VERSION 5.7 ;
BUSBITCHARS "[]" ;
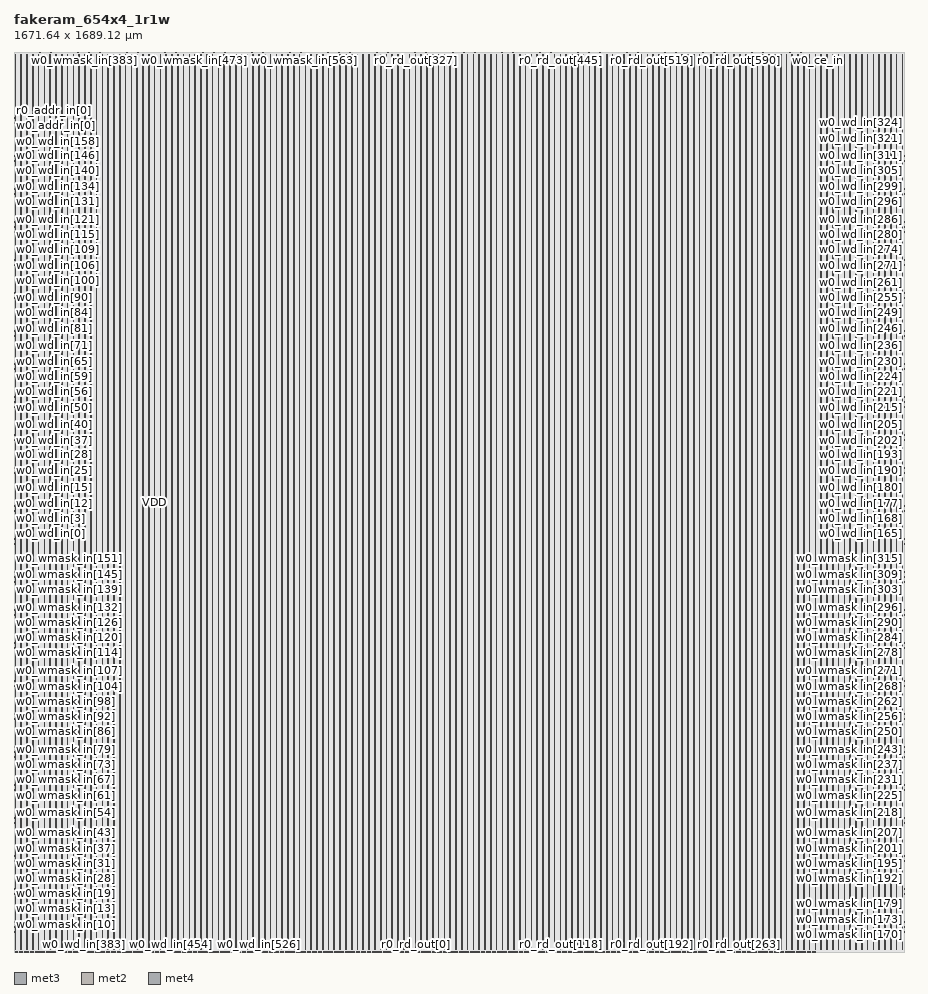
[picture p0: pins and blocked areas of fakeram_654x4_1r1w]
MACRO fakeram_654x4_1r1w
  FOREIGN fakeram_654x4_1r1w 0 0 ;
  SYMMETRY X Y R90 ;
  SIZE 1671.640 BY 1689.120 ;
  CLASS BLOCK ;
  PIN w0_wmask_in[0]
    DIRECTION INPUT ;
    USE SIGNAL ;
    SHAPE ABUTMENT ;
    PORT
      LAYER met3 ;
      RECT 0.000 3.930 0.900 4.230 ;
    END
  END w0_wmask_in[0]
  PIN w0_wmask_in[1]
    DIRECTION INPUT ;
    USE SIGNAL ;
    SHAPE ABUTMENT ;
    PORT
      LAYER met3 ;
      RECT 0.000 8.690 0.900 8.990 ;
    END
  END w0_wmask_in[1]
  PIN w0_wmask_in[2]
    DIRECTION INPUT ;
    USE SIGNAL ;
    SHAPE ABUTMENT ;
    PORT
      LAYER met3 ;
      RECT 0.000 13.450 0.900 13.750 ;
    END
  END w0_wmask_in[2]
  PIN w0_wmask_in[3]
    DIRECTION INPUT ;
    USE SIGNAL ;
    SHAPE ABUTMENT ;
    PORT
      LAYER met3 ;
      RECT 0.000 18.210 0.900 18.510 ;
    END
  END w0_wmask_in[3]
  PIN w0_wmask_in[4]
    DIRECTION INPUT ;
    USE SIGNAL ;
    SHAPE ABUTMENT ;
    PORT
      LAYER met3 ;
      RECT 0.000 22.970 0.900 23.270 ;
    END
  END w0_wmask_in[4]
  PIN w0_wmask_in[5]
    DIRECTION INPUT ;
    USE SIGNAL ;
    SHAPE ABUTMENT ;
    PORT
      LAYER met3 ;
      RECT 0.000 27.730 0.900 28.030 ;
    END
  END w0_wmask_in[5]
  PIN w0_wmask_in[6]
    DIRECTION INPUT ;
    USE SIGNAL ;
    SHAPE ABUTMENT ;
    PORT
      LAYER met3 ;
      RECT 0.000 32.490 0.900 32.790 ;
    END
  END w0_wmask_in[6]
  PIN w0_wmask_in[7]
    DIRECTION INPUT ;
    USE SIGNAL ;
    SHAPE ABUTMENT ;
    PORT
      LAYER met3 ;
      RECT 0.000 37.250 0.900 37.550 ;
    END
  END w0_wmask_in[7]
  PIN w0_wmask_in[8]
    DIRECTION INPUT ;
    USE SIGNAL ;
    SHAPE ABUTMENT ;
    PORT
      LAYER met3 ;
      RECT 0.000 42.010 0.900 42.310 ;
    END
  END w0_wmask_in[8]
  PIN w0_wmask_in[9]
    DIRECTION INPUT ;
    USE SIGNAL ;
    SHAPE ABUTMENT ;
    PORT
      LAYER met3 ;
      RECT 0.000 46.770 0.900 47.070 ;
    END
  END w0_wmask_in[9]
  PIN w0_wmask_in[10]
    DIRECTION INPUT ;
    USE SIGNAL ;
    SHAPE ABUTMENT ;
    PORT
      LAYER met3 ;
      RECT 0.000 51.530 0.900 51.830 ;
    END
  END w0_wmask_in[10]
  PIN w0_wmask_in[11]
    DIRECTION INPUT ;
    USE SIGNAL ;
    SHAPE ABUTMENT ;
    PORT
      LAYER met3 ;
      RECT 0.000 56.290 0.900 56.590 ;
    END
  END w0_wmask_in[11]
  PIN w0_wmask_in[12]
    DIRECTION INPUT ;
    USE SIGNAL ;
    SHAPE ABUTMENT ;
    PORT
      LAYER met3 ;
      RECT 0.000 61.050 0.900 61.350 ;
    END
  END w0_wmask_in[12]
  PIN w0_wmask_in[13]
    DIRECTION INPUT ;
    USE SIGNAL ;
    SHAPE ABUTMENT ;
    PORT
      LAYER met3 ;
      RECT 0.000 65.810 0.900 66.110 ;
    END
  END w0_wmask_in[13]
  PIN w0_wmask_in[14]
    DIRECTION INPUT ;
    USE SIGNAL ;
    SHAPE ABUTMENT ;
    PORT
      LAYER met3 ;
      RECT 0.000 70.570 0.900 70.870 ;
    END
  END w0_wmask_in[14]
  PIN w0_wmask_in[15]
    DIRECTION INPUT ;
    USE SIGNAL ;
    SHAPE ABUTMENT ;
    PORT
      LAYER met3 ;
      RECT 0.000 75.330 0.900 75.630 ;
    END
  END w0_wmask_in[15]
  PIN w0_wmask_in[16]
    DIRECTION INPUT ;
    USE SIGNAL ;
    SHAPE ABUTMENT ;
    PORT
      LAYER met3 ;
      RECT 0.000 80.090 0.900 80.390 ;
    END
  END w0_wmask_in[16]
  PIN w0_wmask_in[17]
    DIRECTION INPUT ;
    USE SIGNAL ;
    SHAPE ABUTMENT ;
    PORT
      LAYER met3 ;
      RECT 0.000 84.850 0.900 85.150 ;
    END
  END w0_wmask_in[17]
  PIN w0_wmask_in[18]
    DIRECTION INPUT ;
    USE SIGNAL ;
    SHAPE ABUTMENT ;
    PORT
      LAYER met3 ;
      RECT 0.000 89.610 0.900 89.910 ;
    END
  END w0_wmask_in[18]
  PIN w0_wmask_in[19]
    DIRECTION INPUT ;
    USE SIGNAL ;
    SHAPE ABUTMENT ;
    PORT
      LAYER met3 ;
      RECT 0.000 94.370 0.900 94.670 ;
    END
  END w0_wmask_in[19]
  PIN w0_wmask_in[20]
    DIRECTION INPUT ;
    USE SIGNAL ;
    SHAPE ABUTMENT ;
    PORT
      LAYER met3 ;
      RECT 0.000 99.130 0.900 99.430 ;
    END
  END w0_wmask_in[20]
  PIN w0_wmask_in[21]
    DIRECTION INPUT ;
    USE SIGNAL ;
    SHAPE ABUTMENT ;
    PORT
      LAYER met3 ;
      RECT 0.000 103.890 0.900 104.190 ;
    END
  END w0_wmask_in[21]
  PIN w0_wmask_in[22]
    DIRECTION INPUT ;
    USE SIGNAL ;
    SHAPE ABUTMENT ;
    PORT
      LAYER met3 ;
      RECT 0.000 108.650 0.900 108.950 ;
    END
  END w0_wmask_in[22]
  PIN w0_wmask_in[23]
    DIRECTION INPUT ;
    USE SIGNAL ;
    SHAPE ABUTMENT ;
    PORT
      LAYER met3 ;
      RECT 0.000 113.410 0.900 113.710 ;
    END
  END w0_wmask_in[23]
  PIN w0_wmask_in[24]
    DIRECTION INPUT ;
    USE SIGNAL ;
    SHAPE ABUTMENT ;
    PORT
      LAYER met3 ;
      RECT 0.000 118.170 0.900 118.470 ;
    END
  END w0_wmask_in[24]
  PIN w0_wmask_in[25]
    DIRECTION INPUT ;
    USE SIGNAL ;
    SHAPE ABUTMENT ;
    PORT
      LAYER met3 ;
      RECT 0.000 122.930 0.900 123.230 ;
    END
  END w0_wmask_in[25]
  PIN w0_wmask_in[26]
    DIRECTION INPUT ;
    USE SIGNAL ;
    SHAPE ABUTMENT ;
    PORT
      LAYER met3 ;
      RECT 0.000 127.690 0.900 127.990 ;
    END
  END w0_wmask_in[26]
  PIN w0_wmask_in[27]
    DIRECTION INPUT ;
    USE SIGNAL ;
    SHAPE ABUTMENT ;
    PORT
      LAYER met3 ;
      RECT 0.000 132.450 0.900 132.750 ;
    END
  END w0_wmask_in[27]
  PIN w0_wmask_in[28]
    DIRECTION INPUT ;
    USE SIGNAL ;
    SHAPE ABUTMENT ;
    PORT
      LAYER met3 ;
      RECT 0.000 137.210 0.900 137.510 ;
    END
  END w0_wmask_in[28]
  PIN w0_wmask_in[29]
    DIRECTION INPUT ;
    USE SIGNAL ;
    SHAPE ABUTMENT ;
    PORT
      LAYER met3 ;
      RECT 0.000 141.970 0.900 142.270 ;
    END
  END w0_wmask_in[29]
  PIN w0_wmask_in[30]
    DIRECTION INPUT ;
    USE SIGNAL ;
    SHAPE ABUTMENT ;
    PORT
      LAYER met3 ;
      RECT 0.000 146.730 0.900 147.030 ;
    END
  END w0_wmask_in[30]
  PIN w0_wmask_in[31]
    DIRECTION INPUT ;
    USE SIGNAL ;
    SHAPE ABUTMENT ;
    PORT
      LAYER met3 ;
      RECT 0.000 151.490 0.900 151.790 ;
    END
  END w0_wmask_in[31]
  PIN w0_wmask_in[32]
    DIRECTION INPUT ;
    USE SIGNAL ;
    SHAPE ABUTMENT ;
    PORT
      LAYER met3 ;
      RECT 0.000 156.250 0.900 156.550 ;
    END
  END w0_wmask_in[32]
  PIN w0_wmask_in[33]
    DIRECTION INPUT ;
    USE SIGNAL ;
    SHAPE ABUTMENT ;
    PORT
      LAYER met3 ;
      RECT 0.000 161.010 0.900 161.310 ;
    END
  END w0_wmask_in[33]
  PIN w0_wmask_in[34]
    DIRECTION INPUT ;
    USE SIGNAL ;
    SHAPE ABUTMENT ;
    PORT
      LAYER met3 ;
      RECT 0.000 165.770 0.900 166.070 ;
    END
  END w0_wmask_in[34]
  PIN w0_wmask_in[35]
    DIRECTION INPUT ;
    USE SIGNAL ;
    SHAPE ABUTMENT ;
    PORT
      LAYER met3 ;
      RECT 0.000 170.530 0.900 170.830 ;
    END
  END w0_wmask_in[35]
  PIN w0_wmask_in[36]
    DIRECTION INPUT ;
    USE SIGNAL ;
    SHAPE ABUTMENT ;
    PORT
      LAYER met3 ;
      RECT 0.000 175.290 0.900 175.590 ;
    END
  END w0_wmask_in[36]
  PIN w0_wmask_in[37]
    DIRECTION INPUT ;
    USE SIGNAL ;
    SHAPE ABUTMENT ;
    PORT
      LAYER met3 ;
      RECT 0.000 180.050 0.900 180.350 ;
    END
  END w0_wmask_in[37]
  PIN w0_wmask_in[38]
    DIRECTION INPUT ;
    USE SIGNAL ;
    SHAPE ABUTMENT ;
    PORT
      LAYER met3 ;
      RECT 0.000 184.810 0.900 185.110 ;
    END
  END w0_wmask_in[38]
  PIN w0_wmask_in[39]
    DIRECTION INPUT ;
    USE SIGNAL ;
    SHAPE ABUTMENT ;
    PORT
      LAYER met3 ;
      RECT 0.000 189.570 0.900 189.870 ;
    END
  END w0_wmask_in[39]
  PIN w0_wmask_in[40]
    DIRECTION INPUT ;
    USE SIGNAL ;
    SHAPE ABUTMENT ;
    PORT
      LAYER met3 ;
      RECT 0.000 194.330 0.900 194.630 ;
    END
  END w0_wmask_in[40]
  PIN w0_wmask_in[41]
    DIRECTION INPUT ;
    USE SIGNAL ;
    SHAPE ABUTMENT ;
    PORT
      LAYER met3 ;
      RECT 0.000 199.090 0.900 199.390 ;
    END
  END w0_wmask_in[41]
  PIN w0_wmask_in[42]
    DIRECTION INPUT ;
    USE SIGNAL ;
    SHAPE ABUTMENT ;
    PORT
      LAYER met3 ;
      RECT 0.000 203.850 0.900 204.150 ;
    END
  END w0_wmask_in[42]
  PIN w0_wmask_in[43]
    DIRECTION INPUT ;
    USE SIGNAL ;
    SHAPE ABUTMENT ;
    PORT
      LAYER met3 ;
      RECT 0.000 208.610 0.900 208.910 ;
    END
  END w0_wmask_in[43]
  PIN w0_wmask_in[44]
    DIRECTION INPUT ;
    USE SIGNAL ;
    SHAPE ABUTMENT ;
    PORT
      LAYER met3 ;
      RECT 0.000 213.370 0.900 213.670 ;
    END
  END w0_wmask_in[44]
  PIN w0_wmask_in[45]
    DIRECTION INPUT ;
    USE SIGNAL ;
    SHAPE ABUTMENT ;
    PORT
      LAYER met3 ;
      RECT 0.000 218.130 0.900 218.430 ;
    END
  END w0_wmask_in[45]
  PIN w0_wmask_in[46]
    DIRECTION INPUT ;
    USE SIGNAL ;
    SHAPE ABUTMENT ;
    PORT
      LAYER met3 ;
      RECT 0.000 222.890 0.900 223.190 ;
    END
  END w0_wmask_in[46]
  PIN w0_wmask_in[47]
    DIRECTION INPUT ;
    USE SIGNAL ;
    SHAPE ABUTMENT ;
    PORT
      LAYER met3 ;
      RECT 0.000 227.650 0.900 227.950 ;
    END
  END w0_wmask_in[47]
  PIN w0_wmask_in[48]
    DIRECTION INPUT ;
    USE SIGNAL ;
    SHAPE ABUTMENT ;
    PORT
      LAYER met3 ;
      RECT 0.000 232.410 0.900 232.710 ;
    END
  END w0_wmask_in[48]
  PIN w0_wmask_in[49]
    DIRECTION INPUT ;
    USE SIGNAL ;
    SHAPE ABUTMENT ;
    PORT
      LAYER met3 ;
      RECT 0.000 237.170 0.900 237.470 ;
    END
  END w0_wmask_in[49]
  PIN w0_wmask_in[50]
    DIRECTION INPUT ;
    USE SIGNAL ;
    SHAPE ABUTMENT ;
    PORT
      LAYER met3 ;
      RECT 0.000 241.930 0.900 242.230 ;
    END
  END w0_wmask_in[50]
  PIN w0_wmask_in[51]
    DIRECTION INPUT ;
    USE SIGNAL ;
    SHAPE ABUTMENT ;
    PORT
      LAYER met3 ;
      RECT 0.000 246.690 0.900 246.990 ;
    END
  END w0_wmask_in[51]
  PIN w0_wmask_in[52]
    DIRECTION INPUT ;
    USE SIGNAL ;
    SHAPE ABUTMENT ;
    PORT
      LAYER met3 ;
      RECT 0.000 251.450 0.900 251.750 ;
    END
  END w0_wmask_in[52]
  PIN w0_wmask_in[53]
    DIRECTION INPUT ;
    USE SIGNAL ;
    SHAPE ABUTMENT ;
    PORT
      LAYER met3 ;
      RECT 0.000 256.210 0.900 256.510 ;
    END
  END w0_wmask_in[53]
  PIN w0_wmask_in[54]
    DIRECTION INPUT ;
    USE SIGNAL ;
    SHAPE ABUTMENT ;
    PORT
      LAYER met3 ;
      RECT 0.000 260.970 0.900 261.270 ;
    END
  END w0_wmask_in[54]
  PIN w0_wmask_in[55]
    DIRECTION INPUT ;
    USE SIGNAL ;
    SHAPE ABUTMENT ;
    PORT
      LAYER met3 ;
      RECT 0.000 265.730 0.900 266.030 ;
    END
  END w0_wmask_in[55]
  PIN w0_wmask_in[56]
    DIRECTION INPUT ;
    USE SIGNAL ;
    SHAPE ABUTMENT ;
    PORT
      LAYER met3 ;
      RECT 0.000 270.490 0.900 270.790 ;
    END
  END w0_wmask_in[56]
  PIN w0_wmask_in[57]
    DIRECTION INPUT ;
    USE SIGNAL ;
    SHAPE ABUTMENT ;
    PORT
      LAYER met3 ;
      RECT 0.000 275.250 0.900 275.550 ;
    END
  END w0_wmask_in[57]
  PIN w0_wmask_in[58]
    DIRECTION INPUT ;
    USE SIGNAL ;
    SHAPE ABUTMENT ;
    PORT
      LAYER met3 ;
      RECT 0.000 280.010 0.900 280.310 ;
    END
  END w0_wmask_in[58]
  PIN w0_wmask_in[59]
    DIRECTION INPUT ;
    USE SIGNAL ;
    SHAPE ABUTMENT ;
    PORT
      LAYER met3 ;
      RECT 0.000 284.770 0.900 285.070 ;
    END
  END w0_wmask_in[59]
  PIN w0_wmask_in[60]
    DIRECTION INPUT ;
    USE SIGNAL ;
    SHAPE ABUTMENT ;
    PORT
      LAYER met3 ;
      RECT 0.000 289.530 0.900 289.830 ;
    END
  END w0_wmask_in[60]
  PIN w0_wmask_in[61]
    DIRECTION INPUT ;
    USE SIGNAL ;
    SHAPE ABUTMENT ;
    PORT
      LAYER met3 ;
      RECT 0.000 294.290 0.900 294.590 ;
    END
  END w0_wmask_in[61]
  PIN w0_wmask_in[62]
    DIRECTION INPUT ;
    USE SIGNAL ;
    SHAPE ABUTMENT ;
    PORT
      LAYER met3 ;
      RECT 0.000 299.050 0.900 299.350 ;
    END
  END w0_wmask_in[62]
  PIN w0_wmask_in[63]
    DIRECTION INPUT ;
    USE SIGNAL ;
    SHAPE ABUTMENT ;
    PORT
      LAYER met3 ;
      RECT 0.000 303.810 0.900 304.110 ;
    END
  END w0_wmask_in[63]
  PIN w0_wmask_in[64]
    DIRECTION INPUT ;
    USE SIGNAL ;
    SHAPE ABUTMENT ;
    PORT
      LAYER met3 ;
      RECT 0.000 308.570 0.900 308.870 ;
    END
  END w0_wmask_in[64]
  PIN w0_wmask_in[65]
    DIRECTION INPUT ;
    USE SIGNAL ;
    SHAPE ABUTMENT ;
    PORT
      LAYER met3 ;
      RECT 0.000 313.330 0.900 313.630 ;
    END
  END w0_wmask_in[65]
  PIN w0_wmask_in[66]
    DIRECTION INPUT ;
    USE SIGNAL ;
    SHAPE ABUTMENT ;
    PORT
      LAYER met3 ;
      RECT 0.000 318.090 0.900 318.390 ;
    END
  END w0_wmask_in[66]
  PIN w0_wmask_in[67]
    DIRECTION INPUT ;
    USE SIGNAL ;
    SHAPE ABUTMENT ;
    PORT
      LAYER met3 ;
      RECT 0.000 322.850 0.900 323.150 ;
    END
  END w0_wmask_in[67]
  PIN w0_wmask_in[68]
    DIRECTION INPUT ;
    USE SIGNAL ;
    SHAPE ABUTMENT ;
    PORT
      LAYER met3 ;
      RECT 0.000 327.610 0.900 327.910 ;
    END
  END w0_wmask_in[68]
  PIN w0_wmask_in[69]
    DIRECTION INPUT ;
    USE SIGNAL ;
    SHAPE ABUTMENT ;
    PORT
      LAYER met3 ;
      RECT 0.000 332.370 0.900 332.670 ;
    END
  END w0_wmask_in[69]
  PIN w0_wmask_in[70]
    DIRECTION INPUT ;
    USE SIGNAL ;
    SHAPE ABUTMENT ;
    PORT
      LAYER met3 ;
      RECT 0.000 337.130 0.900 337.430 ;
    END
  END w0_wmask_in[70]
  PIN w0_wmask_in[71]
    DIRECTION INPUT ;
    USE SIGNAL ;
    SHAPE ABUTMENT ;
    PORT
      LAYER met3 ;
      RECT 0.000 341.890 0.900 342.190 ;
    END
  END w0_wmask_in[71]
  PIN w0_wmask_in[72]
    DIRECTION INPUT ;
    USE SIGNAL ;
    SHAPE ABUTMENT ;
    PORT
      LAYER met3 ;
      RECT 0.000 346.650 0.900 346.950 ;
    END
  END w0_wmask_in[72]
  PIN w0_wmask_in[73]
    DIRECTION INPUT ;
    USE SIGNAL ;
    SHAPE ABUTMENT ;
    PORT
      LAYER met3 ;
      RECT 0.000 351.410 0.900 351.710 ;
    END
  END w0_wmask_in[73]
  PIN w0_wmask_in[74]
    DIRECTION INPUT ;
    USE SIGNAL ;
    SHAPE ABUTMENT ;
    PORT
      LAYER met3 ;
      RECT 0.000 356.170 0.900 356.470 ;
    END
  END w0_wmask_in[74]
  PIN w0_wmask_in[75]
    DIRECTION INPUT ;
    USE SIGNAL ;
    SHAPE ABUTMENT ;
    PORT
      LAYER met3 ;
      RECT 0.000 360.930 0.900 361.230 ;
    END
  END w0_wmask_in[75]
  PIN w0_wmask_in[76]
    DIRECTION INPUT ;
    USE SIGNAL ;
    SHAPE ABUTMENT ;
    PORT
      LAYER met3 ;
      RECT 0.000 365.690 0.900 365.990 ;
    END
  END w0_wmask_in[76]
  PIN w0_wmask_in[77]
    DIRECTION INPUT ;
    USE SIGNAL ;
    SHAPE ABUTMENT ;
    PORT
      LAYER met3 ;
      RECT 0.000 370.450 0.900 370.750 ;
    END
  END w0_wmask_in[77]
  PIN w0_wmask_in[78]
    DIRECTION INPUT ;
    USE SIGNAL ;
    SHAPE ABUTMENT ;
    PORT
      LAYER met3 ;
      RECT 0.000 375.210 0.900 375.510 ;
    END
  END w0_wmask_in[78]
  PIN w0_wmask_in[79]
    DIRECTION INPUT ;
    USE SIGNAL ;
    SHAPE ABUTMENT ;
    PORT
      LAYER met3 ;
      RECT 0.000 379.970 0.900 380.270 ;
    END
  END w0_wmask_in[79]
  PIN w0_wmask_in[80]
    DIRECTION INPUT ;
    USE SIGNAL ;
    SHAPE ABUTMENT ;
    PORT
      LAYER met3 ;
      RECT 0.000 384.730 0.900 385.030 ;
    END
  END w0_wmask_in[80]
  PIN w0_wmask_in[81]
    DIRECTION INPUT ;
    USE SIGNAL ;
    SHAPE ABUTMENT ;
    PORT
      LAYER met3 ;
      RECT 0.000 389.490 0.900 389.790 ;
    END
  END w0_wmask_in[81]
  PIN w0_wmask_in[82]
    DIRECTION INPUT ;
    USE SIGNAL ;
    SHAPE ABUTMENT ;
    PORT
      LAYER met3 ;
      RECT 0.000 394.250 0.900 394.550 ;
    END
  END w0_wmask_in[82]
  PIN w0_wmask_in[83]
    DIRECTION INPUT ;
    USE SIGNAL ;
    SHAPE ABUTMENT ;
    PORT
      LAYER met3 ;
      RECT 0.000 399.010 0.900 399.310 ;
    END
  END w0_wmask_in[83]
  PIN w0_wmask_in[84]
    DIRECTION INPUT ;
    USE SIGNAL ;
    SHAPE ABUTMENT ;
    PORT
      LAYER met3 ;
      RECT 0.000 403.770 0.900 404.070 ;
    END
  END w0_wmask_in[84]
  PIN w0_wmask_in[85]
    DIRECTION INPUT ;
    USE SIGNAL ;
    SHAPE ABUTMENT ;
    PORT
      LAYER met3 ;
      RECT 0.000 408.530 0.900 408.830 ;
    END
  END w0_wmask_in[85]
  PIN w0_wmask_in[86]
    DIRECTION INPUT ;
    USE SIGNAL ;
    SHAPE ABUTMENT ;
    PORT
      LAYER met3 ;
      RECT 0.000 413.290 0.900 413.590 ;
    END
  END w0_wmask_in[86]
  PIN w0_wmask_in[87]
    DIRECTION INPUT ;
    USE SIGNAL ;
    SHAPE ABUTMENT ;
    PORT
      LAYER met3 ;
      RECT 0.000 418.050 0.900 418.350 ;
    END
  END w0_wmask_in[87]
  PIN w0_wmask_in[88]
    DIRECTION INPUT ;
    USE SIGNAL ;
    SHAPE ABUTMENT ;
    PORT
      LAYER met3 ;
      RECT 0.000 422.810 0.900 423.110 ;
    END
  END w0_wmask_in[88]
  PIN w0_wmask_in[89]
    DIRECTION INPUT ;
    USE SIGNAL ;
    SHAPE ABUTMENT ;
    PORT
      LAYER met3 ;
      RECT 0.000 427.570 0.900 427.870 ;
    END
  END w0_wmask_in[89]
  PIN w0_wmask_in[90]
    DIRECTION INPUT ;
    USE SIGNAL ;
    SHAPE ABUTMENT ;
    PORT
      LAYER met3 ;
      RECT 0.000 432.330 0.900 432.630 ;
    END
  END w0_wmask_in[90]
  PIN w0_wmask_in[91]
    DIRECTION INPUT ;
    USE SIGNAL ;
    SHAPE ABUTMENT ;
    PORT
      LAYER met3 ;
      RECT 0.000 437.090 0.900 437.390 ;
    END
  END w0_wmask_in[91]
  PIN w0_wmask_in[92]
    DIRECTION INPUT ;
    USE SIGNAL ;
    SHAPE ABUTMENT ;
    PORT
      LAYER met3 ;
      RECT 0.000 441.850 0.900 442.150 ;
    END
  END w0_wmask_in[92]
  PIN w0_wmask_in[93]
    DIRECTION INPUT ;
    USE SIGNAL ;
    SHAPE ABUTMENT ;
    PORT
      LAYER met3 ;
      RECT 0.000 446.610 0.900 446.910 ;
    END
  END w0_wmask_in[93]
  PIN w0_wmask_in[94]
    DIRECTION INPUT ;
    USE SIGNAL ;
    SHAPE ABUTMENT ;
    PORT
      LAYER met3 ;
      RECT 0.000 451.370 0.900 451.670 ;
    END
  END w0_wmask_in[94]
  PIN w0_wmask_in[95]
    DIRECTION INPUT ;
    USE SIGNAL ;
    SHAPE ABUTMENT ;
    PORT
      LAYER met3 ;
      RECT 0.000 456.130 0.900 456.430 ;
    END
  END w0_wmask_in[95]
  PIN w0_wmask_in[96]
    DIRECTION INPUT ;
    USE SIGNAL ;
    SHAPE ABUTMENT ;
    PORT
      LAYER met3 ;
      RECT 0.000 460.890 0.900 461.190 ;
    END
  END w0_wmask_in[96]
  PIN w0_wmask_in[97]
    DIRECTION INPUT ;
    USE SIGNAL ;
    SHAPE ABUTMENT ;
    PORT
      LAYER met3 ;
      RECT 0.000 465.650 0.900 465.950 ;
    END
  END w0_wmask_in[97]
  PIN w0_wmask_in[98]
    DIRECTION INPUT ;
    USE SIGNAL ;
    SHAPE ABUTMENT ;
    PORT
      LAYER met3 ;
      RECT 0.000 470.410 0.900 470.710 ;
    END
  END w0_wmask_in[98]
  PIN w0_wmask_in[99]
    DIRECTION INPUT ;
    USE SIGNAL ;
    SHAPE ABUTMENT ;
    PORT
      LAYER met3 ;
      RECT 0.000 475.170 0.900 475.470 ;
    END
  END w0_wmask_in[99]
  PIN w0_wmask_in[100]
    DIRECTION INPUT ;
    USE SIGNAL ;
    SHAPE ABUTMENT ;
    PORT
      LAYER met3 ;
      RECT 0.000 479.930 0.900 480.230 ;
    END
  END w0_wmask_in[100]
  PIN w0_wmask_in[101]
    DIRECTION INPUT ;
    USE SIGNAL ;
    SHAPE ABUTMENT ;
    PORT
      LAYER met3 ;
      RECT 0.000 484.690 0.900 484.990 ;
    END
  END w0_wmask_in[101]
  PIN w0_wmask_in[102]
    DIRECTION INPUT ;
    USE SIGNAL ;
    SHAPE ABUTMENT ;
    PORT
      LAYER met3 ;
      RECT 0.000 489.450 0.900 489.750 ;
    END
  END w0_wmask_in[102]
  PIN w0_wmask_in[103]
    DIRECTION INPUT ;
    USE SIGNAL ;
    SHAPE ABUTMENT ;
    PORT
      LAYER met3 ;
      RECT 0.000 494.210 0.900 494.510 ;
    END
  END w0_wmask_in[103]
  PIN w0_wmask_in[104]
    DIRECTION INPUT ;
    USE SIGNAL ;
    SHAPE ABUTMENT ;
    PORT
      LAYER met3 ;
      RECT 0.000 498.970 0.900 499.270 ;
    END
  END w0_wmask_in[104]
  PIN w0_wmask_in[105]
    DIRECTION INPUT ;
    USE SIGNAL ;
    SHAPE ABUTMENT ;
    PORT
      LAYER met3 ;
      RECT 0.000 503.730 0.900 504.030 ;
    END
  END w0_wmask_in[105]
  PIN w0_wmask_in[106]
    DIRECTION INPUT ;
    USE SIGNAL ;
    SHAPE ABUTMENT ;
    PORT
      LAYER met3 ;
      RECT 0.000 508.490 0.900 508.790 ;
    END
  END w0_wmask_in[106]
  PIN w0_wmask_in[107]
    DIRECTION INPUT ;
    USE SIGNAL ;
    SHAPE ABUTMENT ;
    PORT
      LAYER met3 ;
      RECT 0.000 513.250 0.900 513.550 ;
    END
  END w0_wmask_in[107]
  PIN w0_wmask_in[108]
    DIRECTION INPUT ;
    USE SIGNAL ;
    SHAPE ABUTMENT ;
    PORT
      LAYER met3 ;
      RECT 0.000 518.010 0.900 518.310 ;
    END
  END w0_wmask_in[108]
  PIN w0_wmask_in[109]
    DIRECTION INPUT ;
    USE SIGNAL ;
    SHAPE ABUTMENT ;
    PORT
      LAYER met3 ;
      RECT 0.000 522.770 0.900 523.070 ;
    END
  END w0_wmask_in[109]
  PIN w0_wmask_in[110]
    DIRECTION INPUT ;
    USE SIGNAL ;
    SHAPE ABUTMENT ;
    PORT
      LAYER met3 ;
      RECT 0.000 527.530 0.900 527.830 ;
    END
  END w0_wmask_in[110]
  PIN w0_wmask_in[111]
    DIRECTION INPUT ;
    USE SIGNAL ;
    SHAPE ABUTMENT ;
    PORT
      LAYER met3 ;
      RECT 0.000 532.290 0.900 532.590 ;
    END
  END w0_wmask_in[111]
  PIN w0_wmask_in[112]
    DIRECTION INPUT ;
    USE SIGNAL ;
    SHAPE ABUTMENT ;
    PORT
      LAYER met3 ;
      RECT 0.000 537.050 0.900 537.350 ;
    END
  END w0_wmask_in[112]
  PIN w0_wmask_in[113]
    DIRECTION INPUT ;
    USE SIGNAL ;
    SHAPE ABUTMENT ;
    PORT
      LAYER met3 ;
      RECT 0.000 541.810 0.900 542.110 ;
    END
  END w0_wmask_in[113]
  PIN w0_wmask_in[114]
    DIRECTION INPUT ;
    USE SIGNAL ;
    SHAPE ABUTMENT ;
    PORT
      LAYER met3 ;
      RECT 0.000 546.570 0.900 546.870 ;
    END
  END w0_wmask_in[114]
  PIN w0_wmask_in[115]
    DIRECTION INPUT ;
    USE SIGNAL ;
    SHAPE ABUTMENT ;
    PORT
      LAYER met3 ;
      RECT 0.000 551.330 0.900 551.630 ;
    END
  END w0_wmask_in[115]
  PIN w0_wmask_in[116]
    DIRECTION INPUT ;
    USE SIGNAL ;
    SHAPE ABUTMENT ;
    PORT
      LAYER met3 ;
      RECT 0.000 556.090 0.900 556.390 ;
    END
  END w0_wmask_in[116]
  PIN w0_wmask_in[117]
    DIRECTION INPUT ;
    USE SIGNAL ;
    SHAPE ABUTMENT ;
    PORT
      LAYER met3 ;
      RECT 0.000 560.850 0.900 561.150 ;
    END
  END w0_wmask_in[117]
  PIN w0_wmask_in[118]
    DIRECTION INPUT ;
    USE SIGNAL ;
    SHAPE ABUTMENT ;
    PORT
      LAYER met3 ;
      RECT 0.000 565.610 0.900 565.910 ;
    END
  END w0_wmask_in[118]
  PIN w0_wmask_in[119]
    DIRECTION INPUT ;
    USE SIGNAL ;
    SHAPE ABUTMENT ;
    PORT
      LAYER met3 ;
      RECT 0.000 570.370 0.900 570.670 ;
    END
  END w0_wmask_in[119]
  PIN w0_wmask_in[120]
    DIRECTION INPUT ;
    USE SIGNAL ;
    SHAPE ABUTMENT ;
    PORT
      LAYER met3 ;
      RECT 0.000 575.130 0.900 575.430 ;
    END
  END w0_wmask_in[120]
  PIN w0_wmask_in[121]
    DIRECTION INPUT ;
    USE SIGNAL ;
    SHAPE ABUTMENT ;
    PORT
      LAYER met3 ;
      RECT 0.000 579.890 0.900 580.190 ;
    END
  END w0_wmask_in[121]
  PIN w0_wmask_in[122]
    DIRECTION INPUT ;
    USE SIGNAL ;
    SHAPE ABUTMENT ;
    PORT
      LAYER met3 ;
      RECT 0.000 584.650 0.900 584.950 ;
    END
  END w0_wmask_in[122]
  PIN w0_wmask_in[123]
    DIRECTION INPUT ;
    USE SIGNAL ;
    SHAPE ABUTMENT ;
    PORT
      LAYER met3 ;
      RECT 0.000 589.410 0.900 589.710 ;
    END
  END w0_wmask_in[123]
  PIN w0_wmask_in[124]
    DIRECTION INPUT ;
    USE SIGNAL ;
    SHAPE ABUTMENT ;
    PORT
      LAYER met3 ;
      RECT 0.000 594.170 0.900 594.470 ;
    END
  END w0_wmask_in[124]
  PIN w0_wmask_in[125]
    DIRECTION INPUT ;
    USE SIGNAL ;
    SHAPE ABUTMENT ;
    PORT
      LAYER met3 ;
      RECT 0.000 598.930 0.900 599.230 ;
    END
  END w0_wmask_in[125]
  PIN w0_wmask_in[126]
    DIRECTION INPUT ;
    USE SIGNAL ;
    SHAPE ABUTMENT ;
    PORT
      LAYER met3 ;
      RECT 0.000 603.690 0.900 603.990 ;
    END
  END w0_wmask_in[126]
  PIN w0_wmask_in[127]
    DIRECTION INPUT ;
    USE SIGNAL ;
    SHAPE ABUTMENT ;
    PORT
      LAYER met3 ;
      RECT 0.000 608.450 0.900 608.750 ;
    END
  END w0_wmask_in[127]
  PIN w0_wmask_in[128]
    DIRECTION INPUT ;
    USE SIGNAL ;
    SHAPE ABUTMENT ;
    PORT
      LAYER met3 ;
      RECT 0.000 613.210 0.900 613.510 ;
    END
  END w0_wmask_in[128]
  PIN w0_wmask_in[129]
    DIRECTION INPUT ;
    USE SIGNAL ;
    SHAPE ABUTMENT ;
    PORT
      LAYER met3 ;
      RECT 0.000 617.970 0.900 618.270 ;
    END
  END w0_wmask_in[129]
  PIN w0_wmask_in[130]
    DIRECTION INPUT ;
    USE SIGNAL ;
    SHAPE ABUTMENT ;
    PORT
      LAYER met3 ;
      RECT 0.000 622.730 0.900 623.030 ;
    END
  END w0_wmask_in[130]
  PIN w0_wmask_in[131]
    DIRECTION INPUT ;
    USE SIGNAL ;
    SHAPE ABUTMENT ;
    PORT
      LAYER met3 ;
      RECT 0.000 627.490 0.900 627.790 ;
    END
  END w0_wmask_in[131]
  PIN w0_wmask_in[132]
    DIRECTION INPUT ;
    USE SIGNAL ;
    SHAPE ABUTMENT ;
    PORT
      LAYER met3 ;
      RECT 0.000 632.250 0.900 632.550 ;
    END
  END w0_wmask_in[132]
  PIN w0_wmask_in[133]
    DIRECTION INPUT ;
    USE SIGNAL ;
    SHAPE ABUTMENT ;
    PORT
      LAYER met3 ;
      RECT 0.000 637.010 0.900 637.310 ;
    END
  END w0_wmask_in[133]
  PIN w0_wmask_in[134]
    DIRECTION INPUT ;
    USE SIGNAL ;
    SHAPE ABUTMENT ;
    PORT
      LAYER met3 ;
      RECT 0.000 641.770 0.900 642.070 ;
    END
  END w0_wmask_in[134]
  PIN w0_wmask_in[135]
    DIRECTION INPUT ;
    USE SIGNAL ;
    SHAPE ABUTMENT ;
    PORT
      LAYER met3 ;
      RECT 0.000 646.530 0.900 646.830 ;
    END
  END w0_wmask_in[135]
  PIN w0_wmask_in[136]
    DIRECTION INPUT ;
    USE SIGNAL ;
    SHAPE ABUTMENT ;
    PORT
      LAYER met3 ;
      RECT 0.000 651.290 0.900 651.590 ;
    END
  END w0_wmask_in[136]
  PIN w0_wmask_in[137]
    DIRECTION INPUT ;
    USE SIGNAL ;
    SHAPE ABUTMENT ;
    PORT
      LAYER met3 ;
      RECT 0.000 656.050 0.900 656.350 ;
    END
  END w0_wmask_in[137]
  PIN w0_wmask_in[138]
    DIRECTION INPUT ;
    USE SIGNAL ;
    SHAPE ABUTMENT ;
    PORT
      LAYER met3 ;
      RECT 0.000 660.810 0.900 661.110 ;
    END
  END w0_wmask_in[138]
  PIN w0_wmask_in[139]
    DIRECTION INPUT ;
    USE SIGNAL ;
    SHAPE ABUTMENT ;
    PORT
      LAYER met3 ;
      RECT 0.000 665.570 0.900 665.870 ;
    END
  END w0_wmask_in[139]
  PIN w0_wmask_in[140]
    DIRECTION INPUT ;
    USE SIGNAL ;
    SHAPE ABUTMENT ;
    PORT
      LAYER met3 ;
      RECT 0.000 670.330 0.900 670.630 ;
    END
  END w0_wmask_in[140]
  PIN w0_wmask_in[141]
    DIRECTION INPUT ;
    USE SIGNAL ;
    SHAPE ABUTMENT ;
    PORT
      LAYER met3 ;
      RECT 0.000 675.090 0.900 675.390 ;
    END
  END w0_wmask_in[141]
  PIN w0_wmask_in[142]
    DIRECTION INPUT ;
    USE SIGNAL ;
    SHAPE ABUTMENT ;
    PORT
      LAYER met3 ;
      RECT 0.000 679.850 0.900 680.150 ;
    END
  END w0_wmask_in[142]
  PIN w0_wmask_in[143]
    DIRECTION INPUT ;
    USE SIGNAL ;
    SHAPE ABUTMENT ;
    PORT
      LAYER met3 ;
      RECT 0.000 684.610 0.900 684.910 ;
    END
  END w0_wmask_in[143]
  PIN w0_wmask_in[144]
    DIRECTION INPUT ;
    USE SIGNAL ;
    SHAPE ABUTMENT ;
    PORT
      LAYER met3 ;
      RECT 0.000 689.370 0.900 689.670 ;
    END
  END w0_wmask_in[144]
  PIN w0_wmask_in[145]
    DIRECTION INPUT ;
    USE SIGNAL ;
    SHAPE ABUTMENT ;
    PORT
      LAYER met3 ;
      RECT 0.000 694.130 0.900 694.430 ;
    END
  END w0_wmask_in[145]
  PIN w0_wmask_in[146]
    DIRECTION INPUT ;
    USE SIGNAL ;
    SHAPE ABUTMENT ;
    PORT
      LAYER met3 ;
      RECT 0.000 698.890 0.900 699.190 ;
    END
  END w0_wmask_in[146]
  PIN w0_wmask_in[147]
    DIRECTION INPUT ;
    USE SIGNAL ;
    SHAPE ABUTMENT ;
    PORT
      LAYER met3 ;
      RECT 0.000 703.650 0.900 703.950 ;
    END
  END w0_wmask_in[147]
  PIN w0_wmask_in[148]
    DIRECTION INPUT ;
    USE SIGNAL ;
    SHAPE ABUTMENT ;
    PORT
      LAYER met3 ;
      RECT 0.000 708.410 0.900 708.710 ;
    END
  END w0_wmask_in[148]
  PIN w0_wmask_in[149]
    DIRECTION INPUT ;
    USE SIGNAL ;
    SHAPE ABUTMENT ;
    PORT
      LAYER met3 ;
      RECT 0.000 713.170 0.900 713.470 ;
    END
  END w0_wmask_in[149]
  PIN w0_wmask_in[150]
    DIRECTION INPUT ;
    USE SIGNAL ;
    SHAPE ABUTMENT ;
    PORT
      LAYER met3 ;
      RECT 0.000 717.930 0.900 718.230 ;
    END
  END w0_wmask_in[150]
  PIN w0_wmask_in[151]
    DIRECTION INPUT ;
    USE SIGNAL ;
    SHAPE ABUTMENT ;
    PORT
      LAYER met3 ;
      RECT 0.000 722.690 0.900 722.990 ;
    END
  END w0_wmask_in[151]
  PIN w0_wmask_in[152]
    DIRECTION INPUT ;
    USE SIGNAL ;
    SHAPE ABUTMENT ;
    PORT
      LAYER met3 ;
      RECT 0.000 727.450 0.900 727.750 ;
    END
  END w0_wmask_in[152]
  PIN w0_wmask_in[153]
    DIRECTION INPUT ;
    USE SIGNAL ;
    SHAPE ABUTMENT ;
    PORT
      LAYER met3 ;
      RECT 0.000 732.210 0.900 732.510 ;
    END
  END w0_wmask_in[153]
  PIN w0_wmask_in[154]
    DIRECTION INPUT ;
    USE SIGNAL ;
    SHAPE ABUTMENT ;
    PORT
      LAYER met3 ;
      RECT 0.000 736.970 0.900 737.270 ;
    END
  END w0_wmask_in[154]
  PIN w0_wmask_in[155]
    DIRECTION INPUT ;
    USE SIGNAL ;
    SHAPE ABUTMENT ;
    PORT
      LAYER met3 ;
      RECT 0.000 741.730 0.900 742.030 ;
    END
  END w0_wmask_in[155]
  PIN w0_wmask_in[156]
    DIRECTION INPUT ;
    USE SIGNAL ;
    SHAPE ABUTMENT ;
    PORT
      LAYER met3 ;
      RECT 0.000 746.490 0.900 746.790 ;
    END
  END w0_wmask_in[156]
  PIN w0_wmask_in[157]
    DIRECTION INPUT ;
    USE SIGNAL ;
    SHAPE ABUTMENT ;
    PORT
      LAYER met3 ;
      RECT 0.000 751.250 0.900 751.550 ;
    END
  END w0_wmask_in[157]
  PIN w0_wmask_in[158]
    DIRECTION INPUT ;
    USE SIGNAL ;
    SHAPE ABUTMENT ;
    PORT
      LAYER met3 ;
      RECT 0.000 756.010 0.900 756.310 ;
    END
  END w0_wmask_in[158]
  PIN w0_wmask_in[159]
    DIRECTION INPUT ;
    USE SIGNAL ;
    SHAPE ABUTMENT ;
    PORT
      LAYER met3 ;
      RECT 0.000 760.770 0.900 761.070 ;
    END
  END w0_wmask_in[159]
  PIN w0_wmask_in[160]
    DIRECTION INPUT ;
    USE SIGNAL ;
    SHAPE ABUTMENT ;
    PORT
      LAYER met3 ;
      RECT 0.000 765.530 0.900 765.830 ;
    END
  END w0_wmask_in[160]
  PIN w0_wmask_in[161]
    DIRECTION INPUT ;
    USE SIGNAL ;
    SHAPE ABUTMENT ;
    PORT
      LAYER met3 ;
      RECT 0.000 770.290 0.900 770.590 ;
    END
  END w0_wmask_in[161]
  PIN w0_wmask_in[162]
    DIRECTION INPUT ;
    USE SIGNAL ;
    SHAPE ABUTMENT ;
    PORT
      LAYER met3 ;
      RECT 0.000 775.050 0.900 775.350 ;
    END
  END w0_wmask_in[162]
  PIN w0_wmask_in[163]
    DIRECTION INPUT ;
    USE SIGNAL ;
    SHAPE ABUTMENT ;
    PORT
      LAYER met3 ;
      RECT 0.000 779.810 0.900 780.110 ;
    END
  END w0_wmask_in[163]
  PIN w0_wmask_in[164]
    DIRECTION INPUT ;
    USE SIGNAL ;
    SHAPE ABUTMENT ;
    PORT
      LAYER met3 ;
      RECT 1670.740 3.930 1671.640 4.230 ;
    END
  END w0_wmask_in[164]
  PIN w0_wmask_in[165]
    DIRECTION INPUT ;
    USE SIGNAL ;
    SHAPE ABUTMENT ;
    PORT
      LAYER met3 ;
      RECT 1670.740 8.690 1671.640 8.990 ;
    END
  END w0_wmask_in[165]
  PIN w0_wmask_in[166]
    DIRECTION INPUT ;
    USE SIGNAL ;
    SHAPE ABUTMENT ;
    PORT
      LAYER met3 ;
      RECT 1670.740 13.450 1671.640 13.750 ;
    END
  END w0_wmask_in[166]
  PIN w0_wmask_in[167]
    DIRECTION INPUT ;
    USE SIGNAL ;
    SHAPE ABUTMENT ;
    PORT
      LAYER met3 ;
      RECT 1670.740 18.210 1671.640 18.510 ;
    END
  END w0_wmask_in[167]
  PIN w0_wmask_in[168]
    DIRECTION INPUT ;
    USE SIGNAL ;
    SHAPE ABUTMENT ;
    PORT
      LAYER met3 ;
      RECT 1670.740 22.970 1671.640 23.270 ;
    END
  END w0_wmask_in[168]
  PIN w0_wmask_in[169]
    DIRECTION INPUT ;
    USE SIGNAL ;
    SHAPE ABUTMENT ;
    PORT
      LAYER met3 ;
      RECT 1670.740 27.730 1671.640 28.030 ;
    END
  END w0_wmask_in[169]
  PIN w0_wmask_in[170]
    DIRECTION INPUT ;
    USE SIGNAL ;
    SHAPE ABUTMENT ;
    PORT
      LAYER met3 ;
      RECT 1670.740 32.490 1671.640 32.790 ;
    END
  END w0_wmask_in[170]
  PIN w0_wmask_in[171]
    DIRECTION INPUT ;
    USE SIGNAL ;
    SHAPE ABUTMENT ;
    PORT
      LAYER met3 ;
      RECT 1670.740 37.250 1671.640 37.550 ;
    END
  END w0_wmask_in[171]
  PIN w0_wmask_in[172]
    DIRECTION INPUT ;
    USE SIGNAL ;
    SHAPE ABUTMENT ;
    PORT
      LAYER met3 ;
      RECT 1670.740 42.010 1671.640 42.310 ;
    END
  END w0_wmask_in[172]
  PIN w0_wmask_in[173]
    DIRECTION INPUT ;
    USE SIGNAL ;
    SHAPE ABUTMENT ;
    PORT
      LAYER met3 ;
      RECT 1670.740 46.770 1671.640 47.070 ;
    END
  END w0_wmask_in[173]
  PIN w0_wmask_in[174]
    DIRECTION INPUT ;
    USE SIGNAL ;
    SHAPE ABUTMENT ;
    PORT
      LAYER met3 ;
      RECT 1670.740 51.530 1671.640 51.830 ;
    END
  END w0_wmask_in[174]
  PIN w0_wmask_in[175]
    DIRECTION INPUT ;
    USE SIGNAL ;
    SHAPE ABUTMENT ;
    PORT
      LAYER met3 ;
      RECT 1670.740 56.290 1671.640 56.590 ;
    END
  END w0_wmask_in[175]
  PIN w0_wmask_in[176]
    DIRECTION INPUT ;
    USE SIGNAL ;
    SHAPE ABUTMENT ;
    PORT
      LAYER met3 ;
      RECT 1670.740 61.050 1671.640 61.350 ;
    END
  END w0_wmask_in[176]
  PIN w0_wmask_in[177]
    DIRECTION INPUT ;
    USE SIGNAL ;
    SHAPE ABUTMENT ;
    PORT
      LAYER met3 ;
      RECT 1670.740 65.810 1671.640 66.110 ;
    END
  END w0_wmask_in[177]
  PIN w0_wmask_in[178]
    DIRECTION INPUT ;
    USE SIGNAL ;
    SHAPE ABUTMENT ;
    PORT
      LAYER met3 ;
      RECT 1670.740 70.570 1671.640 70.870 ;
    END
  END w0_wmask_in[178]
  PIN w0_wmask_in[179]
    DIRECTION INPUT ;
    USE SIGNAL ;
    SHAPE ABUTMENT ;
    PORT
      LAYER met3 ;
      RECT 1670.740 75.330 1671.640 75.630 ;
    END
  END w0_wmask_in[179]
  PIN w0_wmask_in[180]
    DIRECTION INPUT ;
    USE SIGNAL ;
    SHAPE ABUTMENT ;
    PORT
      LAYER met3 ;
      RECT 1670.740 80.090 1671.640 80.390 ;
    END
  END w0_wmask_in[180]
  PIN w0_wmask_in[181]
    DIRECTION INPUT ;
    USE SIGNAL ;
    SHAPE ABUTMENT ;
    PORT
      LAYER met3 ;
      RECT 1670.740 84.850 1671.640 85.150 ;
    END
  END w0_wmask_in[181]
  PIN w0_wmask_in[182]
    DIRECTION INPUT ;
    USE SIGNAL ;
    SHAPE ABUTMENT ;
    PORT
      LAYER met3 ;
      RECT 1670.740 89.610 1671.640 89.910 ;
    END
  END w0_wmask_in[182]
  PIN w0_wmask_in[183]
    DIRECTION INPUT ;
    USE SIGNAL ;
    SHAPE ABUTMENT ;
    PORT
      LAYER met3 ;
      RECT 1670.740 94.370 1671.640 94.670 ;
    END
  END w0_wmask_in[183]
  PIN w0_wmask_in[184]
    DIRECTION INPUT ;
    USE SIGNAL ;
    SHAPE ABUTMENT ;
    PORT
      LAYER met3 ;
      RECT 1670.740 99.130 1671.640 99.430 ;
    END
  END w0_wmask_in[184]
  PIN w0_wmask_in[185]
    DIRECTION INPUT ;
    USE SIGNAL ;
    SHAPE ABUTMENT ;
    PORT
      LAYER met3 ;
      RECT 1670.740 103.890 1671.640 104.190 ;
    END
  END w0_wmask_in[185]
  PIN w0_wmask_in[186]
    DIRECTION INPUT ;
    USE SIGNAL ;
    SHAPE ABUTMENT ;
    PORT
      LAYER met3 ;
      RECT 1670.740 108.650 1671.640 108.950 ;
    END
  END w0_wmask_in[186]
  PIN w0_wmask_in[187]
    DIRECTION INPUT ;
    USE SIGNAL ;
    SHAPE ABUTMENT ;
    PORT
      LAYER met3 ;
      RECT 1670.740 113.410 1671.640 113.710 ;
    END
  END w0_wmask_in[187]
  PIN w0_wmask_in[188]
    DIRECTION INPUT ;
    USE SIGNAL ;
    SHAPE ABUTMENT ;
    PORT
      LAYER met3 ;
      RECT 1670.740 118.170 1671.640 118.470 ;
    END
  END w0_wmask_in[188]
  PIN w0_wmask_in[189]
    DIRECTION INPUT ;
    USE SIGNAL ;
    SHAPE ABUTMENT ;
    PORT
      LAYER met3 ;
      RECT 1670.740 122.930 1671.640 123.230 ;
    END
  END w0_wmask_in[189]
  PIN w0_wmask_in[190]
    DIRECTION INPUT ;
    USE SIGNAL ;
    SHAPE ABUTMENT ;
    PORT
      LAYER met3 ;
      RECT 1670.740 127.690 1671.640 127.990 ;
    END
  END w0_wmask_in[190]
  PIN w0_wmask_in[191]
    DIRECTION INPUT ;
    USE SIGNAL ;
    SHAPE ABUTMENT ;
    PORT
      LAYER met3 ;
      RECT 1670.740 132.450 1671.640 132.750 ;
    END
  END w0_wmask_in[191]
  PIN w0_wmask_in[192]
    DIRECTION INPUT ;
    USE SIGNAL ;
    SHAPE ABUTMENT ;
    PORT
      LAYER met3 ;
      RECT 1670.740 137.210 1671.640 137.510 ;
    END
  END w0_wmask_in[192]
  PIN w0_wmask_in[193]
    DIRECTION INPUT ;
    USE SIGNAL ;
    SHAPE ABUTMENT ;
    PORT
      LAYER met3 ;
      RECT 1670.740 141.970 1671.640 142.270 ;
    END
  END w0_wmask_in[193]
  PIN w0_wmask_in[194]
    DIRECTION INPUT ;
    USE SIGNAL ;
    SHAPE ABUTMENT ;
    PORT
      LAYER met3 ;
      RECT 1670.740 146.730 1671.640 147.030 ;
    END
  END w0_wmask_in[194]
  PIN w0_wmask_in[195]
    DIRECTION INPUT ;
    USE SIGNAL ;
    SHAPE ABUTMENT ;
    PORT
      LAYER met3 ;
      RECT 1670.740 151.490 1671.640 151.790 ;
    END
  END w0_wmask_in[195]
  PIN w0_wmask_in[196]
    DIRECTION INPUT ;
    USE SIGNAL ;
    SHAPE ABUTMENT ;
    PORT
      LAYER met3 ;
      RECT 1670.740 156.250 1671.640 156.550 ;
    END
  END w0_wmask_in[196]
  PIN w0_wmask_in[197]
    DIRECTION INPUT ;
    USE SIGNAL ;
    SHAPE ABUTMENT ;
    PORT
      LAYER met3 ;
      RECT 1670.740 161.010 1671.640 161.310 ;
    END
  END w0_wmask_in[197]
  PIN w0_wmask_in[198]
    DIRECTION INPUT ;
    USE SIGNAL ;
    SHAPE ABUTMENT ;
    PORT
      LAYER met3 ;
      RECT 1670.740 165.770 1671.640 166.070 ;
    END
  END w0_wmask_in[198]
  PIN w0_wmask_in[199]
    DIRECTION INPUT ;
    USE SIGNAL ;
    SHAPE ABUTMENT ;
    PORT
      LAYER met3 ;
      RECT 1670.740 170.530 1671.640 170.830 ;
    END
  END w0_wmask_in[199]
  PIN w0_wmask_in[200]
    DIRECTION INPUT ;
    USE SIGNAL ;
    SHAPE ABUTMENT ;
    PORT
      LAYER met3 ;
      RECT 1670.740 175.290 1671.640 175.590 ;
    END
  END w0_wmask_in[200]
  PIN w0_wmask_in[201]
    DIRECTION INPUT ;
    USE SIGNAL ;
    SHAPE ABUTMENT ;
    PORT
      LAYER met3 ;
      RECT 1670.740 180.050 1671.640 180.350 ;
    END
  END w0_wmask_in[201]
  PIN w0_wmask_in[202]
    DIRECTION INPUT ;
    USE SIGNAL ;
    SHAPE ABUTMENT ;
    PORT
      LAYER met3 ;
      RECT 1670.740 184.810 1671.640 185.110 ;
    END
  END w0_wmask_in[202]
  PIN w0_wmask_in[203]
    DIRECTION INPUT ;
    USE SIGNAL ;
    SHAPE ABUTMENT ;
    PORT
      LAYER met3 ;
      RECT 1670.740 189.570 1671.640 189.870 ;
    END
  END w0_wmask_in[203]
  PIN w0_wmask_in[204]
    DIRECTION INPUT ;
    USE SIGNAL ;
    SHAPE ABUTMENT ;
    PORT
      LAYER met3 ;
      RECT 1670.740 194.330 1671.640 194.630 ;
    END
  END w0_wmask_in[204]
  PIN w0_wmask_in[205]
    DIRECTION INPUT ;
    USE SIGNAL ;
    SHAPE ABUTMENT ;
    PORT
      LAYER met3 ;
      RECT 1670.740 199.090 1671.640 199.390 ;
    END
  END w0_wmask_in[205]
  PIN w0_wmask_in[206]
    DIRECTION INPUT ;
    USE SIGNAL ;
    SHAPE ABUTMENT ;
    PORT
      LAYER met3 ;
      RECT 1670.740 203.850 1671.640 204.150 ;
    END
  END w0_wmask_in[206]
  PIN w0_wmask_in[207]
    DIRECTION INPUT ;
    USE SIGNAL ;
    SHAPE ABUTMENT ;
    PORT
      LAYER met3 ;
      RECT 1670.740 208.610 1671.640 208.910 ;
    END
  END w0_wmask_in[207]
  PIN w0_wmask_in[208]
    DIRECTION INPUT ;
    USE SIGNAL ;
    SHAPE ABUTMENT ;
    PORT
      LAYER met3 ;
      RECT 1670.740 213.370 1671.640 213.670 ;
    END
  END w0_wmask_in[208]
  PIN w0_wmask_in[209]
    DIRECTION INPUT ;
    USE SIGNAL ;
    SHAPE ABUTMENT ;
    PORT
      LAYER met3 ;
      RECT 1670.740 218.130 1671.640 218.430 ;
    END
  END w0_wmask_in[209]
  PIN w0_wmask_in[210]
    DIRECTION INPUT ;
    USE SIGNAL ;
    SHAPE ABUTMENT ;
    PORT
      LAYER met3 ;
      RECT 1670.740 222.890 1671.640 223.190 ;
    END
  END w0_wmask_in[210]
  PIN w0_wmask_in[211]
    DIRECTION INPUT ;
    USE SIGNAL ;
    SHAPE ABUTMENT ;
    PORT
      LAYER met3 ;
      RECT 1670.740 227.650 1671.640 227.950 ;
    END
  END w0_wmask_in[211]
  PIN w0_wmask_in[212]
    DIRECTION INPUT ;
    USE SIGNAL ;
    SHAPE ABUTMENT ;
    PORT
      LAYER met3 ;
      RECT 1670.740 232.410 1671.640 232.710 ;
    END
  END w0_wmask_in[212]
  PIN w0_wmask_in[213]
    DIRECTION INPUT ;
    USE SIGNAL ;
    SHAPE ABUTMENT ;
    PORT
      LAYER met3 ;
      RECT 1670.740 237.170 1671.640 237.470 ;
    END
  END w0_wmask_in[213]
  PIN w0_wmask_in[214]
    DIRECTION INPUT ;
    USE SIGNAL ;
    SHAPE ABUTMENT ;
    PORT
      LAYER met3 ;
      RECT 1670.740 241.930 1671.640 242.230 ;
    END
  END w0_wmask_in[214]
  PIN w0_wmask_in[215]
    DIRECTION INPUT ;
    USE SIGNAL ;
    SHAPE ABUTMENT ;
    PORT
      LAYER met3 ;
      RECT 1670.740 246.690 1671.640 246.990 ;
    END
  END w0_wmask_in[215]
  PIN w0_wmask_in[216]
    DIRECTION INPUT ;
    USE SIGNAL ;
    SHAPE ABUTMENT ;
    PORT
      LAYER met3 ;
      RECT 1670.740 251.450 1671.640 251.750 ;
    END
  END w0_wmask_in[216]
  PIN w0_wmask_in[217]
    DIRECTION INPUT ;
    USE SIGNAL ;
    SHAPE ABUTMENT ;
    PORT
      LAYER met3 ;
      RECT 1670.740 256.210 1671.640 256.510 ;
    END
  END w0_wmask_in[217]
  PIN w0_wmask_in[218]
    DIRECTION INPUT ;
    USE SIGNAL ;
    SHAPE ABUTMENT ;
    PORT
      LAYER met3 ;
      RECT 1670.740 260.970 1671.640 261.270 ;
    END
  END w0_wmask_in[218]
  PIN w0_wmask_in[219]
    DIRECTION INPUT ;
    USE SIGNAL ;
    SHAPE ABUTMENT ;
    PORT
      LAYER met3 ;
      RECT 1670.740 265.730 1671.640 266.030 ;
    END
  END w0_wmask_in[219]
  PIN w0_wmask_in[220]
    DIRECTION INPUT ;
    USE SIGNAL ;
    SHAPE ABUTMENT ;
    PORT
      LAYER met3 ;
      RECT 1670.740 270.490 1671.640 270.790 ;
    END
  END w0_wmask_in[220]
  PIN w0_wmask_in[221]
    DIRECTION INPUT ;
    USE SIGNAL ;
    SHAPE ABUTMENT ;
    PORT
      LAYER met3 ;
      RECT 1670.740 275.250 1671.640 275.550 ;
    END
  END w0_wmask_in[221]
  PIN w0_wmask_in[222]
    DIRECTION INPUT ;
    USE SIGNAL ;
    SHAPE ABUTMENT ;
    PORT
      LAYER met3 ;
      RECT 1670.740 280.010 1671.640 280.310 ;
    END
  END w0_wmask_in[222]
  PIN w0_wmask_in[223]
    DIRECTION INPUT ;
    USE SIGNAL ;
    SHAPE ABUTMENT ;
    PORT
      LAYER met3 ;
      RECT 1670.740 284.770 1671.640 285.070 ;
    END
  END w0_wmask_in[223]
  PIN w0_wmask_in[224]
    DIRECTION INPUT ;
    USE SIGNAL ;
    SHAPE ABUTMENT ;
    PORT
      LAYER met3 ;
      RECT 1670.740 289.530 1671.640 289.830 ;
    END
  END w0_wmask_in[224]
  PIN w0_wmask_in[225]
    DIRECTION INPUT ;
    USE SIGNAL ;
    SHAPE ABUTMENT ;
    PORT
      LAYER met3 ;
      RECT 1670.740 294.290 1671.640 294.590 ;
    END
  END w0_wmask_in[225]
  PIN w0_wmask_in[226]
    DIRECTION INPUT ;
    USE SIGNAL ;
    SHAPE ABUTMENT ;
    PORT
      LAYER met3 ;
      RECT 1670.740 299.050 1671.640 299.350 ;
    END
  END w0_wmask_in[226]
  PIN w0_wmask_in[227]
    DIRECTION INPUT ;
    USE SIGNAL ;
    SHAPE ABUTMENT ;
    PORT
      LAYER met3 ;
      RECT 1670.740 303.810 1671.640 304.110 ;
    END
  END w0_wmask_in[227]
  PIN w0_wmask_in[228]
    DIRECTION INPUT ;
    USE SIGNAL ;
    SHAPE ABUTMENT ;
    PORT
      LAYER met3 ;
      RECT 1670.740 308.570 1671.640 308.870 ;
    END
  END w0_wmask_in[228]
  PIN w0_wmask_in[229]
    DIRECTION INPUT ;
    USE SIGNAL ;
    SHAPE ABUTMENT ;
    PORT
      LAYER met3 ;
      RECT 1670.740 313.330 1671.640 313.630 ;
    END
  END w0_wmask_in[229]
  PIN w0_wmask_in[230]
    DIRECTION INPUT ;
    USE SIGNAL ;
    SHAPE ABUTMENT ;
    PORT
      LAYER met3 ;
      RECT 1670.740 318.090 1671.640 318.390 ;
    END
  END w0_wmask_in[230]
  PIN w0_wmask_in[231]
    DIRECTION INPUT ;
    USE SIGNAL ;
    SHAPE ABUTMENT ;
    PORT
      LAYER met3 ;
      RECT 1670.740 322.850 1671.640 323.150 ;
    END
  END w0_wmask_in[231]
  PIN w0_wmask_in[232]
    DIRECTION INPUT ;
    USE SIGNAL ;
    SHAPE ABUTMENT ;
    PORT
      LAYER met3 ;
      RECT 1670.740 327.610 1671.640 327.910 ;
    END
  END w0_wmask_in[232]
  PIN w0_wmask_in[233]
    DIRECTION INPUT ;
    USE SIGNAL ;
    SHAPE ABUTMENT ;
    PORT
      LAYER met3 ;
      RECT 1670.740 332.370 1671.640 332.670 ;
    END
  END w0_wmask_in[233]
  PIN w0_wmask_in[234]
    DIRECTION INPUT ;
    USE SIGNAL ;
    SHAPE ABUTMENT ;
    PORT
      LAYER met3 ;
      RECT 1670.740 337.130 1671.640 337.430 ;
    END
  END w0_wmask_in[234]
  PIN w0_wmask_in[235]
    DIRECTION INPUT ;
    USE SIGNAL ;
    SHAPE ABUTMENT ;
    PORT
      LAYER met3 ;
      RECT 1670.740 341.890 1671.640 342.190 ;
    END
  END w0_wmask_in[235]
  PIN w0_wmask_in[236]
    DIRECTION INPUT ;
    USE SIGNAL ;
    SHAPE ABUTMENT ;
    PORT
      LAYER met3 ;
      RECT 1670.740 346.650 1671.640 346.950 ;
    END
  END w0_wmask_in[236]
  PIN w0_wmask_in[237]
    DIRECTION INPUT ;
    USE SIGNAL ;
    SHAPE ABUTMENT ;
    PORT
      LAYER met3 ;
      RECT 1670.740 351.410 1671.640 351.710 ;
    END
  END w0_wmask_in[237]
  PIN w0_wmask_in[238]
    DIRECTION INPUT ;
    USE SIGNAL ;
    SHAPE ABUTMENT ;
    PORT
      LAYER met3 ;
      RECT 1670.740 356.170 1671.640 356.470 ;
    END
  END w0_wmask_in[238]
  PIN w0_wmask_in[239]
    DIRECTION INPUT ;
    USE SIGNAL ;
    SHAPE ABUTMENT ;
    PORT
      LAYER met3 ;
      RECT 1670.740 360.930 1671.640 361.230 ;
    END
  END w0_wmask_in[239]
  PIN w0_wmask_in[240]
    DIRECTION INPUT ;
    USE SIGNAL ;
    SHAPE ABUTMENT ;
    PORT
      LAYER met3 ;
      RECT 1670.740 365.690 1671.640 365.990 ;
    END
  END w0_wmask_in[240]
  PIN w0_wmask_in[241]
    DIRECTION INPUT ;
    USE SIGNAL ;
    SHAPE ABUTMENT ;
    PORT
      LAYER met3 ;
      RECT 1670.740 370.450 1671.640 370.750 ;
    END
  END w0_wmask_in[241]
  PIN w0_wmask_in[242]
    DIRECTION INPUT ;
    USE SIGNAL ;
    SHAPE ABUTMENT ;
    PORT
      LAYER met3 ;
      RECT 1670.740 375.210 1671.640 375.510 ;
    END
  END w0_wmask_in[242]
  PIN w0_wmask_in[243]
    DIRECTION INPUT ;
    USE SIGNAL ;
    SHAPE ABUTMENT ;
    PORT
      LAYER met3 ;
      RECT 1670.740 379.970 1671.640 380.270 ;
    END
  END w0_wmask_in[243]
  PIN w0_wmask_in[244]
    DIRECTION INPUT ;
    USE SIGNAL ;
    SHAPE ABUTMENT ;
    PORT
      LAYER met3 ;
      RECT 1670.740 384.730 1671.640 385.030 ;
    END
  END w0_wmask_in[244]
  PIN w0_wmask_in[245]
    DIRECTION INPUT ;
    USE SIGNAL ;
    SHAPE ABUTMENT ;
    PORT
      LAYER met3 ;
      RECT 1670.740 389.490 1671.640 389.790 ;
    END
  END w0_wmask_in[245]
  PIN w0_wmask_in[246]
    DIRECTION INPUT ;
    USE SIGNAL ;
    SHAPE ABUTMENT ;
    PORT
      LAYER met3 ;
      RECT 1670.740 394.250 1671.640 394.550 ;
    END
  END w0_wmask_in[246]
  PIN w0_wmask_in[247]
    DIRECTION INPUT ;
    USE SIGNAL ;
    SHAPE ABUTMENT ;
    PORT
      LAYER met3 ;
      RECT 1670.740 399.010 1671.640 399.310 ;
    END
  END w0_wmask_in[247]
  PIN w0_wmask_in[248]
    DIRECTION INPUT ;
    USE SIGNAL ;
    SHAPE ABUTMENT ;
    PORT
      LAYER met3 ;
      RECT 1670.740 403.770 1671.640 404.070 ;
    END
  END w0_wmask_in[248]
  PIN w0_wmask_in[249]
    DIRECTION INPUT ;
    USE SIGNAL ;
    SHAPE ABUTMENT ;
    PORT
      LAYER met3 ;
      RECT 1670.740 408.530 1671.640 408.830 ;
    END
  END w0_wmask_in[249]
  PIN w0_wmask_in[250]
    DIRECTION INPUT ;
    USE SIGNAL ;
    SHAPE ABUTMENT ;
    PORT
      LAYER met3 ;
      RECT 1670.740 413.290 1671.640 413.590 ;
    END
  END w0_wmask_in[250]
  PIN w0_wmask_in[251]
    DIRECTION INPUT ;
    USE SIGNAL ;
    SHAPE ABUTMENT ;
    PORT
      LAYER met3 ;
      RECT 1670.740 418.050 1671.640 418.350 ;
    END
  END w0_wmask_in[251]
  PIN w0_wmask_in[252]
    DIRECTION INPUT ;
    USE SIGNAL ;
    SHAPE ABUTMENT ;
    PORT
      LAYER met3 ;
      RECT 1670.740 422.810 1671.640 423.110 ;
    END
  END w0_wmask_in[252]
  PIN w0_wmask_in[253]
    DIRECTION INPUT ;
    USE SIGNAL ;
    SHAPE ABUTMENT ;
    PORT
      LAYER met3 ;
      RECT 1670.740 427.570 1671.640 427.870 ;
    END
  END w0_wmask_in[253]
  PIN w0_wmask_in[254]
    DIRECTION INPUT ;
    USE SIGNAL ;
    SHAPE ABUTMENT ;
    PORT
      LAYER met3 ;
      RECT 1670.740 432.330 1671.640 432.630 ;
    END
  END w0_wmask_in[254]
  PIN w0_wmask_in[255]
    DIRECTION INPUT ;
    USE SIGNAL ;
    SHAPE ABUTMENT ;
    PORT
      LAYER met3 ;
      RECT 1670.740 437.090 1671.640 437.390 ;
    END
  END w0_wmask_in[255]
  PIN w0_wmask_in[256]
    DIRECTION INPUT ;
    USE SIGNAL ;
    SHAPE ABUTMENT ;
    PORT
      LAYER met3 ;
      RECT 1670.740 441.850 1671.640 442.150 ;
    END
  END w0_wmask_in[256]
  PIN w0_wmask_in[257]
    DIRECTION INPUT ;
    USE SIGNAL ;
    SHAPE ABUTMENT ;
    PORT
      LAYER met3 ;
      RECT 1670.740 446.610 1671.640 446.910 ;
    END
  END w0_wmask_in[257]
  PIN w0_wmask_in[258]
    DIRECTION INPUT ;
    USE SIGNAL ;
    SHAPE ABUTMENT ;
    PORT
      LAYER met3 ;
      RECT 1670.740 451.370 1671.640 451.670 ;
    END
  END w0_wmask_in[258]
  PIN w0_wmask_in[259]
    DIRECTION INPUT ;
    USE SIGNAL ;
    SHAPE ABUTMENT ;
    PORT
      LAYER met3 ;
      RECT 1670.740 456.130 1671.640 456.430 ;
    END
  END w0_wmask_in[259]
  PIN w0_wmask_in[260]
    DIRECTION INPUT ;
    USE SIGNAL ;
    SHAPE ABUTMENT ;
    PORT
      LAYER met3 ;
      RECT 1670.740 460.890 1671.640 461.190 ;
    END
  END w0_wmask_in[260]
  PIN w0_wmask_in[261]
    DIRECTION INPUT ;
    USE SIGNAL ;
    SHAPE ABUTMENT ;
    PORT
      LAYER met3 ;
      RECT 1670.740 465.650 1671.640 465.950 ;
    END
  END w0_wmask_in[261]
  PIN w0_wmask_in[262]
    DIRECTION INPUT ;
    USE SIGNAL ;
    SHAPE ABUTMENT ;
    PORT
      LAYER met3 ;
      RECT 1670.740 470.410 1671.640 470.710 ;
    END
  END w0_wmask_in[262]
  PIN w0_wmask_in[263]
    DIRECTION INPUT ;
    USE SIGNAL ;
    SHAPE ABUTMENT ;
    PORT
      LAYER met3 ;
      RECT 1670.740 475.170 1671.640 475.470 ;
    END
  END w0_wmask_in[263]
  PIN w0_wmask_in[264]
    DIRECTION INPUT ;
    USE SIGNAL ;
    SHAPE ABUTMENT ;
    PORT
      LAYER met3 ;
      RECT 1670.740 479.930 1671.640 480.230 ;
    END
  END w0_wmask_in[264]
  PIN w0_wmask_in[265]
    DIRECTION INPUT ;
    USE SIGNAL ;
    SHAPE ABUTMENT ;
    PORT
      LAYER met3 ;
      RECT 1670.740 484.690 1671.640 484.990 ;
    END
  END w0_wmask_in[265]
  PIN w0_wmask_in[266]
    DIRECTION INPUT ;
    USE SIGNAL ;
    SHAPE ABUTMENT ;
    PORT
      LAYER met3 ;
      RECT 1670.740 489.450 1671.640 489.750 ;
    END
  END w0_wmask_in[266]
  PIN w0_wmask_in[267]
    DIRECTION INPUT ;
    USE SIGNAL ;
    SHAPE ABUTMENT ;
    PORT
      LAYER met3 ;
      RECT 1670.740 494.210 1671.640 494.510 ;
    END
  END w0_wmask_in[267]
  PIN w0_wmask_in[268]
    DIRECTION INPUT ;
    USE SIGNAL ;
    SHAPE ABUTMENT ;
    PORT
      LAYER met3 ;
      RECT 1670.740 498.970 1671.640 499.270 ;
    END
  END w0_wmask_in[268]
  PIN w0_wmask_in[269]
    DIRECTION INPUT ;
    USE SIGNAL ;
    SHAPE ABUTMENT ;
    PORT
      LAYER met3 ;
      RECT 1670.740 503.730 1671.640 504.030 ;
    END
  END w0_wmask_in[269]
  PIN w0_wmask_in[270]
    DIRECTION INPUT ;
    USE SIGNAL ;
    SHAPE ABUTMENT ;
    PORT
      LAYER met3 ;
      RECT 1670.740 508.490 1671.640 508.790 ;
    END
  END w0_wmask_in[270]
  PIN w0_wmask_in[271]
    DIRECTION INPUT ;
    USE SIGNAL ;
    SHAPE ABUTMENT ;
    PORT
      LAYER met3 ;
      RECT 1670.740 513.250 1671.640 513.550 ;
    END
  END w0_wmask_in[271]
  PIN w0_wmask_in[272]
    DIRECTION INPUT ;
    USE SIGNAL ;
    SHAPE ABUTMENT ;
    PORT
      LAYER met3 ;
      RECT 1670.740 518.010 1671.640 518.310 ;
    END
  END w0_wmask_in[272]
  PIN w0_wmask_in[273]
    DIRECTION INPUT ;
    USE SIGNAL ;
    SHAPE ABUTMENT ;
    PORT
      LAYER met3 ;
      RECT 1670.740 522.770 1671.640 523.070 ;
    END
  END w0_wmask_in[273]
  PIN w0_wmask_in[274]
    DIRECTION INPUT ;
    USE SIGNAL ;
    SHAPE ABUTMENT ;
    PORT
      LAYER met3 ;
      RECT 1670.740 527.530 1671.640 527.830 ;
    END
  END w0_wmask_in[274]
  PIN w0_wmask_in[275]
    DIRECTION INPUT ;
    USE SIGNAL ;
    SHAPE ABUTMENT ;
    PORT
      LAYER met3 ;
      RECT 1670.740 532.290 1671.640 532.590 ;
    END
  END w0_wmask_in[275]
  PIN w0_wmask_in[276]
    DIRECTION INPUT ;
    USE SIGNAL ;
    SHAPE ABUTMENT ;
    PORT
      LAYER met3 ;
      RECT 1670.740 537.050 1671.640 537.350 ;
    END
  END w0_wmask_in[276]
  PIN w0_wmask_in[277]
    DIRECTION INPUT ;
    USE SIGNAL ;
    SHAPE ABUTMENT ;
    PORT
      LAYER met3 ;
      RECT 1670.740 541.810 1671.640 542.110 ;
    END
  END w0_wmask_in[277]
  PIN w0_wmask_in[278]
    DIRECTION INPUT ;
    USE SIGNAL ;
    SHAPE ABUTMENT ;
    PORT
      LAYER met3 ;
      RECT 1670.740 546.570 1671.640 546.870 ;
    END
  END w0_wmask_in[278]
  PIN w0_wmask_in[279]
    DIRECTION INPUT ;
    USE SIGNAL ;
    SHAPE ABUTMENT ;
    PORT
      LAYER met3 ;
      RECT 1670.740 551.330 1671.640 551.630 ;
    END
  END w0_wmask_in[279]
  PIN w0_wmask_in[280]
    DIRECTION INPUT ;
    USE SIGNAL ;
    SHAPE ABUTMENT ;
    PORT
      LAYER met3 ;
      RECT 1670.740 556.090 1671.640 556.390 ;
    END
  END w0_wmask_in[280]
  PIN w0_wmask_in[281]
    DIRECTION INPUT ;
    USE SIGNAL ;
    SHAPE ABUTMENT ;
    PORT
      LAYER met3 ;
      RECT 1670.740 560.850 1671.640 561.150 ;
    END
  END w0_wmask_in[281]
  PIN w0_wmask_in[282]
    DIRECTION INPUT ;
    USE SIGNAL ;
    SHAPE ABUTMENT ;
    PORT
      LAYER met3 ;
      RECT 1670.740 565.610 1671.640 565.910 ;
    END
  END w0_wmask_in[282]
  PIN w0_wmask_in[283]
    DIRECTION INPUT ;
    USE SIGNAL ;
    SHAPE ABUTMENT ;
    PORT
      LAYER met3 ;
      RECT 1670.740 570.370 1671.640 570.670 ;
    END
  END w0_wmask_in[283]
  PIN w0_wmask_in[284]
    DIRECTION INPUT ;
    USE SIGNAL ;
    SHAPE ABUTMENT ;
    PORT
      LAYER met3 ;
      RECT 1670.740 575.130 1671.640 575.430 ;
    END
  END w0_wmask_in[284]
  PIN w0_wmask_in[285]
    DIRECTION INPUT ;
    USE SIGNAL ;
    SHAPE ABUTMENT ;
    PORT
      LAYER met3 ;
      RECT 1670.740 579.890 1671.640 580.190 ;
    END
  END w0_wmask_in[285]
  PIN w0_wmask_in[286]
    DIRECTION INPUT ;
    USE SIGNAL ;
    SHAPE ABUTMENT ;
    PORT
      LAYER met3 ;
      RECT 1670.740 584.650 1671.640 584.950 ;
    END
  END w0_wmask_in[286]
  PIN w0_wmask_in[287]
    DIRECTION INPUT ;
    USE SIGNAL ;
    SHAPE ABUTMENT ;
    PORT
      LAYER met3 ;
      RECT 1670.740 589.410 1671.640 589.710 ;
    END
  END w0_wmask_in[287]
  PIN w0_wmask_in[288]
    DIRECTION INPUT ;
    USE SIGNAL ;
    SHAPE ABUTMENT ;
    PORT
      LAYER met3 ;
      RECT 1670.740 594.170 1671.640 594.470 ;
    END
  END w0_wmask_in[288]
  PIN w0_wmask_in[289]
    DIRECTION INPUT ;
    USE SIGNAL ;
    SHAPE ABUTMENT ;
    PORT
      LAYER met3 ;
      RECT 1670.740 598.930 1671.640 599.230 ;
    END
  END w0_wmask_in[289]
  PIN w0_wmask_in[290]
    DIRECTION INPUT ;
    USE SIGNAL ;
    SHAPE ABUTMENT ;
    PORT
      LAYER met3 ;
      RECT 1670.740 603.690 1671.640 603.990 ;
    END
  END w0_wmask_in[290]
  PIN w0_wmask_in[291]
    DIRECTION INPUT ;
    USE SIGNAL ;
    SHAPE ABUTMENT ;
    PORT
      LAYER met3 ;
      RECT 1670.740 608.450 1671.640 608.750 ;
    END
  END w0_wmask_in[291]
  PIN w0_wmask_in[292]
    DIRECTION INPUT ;
    USE SIGNAL ;
    SHAPE ABUTMENT ;
    PORT
      LAYER met3 ;
      RECT 1670.740 613.210 1671.640 613.510 ;
    END
  END w0_wmask_in[292]
  PIN w0_wmask_in[293]
    DIRECTION INPUT ;
    USE SIGNAL ;
    SHAPE ABUTMENT ;
    PORT
      LAYER met3 ;
      RECT 1670.740 617.970 1671.640 618.270 ;
    END
  END w0_wmask_in[293]
  PIN w0_wmask_in[294]
    DIRECTION INPUT ;
    USE SIGNAL ;
    SHAPE ABUTMENT ;
    PORT
      LAYER met3 ;
      RECT 1670.740 622.730 1671.640 623.030 ;
    END
  END w0_wmask_in[294]
  PIN w0_wmask_in[295]
    DIRECTION INPUT ;
    USE SIGNAL ;
    SHAPE ABUTMENT ;
    PORT
      LAYER met3 ;
      RECT 1670.740 627.490 1671.640 627.790 ;
    END
  END w0_wmask_in[295]
  PIN w0_wmask_in[296]
    DIRECTION INPUT ;
    USE SIGNAL ;
    SHAPE ABUTMENT ;
    PORT
      LAYER met3 ;
      RECT 1670.740 632.250 1671.640 632.550 ;
    END
  END w0_wmask_in[296]
  PIN w0_wmask_in[297]
    DIRECTION INPUT ;
    USE SIGNAL ;
    SHAPE ABUTMENT ;
    PORT
      LAYER met3 ;
      RECT 1670.740 637.010 1671.640 637.310 ;
    END
  END w0_wmask_in[297]
  PIN w0_wmask_in[298]
    DIRECTION INPUT ;
    USE SIGNAL ;
    SHAPE ABUTMENT ;
    PORT
      LAYER met3 ;
      RECT 1670.740 641.770 1671.640 642.070 ;
    END
  END w0_wmask_in[298]
  PIN w0_wmask_in[299]
    DIRECTION INPUT ;
    USE SIGNAL ;
    SHAPE ABUTMENT ;
    PORT
      LAYER met3 ;
      RECT 1670.740 646.530 1671.640 646.830 ;
    END
  END w0_wmask_in[299]
  PIN w0_wmask_in[300]
    DIRECTION INPUT ;
    USE SIGNAL ;
    SHAPE ABUTMENT ;
    PORT
      LAYER met3 ;
      RECT 1670.740 651.290 1671.640 651.590 ;
    END
  END w0_wmask_in[300]
  PIN w0_wmask_in[301]
    DIRECTION INPUT ;
    USE SIGNAL ;
    SHAPE ABUTMENT ;
    PORT
      LAYER met3 ;
      RECT 1670.740 656.050 1671.640 656.350 ;
    END
  END w0_wmask_in[301]
  PIN w0_wmask_in[302]
    DIRECTION INPUT ;
    USE SIGNAL ;
    SHAPE ABUTMENT ;
    PORT
      LAYER met3 ;
      RECT 1670.740 660.810 1671.640 661.110 ;
    END
  END w0_wmask_in[302]
  PIN w0_wmask_in[303]
    DIRECTION INPUT ;
    USE SIGNAL ;
    SHAPE ABUTMENT ;
    PORT
      LAYER met3 ;
      RECT 1670.740 665.570 1671.640 665.870 ;
    END
  END w0_wmask_in[303]
  PIN w0_wmask_in[304]
    DIRECTION INPUT ;
    USE SIGNAL ;
    SHAPE ABUTMENT ;
    PORT
      LAYER met3 ;
      RECT 1670.740 670.330 1671.640 670.630 ;
    END
  END w0_wmask_in[304]
  PIN w0_wmask_in[305]
    DIRECTION INPUT ;
    USE SIGNAL ;
    SHAPE ABUTMENT ;
    PORT
      LAYER met3 ;
      RECT 1670.740 675.090 1671.640 675.390 ;
    END
  END w0_wmask_in[305]
  PIN w0_wmask_in[306]
    DIRECTION INPUT ;
    USE SIGNAL ;
    SHAPE ABUTMENT ;
    PORT
      LAYER met3 ;
      RECT 1670.740 679.850 1671.640 680.150 ;
    END
  END w0_wmask_in[306]
  PIN w0_wmask_in[307]
    DIRECTION INPUT ;
    USE SIGNAL ;
    SHAPE ABUTMENT ;
    PORT
      LAYER met3 ;
      RECT 1670.740 684.610 1671.640 684.910 ;
    END
  END w0_wmask_in[307]
  PIN w0_wmask_in[308]
    DIRECTION INPUT ;
    USE SIGNAL ;
    SHAPE ABUTMENT ;
    PORT
      LAYER met3 ;
      RECT 1670.740 689.370 1671.640 689.670 ;
    END
  END w0_wmask_in[308]
  PIN w0_wmask_in[309]
    DIRECTION INPUT ;
    USE SIGNAL ;
    SHAPE ABUTMENT ;
    PORT
      LAYER met3 ;
      RECT 1670.740 694.130 1671.640 694.430 ;
    END
  END w0_wmask_in[309]
  PIN w0_wmask_in[310]
    DIRECTION INPUT ;
    USE SIGNAL ;
    SHAPE ABUTMENT ;
    PORT
      LAYER met3 ;
      RECT 1670.740 698.890 1671.640 699.190 ;
    END
  END w0_wmask_in[310]
  PIN w0_wmask_in[311]
    DIRECTION INPUT ;
    USE SIGNAL ;
    SHAPE ABUTMENT ;
    PORT
      LAYER met3 ;
      RECT 1670.740 703.650 1671.640 703.950 ;
    END
  END w0_wmask_in[311]
  PIN w0_wmask_in[312]
    DIRECTION INPUT ;
    USE SIGNAL ;
    SHAPE ABUTMENT ;
    PORT
      LAYER met3 ;
      RECT 1670.740 708.410 1671.640 708.710 ;
    END
  END w0_wmask_in[312]
  PIN w0_wmask_in[313]
    DIRECTION INPUT ;
    USE SIGNAL ;
    SHAPE ABUTMENT ;
    PORT
      LAYER met3 ;
      RECT 1670.740 713.170 1671.640 713.470 ;
    END
  END w0_wmask_in[313]
  PIN w0_wmask_in[314]
    DIRECTION INPUT ;
    USE SIGNAL ;
    SHAPE ABUTMENT ;
    PORT
      LAYER met3 ;
      RECT 1670.740 717.930 1671.640 718.230 ;
    END
  END w0_wmask_in[314]
  PIN w0_wmask_in[315]
    DIRECTION INPUT ;
    USE SIGNAL ;
    SHAPE ABUTMENT ;
    PORT
      LAYER met3 ;
      RECT 1670.740 722.690 1671.640 722.990 ;
    END
  END w0_wmask_in[315]
  PIN w0_wmask_in[316]
    DIRECTION INPUT ;
    USE SIGNAL ;
    SHAPE ABUTMENT ;
    PORT
      LAYER met3 ;
      RECT 1670.740 727.450 1671.640 727.750 ;
    END
  END w0_wmask_in[316]
  PIN w0_wmask_in[317]
    DIRECTION INPUT ;
    USE SIGNAL ;
    SHAPE ABUTMENT ;
    PORT
      LAYER met3 ;
      RECT 1670.740 732.210 1671.640 732.510 ;
    END
  END w0_wmask_in[317]
  PIN w0_wmask_in[318]
    DIRECTION INPUT ;
    USE SIGNAL ;
    SHAPE ABUTMENT ;
    PORT
      LAYER met3 ;
      RECT 1670.740 736.970 1671.640 737.270 ;
    END
  END w0_wmask_in[318]
  PIN w0_wmask_in[319]
    DIRECTION INPUT ;
    USE SIGNAL ;
    SHAPE ABUTMENT ;
    PORT
      LAYER met3 ;
      RECT 1670.740 741.730 1671.640 742.030 ;
    END
  END w0_wmask_in[319]
  PIN w0_wmask_in[320]
    DIRECTION INPUT ;
    USE SIGNAL ;
    SHAPE ABUTMENT ;
    PORT
      LAYER met3 ;
      RECT 1670.740 746.490 1671.640 746.790 ;
    END
  END w0_wmask_in[320]
  PIN w0_wmask_in[321]
    DIRECTION INPUT ;
    USE SIGNAL ;
    SHAPE ABUTMENT ;
    PORT
      LAYER met3 ;
      RECT 1670.740 751.250 1671.640 751.550 ;
    END
  END w0_wmask_in[321]
  PIN w0_wmask_in[322]
    DIRECTION INPUT ;
    USE SIGNAL ;
    SHAPE ABUTMENT ;
    PORT
      LAYER met3 ;
      RECT 1670.740 756.010 1671.640 756.310 ;
    END
  END w0_wmask_in[322]
  PIN w0_wmask_in[323]
    DIRECTION INPUT ;
    USE SIGNAL ;
    SHAPE ABUTMENT ;
    PORT
      LAYER met3 ;
      RECT 1670.740 760.770 1671.640 761.070 ;
    END
  END w0_wmask_in[323]
  PIN w0_wmask_in[324]
    DIRECTION INPUT ;
    USE SIGNAL ;
    SHAPE ABUTMENT ;
    PORT
      LAYER met3 ;
      RECT 1670.740 765.530 1671.640 765.830 ;
    END
  END w0_wmask_in[324]
  PIN w0_wmask_in[325]
    DIRECTION INPUT ;
    USE SIGNAL ;
    SHAPE ABUTMENT ;
    PORT
      LAYER met3 ;
      RECT 1670.740 770.290 1671.640 770.590 ;
    END
  END w0_wmask_in[325]
  PIN w0_wmask_in[326]
    DIRECTION INPUT ;
    USE SIGNAL ;
    SHAPE ABUTMENT ;
    PORT
      LAYER met3 ;
      RECT 1670.740 775.050 1671.640 775.350 ;
    END
  END w0_wmask_in[326]
  PIN w0_wmask_in[327]
    DIRECTION INPUT ;
    USE SIGNAL ;
    SHAPE ABUTMENT ;
    PORT
      LAYER met2 ;
      RECT 2.690 1688.700 2.830 1689.120 ;
    END
  END w0_wmask_in[327]
  PIN w0_wmask_in[328]
    DIRECTION INPUT ;
    USE SIGNAL ;
    SHAPE ABUTMENT ;
    PORT
      LAYER met2 ;
      RECT 4.990 1688.700 5.130 1689.120 ;
    END
  END w0_wmask_in[328]
  PIN w0_wmask_in[329]
    DIRECTION INPUT ;
    USE SIGNAL ;
    SHAPE ABUTMENT ;
    PORT
      LAYER met2 ;
      RECT 7.290 1688.700 7.430 1689.120 ;
    END
  END w0_wmask_in[329]
  PIN w0_wmask_in[330]
    DIRECTION INPUT ;
    USE SIGNAL ;
    SHAPE ABUTMENT ;
    PORT
      LAYER met2 ;
      RECT 9.590 1688.700 9.730 1689.120 ;
    END
  END w0_wmask_in[330]
  PIN w0_wmask_in[331]
    DIRECTION INPUT ;
    USE SIGNAL ;
    SHAPE ABUTMENT ;
    PORT
      LAYER met2 ;
      RECT 11.890 1688.700 12.030 1689.120 ;
    END
  END w0_wmask_in[331]
  PIN w0_wmask_in[332]
    DIRECTION INPUT ;
    USE SIGNAL ;
    SHAPE ABUTMENT ;
    PORT
      LAYER met2 ;
      RECT 14.190 1688.700 14.330 1689.120 ;
    END
  END w0_wmask_in[332]
  PIN w0_wmask_in[333]
    DIRECTION INPUT ;
    USE SIGNAL ;
    SHAPE ABUTMENT ;
    PORT
      LAYER met2 ;
      RECT 16.490 1688.700 16.630 1689.120 ;
    END
  END w0_wmask_in[333]
  PIN w0_wmask_in[334]
    DIRECTION INPUT ;
    USE SIGNAL ;
    SHAPE ABUTMENT ;
    PORT
      LAYER met2 ;
      RECT 18.790 1688.700 18.930 1689.120 ;
    END
  END w0_wmask_in[334]
  PIN w0_wmask_in[335]
    DIRECTION INPUT ;
    USE SIGNAL ;
    SHAPE ABUTMENT ;
    PORT
      LAYER met2 ;
      RECT 21.090 1688.700 21.230 1689.120 ;
    END
  END w0_wmask_in[335]
  PIN w0_wmask_in[336]
    DIRECTION INPUT ;
    USE SIGNAL ;
    SHAPE ABUTMENT ;
    PORT
      LAYER met2 ;
      RECT 23.390 1688.700 23.530 1689.120 ;
    END
  END w0_wmask_in[336]
  PIN w0_wmask_in[337]
    DIRECTION INPUT ;
    USE SIGNAL ;
    SHAPE ABUTMENT ;
    PORT
      LAYER met2 ;
      RECT 25.690 1688.700 25.830 1689.120 ;
    END
  END w0_wmask_in[337]
  PIN w0_wmask_in[338]
    DIRECTION INPUT ;
    USE SIGNAL ;
    SHAPE ABUTMENT ;
    PORT
      LAYER met2 ;
      RECT 27.990 1688.700 28.130 1689.120 ;
    END
  END w0_wmask_in[338]
  PIN w0_wmask_in[339]
    DIRECTION INPUT ;
    USE SIGNAL ;
    SHAPE ABUTMENT ;
    PORT
      LAYER met2 ;
      RECT 30.290 1688.700 30.430 1689.120 ;
    END
  END w0_wmask_in[339]
  PIN w0_wmask_in[340]
    DIRECTION INPUT ;
    USE SIGNAL ;
    SHAPE ABUTMENT ;
    PORT
      LAYER met2 ;
      RECT 32.590 1688.700 32.730 1689.120 ;
    END
  END w0_wmask_in[340]
  PIN w0_wmask_in[341]
    DIRECTION INPUT ;
    USE SIGNAL ;
    SHAPE ABUTMENT ;
    PORT
      LAYER met2 ;
      RECT 34.890 1688.700 35.030 1689.120 ;
    END
  END w0_wmask_in[341]
  PIN w0_wmask_in[342]
    DIRECTION INPUT ;
    USE SIGNAL ;
    SHAPE ABUTMENT ;
    PORT
      LAYER met2 ;
      RECT 37.190 1688.700 37.330 1689.120 ;
    END
  END w0_wmask_in[342]
  PIN w0_wmask_in[343]
    DIRECTION INPUT ;
    USE SIGNAL ;
    SHAPE ABUTMENT ;
    PORT
      LAYER met2 ;
      RECT 39.490 1688.700 39.630 1689.120 ;
    END
  END w0_wmask_in[343]
  PIN w0_wmask_in[344]
    DIRECTION INPUT ;
    USE SIGNAL ;
    SHAPE ABUTMENT ;
    PORT
      LAYER met2 ;
      RECT 41.790 1688.700 41.930 1689.120 ;
    END
  END w0_wmask_in[344]
  PIN w0_wmask_in[345]
    DIRECTION INPUT ;
    USE SIGNAL ;
    SHAPE ABUTMENT ;
    PORT
      LAYER met2 ;
      RECT 44.090 1688.700 44.230 1689.120 ;
    END
  END w0_wmask_in[345]
  PIN w0_wmask_in[346]
    DIRECTION INPUT ;
    USE SIGNAL ;
    SHAPE ABUTMENT ;
    PORT
      LAYER met2 ;
      RECT 46.390 1688.700 46.530 1689.120 ;
    END
  END w0_wmask_in[346]
  PIN w0_wmask_in[347]
    DIRECTION INPUT ;
    USE SIGNAL ;
    SHAPE ABUTMENT ;
    PORT
      LAYER met2 ;
      RECT 48.690 1688.700 48.830 1689.120 ;
    END
  END w0_wmask_in[347]
  PIN w0_wmask_in[348]
    DIRECTION INPUT ;
    USE SIGNAL ;
    SHAPE ABUTMENT ;
    PORT
      LAYER met2 ;
      RECT 50.990 1688.700 51.130 1689.120 ;
    END
  END w0_wmask_in[348]
  PIN w0_wmask_in[349]
    DIRECTION INPUT ;
    USE SIGNAL ;
    SHAPE ABUTMENT ;
    PORT
      LAYER met2 ;
      RECT 53.290 1688.700 53.430 1689.120 ;
    END
  END w0_wmask_in[349]
  PIN w0_wmask_in[350]
    DIRECTION INPUT ;
    USE SIGNAL ;
    SHAPE ABUTMENT ;
    PORT
      LAYER met2 ;
      RECT 55.590 1688.700 55.730 1689.120 ;
    END
  END w0_wmask_in[350]
  PIN w0_wmask_in[351]
    DIRECTION INPUT ;
    USE SIGNAL ;
    SHAPE ABUTMENT ;
    PORT
      LAYER met2 ;
      RECT 57.890 1688.700 58.030 1689.120 ;
    END
  END w0_wmask_in[351]
  PIN w0_wmask_in[352]
    DIRECTION INPUT ;
    USE SIGNAL ;
    SHAPE ABUTMENT ;
    PORT
      LAYER met2 ;
      RECT 60.190 1688.700 60.330 1689.120 ;
    END
  END w0_wmask_in[352]
  PIN w0_wmask_in[353]
    DIRECTION INPUT ;
    USE SIGNAL ;
    SHAPE ABUTMENT ;
    PORT
      LAYER met2 ;
      RECT 62.490 1688.700 62.630 1689.120 ;
    END
  END w0_wmask_in[353]
  PIN w0_wmask_in[354]
    DIRECTION INPUT ;
    USE SIGNAL ;
    SHAPE ABUTMENT ;
    PORT
      LAYER met2 ;
      RECT 64.790 1688.700 64.930 1689.120 ;
    END
  END w0_wmask_in[354]
  PIN w0_wmask_in[355]
    DIRECTION INPUT ;
    USE SIGNAL ;
    SHAPE ABUTMENT ;
    PORT
      LAYER met2 ;
      RECT 67.090 1688.700 67.230 1689.120 ;
    END
  END w0_wmask_in[355]
  PIN w0_wmask_in[356]
    DIRECTION INPUT ;
    USE SIGNAL ;
    SHAPE ABUTMENT ;
    PORT
      LAYER met2 ;
      RECT 69.390 1688.700 69.530 1689.120 ;
    END
  END w0_wmask_in[356]
  PIN w0_wmask_in[357]
    DIRECTION INPUT ;
    USE SIGNAL ;
    SHAPE ABUTMENT ;
    PORT
      LAYER met2 ;
      RECT 71.690 1688.700 71.830 1689.120 ;
    END
  END w0_wmask_in[357]
  PIN w0_wmask_in[358]
    DIRECTION INPUT ;
    USE SIGNAL ;
    SHAPE ABUTMENT ;
    PORT
      LAYER met2 ;
      RECT 73.990 1688.700 74.130 1689.120 ;
    END
  END w0_wmask_in[358]
  PIN w0_wmask_in[359]
    DIRECTION INPUT ;
    USE SIGNAL ;
    SHAPE ABUTMENT ;
    PORT
      LAYER met2 ;
      RECT 76.290 1688.700 76.430 1689.120 ;
    END
  END w0_wmask_in[359]
  PIN w0_wmask_in[360]
    DIRECTION INPUT ;
    USE SIGNAL ;
    SHAPE ABUTMENT ;
    PORT
      LAYER met2 ;
      RECT 78.590 1688.700 78.730 1689.120 ;
    END
  END w0_wmask_in[360]
  PIN w0_wmask_in[361]
    DIRECTION INPUT ;
    USE SIGNAL ;
    SHAPE ABUTMENT ;
    PORT
      LAYER met2 ;
      RECT 80.890 1688.700 81.030 1689.120 ;
    END
  END w0_wmask_in[361]
  PIN w0_wmask_in[362]
    DIRECTION INPUT ;
    USE SIGNAL ;
    SHAPE ABUTMENT ;
    PORT
      LAYER met2 ;
      RECT 83.190 1688.700 83.330 1689.120 ;
    END
  END w0_wmask_in[362]
  PIN w0_wmask_in[363]
    DIRECTION INPUT ;
    USE SIGNAL ;
    SHAPE ABUTMENT ;
    PORT
      LAYER met2 ;
      RECT 85.490 1688.700 85.630 1689.120 ;
    END
  END w0_wmask_in[363]
  PIN w0_wmask_in[364]
    DIRECTION INPUT ;
    USE SIGNAL ;
    SHAPE ABUTMENT ;
    PORT
      LAYER met2 ;
      RECT 87.790 1688.700 87.930 1689.120 ;
    END
  END w0_wmask_in[364]
  PIN w0_wmask_in[365]
    DIRECTION INPUT ;
    USE SIGNAL ;
    SHAPE ABUTMENT ;
    PORT
      LAYER met2 ;
      RECT 90.090 1688.700 90.230 1689.120 ;
    END
  END w0_wmask_in[365]
  PIN w0_wmask_in[366]
    DIRECTION INPUT ;
    USE SIGNAL ;
    SHAPE ABUTMENT ;
    PORT
      LAYER met2 ;
      RECT 92.390 1688.700 92.530 1689.120 ;
    END
  END w0_wmask_in[366]
  PIN w0_wmask_in[367]
    DIRECTION INPUT ;
    USE SIGNAL ;
    SHAPE ABUTMENT ;
    PORT
      LAYER met2 ;
      RECT 94.690 1688.700 94.830 1689.120 ;
    END
  END w0_wmask_in[367]
  PIN w0_wmask_in[368]
    DIRECTION INPUT ;
    USE SIGNAL ;
    SHAPE ABUTMENT ;
    PORT
      LAYER met2 ;
      RECT 96.990 1688.700 97.130 1689.120 ;
    END
  END w0_wmask_in[368]
  PIN w0_wmask_in[369]
    DIRECTION INPUT ;
    USE SIGNAL ;
    SHAPE ABUTMENT ;
    PORT
      LAYER met2 ;
      RECT 99.290 1688.700 99.430 1689.120 ;
    END
  END w0_wmask_in[369]
  PIN w0_wmask_in[370]
    DIRECTION INPUT ;
    USE SIGNAL ;
    SHAPE ABUTMENT ;
    PORT
      LAYER met2 ;
      RECT 101.590 1688.700 101.730 1689.120 ;
    END
  END w0_wmask_in[370]
  PIN w0_wmask_in[371]
    DIRECTION INPUT ;
    USE SIGNAL ;
    SHAPE ABUTMENT ;
    PORT
      LAYER met2 ;
      RECT 103.890 1688.700 104.030 1689.120 ;
    END
  END w0_wmask_in[371]
  PIN w0_wmask_in[372]
    DIRECTION INPUT ;
    USE SIGNAL ;
    SHAPE ABUTMENT ;
    PORT
      LAYER met2 ;
      RECT 106.190 1688.700 106.330 1689.120 ;
    END
  END w0_wmask_in[372]
  PIN w0_wmask_in[373]
    DIRECTION INPUT ;
    USE SIGNAL ;
    SHAPE ABUTMENT ;
    PORT
      LAYER met2 ;
      RECT 108.490 1688.700 108.630 1689.120 ;
    END
  END w0_wmask_in[373]
  PIN w0_wmask_in[374]
    DIRECTION INPUT ;
    USE SIGNAL ;
    SHAPE ABUTMENT ;
    PORT
      LAYER met2 ;
      RECT 110.790 1688.700 110.930 1689.120 ;
    END
  END w0_wmask_in[374]
  PIN w0_wmask_in[375]
    DIRECTION INPUT ;
    USE SIGNAL ;
    SHAPE ABUTMENT ;
    PORT
      LAYER met2 ;
      RECT 113.090 1688.700 113.230 1689.120 ;
    END
  END w0_wmask_in[375]
  PIN w0_wmask_in[376]
    DIRECTION INPUT ;
    USE SIGNAL ;
    SHAPE ABUTMENT ;
    PORT
      LAYER met2 ;
      RECT 115.390 1688.700 115.530 1689.120 ;
    END
  END w0_wmask_in[376]
  PIN w0_wmask_in[377]
    DIRECTION INPUT ;
    USE SIGNAL ;
    SHAPE ABUTMENT ;
    PORT
      LAYER met2 ;
      RECT 117.690 1688.700 117.830 1689.120 ;
    END
  END w0_wmask_in[377]
  PIN w0_wmask_in[378]
    DIRECTION INPUT ;
    USE SIGNAL ;
    SHAPE ABUTMENT ;
    PORT
      LAYER met2 ;
      RECT 119.990 1688.700 120.130 1689.120 ;
    END
  END w0_wmask_in[378]
  PIN w0_wmask_in[379]
    DIRECTION INPUT ;
    USE SIGNAL ;
    SHAPE ABUTMENT ;
    PORT
      LAYER met2 ;
      RECT 122.290 1688.700 122.430 1689.120 ;
    END
  END w0_wmask_in[379]
  PIN w0_wmask_in[380]
    DIRECTION INPUT ;
    USE SIGNAL ;
    SHAPE ABUTMENT ;
    PORT
      LAYER met2 ;
      RECT 124.590 1688.700 124.730 1689.120 ;
    END
  END w0_wmask_in[380]
  PIN w0_wmask_in[381]
    DIRECTION INPUT ;
    USE SIGNAL ;
    SHAPE ABUTMENT ;
    PORT
      LAYER met2 ;
      RECT 126.890 1688.700 127.030 1689.120 ;
    END
  END w0_wmask_in[381]
  PIN w0_wmask_in[382]
    DIRECTION INPUT ;
    USE SIGNAL ;
    SHAPE ABUTMENT ;
    PORT
      LAYER met2 ;
      RECT 129.190 1688.700 129.330 1689.120 ;
    END
  END w0_wmask_in[382]
  PIN w0_wmask_in[383]
    DIRECTION INPUT ;
    USE SIGNAL ;
    SHAPE ABUTMENT ;
    PORT
      LAYER met2 ;
      RECT 131.490 1688.700 131.630 1689.120 ;
    END
  END w0_wmask_in[383]
  PIN w0_wmask_in[384]
    DIRECTION INPUT ;
    USE SIGNAL ;
    SHAPE ABUTMENT ;
    PORT
      LAYER met2 ;
      RECT 133.790 1688.700 133.930 1689.120 ;
    END
  END w0_wmask_in[384]
  PIN w0_wmask_in[385]
    DIRECTION INPUT ;
    USE SIGNAL ;
    SHAPE ABUTMENT ;
    PORT
      LAYER met2 ;
      RECT 136.090 1688.700 136.230 1689.120 ;
    END
  END w0_wmask_in[385]
  PIN w0_wmask_in[386]
    DIRECTION INPUT ;
    USE SIGNAL ;
    SHAPE ABUTMENT ;
    PORT
      LAYER met2 ;
      RECT 138.390 1688.700 138.530 1689.120 ;
    END
  END w0_wmask_in[386]
  PIN w0_wmask_in[387]
    DIRECTION INPUT ;
    USE SIGNAL ;
    SHAPE ABUTMENT ;
    PORT
      LAYER met2 ;
      RECT 140.690 1688.700 140.830 1689.120 ;
    END
  END w0_wmask_in[387]
  PIN w0_wmask_in[388]
    DIRECTION INPUT ;
    USE SIGNAL ;
    SHAPE ABUTMENT ;
    PORT
      LAYER met2 ;
      RECT 142.990 1688.700 143.130 1689.120 ;
    END
  END w0_wmask_in[388]
  PIN w0_wmask_in[389]
    DIRECTION INPUT ;
    USE SIGNAL ;
    SHAPE ABUTMENT ;
    PORT
      LAYER met2 ;
      RECT 145.290 1688.700 145.430 1689.120 ;
    END
  END w0_wmask_in[389]
  PIN w0_wmask_in[390]
    DIRECTION INPUT ;
    USE SIGNAL ;
    SHAPE ABUTMENT ;
    PORT
      LAYER met2 ;
      RECT 147.590 1688.700 147.730 1689.120 ;
    END
  END w0_wmask_in[390]
  PIN w0_wmask_in[391]
    DIRECTION INPUT ;
    USE SIGNAL ;
    SHAPE ABUTMENT ;
    PORT
      LAYER met2 ;
      RECT 149.890 1688.700 150.030 1689.120 ;
    END
  END w0_wmask_in[391]
  PIN w0_wmask_in[392]
    DIRECTION INPUT ;
    USE SIGNAL ;
    SHAPE ABUTMENT ;
    PORT
      LAYER met2 ;
      RECT 152.190 1688.700 152.330 1689.120 ;
    END
  END w0_wmask_in[392]
  PIN w0_wmask_in[393]
    DIRECTION INPUT ;
    USE SIGNAL ;
    SHAPE ABUTMENT ;
    PORT
      LAYER met2 ;
      RECT 154.490 1688.700 154.630 1689.120 ;
    END
  END w0_wmask_in[393]
  PIN w0_wmask_in[394]
    DIRECTION INPUT ;
    USE SIGNAL ;
    SHAPE ABUTMENT ;
    PORT
      LAYER met2 ;
      RECT 156.790 1688.700 156.930 1689.120 ;
    END
  END w0_wmask_in[394]
  PIN w0_wmask_in[395]
    DIRECTION INPUT ;
    USE SIGNAL ;
    SHAPE ABUTMENT ;
    PORT
      LAYER met2 ;
      RECT 159.090 1688.700 159.230 1689.120 ;
    END
  END w0_wmask_in[395]
  PIN w0_wmask_in[396]
    DIRECTION INPUT ;
    USE SIGNAL ;
    SHAPE ABUTMENT ;
    PORT
      LAYER met2 ;
      RECT 161.390 1688.700 161.530 1689.120 ;
    END
  END w0_wmask_in[396]
  PIN w0_wmask_in[397]
    DIRECTION INPUT ;
    USE SIGNAL ;
    SHAPE ABUTMENT ;
    PORT
      LAYER met2 ;
      RECT 163.690 1688.700 163.830 1689.120 ;
    END
  END w0_wmask_in[397]
  PIN w0_wmask_in[398]
    DIRECTION INPUT ;
    USE SIGNAL ;
    SHAPE ABUTMENT ;
    PORT
      LAYER met2 ;
      RECT 165.990 1688.700 166.130 1689.120 ;
    END
  END w0_wmask_in[398]
  PIN w0_wmask_in[399]
    DIRECTION INPUT ;
    USE SIGNAL ;
    SHAPE ABUTMENT ;
    PORT
      LAYER met2 ;
      RECT 168.290 1688.700 168.430 1689.120 ;
    END
  END w0_wmask_in[399]
  PIN w0_wmask_in[400]
    DIRECTION INPUT ;
    USE SIGNAL ;
    SHAPE ABUTMENT ;
    PORT
      LAYER met2 ;
      RECT 170.590 1688.700 170.730 1689.120 ;
    END
  END w0_wmask_in[400]
  PIN w0_wmask_in[401]
    DIRECTION INPUT ;
    USE SIGNAL ;
    SHAPE ABUTMENT ;
    PORT
      LAYER met2 ;
      RECT 172.890 1688.700 173.030 1689.120 ;
    END
  END w0_wmask_in[401]
  PIN w0_wmask_in[402]
    DIRECTION INPUT ;
    USE SIGNAL ;
    SHAPE ABUTMENT ;
    PORT
      LAYER met2 ;
      RECT 175.190 1688.700 175.330 1689.120 ;
    END
  END w0_wmask_in[402]
  PIN w0_wmask_in[403]
    DIRECTION INPUT ;
    USE SIGNAL ;
    SHAPE ABUTMENT ;
    PORT
      LAYER met2 ;
      RECT 177.490 1688.700 177.630 1689.120 ;
    END
  END w0_wmask_in[403]
  PIN w0_wmask_in[404]
    DIRECTION INPUT ;
    USE SIGNAL ;
    SHAPE ABUTMENT ;
    PORT
      LAYER met2 ;
      RECT 179.790 1688.700 179.930 1689.120 ;
    END
  END w0_wmask_in[404]
  PIN w0_wmask_in[405]
    DIRECTION INPUT ;
    USE SIGNAL ;
    SHAPE ABUTMENT ;
    PORT
      LAYER met2 ;
      RECT 182.090 1688.700 182.230 1689.120 ;
    END
  END w0_wmask_in[405]
  PIN w0_wmask_in[406]
    DIRECTION INPUT ;
    USE SIGNAL ;
    SHAPE ABUTMENT ;
    PORT
      LAYER met2 ;
      RECT 184.390 1688.700 184.530 1689.120 ;
    END
  END w0_wmask_in[406]
  PIN w0_wmask_in[407]
    DIRECTION INPUT ;
    USE SIGNAL ;
    SHAPE ABUTMENT ;
    PORT
      LAYER met2 ;
      RECT 186.690 1688.700 186.830 1689.120 ;
    END
  END w0_wmask_in[407]
  PIN w0_wmask_in[408]
    DIRECTION INPUT ;
    USE SIGNAL ;
    SHAPE ABUTMENT ;
    PORT
      LAYER met2 ;
      RECT 188.990 1688.700 189.130 1689.120 ;
    END
  END w0_wmask_in[408]
  PIN w0_wmask_in[409]
    DIRECTION INPUT ;
    USE SIGNAL ;
    SHAPE ABUTMENT ;
    PORT
      LAYER met2 ;
      RECT 191.290 1688.700 191.430 1689.120 ;
    END
  END w0_wmask_in[409]
  PIN w0_wmask_in[410]
    DIRECTION INPUT ;
    USE SIGNAL ;
    SHAPE ABUTMENT ;
    PORT
      LAYER met2 ;
      RECT 193.590 1688.700 193.730 1689.120 ;
    END
  END w0_wmask_in[410]
  PIN w0_wmask_in[411]
    DIRECTION INPUT ;
    USE SIGNAL ;
    SHAPE ABUTMENT ;
    PORT
      LAYER met2 ;
      RECT 195.890 1688.700 196.030 1689.120 ;
    END
  END w0_wmask_in[411]
  PIN w0_wmask_in[412]
    DIRECTION INPUT ;
    USE SIGNAL ;
    SHAPE ABUTMENT ;
    PORT
      LAYER met2 ;
      RECT 198.190 1688.700 198.330 1689.120 ;
    END
  END w0_wmask_in[412]
  PIN w0_wmask_in[413]
    DIRECTION INPUT ;
    USE SIGNAL ;
    SHAPE ABUTMENT ;
    PORT
      LAYER met2 ;
      RECT 200.490 1688.700 200.630 1689.120 ;
    END
  END w0_wmask_in[413]
  PIN w0_wmask_in[414]
    DIRECTION INPUT ;
    USE SIGNAL ;
    SHAPE ABUTMENT ;
    PORT
      LAYER met2 ;
      RECT 202.790 1688.700 202.930 1689.120 ;
    END
  END w0_wmask_in[414]
  PIN w0_wmask_in[415]
    DIRECTION INPUT ;
    USE SIGNAL ;
    SHAPE ABUTMENT ;
    PORT
      LAYER met2 ;
      RECT 205.090 1688.700 205.230 1689.120 ;
    END
  END w0_wmask_in[415]
  PIN w0_wmask_in[416]
    DIRECTION INPUT ;
    USE SIGNAL ;
    SHAPE ABUTMENT ;
    PORT
      LAYER met2 ;
      RECT 207.390 1688.700 207.530 1689.120 ;
    END
  END w0_wmask_in[416]
  PIN w0_wmask_in[417]
    DIRECTION INPUT ;
    USE SIGNAL ;
    SHAPE ABUTMENT ;
    PORT
      LAYER met2 ;
      RECT 209.690 1688.700 209.830 1689.120 ;
    END
  END w0_wmask_in[417]
  PIN w0_wmask_in[418]
    DIRECTION INPUT ;
    USE SIGNAL ;
    SHAPE ABUTMENT ;
    PORT
      LAYER met2 ;
      RECT 211.990 1688.700 212.130 1689.120 ;
    END
  END w0_wmask_in[418]
  PIN w0_wmask_in[419]
    DIRECTION INPUT ;
    USE SIGNAL ;
    SHAPE ABUTMENT ;
    PORT
      LAYER met2 ;
      RECT 214.290 1688.700 214.430 1689.120 ;
    END
  END w0_wmask_in[419]
  PIN w0_wmask_in[420]
    DIRECTION INPUT ;
    USE SIGNAL ;
    SHAPE ABUTMENT ;
    PORT
      LAYER met2 ;
      RECT 216.590 1688.700 216.730 1689.120 ;
    END
  END w0_wmask_in[420]
  PIN w0_wmask_in[421]
    DIRECTION INPUT ;
    USE SIGNAL ;
    SHAPE ABUTMENT ;
    PORT
      LAYER met2 ;
      RECT 218.890 1688.700 219.030 1689.120 ;
    END
  END w0_wmask_in[421]
  PIN w0_wmask_in[422]
    DIRECTION INPUT ;
    USE SIGNAL ;
    SHAPE ABUTMENT ;
    PORT
      LAYER met2 ;
      RECT 221.190 1688.700 221.330 1689.120 ;
    END
  END w0_wmask_in[422]
  PIN w0_wmask_in[423]
    DIRECTION INPUT ;
    USE SIGNAL ;
    SHAPE ABUTMENT ;
    PORT
      LAYER met2 ;
      RECT 223.490 1688.700 223.630 1689.120 ;
    END
  END w0_wmask_in[423]
  PIN w0_wmask_in[424]
    DIRECTION INPUT ;
    USE SIGNAL ;
    SHAPE ABUTMENT ;
    PORT
      LAYER met2 ;
      RECT 225.790 1688.700 225.930 1689.120 ;
    END
  END w0_wmask_in[424]
  PIN w0_wmask_in[425]
    DIRECTION INPUT ;
    USE SIGNAL ;
    SHAPE ABUTMENT ;
    PORT
      LAYER met2 ;
      RECT 228.090 1688.700 228.230 1689.120 ;
    END
  END w0_wmask_in[425]
  PIN w0_wmask_in[426]
    DIRECTION INPUT ;
    USE SIGNAL ;
    SHAPE ABUTMENT ;
    PORT
      LAYER met2 ;
      RECT 230.390 1688.700 230.530 1689.120 ;
    END
  END w0_wmask_in[426]
  PIN w0_wmask_in[427]
    DIRECTION INPUT ;
    USE SIGNAL ;
    SHAPE ABUTMENT ;
    PORT
      LAYER met2 ;
      RECT 232.690 1688.700 232.830 1689.120 ;
    END
  END w0_wmask_in[427]
  PIN w0_wmask_in[428]
    DIRECTION INPUT ;
    USE SIGNAL ;
    SHAPE ABUTMENT ;
    PORT
      LAYER met2 ;
      RECT 234.990 1688.700 235.130 1689.120 ;
    END
  END w0_wmask_in[428]
  PIN w0_wmask_in[429]
    DIRECTION INPUT ;
    USE SIGNAL ;
    SHAPE ABUTMENT ;
    PORT
      LAYER met2 ;
      RECT 237.290 1688.700 237.430 1689.120 ;
    END
  END w0_wmask_in[429]
  PIN w0_wmask_in[430]
    DIRECTION INPUT ;
    USE SIGNAL ;
    SHAPE ABUTMENT ;
    PORT
      LAYER met2 ;
      RECT 239.590 1688.700 239.730 1689.120 ;
    END
  END w0_wmask_in[430]
  PIN w0_wmask_in[431]
    DIRECTION INPUT ;
    USE SIGNAL ;
    SHAPE ABUTMENT ;
    PORT
      LAYER met2 ;
      RECT 241.890 1688.700 242.030 1689.120 ;
    END
  END w0_wmask_in[431]
  PIN w0_wmask_in[432]
    DIRECTION INPUT ;
    USE SIGNAL ;
    SHAPE ABUTMENT ;
    PORT
      LAYER met2 ;
      RECT 244.190 1688.700 244.330 1689.120 ;
    END
  END w0_wmask_in[432]
  PIN w0_wmask_in[433]
    DIRECTION INPUT ;
    USE SIGNAL ;
    SHAPE ABUTMENT ;
    PORT
      LAYER met2 ;
      RECT 246.490 1688.700 246.630 1689.120 ;
    END
  END w0_wmask_in[433]
  PIN w0_wmask_in[434]
    DIRECTION INPUT ;
    USE SIGNAL ;
    SHAPE ABUTMENT ;
    PORT
      LAYER met2 ;
      RECT 248.790 1688.700 248.930 1689.120 ;
    END
  END w0_wmask_in[434]
  PIN w0_wmask_in[435]
    DIRECTION INPUT ;
    USE SIGNAL ;
    SHAPE ABUTMENT ;
    PORT
      LAYER met2 ;
      RECT 251.090 1688.700 251.230 1689.120 ;
    END
  END w0_wmask_in[435]
  PIN w0_wmask_in[436]
    DIRECTION INPUT ;
    USE SIGNAL ;
    SHAPE ABUTMENT ;
    PORT
      LAYER met2 ;
      RECT 253.390 1688.700 253.530 1689.120 ;
    END
  END w0_wmask_in[436]
  PIN w0_wmask_in[437]
    DIRECTION INPUT ;
    USE SIGNAL ;
    SHAPE ABUTMENT ;
    PORT
      LAYER met2 ;
      RECT 255.690 1688.700 255.830 1689.120 ;
    END
  END w0_wmask_in[437]
  PIN w0_wmask_in[438]
    DIRECTION INPUT ;
    USE SIGNAL ;
    SHAPE ABUTMENT ;
    PORT
      LAYER met2 ;
      RECT 257.990 1688.700 258.130 1689.120 ;
    END
  END w0_wmask_in[438]
  PIN w0_wmask_in[439]
    DIRECTION INPUT ;
    USE SIGNAL ;
    SHAPE ABUTMENT ;
    PORT
      LAYER met2 ;
      RECT 260.290 1688.700 260.430 1689.120 ;
    END
  END w0_wmask_in[439]
  PIN w0_wmask_in[440]
    DIRECTION INPUT ;
    USE SIGNAL ;
    SHAPE ABUTMENT ;
    PORT
      LAYER met2 ;
      RECT 262.590 1688.700 262.730 1689.120 ;
    END
  END w0_wmask_in[440]
  PIN w0_wmask_in[441]
    DIRECTION INPUT ;
    USE SIGNAL ;
    SHAPE ABUTMENT ;
    PORT
      LAYER met2 ;
      RECT 264.890 1688.700 265.030 1689.120 ;
    END
  END w0_wmask_in[441]
  PIN w0_wmask_in[442]
    DIRECTION INPUT ;
    USE SIGNAL ;
    SHAPE ABUTMENT ;
    PORT
      LAYER met2 ;
      RECT 267.190 1688.700 267.330 1689.120 ;
    END
  END w0_wmask_in[442]
  PIN w0_wmask_in[443]
    DIRECTION INPUT ;
    USE SIGNAL ;
    SHAPE ABUTMENT ;
    PORT
      LAYER met2 ;
      RECT 269.490 1688.700 269.630 1689.120 ;
    END
  END w0_wmask_in[443]
  PIN w0_wmask_in[444]
    DIRECTION INPUT ;
    USE SIGNAL ;
    SHAPE ABUTMENT ;
    PORT
      LAYER met2 ;
      RECT 271.790 1688.700 271.930 1689.120 ;
    END
  END w0_wmask_in[444]
  PIN w0_wmask_in[445]
    DIRECTION INPUT ;
    USE SIGNAL ;
    SHAPE ABUTMENT ;
    PORT
      LAYER met2 ;
      RECT 274.090 1688.700 274.230 1689.120 ;
    END
  END w0_wmask_in[445]
  PIN w0_wmask_in[446]
    DIRECTION INPUT ;
    USE SIGNAL ;
    SHAPE ABUTMENT ;
    PORT
      LAYER met2 ;
      RECT 276.390 1688.700 276.530 1689.120 ;
    END
  END w0_wmask_in[446]
  PIN w0_wmask_in[447]
    DIRECTION INPUT ;
    USE SIGNAL ;
    SHAPE ABUTMENT ;
    PORT
      LAYER met2 ;
      RECT 278.690 1688.700 278.830 1689.120 ;
    END
  END w0_wmask_in[447]
  PIN w0_wmask_in[448]
    DIRECTION INPUT ;
    USE SIGNAL ;
    SHAPE ABUTMENT ;
    PORT
      LAYER met2 ;
      RECT 280.990 1688.700 281.130 1689.120 ;
    END
  END w0_wmask_in[448]
  PIN w0_wmask_in[449]
    DIRECTION INPUT ;
    USE SIGNAL ;
    SHAPE ABUTMENT ;
    PORT
      LAYER met2 ;
      RECT 283.290 1688.700 283.430 1689.120 ;
    END
  END w0_wmask_in[449]
  PIN w0_wmask_in[450]
    DIRECTION INPUT ;
    USE SIGNAL ;
    SHAPE ABUTMENT ;
    PORT
      LAYER met2 ;
      RECT 285.590 1688.700 285.730 1689.120 ;
    END
  END w0_wmask_in[450]
  PIN w0_wmask_in[451]
    DIRECTION INPUT ;
    USE SIGNAL ;
    SHAPE ABUTMENT ;
    PORT
      LAYER met2 ;
      RECT 287.890 1688.700 288.030 1689.120 ;
    END
  END w0_wmask_in[451]
  PIN w0_wmask_in[452]
    DIRECTION INPUT ;
    USE SIGNAL ;
    SHAPE ABUTMENT ;
    PORT
      LAYER met2 ;
      RECT 290.190 1688.700 290.330 1689.120 ;
    END
  END w0_wmask_in[452]
  PIN w0_wmask_in[453]
    DIRECTION INPUT ;
    USE SIGNAL ;
    SHAPE ABUTMENT ;
    PORT
      LAYER met2 ;
      RECT 292.490 1688.700 292.630 1689.120 ;
    END
  END w0_wmask_in[453]
  PIN w0_wmask_in[454]
    DIRECTION INPUT ;
    USE SIGNAL ;
    SHAPE ABUTMENT ;
    PORT
      LAYER met2 ;
      RECT 294.790 1688.700 294.930 1689.120 ;
    END
  END w0_wmask_in[454]
  PIN w0_wmask_in[455]
    DIRECTION INPUT ;
    USE SIGNAL ;
    SHAPE ABUTMENT ;
    PORT
      LAYER met2 ;
      RECT 297.090 1688.700 297.230 1689.120 ;
    END
  END w0_wmask_in[455]
  PIN w0_wmask_in[456]
    DIRECTION INPUT ;
    USE SIGNAL ;
    SHAPE ABUTMENT ;
    PORT
      LAYER met2 ;
      RECT 299.390 1688.700 299.530 1689.120 ;
    END
  END w0_wmask_in[456]
  PIN w0_wmask_in[457]
    DIRECTION INPUT ;
    USE SIGNAL ;
    SHAPE ABUTMENT ;
    PORT
      LAYER met2 ;
      RECT 301.690 1688.700 301.830 1689.120 ;
    END
  END w0_wmask_in[457]
  PIN w0_wmask_in[458]
    DIRECTION INPUT ;
    USE SIGNAL ;
    SHAPE ABUTMENT ;
    PORT
      LAYER met2 ;
      RECT 303.990 1688.700 304.130 1689.120 ;
    END
  END w0_wmask_in[458]
  PIN w0_wmask_in[459]
    DIRECTION INPUT ;
    USE SIGNAL ;
    SHAPE ABUTMENT ;
    PORT
      LAYER met2 ;
      RECT 306.290 1688.700 306.430 1689.120 ;
    END
  END w0_wmask_in[459]
  PIN w0_wmask_in[460]
    DIRECTION INPUT ;
    USE SIGNAL ;
    SHAPE ABUTMENT ;
    PORT
      LAYER met2 ;
      RECT 308.590 1688.700 308.730 1689.120 ;
    END
  END w0_wmask_in[460]
  PIN w0_wmask_in[461]
    DIRECTION INPUT ;
    USE SIGNAL ;
    SHAPE ABUTMENT ;
    PORT
      LAYER met2 ;
      RECT 310.890 1688.700 311.030 1689.120 ;
    END
  END w0_wmask_in[461]
  PIN w0_wmask_in[462]
    DIRECTION INPUT ;
    USE SIGNAL ;
    SHAPE ABUTMENT ;
    PORT
      LAYER met2 ;
      RECT 313.190 1688.700 313.330 1689.120 ;
    END
  END w0_wmask_in[462]
  PIN w0_wmask_in[463]
    DIRECTION INPUT ;
    USE SIGNAL ;
    SHAPE ABUTMENT ;
    PORT
      LAYER met2 ;
      RECT 315.490 1688.700 315.630 1689.120 ;
    END
  END w0_wmask_in[463]
  PIN w0_wmask_in[464]
    DIRECTION INPUT ;
    USE SIGNAL ;
    SHAPE ABUTMENT ;
    PORT
      LAYER met2 ;
      RECT 317.790 1688.700 317.930 1689.120 ;
    END
  END w0_wmask_in[464]
  PIN w0_wmask_in[465]
    DIRECTION INPUT ;
    USE SIGNAL ;
    SHAPE ABUTMENT ;
    PORT
      LAYER met2 ;
      RECT 320.090 1688.700 320.230 1689.120 ;
    END
  END w0_wmask_in[465]
  PIN w0_wmask_in[466]
    DIRECTION INPUT ;
    USE SIGNAL ;
    SHAPE ABUTMENT ;
    PORT
      LAYER met2 ;
      RECT 322.390 1688.700 322.530 1689.120 ;
    END
  END w0_wmask_in[466]
  PIN w0_wmask_in[467]
    DIRECTION INPUT ;
    USE SIGNAL ;
    SHAPE ABUTMENT ;
    PORT
      LAYER met2 ;
      RECT 324.690 1688.700 324.830 1689.120 ;
    END
  END w0_wmask_in[467]
  PIN w0_wmask_in[468]
    DIRECTION INPUT ;
    USE SIGNAL ;
    SHAPE ABUTMENT ;
    PORT
      LAYER met2 ;
      RECT 326.990 1688.700 327.130 1689.120 ;
    END
  END w0_wmask_in[468]
  PIN w0_wmask_in[469]
    DIRECTION INPUT ;
    USE SIGNAL ;
    SHAPE ABUTMENT ;
    PORT
      LAYER met2 ;
      RECT 329.290 1688.700 329.430 1689.120 ;
    END
  END w0_wmask_in[469]
  PIN w0_wmask_in[470]
    DIRECTION INPUT ;
    USE SIGNAL ;
    SHAPE ABUTMENT ;
    PORT
      LAYER met2 ;
      RECT 331.590 1688.700 331.730 1689.120 ;
    END
  END w0_wmask_in[470]
  PIN w0_wmask_in[471]
    DIRECTION INPUT ;
    USE SIGNAL ;
    SHAPE ABUTMENT ;
    PORT
      LAYER met2 ;
      RECT 333.890 1688.700 334.030 1689.120 ;
    END
  END w0_wmask_in[471]
  PIN w0_wmask_in[472]
    DIRECTION INPUT ;
    USE SIGNAL ;
    SHAPE ABUTMENT ;
    PORT
      LAYER met2 ;
      RECT 336.190 1688.700 336.330 1689.120 ;
    END
  END w0_wmask_in[472]
  PIN w0_wmask_in[473]
    DIRECTION INPUT ;
    USE SIGNAL ;
    SHAPE ABUTMENT ;
    PORT
      LAYER met2 ;
      RECT 338.490 1688.700 338.630 1689.120 ;
    END
  END w0_wmask_in[473]
  PIN w0_wmask_in[474]
    DIRECTION INPUT ;
    USE SIGNAL ;
    SHAPE ABUTMENT ;
    PORT
      LAYER met2 ;
      RECT 340.790 1688.700 340.930 1689.120 ;
    END
  END w0_wmask_in[474]
  PIN w0_wmask_in[475]
    DIRECTION INPUT ;
    USE SIGNAL ;
    SHAPE ABUTMENT ;
    PORT
      LAYER met2 ;
      RECT 343.090 1688.700 343.230 1689.120 ;
    END
  END w0_wmask_in[475]
  PIN w0_wmask_in[476]
    DIRECTION INPUT ;
    USE SIGNAL ;
    SHAPE ABUTMENT ;
    PORT
      LAYER met2 ;
      RECT 345.390 1688.700 345.530 1689.120 ;
    END
  END w0_wmask_in[476]
  PIN w0_wmask_in[477]
    DIRECTION INPUT ;
    USE SIGNAL ;
    SHAPE ABUTMENT ;
    PORT
      LAYER met2 ;
      RECT 347.690 1688.700 347.830 1689.120 ;
    END
  END w0_wmask_in[477]
  PIN w0_wmask_in[478]
    DIRECTION INPUT ;
    USE SIGNAL ;
    SHAPE ABUTMENT ;
    PORT
      LAYER met2 ;
      RECT 349.990 1688.700 350.130 1689.120 ;
    END
  END w0_wmask_in[478]
  PIN w0_wmask_in[479]
    DIRECTION INPUT ;
    USE SIGNAL ;
    SHAPE ABUTMENT ;
    PORT
      LAYER met2 ;
      RECT 352.290 1688.700 352.430 1689.120 ;
    END
  END w0_wmask_in[479]
  PIN w0_wmask_in[480]
    DIRECTION INPUT ;
    USE SIGNAL ;
    SHAPE ABUTMENT ;
    PORT
      LAYER met2 ;
      RECT 354.590 1688.700 354.730 1689.120 ;
    END
  END w0_wmask_in[480]
  PIN w0_wmask_in[481]
    DIRECTION INPUT ;
    USE SIGNAL ;
    SHAPE ABUTMENT ;
    PORT
      LAYER met2 ;
      RECT 356.890 1688.700 357.030 1689.120 ;
    END
  END w0_wmask_in[481]
  PIN w0_wmask_in[482]
    DIRECTION INPUT ;
    USE SIGNAL ;
    SHAPE ABUTMENT ;
    PORT
      LAYER met2 ;
      RECT 359.190 1688.700 359.330 1689.120 ;
    END
  END w0_wmask_in[482]
  PIN w0_wmask_in[483]
    DIRECTION INPUT ;
    USE SIGNAL ;
    SHAPE ABUTMENT ;
    PORT
      LAYER met2 ;
      RECT 361.490 1688.700 361.630 1689.120 ;
    END
  END w0_wmask_in[483]
  PIN w0_wmask_in[484]
    DIRECTION INPUT ;
    USE SIGNAL ;
    SHAPE ABUTMENT ;
    PORT
      LAYER met2 ;
      RECT 363.790 1688.700 363.930 1689.120 ;
    END
  END w0_wmask_in[484]
  PIN w0_wmask_in[485]
    DIRECTION INPUT ;
    USE SIGNAL ;
    SHAPE ABUTMENT ;
    PORT
      LAYER met2 ;
      RECT 366.090 1688.700 366.230 1689.120 ;
    END
  END w0_wmask_in[485]
  PIN w0_wmask_in[486]
    DIRECTION INPUT ;
    USE SIGNAL ;
    SHAPE ABUTMENT ;
    PORT
      LAYER met2 ;
      RECT 368.390 1688.700 368.530 1689.120 ;
    END
  END w0_wmask_in[486]
  PIN w0_wmask_in[487]
    DIRECTION INPUT ;
    USE SIGNAL ;
    SHAPE ABUTMENT ;
    PORT
      LAYER met2 ;
      RECT 370.690 1688.700 370.830 1689.120 ;
    END
  END w0_wmask_in[487]
  PIN w0_wmask_in[488]
    DIRECTION INPUT ;
    USE SIGNAL ;
    SHAPE ABUTMENT ;
    PORT
      LAYER met2 ;
      RECT 372.990 1688.700 373.130 1689.120 ;
    END
  END w0_wmask_in[488]
  PIN w0_wmask_in[489]
    DIRECTION INPUT ;
    USE SIGNAL ;
    SHAPE ABUTMENT ;
    PORT
      LAYER met2 ;
      RECT 375.290 1688.700 375.430 1689.120 ;
    END
  END w0_wmask_in[489]
  PIN w0_wmask_in[490]
    DIRECTION INPUT ;
    USE SIGNAL ;
    SHAPE ABUTMENT ;
    PORT
      LAYER met2 ;
      RECT 377.590 1688.700 377.730 1689.120 ;
    END
  END w0_wmask_in[490]
  PIN w0_wmask_in[491]
    DIRECTION INPUT ;
    USE SIGNAL ;
    SHAPE ABUTMENT ;
    PORT
      LAYER met2 ;
      RECT 379.890 1688.700 380.030 1689.120 ;
    END
  END w0_wmask_in[491]
  PIN w0_wmask_in[492]
    DIRECTION INPUT ;
    USE SIGNAL ;
    SHAPE ABUTMENT ;
    PORT
      LAYER met2 ;
      RECT 382.190 1688.700 382.330 1689.120 ;
    END
  END w0_wmask_in[492]
  PIN w0_wmask_in[493]
    DIRECTION INPUT ;
    USE SIGNAL ;
    SHAPE ABUTMENT ;
    PORT
      LAYER met2 ;
      RECT 384.490 1688.700 384.630 1689.120 ;
    END
  END w0_wmask_in[493]
  PIN w0_wmask_in[494]
    DIRECTION INPUT ;
    USE SIGNAL ;
    SHAPE ABUTMENT ;
    PORT
      LAYER met2 ;
      RECT 386.790 1688.700 386.930 1689.120 ;
    END
  END w0_wmask_in[494]
  PIN w0_wmask_in[495]
    DIRECTION INPUT ;
    USE SIGNAL ;
    SHAPE ABUTMENT ;
    PORT
      LAYER met2 ;
      RECT 389.090 1688.700 389.230 1689.120 ;
    END
  END w0_wmask_in[495]
  PIN w0_wmask_in[496]
    DIRECTION INPUT ;
    USE SIGNAL ;
    SHAPE ABUTMENT ;
    PORT
      LAYER met2 ;
      RECT 391.390 1688.700 391.530 1689.120 ;
    END
  END w0_wmask_in[496]
  PIN w0_wmask_in[497]
    DIRECTION INPUT ;
    USE SIGNAL ;
    SHAPE ABUTMENT ;
    PORT
      LAYER met2 ;
      RECT 393.690 1688.700 393.830 1689.120 ;
    END
  END w0_wmask_in[497]
  PIN w0_wmask_in[498]
    DIRECTION INPUT ;
    USE SIGNAL ;
    SHAPE ABUTMENT ;
    PORT
      LAYER met2 ;
      RECT 395.990 1688.700 396.130 1689.120 ;
    END
  END w0_wmask_in[498]
  PIN w0_wmask_in[499]
    DIRECTION INPUT ;
    USE SIGNAL ;
    SHAPE ABUTMENT ;
    PORT
      LAYER met2 ;
      RECT 398.290 1688.700 398.430 1689.120 ;
    END
  END w0_wmask_in[499]
  PIN w0_wmask_in[500]
    DIRECTION INPUT ;
    USE SIGNAL ;
    SHAPE ABUTMENT ;
    PORT
      LAYER met2 ;
      RECT 400.590 1688.700 400.730 1689.120 ;
    END
  END w0_wmask_in[500]
  PIN w0_wmask_in[501]
    DIRECTION INPUT ;
    USE SIGNAL ;
    SHAPE ABUTMENT ;
    PORT
      LAYER met2 ;
      RECT 402.890 1688.700 403.030 1689.120 ;
    END
  END w0_wmask_in[501]
  PIN w0_wmask_in[502]
    DIRECTION INPUT ;
    USE SIGNAL ;
    SHAPE ABUTMENT ;
    PORT
      LAYER met2 ;
      RECT 405.190 1688.700 405.330 1689.120 ;
    END
  END w0_wmask_in[502]
  PIN w0_wmask_in[503]
    DIRECTION INPUT ;
    USE SIGNAL ;
    SHAPE ABUTMENT ;
    PORT
      LAYER met2 ;
      RECT 407.490 1688.700 407.630 1689.120 ;
    END
  END w0_wmask_in[503]
  PIN w0_wmask_in[504]
    DIRECTION INPUT ;
    USE SIGNAL ;
    SHAPE ABUTMENT ;
    PORT
      LAYER met2 ;
      RECT 409.790 1688.700 409.930 1689.120 ;
    END
  END w0_wmask_in[504]
  PIN w0_wmask_in[505]
    DIRECTION INPUT ;
    USE SIGNAL ;
    SHAPE ABUTMENT ;
    PORT
      LAYER met2 ;
      RECT 412.090 1688.700 412.230 1689.120 ;
    END
  END w0_wmask_in[505]
  PIN w0_wmask_in[506]
    DIRECTION INPUT ;
    USE SIGNAL ;
    SHAPE ABUTMENT ;
    PORT
      LAYER met2 ;
      RECT 414.390 1688.700 414.530 1689.120 ;
    END
  END w0_wmask_in[506]
  PIN w0_wmask_in[507]
    DIRECTION INPUT ;
    USE SIGNAL ;
    SHAPE ABUTMENT ;
    PORT
      LAYER met2 ;
      RECT 416.690 1688.700 416.830 1689.120 ;
    END
  END w0_wmask_in[507]
  PIN w0_wmask_in[508]
    DIRECTION INPUT ;
    USE SIGNAL ;
    SHAPE ABUTMENT ;
    PORT
      LAYER met2 ;
      RECT 418.990 1688.700 419.130 1689.120 ;
    END
  END w0_wmask_in[508]
  PIN w0_wmask_in[509]
    DIRECTION INPUT ;
    USE SIGNAL ;
    SHAPE ABUTMENT ;
    PORT
      LAYER met2 ;
      RECT 421.290 1688.700 421.430 1689.120 ;
    END
  END w0_wmask_in[509]
  PIN w0_wmask_in[510]
    DIRECTION INPUT ;
    USE SIGNAL ;
    SHAPE ABUTMENT ;
    PORT
      LAYER met2 ;
      RECT 423.590 1688.700 423.730 1689.120 ;
    END
  END w0_wmask_in[510]
  PIN w0_wmask_in[511]
    DIRECTION INPUT ;
    USE SIGNAL ;
    SHAPE ABUTMENT ;
    PORT
      LAYER met2 ;
      RECT 425.890 1688.700 426.030 1689.120 ;
    END
  END w0_wmask_in[511]
  PIN w0_wmask_in[512]
    DIRECTION INPUT ;
    USE SIGNAL ;
    SHAPE ABUTMENT ;
    PORT
      LAYER met2 ;
      RECT 428.190 1688.700 428.330 1689.120 ;
    END
  END w0_wmask_in[512]
  PIN w0_wmask_in[513]
    DIRECTION INPUT ;
    USE SIGNAL ;
    SHAPE ABUTMENT ;
    PORT
      LAYER met2 ;
      RECT 430.490 1688.700 430.630 1689.120 ;
    END
  END w0_wmask_in[513]
  PIN w0_wmask_in[514]
    DIRECTION INPUT ;
    USE SIGNAL ;
    SHAPE ABUTMENT ;
    PORT
      LAYER met2 ;
      RECT 432.790 1688.700 432.930 1689.120 ;
    END
  END w0_wmask_in[514]
  PIN w0_wmask_in[515]
    DIRECTION INPUT ;
    USE SIGNAL ;
    SHAPE ABUTMENT ;
    PORT
      LAYER met2 ;
      RECT 435.090 1688.700 435.230 1689.120 ;
    END
  END w0_wmask_in[515]
  PIN w0_wmask_in[516]
    DIRECTION INPUT ;
    USE SIGNAL ;
    SHAPE ABUTMENT ;
    PORT
      LAYER met2 ;
      RECT 437.390 1688.700 437.530 1689.120 ;
    END
  END w0_wmask_in[516]
  PIN w0_wmask_in[517]
    DIRECTION INPUT ;
    USE SIGNAL ;
    SHAPE ABUTMENT ;
    PORT
      LAYER met2 ;
      RECT 439.690 1688.700 439.830 1689.120 ;
    END
  END w0_wmask_in[517]
  PIN w0_wmask_in[518]
    DIRECTION INPUT ;
    USE SIGNAL ;
    SHAPE ABUTMENT ;
    PORT
      LAYER met2 ;
      RECT 441.990 1688.700 442.130 1689.120 ;
    END
  END w0_wmask_in[518]
  PIN w0_wmask_in[519]
    DIRECTION INPUT ;
    USE SIGNAL ;
    SHAPE ABUTMENT ;
    PORT
      LAYER met2 ;
      RECT 444.290 1688.700 444.430 1689.120 ;
    END
  END w0_wmask_in[519]
  PIN w0_wmask_in[520]
    DIRECTION INPUT ;
    USE SIGNAL ;
    SHAPE ABUTMENT ;
    PORT
      LAYER met2 ;
      RECT 446.590 1688.700 446.730 1689.120 ;
    END
  END w0_wmask_in[520]
  PIN w0_wmask_in[521]
    DIRECTION INPUT ;
    USE SIGNAL ;
    SHAPE ABUTMENT ;
    PORT
      LAYER met2 ;
      RECT 448.890 1688.700 449.030 1689.120 ;
    END
  END w0_wmask_in[521]
  PIN w0_wmask_in[522]
    DIRECTION INPUT ;
    USE SIGNAL ;
    SHAPE ABUTMENT ;
    PORT
      LAYER met2 ;
      RECT 451.190 1688.700 451.330 1689.120 ;
    END
  END w0_wmask_in[522]
  PIN w0_wmask_in[523]
    DIRECTION INPUT ;
    USE SIGNAL ;
    SHAPE ABUTMENT ;
    PORT
      LAYER met2 ;
      RECT 453.490 1688.700 453.630 1689.120 ;
    END
  END w0_wmask_in[523]
  PIN w0_wmask_in[524]
    DIRECTION INPUT ;
    USE SIGNAL ;
    SHAPE ABUTMENT ;
    PORT
      LAYER met2 ;
      RECT 455.790 1688.700 455.930 1689.120 ;
    END
  END w0_wmask_in[524]
  PIN w0_wmask_in[525]
    DIRECTION INPUT ;
    USE SIGNAL ;
    SHAPE ABUTMENT ;
    PORT
      LAYER met2 ;
      RECT 458.090 1688.700 458.230 1689.120 ;
    END
  END w0_wmask_in[525]
  PIN w0_wmask_in[526]
    DIRECTION INPUT ;
    USE SIGNAL ;
    SHAPE ABUTMENT ;
    PORT
      LAYER met2 ;
      RECT 460.390 1688.700 460.530 1689.120 ;
    END
  END w0_wmask_in[526]
  PIN w0_wmask_in[527]
    DIRECTION INPUT ;
    USE SIGNAL ;
    SHAPE ABUTMENT ;
    PORT
      LAYER met2 ;
      RECT 462.690 1688.700 462.830 1689.120 ;
    END
  END w0_wmask_in[527]
  PIN w0_wmask_in[528]
    DIRECTION INPUT ;
    USE SIGNAL ;
    SHAPE ABUTMENT ;
    PORT
      LAYER met2 ;
      RECT 464.990 1688.700 465.130 1689.120 ;
    END
  END w0_wmask_in[528]
  PIN w0_wmask_in[529]
    DIRECTION INPUT ;
    USE SIGNAL ;
    SHAPE ABUTMENT ;
    PORT
      LAYER met2 ;
      RECT 467.290 1688.700 467.430 1689.120 ;
    END
  END w0_wmask_in[529]
  PIN w0_wmask_in[530]
    DIRECTION INPUT ;
    USE SIGNAL ;
    SHAPE ABUTMENT ;
    PORT
      LAYER met2 ;
      RECT 469.590 1688.700 469.730 1689.120 ;
    END
  END w0_wmask_in[530]
  PIN w0_wmask_in[531]
    DIRECTION INPUT ;
    USE SIGNAL ;
    SHAPE ABUTMENT ;
    PORT
      LAYER met2 ;
      RECT 471.890 1688.700 472.030 1689.120 ;
    END
  END w0_wmask_in[531]
  PIN w0_wmask_in[532]
    DIRECTION INPUT ;
    USE SIGNAL ;
    SHAPE ABUTMENT ;
    PORT
      LAYER met2 ;
      RECT 474.190 1688.700 474.330 1689.120 ;
    END
  END w0_wmask_in[532]
  PIN w0_wmask_in[533]
    DIRECTION INPUT ;
    USE SIGNAL ;
    SHAPE ABUTMENT ;
    PORT
      LAYER met2 ;
      RECT 476.490 1688.700 476.630 1689.120 ;
    END
  END w0_wmask_in[533]
  PIN w0_wmask_in[534]
    DIRECTION INPUT ;
    USE SIGNAL ;
    SHAPE ABUTMENT ;
    PORT
      LAYER met2 ;
      RECT 478.790 1688.700 478.930 1689.120 ;
    END
  END w0_wmask_in[534]
  PIN w0_wmask_in[535]
    DIRECTION INPUT ;
    USE SIGNAL ;
    SHAPE ABUTMENT ;
    PORT
      LAYER met2 ;
      RECT 481.090 1688.700 481.230 1689.120 ;
    END
  END w0_wmask_in[535]
  PIN w0_wmask_in[536]
    DIRECTION INPUT ;
    USE SIGNAL ;
    SHAPE ABUTMENT ;
    PORT
      LAYER met2 ;
      RECT 483.390 1688.700 483.530 1689.120 ;
    END
  END w0_wmask_in[536]
  PIN w0_wmask_in[537]
    DIRECTION INPUT ;
    USE SIGNAL ;
    SHAPE ABUTMENT ;
    PORT
      LAYER met2 ;
      RECT 485.690 1688.700 485.830 1689.120 ;
    END
  END w0_wmask_in[537]
  PIN w0_wmask_in[538]
    DIRECTION INPUT ;
    USE SIGNAL ;
    SHAPE ABUTMENT ;
    PORT
      LAYER met2 ;
      RECT 487.990 1688.700 488.130 1689.120 ;
    END
  END w0_wmask_in[538]
  PIN w0_wmask_in[539]
    DIRECTION INPUT ;
    USE SIGNAL ;
    SHAPE ABUTMENT ;
    PORT
      LAYER met2 ;
      RECT 490.290 1688.700 490.430 1689.120 ;
    END
  END w0_wmask_in[539]
  PIN w0_wmask_in[540]
    DIRECTION INPUT ;
    USE SIGNAL ;
    SHAPE ABUTMENT ;
    PORT
      LAYER met2 ;
      RECT 492.590 1688.700 492.730 1689.120 ;
    END
  END w0_wmask_in[540]
  PIN w0_wmask_in[541]
    DIRECTION INPUT ;
    USE SIGNAL ;
    SHAPE ABUTMENT ;
    PORT
      LAYER met2 ;
      RECT 494.890 1688.700 495.030 1689.120 ;
    END
  END w0_wmask_in[541]
  PIN w0_wmask_in[542]
    DIRECTION INPUT ;
    USE SIGNAL ;
    SHAPE ABUTMENT ;
    PORT
      LAYER met2 ;
      RECT 497.190 1688.700 497.330 1689.120 ;
    END
  END w0_wmask_in[542]
  PIN w0_wmask_in[543]
    DIRECTION INPUT ;
    USE SIGNAL ;
    SHAPE ABUTMENT ;
    PORT
      LAYER met2 ;
      RECT 499.490 1688.700 499.630 1689.120 ;
    END
  END w0_wmask_in[543]
  PIN w0_wmask_in[544]
    DIRECTION INPUT ;
    USE SIGNAL ;
    SHAPE ABUTMENT ;
    PORT
      LAYER met2 ;
      RECT 501.790 1688.700 501.930 1689.120 ;
    END
  END w0_wmask_in[544]
  PIN w0_wmask_in[545]
    DIRECTION INPUT ;
    USE SIGNAL ;
    SHAPE ABUTMENT ;
    PORT
      LAYER met2 ;
      RECT 504.090 1688.700 504.230 1689.120 ;
    END
  END w0_wmask_in[545]
  PIN w0_wmask_in[546]
    DIRECTION INPUT ;
    USE SIGNAL ;
    SHAPE ABUTMENT ;
    PORT
      LAYER met2 ;
      RECT 506.390 1688.700 506.530 1689.120 ;
    END
  END w0_wmask_in[546]
  PIN w0_wmask_in[547]
    DIRECTION INPUT ;
    USE SIGNAL ;
    SHAPE ABUTMENT ;
    PORT
      LAYER met2 ;
      RECT 508.690 1688.700 508.830 1689.120 ;
    END
  END w0_wmask_in[547]
  PIN w0_wmask_in[548]
    DIRECTION INPUT ;
    USE SIGNAL ;
    SHAPE ABUTMENT ;
    PORT
      LAYER met2 ;
      RECT 510.990 1688.700 511.130 1689.120 ;
    END
  END w0_wmask_in[548]
  PIN w0_wmask_in[549]
    DIRECTION INPUT ;
    USE SIGNAL ;
    SHAPE ABUTMENT ;
    PORT
      LAYER met2 ;
      RECT 513.290 1688.700 513.430 1689.120 ;
    END
  END w0_wmask_in[549]
  PIN w0_wmask_in[550]
    DIRECTION INPUT ;
    USE SIGNAL ;
    SHAPE ABUTMENT ;
    PORT
      LAYER met2 ;
      RECT 515.590 1688.700 515.730 1689.120 ;
    END
  END w0_wmask_in[550]
  PIN w0_wmask_in[551]
    DIRECTION INPUT ;
    USE SIGNAL ;
    SHAPE ABUTMENT ;
    PORT
      LAYER met2 ;
      RECT 517.890 1688.700 518.030 1689.120 ;
    END
  END w0_wmask_in[551]
  PIN w0_wmask_in[552]
    DIRECTION INPUT ;
    USE SIGNAL ;
    SHAPE ABUTMENT ;
    PORT
      LAYER met2 ;
      RECT 520.190 1688.700 520.330 1689.120 ;
    END
  END w0_wmask_in[552]
  PIN w0_wmask_in[553]
    DIRECTION INPUT ;
    USE SIGNAL ;
    SHAPE ABUTMENT ;
    PORT
      LAYER met2 ;
      RECT 522.490 1688.700 522.630 1689.120 ;
    END
  END w0_wmask_in[553]
  PIN w0_wmask_in[554]
    DIRECTION INPUT ;
    USE SIGNAL ;
    SHAPE ABUTMENT ;
    PORT
      LAYER met2 ;
      RECT 524.790 1688.700 524.930 1689.120 ;
    END
  END w0_wmask_in[554]
  PIN w0_wmask_in[555]
    DIRECTION INPUT ;
    USE SIGNAL ;
    SHAPE ABUTMENT ;
    PORT
      LAYER met2 ;
      RECT 527.090 1688.700 527.230 1689.120 ;
    END
  END w0_wmask_in[555]
  PIN w0_wmask_in[556]
    DIRECTION INPUT ;
    USE SIGNAL ;
    SHAPE ABUTMENT ;
    PORT
      LAYER met2 ;
      RECT 529.390 1688.700 529.530 1689.120 ;
    END
  END w0_wmask_in[556]
  PIN w0_wmask_in[557]
    DIRECTION INPUT ;
    USE SIGNAL ;
    SHAPE ABUTMENT ;
    PORT
      LAYER met2 ;
      RECT 531.690 1688.700 531.830 1689.120 ;
    END
  END w0_wmask_in[557]
  PIN w0_wmask_in[558]
    DIRECTION INPUT ;
    USE SIGNAL ;
    SHAPE ABUTMENT ;
    PORT
      LAYER met2 ;
      RECT 533.990 1688.700 534.130 1689.120 ;
    END
  END w0_wmask_in[558]
  PIN w0_wmask_in[559]
    DIRECTION INPUT ;
    USE SIGNAL ;
    SHAPE ABUTMENT ;
    PORT
      LAYER met2 ;
      RECT 536.290 1688.700 536.430 1689.120 ;
    END
  END w0_wmask_in[559]
  PIN w0_wmask_in[560]
    DIRECTION INPUT ;
    USE SIGNAL ;
    SHAPE ABUTMENT ;
    PORT
      LAYER met2 ;
      RECT 538.590 1688.700 538.730 1689.120 ;
    END
  END w0_wmask_in[560]
  PIN w0_wmask_in[561]
    DIRECTION INPUT ;
    USE SIGNAL ;
    SHAPE ABUTMENT ;
    PORT
      LAYER met2 ;
      RECT 540.890 1688.700 541.030 1689.120 ;
    END
  END w0_wmask_in[561]
  PIN w0_wmask_in[562]
    DIRECTION INPUT ;
    USE SIGNAL ;
    SHAPE ABUTMENT ;
    PORT
      LAYER met2 ;
      RECT 543.190 1688.700 543.330 1689.120 ;
    END
  END w0_wmask_in[562]
  PIN w0_wmask_in[563]
    DIRECTION INPUT ;
    USE SIGNAL ;
    SHAPE ABUTMENT ;
    PORT
      LAYER met2 ;
      RECT 545.490 1688.700 545.630 1689.120 ;
    END
  END w0_wmask_in[563]
  PIN w0_wmask_in[564]
    DIRECTION INPUT ;
    USE SIGNAL ;
    SHAPE ABUTMENT ;
    PORT
      LAYER met2 ;
      RECT 547.790 1688.700 547.930 1689.120 ;
    END
  END w0_wmask_in[564]
  PIN w0_wmask_in[565]
    DIRECTION INPUT ;
    USE SIGNAL ;
    SHAPE ABUTMENT ;
    PORT
      LAYER met2 ;
      RECT 550.090 1688.700 550.230 1689.120 ;
    END
  END w0_wmask_in[565]
  PIN w0_wmask_in[566]
    DIRECTION INPUT ;
    USE SIGNAL ;
    SHAPE ABUTMENT ;
    PORT
      LAYER met2 ;
      RECT 552.390 1688.700 552.530 1689.120 ;
    END
  END w0_wmask_in[566]
  PIN w0_wmask_in[567]
    DIRECTION INPUT ;
    USE SIGNAL ;
    SHAPE ABUTMENT ;
    PORT
      LAYER met2 ;
      RECT 554.690 1688.700 554.830 1689.120 ;
    END
  END w0_wmask_in[567]
  PIN w0_wmask_in[568]
    DIRECTION INPUT ;
    USE SIGNAL ;
    SHAPE ABUTMENT ;
    PORT
      LAYER met2 ;
      RECT 556.990 1688.700 557.130 1689.120 ;
    END
  END w0_wmask_in[568]
  PIN w0_wmask_in[569]
    DIRECTION INPUT ;
    USE SIGNAL ;
    SHAPE ABUTMENT ;
    PORT
      LAYER met2 ;
      RECT 559.290 1688.700 559.430 1689.120 ;
    END
  END w0_wmask_in[569]
  PIN w0_wmask_in[570]
    DIRECTION INPUT ;
    USE SIGNAL ;
    SHAPE ABUTMENT ;
    PORT
      LAYER met2 ;
      RECT 561.590 1688.700 561.730 1689.120 ;
    END
  END w0_wmask_in[570]
  PIN w0_wmask_in[571]
    DIRECTION INPUT ;
    USE SIGNAL ;
    SHAPE ABUTMENT ;
    PORT
      LAYER met2 ;
      RECT 563.890 1688.700 564.030 1689.120 ;
    END
  END w0_wmask_in[571]
  PIN w0_wmask_in[572]
    DIRECTION INPUT ;
    USE SIGNAL ;
    SHAPE ABUTMENT ;
    PORT
      LAYER met2 ;
      RECT 566.190 1688.700 566.330 1689.120 ;
    END
  END w0_wmask_in[572]
  PIN w0_wmask_in[573]
    DIRECTION INPUT ;
    USE SIGNAL ;
    SHAPE ABUTMENT ;
    PORT
      LAYER met2 ;
      RECT 568.490 1688.700 568.630 1689.120 ;
    END
  END w0_wmask_in[573]
  PIN w0_wmask_in[574]
    DIRECTION INPUT ;
    USE SIGNAL ;
    SHAPE ABUTMENT ;
    PORT
      LAYER met2 ;
      RECT 570.790 1688.700 570.930 1689.120 ;
    END
  END w0_wmask_in[574]
  PIN w0_wmask_in[575]
    DIRECTION INPUT ;
    USE SIGNAL ;
    SHAPE ABUTMENT ;
    PORT
      LAYER met2 ;
      RECT 573.090 1688.700 573.230 1689.120 ;
    END
  END w0_wmask_in[575]
  PIN w0_wmask_in[576]
    DIRECTION INPUT ;
    USE SIGNAL ;
    SHAPE ABUTMENT ;
    PORT
      LAYER met2 ;
      RECT 575.390 1688.700 575.530 1689.120 ;
    END
  END w0_wmask_in[576]
  PIN w0_wmask_in[577]
    DIRECTION INPUT ;
    USE SIGNAL ;
    SHAPE ABUTMENT ;
    PORT
      LAYER met2 ;
      RECT 577.690 1688.700 577.830 1689.120 ;
    END
  END w0_wmask_in[577]
  PIN w0_wmask_in[578]
    DIRECTION INPUT ;
    USE SIGNAL ;
    SHAPE ABUTMENT ;
    PORT
      LAYER met2 ;
      RECT 579.990 1688.700 580.130 1689.120 ;
    END
  END w0_wmask_in[578]
  PIN w0_wmask_in[579]
    DIRECTION INPUT ;
    USE SIGNAL ;
    SHAPE ABUTMENT ;
    PORT
      LAYER met2 ;
      RECT 582.290 1688.700 582.430 1689.120 ;
    END
  END w0_wmask_in[579]
  PIN w0_wmask_in[580]
    DIRECTION INPUT ;
    USE SIGNAL ;
    SHAPE ABUTMENT ;
    PORT
      LAYER met2 ;
      RECT 584.590 1688.700 584.730 1689.120 ;
    END
  END w0_wmask_in[580]
  PIN w0_wmask_in[581]
    DIRECTION INPUT ;
    USE SIGNAL ;
    SHAPE ABUTMENT ;
    PORT
      LAYER met2 ;
      RECT 586.890 1688.700 587.030 1689.120 ;
    END
  END w0_wmask_in[581]
  PIN w0_wmask_in[582]
    DIRECTION INPUT ;
    USE SIGNAL ;
    SHAPE ABUTMENT ;
    PORT
      LAYER met2 ;
      RECT 589.190 1688.700 589.330 1689.120 ;
    END
  END w0_wmask_in[582]
  PIN w0_wmask_in[583]
    DIRECTION INPUT ;
    USE SIGNAL ;
    SHAPE ABUTMENT ;
    PORT
      LAYER met2 ;
      RECT 591.490 1688.700 591.630 1689.120 ;
    END
  END w0_wmask_in[583]
  PIN w0_wmask_in[584]
    DIRECTION INPUT ;
    USE SIGNAL ;
    SHAPE ABUTMENT ;
    PORT
      LAYER met2 ;
      RECT 593.790 1688.700 593.930 1689.120 ;
    END
  END w0_wmask_in[584]
  PIN w0_wmask_in[585]
    DIRECTION INPUT ;
    USE SIGNAL ;
    SHAPE ABUTMENT ;
    PORT
      LAYER met2 ;
      RECT 596.090 1688.700 596.230 1689.120 ;
    END
  END w0_wmask_in[585]
  PIN w0_wmask_in[586]
    DIRECTION INPUT ;
    USE SIGNAL ;
    SHAPE ABUTMENT ;
    PORT
      LAYER met2 ;
      RECT 598.390 1688.700 598.530 1689.120 ;
    END
  END w0_wmask_in[586]
  PIN w0_wmask_in[587]
    DIRECTION INPUT ;
    USE SIGNAL ;
    SHAPE ABUTMENT ;
    PORT
      LAYER met2 ;
      RECT 600.690 1688.700 600.830 1689.120 ;
    END
  END w0_wmask_in[587]
  PIN w0_wmask_in[588]
    DIRECTION INPUT ;
    USE SIGNAL ;
    SHAPE ABUTMENT ;
    PORT
      LAYER met2 ;
      RECT 602.990 1688.700 603.130 1689.120 ;
    END
  END w0_wmask_in[588]
  PIN w0_wmask_in[589]
    DIRECTION INPUT ;
    USE SIGNAL ;
    SHAPE ABUTMENT ;
    PORT
      LAYER met2 ;
      RECT 605.290 1688.700 605.430 1689.120 ;
    END
  END w0_wmask_in[589]
  PIN w0_wmask_in[590]
    DIRECTION INPUT ;
    USE SIGNAL ;
    SHAPE ABUTMENT ;
    PORT
      LAYER met2 ;
      RECT 607.590 1688.700 607.730 1689.120 ;
    END
  END w0_wmask_in[590]
  PIN w0_wmask_in[591]
    DIRECTION INPUT ;
    USE SIGNAL ;
    SHAPE ABUTMENT ;
    PORT
      LAYER met2 ;
      RECT 609.890 1688.700 610.030 1689.120 ;
    END
  END w0_wmask_in[591]
  PIN w0_wmask_in[592]
    DIRECTION INPUT ;
    USE SIGNAL ;
    SHAPE ABUTMENT ;
    PORT
      LAYER met2 ;
      RECT 612.190 1688.700 612.330 1689.120 ;
    END
  END w0_wmask_in[592]
  PIN w0_wmask_in[593]
    DIRECTION INPUT ;
    USE SIGNAL ;
    SHAPE ABUTMENT ;
    PORT
      LAYER met2 ;
      RECT 614.490 1688.700 614.630 1689.120 ;
    END
  END w0_wmask_in[593]
  PIN w0_wmask_in[594]
    DIRECTION INPUT ;
    USE SIGNAL ;
    SHAPE ABUTMENT ;
    PORT
      LAYER met2 ;
      RECT 616.790 1688.700 616.930 1689.120 ;
    END
  END w0_wmask_in[594]
  PIN w0_wmask_in[595]
    DIRECTION INPUT ;
    USE SIGNAL ;
    SHAPE ABUTMENT ;
    PORT
      LAYER met2 ;
      RECT 619.090 1688.700 619.230 1689.120 ;
    END
  END w0_wmask_in[595]
  PIN w0_wmask_in[596]
    DIRECTION INPUT ;
    USE SIGNAL ;
    SHAPE ABUTMENT ;
    PORT
      LAYER met2 ;
      RECT 621.390 1688.700 621.530 1689.120 ;
    END
  END w0_wmask_in[596]
  PIN w0_wmask_in[597]
    DIRECTION INPUT ;
    USE SIGNAL ;
    SHAPE ABUTMENT ;
    PORT
      LAYER met2 ;
      RECT 623.690 1688.700 623.830 1689.120 ;
    END
  END w0_wmask_in[597]
  PIN w0_wmask_in[598]
    DIRECTION INPUT ;
    USE SIGNAL ;
    SHAPE ABUTMENT ;
    PORT
      LAYER met2 ;
      RECT 625.990 1688.700 626.130 1689.120 ;
    END
  END w0_wmask_in[598]
  PIN w0_wmask_in[599]
    DIRECTION INPUT ;
    USE SIGNAL ;
    SHAPE ABUTMENT ;
    PORT
      LAYER met2 ;
      RECT 628.290 1688.700 628.430 1689.120 ;
    END
  END w0_wmask_in[599]
  PIN w0_wmask_in[600]
    DIRECTION INPUT ;
    USE SIGNAL ;
    SHAPE ABUTMENT ;
    PORT
      LAYER met2 ;
      RECT 630.590 1688.700 630.730 1689.120 ;
    END
  END w0_wmask_in[600]
  PIN w0_wmask_in[601]
    DIRECTION INPUT ;
    USE SIGNAL ;
    SHAPE ABUTMENT ;
    PORT
      LAYER met2 ;
      RECT 632.890 1688.700 633.030 1689.120 ;
    END
  END w0_wmask_in[601]
  PIN w0_wmask_in[602]
    DIRECTION INPUT ;
    USE SIGNAL ;
    SHAPE ABUTMENT ;
    PORT
      LAYER met2 ;
      RECT 635.190 1688.700 635.330 1689.120 ;
    END
  END w0_wmask_in[602]
  PIN w0_wmask_in[603]
    DIRECTION INPUT ;
    USE SIGNAL ;
    SHAPE ABUTMENT ;
    PORT
      LAYER met2 ;
      RECT 637.490 1688.700 637.630 1689.120 ;
    END
  END w0_wmask_in[603]
  PIN w0_wmask_in[604]
    DIRECTION INPUT ;
    USE SIGNAL ;
    SHAPE ABUTMENT ;
    PORT
      LAYER met2 ;
      RECT 639.790 1688.700 639.930 1689.120 ;
    END
  END w0_wmask_in[604]
  PIN w0_wmask_in[605]
    DIRECTION INPUT ;
    USE SIGNAL ;
    SHAPE ABUTMENT ;
    PORT
      LAYER met2 ;
      RECT 642.090 1688.700 642.230 1689.120 ;
    END
  END w0_wmask_in[605]
  PIN w0_wmask_in[606]
    DIRECTION INPUT ;
    USE SIGNAL ;
    SHAPE ABUTMENT ;
    PORT
      LAYER met2 ;
      RECT 644.390 1688.700 644.530 1689.120 ;
    END
  END w0_wmask_in[606]
  PIN w0_wmask_in[607]
    DIRECTION INPUT ;
    USE SIGNAL ;
    SHAPE ABUTMENT ;
    PORT
      LAYER met2 ;
      RECT 646.690 1688.700 646.830 1689.120 ;
    END
  END w0_wmask_in[607]
  PIN w0_wmask_in[608]
    DIRECTION INPUT ;
    USE SIGNAL ;
    SHAPE ABUTMENT ;
    PORT
      LAYER met2 ;
      RECT 648.990 1688.700 649.130 1689.120 ;
    END
  END w0_wmask_in[608]
  PIN w0_wmask_in[609]
    DIRECTION INPUT ;
    USE SIGNAL ;
    SHAPE ABUTMENT ;
    PORT
      LAYER met2 ;
      RECT 651.290 1688.700 651.430 1689.120 ;
    END
  END w0_wmask_in[609]
  PIN w0_wmask_in[610]
    DIRECTION INPUT ;
    USE SIGNAL ;
    SHAPE ABUTMENT ;
    PORT
      LAYER met2 ;
      RECT 653.590 1688.700 653.730 1689.120 ;
    END
  END w0_wmask_in[610]
  PIN w0_wmask_in[611]
    DIRECTION INPUT ;
    USE SIGNAL ;
    SHAPE ABUTMENT ;
    PORT
      LAYER met2 ;
      RECT 655.890 1688.700 656.030 1689.120 ;
    END
  END w0_wmask_in[611]
  PIN w0_wmask_in[612]
    DIRECTION INPUT ;
    USE SIGNAL ;
    SHAPE ABUTMENT ;
    PORT
      LAYER met2 ;
      RECT 658.190 1688.700 658.330 1689.120 ;
    END
  END w0_wmask_in[612]
  PIN w0_wmask_in[613]
    DIRECTION INPUT ;
    USE SIGNAL ;
    SHAPE ABUTMENT ;
    PORT
      LAYER met2 ;
      RECT 660.490 1688.700 660.630 1689.120 ;
    END
  END w0_wmask_in[613]
  PIN w0_wmask_in[614]
    DIRECTION INPUT ;
    USE SIGNAL ;
    SHAPE ABUTMENT ;
    PORT
      LAYER met2 ;
      RECT 662.790 1688.700 662.930 1689.120 ;
    END
  END w0_wmask_in[614]
  PIN w0_wmask_in[615]
    DIRECTION INPUT ;
    USE SIGNAL ;
    SHAPE ABUTMENT ;
    PORT
      LAYER met2 ;
      RECT 665.090 1688.700 665.230 1689.120 ;
    END
  END w0_wmask_in[615]
  PIN w0_wmask_in[616]
    DIRECTION INPUT ;
    USE SIGNAL ;
    SHAPE ABUTMENT ;
    PORT
      LAYER met2 ;
      RECT 667.390 1688.700 667.530 1689.120 ;
    END
  END w0_wmask_in[616]
  PIN w0_wmask_in[617]
    DIRECTION INPUT ;
    USE SIGNAL ;
    SHAPE ABUTMENT ;
    PORT
      LAYER met2 ;
      RECT 669.690 1688.700 669.830 1689.120 ;
    END
  END w0_wmask_in[617]
  PIN w0_wmask_in[618]
    DIRECTION INPUT ;
    USE SIGNAL ;
    SHAPE ABUTMENT ;
    PORT
      LAYER met2 ;
      RECT 671.990 1688.700 672.130 1689.120 ;
    END
  END w0_wmask_in[618]
  PIN w0_wmask_in[619]
    DIRECTION INPUT ;
    USE SIGNAL ;
    SHAPE ABUTMENT ;
    PORT
      LAYER met2 ;
      RECT 674.290 1688.700 674.430 1689.120 ;
    END
  END w0_wmask_in[619]
  PIN w0_wmask_in[620]
    DIRECTION INPUT ;
    USE SIGNAL ;
    SHAPE ABUTMENT ;
    PORT
      LAYER met2 ;
      RECT 676.590 1688.700 676.730 1689.120 ;
    END
  END w0_wmask_in[620]
  PIN w0_wmask_in[621]
    DIRECTION INPUT ;
    USE SIGNAL ;
    SHAPE ABUTMENT ;
    PORT
      LAYER met2 ;
      RECT 678.890 1688.700 679.030 1689.120 ;
    END
  END w0_wmask_in[621]
  PIN w0_wmask_in[622]
    DIRECTION INPUT ;
    USE SIGNAL ;
    SHAPE ABUTMENT ;
    PORT
      LAYER met2 ;
      RECT 681.190 1688.700 681.330 1689.120 ;
    END
  END w0_wmask_in[622]
  PIN w0_wmask_in[623]
    DIRECTION INPUT ;
    USE SIGNAL ;
    SHAPE ABUTMENT ;
    PORT
      LAYER met2 ;
      RECT 683.490 1688.700 683.630 1689.120 ;
    END
  END w0_wmask_in[623]
  PIN w0_wmask_in[624]
    DIRECTION INPUT ;
    USE SIGNAL ;
    SHAPE ABUTMENT ;
    PORT
      LAYER met2 ;
      RECT 685.790 1688.700 685.930 1689.120 ;
    END
  END w0_wmask_in[624]
  PIN w0_wmask_in[625]
    DIRECTION INPUT ;
    USE SIGNAL ;
    SHAPE ABUTMENT ;
    PORT
      LAYER met2 ;
      RECT 688.090 1688.700 688.230 1689.120 ;
    END
  END w0_wmask_in[625]
  PIN w0_wmask_in[626]
    DIRECTION INPUT ;
    USE SIGNAL ;
    SHAPE ABUTMENT ;
    PORT
      LAYER met2 ;
      RECT 690.390 1688.700 690.530 1689.120 ;
    END
  END w0_wmask_in[626]
  PIN w0_wmask_in[627]
    DIRECTION INPUT ;
    USE SIGNAL ;
    SHAPE ABUTMENT ;
    PORT
      LAYER met2 ;
      RECT 692.690 1688.700 692.830 1689.120 ;
    END
  END w0_wmask_in[627]
  PIN w0_wmask_in[628]
    DIRECTION INPUT ;
    USE SIGNAL ;
    SHAPE ABUTMENT ;
    PORT
      LAYER met2 ;
      RECT 694.990 1688.700 695.130 1689.120 ;
    END
  END w0_wmask_in[628]
  PIN w0_wmask_in[629]
    DIRECTION INPUT ;
    USE SIGNAL ;
    SHAPE ABUTMENT ;
    PORT
      LAYER met2 ;
      RECT 697.290 1688.700 697.430 1689.120 ;
    END
  END w0_wmask_in[629]
  PIN w0_wmask_in[630]
    DIRECTION INPUT ;
    USE SIGNAL ;
    SHAPE ABUTMENT ;
    PORT
      LAYER met2 ;
      RECT 699.590 1688.700 699.730 1689.120 ;
    END
  END w0_wmask_in[630]
  PIN w0_wmask_in[631]
    DIRECTION INPUT ;
    USE SIGNAL ;
    SHAPE ABUTMENT ;
    PORT
      LAYER met2 ;
      RECT 701.890 1688.700 702.030 1689.120 ;
    END
  END w0_wmask_in[631]
  PIN w0_wmask_in[632]
    DIRECTION INPUT ;
    USE SIGNAL ;
    SHAPE ABUTMENT ;
    PORT
      LAYER met2 ;
      RECT 704.190 1688.700 704.330 1689.120 ;
    END
  END w0_wmask_in[632]
  PIN w0_wmask_in[633]
    DIRECTION INPUT ;
    USE SIGNAL ;
    SHAPE ABUTMENT ;
    PORT
      LAYER met2 ;
      RECT 706.490 1688.700 706.630 1689.120 ;
    END
  END w0_wmask_in[633]
  PIN w0_wmask_in[634]
    DIRECTION INPUT ;
    USE SIGNAL ;
    SHAPE ABUTMENT ;
    PORT
      LAYER met2 ;
      RECT 708.790 1688.700 708.930 1689.120 ;
    END
  END w0_wmask_in[634]
  PIN w0_wmask_in[635]
    DIRECTION INPUT ;
    USE SIGNAL ;
    SHAPE ABUTMENT ;
    PORT
      LAYER met2 ;
      RECT 711.090 1688.700 711.230 1689.120 ;
    END
  END w0_wmask_in[635]
  PIN w0_wmask_in[636]
    DIRECTION INPUT ;
    USE SIGNAL ;
    SHAPE ABUTMENT ;
    PORT
      LAYER met2 ;
      RECT 713.390 1688.700 713.530 1689.120 ;
    END
  END w0_wmask_in[636]
  PIN w0_wmask_in[637]
    DIRECTION INPUT ;
    USE SIGNAL ;
    SHAPE ABUTMENT ;
    PORT
      LAYER met2 ;
      RECT 715.690 1688.700 715.830 1689.120 ;
    END
  END w0_wmask_in[637]
  PIN w0_wmask_in[638]
    DIRECTION INPUT ;
    USE SIGNAL ;
    SHAPE ABUTMENT ;
    PORT
      LAYER met2 ;
      RECT 717.990 1688.700 718.130 1689.120 ;
    END
  END w0_wmask_in[638]
  PIN w0_wmask_in[639]
    DIRECTION INPUT ;
    USE SIGNAL ;
    SHAPE ABUTMENT ;
    PORT
      LAYER met2 ;
      RECT 720.290 1688.700 720.430 1689.120 ;
    END
  END w0_wmask_in[639]
  PIN w0_wmask_in[640]
    DIRECTION INPUT ;
    USE SIGNAL ;
    SHAPE ABUTMENT ;
    PORT
      LAYER met2 ;
      RECT 722.590 1688.700 722.730 1689.120 ;
    END
  END w0_wmask_in[640]
  PIN w0_wmask_in[641]
    DIRECTION INPUT ;
    USE SIGNAL ;
    SHAPE ABUTMENT ;
    PORT
      LAYER met2 ;
      RECT 724.890 1688.700 725.030 1689.120 ;
    END
  END w0_wmask_in[641]
  PIN w0_wmask_in[642]
    DIRECTION INPUT ;
    USE SIGNAL ;
    SHAPE ABUTMENT ;
    PORT
      LAYER met2 ;
      RECT 727.190 1688.700 727.330 1689.120 ;
    END
  END w0_wmask_in[642]
  PIN w0_wmask_in[643]
    DIRECTION INPUT ;
    USE SIGNAL ;
    SHAPE ABUTMENT ;
    PORT
      LAYER met2 ;
      RECT 729.490 1688.700 729.630 1689.120 ;
    END
  END w0_wmask_in[643]
  PIN w0_wmask_in[644]
    DIRECTION INPUT ;
    USE SIGNAL ;
    SHAPE ABUTMENT ;
    PORT
      LAYER met2 ;
      RECT 731.790 1688.700 731.930 1689.120 ;
    END
  END w0_wmask_in[644]
  PIN w0_wmask_in[645]
    DIRECTION INPUT ;
    USE SIGNAL ;
    SHAPE ABUTMENT ;
    PORT
      LAYER met2 ;
      RECT 734.090 1688.700 734.230 1689.120 ;
    END
  END w0_wmask_in[645]
  PIN w0_wmask_in[646]
    DIRECTION INPUT ;
    USE SIGNAL ;
    SHAPE ABUTMENT ;
    PORT
      LAYER met2 ;
      RECT 736.390 1688.700 736.530 1689.120 ;
    END
  END w0_wmask_in[646]
  PIN w0_wmask_in[647]
    DIRECTION INPUT ;
    USE SIGNAL ;
    SHAPE ABUTMENT ;
    PORT
      LAYER met2 ;
      RECT 738.690 1688.700 738.830 1689.120 ;
    END
  END w0_wmask_in[647]
  PIN w0_wmask_in[648]
    DIRECTION INPUT ;
    USE SIGNAL ;
    SHAPE ABUTMENT ;
    PORT
      LAYER met2 ;
      RECT 740.990 1688.700 741.130 1689.120 ;
    END
  END w0_wmask_in[648]
  PIN w0_wmask_in[649]
    DIRECTION INPUT ;
    USE SIGNAL ;
    SHAPE ABUTMENT ;
    PORT
      LAYER met2 ;
      RECT 743.290 1688.700 743.430 1689.120 ;
    END
  END w0_wmask_in[649]
  PIN w0_wmask_in[650]
    DIRECTION INPUT ;
    USE SIGNAL ;
    SHAPE ABUTMENT ;
    PORT
      LAYER met2 ;
      RECT 745.590 1688.700 745.730 1689.120 ;
    END
  END w0_wmask_in[650]
  PIN w0_wmask_in[651]
    DIRECTION INPUT ;
    USE SIGNAL ;
    SHAPE ABUTMENT ;
    PORT
      LAYER met2 ;
      RECT 747.890 1688.700 748.030 1689.120 ;
    END
  END w0_wmask_in[651]
  PIN w0_wmask_in[652]
    DIRECTION INPUT ;
    USE SIGNAL ;
    SHAPE ABUTMENT ;
    PORT
      LAYER met2 ;
      RECT 750.190 1688.700 750.330 1689.120 ;
    END
  END w0_wmask_in[652]
  PIN w0_wmask_in[653]
    DIRECTION INPUT ;
    USE SIGNAL ;
    SHAPE ABUTMENT ;
    PORT
      LAYER met2 ;
      RECT 752.490 1688.700 752.630 1689.120 ;
    END
  END w0_wmask_in[653]
  PIN w0_wd_in[0]
    DIRECTION INPUT ;
    USE SIGNAL ;
    SHAPE ABUTMENT ;
    PORT
      LAYER met3 ;
      RECT 0.000 784.570 0.900 784.870 ;
    END
  END w0_wd_in[0]
  PIN w0_wd_in[1]
    DIRECTION INPUT ;
    USE SIGNAL ;
    SHAPE ABUTMENT ;
    PORT
      LAYER met3 ;
      RECT 0.000 789.330 0.900 789.630 ;
    END
  END w0_wd_in[1]
  PIN w0_wd_in[2]
    DIRECTION INPUT ;
    USE SIGNAL ;
    SHAPE ABUTMENT ;
    PORT
      LAYER met3 ;
      RECT 0.000 794.090 0.900 794.390 ;
    END
  END w0_wd_in[2]
  PIN w0_wd_in[3]
    DIRECTION INPUT ;
    USE SIGNAL ;
    SHAPE ABUTMENT ;
    PORT
      LAYER met3 ;
      RECT 0.000 798.850 0.900 799.150 ;
    END
  END w0_wd_in[3]
  PIN w0_wd_in[4]
    DIRECTION INPUT ;
    USE SIGNAL ;
    SHAPE ABUTMENT ;
    PORT
      LAYER met3 ;
      RECT 0.000 803.610 0.900 803.910 ;
    END
  END w0_wd_in[4]
  PIN w0_wd_in[5]
    DIRECTION INPUT ;
    USE SIGNAL ;
    SHAPE ABUTMENT ;
    PORT
      LAYER met3 ;
      RECT 0.000 808.370 0.900 808.670 ;
    END
  END w0_wd_in[5]
  PIN w0_wd_in[6]
    DIRECTION INPUT ;
    USE SIGNAL ;
    SHAPE ABUTMENT ;
    PORT
      LAYER met3 ;
      RECT 0.000 813.130 0.900 813.430 ;
    END
  END w0_wd_in[6]
  PIN w0_wd_in[7]
    DIRECTION INPUT ;
    USE SIGNAL ;
    SHAPE ABUTMENT ;
    PORT
      LAYER met3 ;
      RECT 0.000 817.890 0.900 818.190 ;
    END
  END w0_wd_in[7]
  PIN w0_wd_in[8]
    DIRECTION INPUT ;
    USE SIGNAL ;
    SHAPE ABUTMENT ;
    PORT
      LAYER met3 ;
      RECT 0.000 822.650 0.900 822.950 ;
    END
  END w0_wd_in[8]
  PIN w0_wd_in[9]
    DIRECTION INPUT ;
    USE SIGNAL ;
    SHAPE ABUTMENT ;
    PORT
      LAYER met3 ;
      RECT 0.000 827.410 0.900 827.710 ;
    END
  END w0_wd_in[9]
  PIN w0_wd_in[10]
    DIRECTION INPUT ;
    USE SIGNAL ;
    SHAPE ABUTMENT ;
    PORT
      LAYER met3 ;
      RECT 0.000 832.170 0.900 832.470 ;
    END
  END w0_wd_in[10]
  PIN w0_wd_in[11]
    DIRECTION INPUT ;
    USE SIGNAL ;
    SHAPE ABUTMENT ;
    PORT
      LAYER met3 ;
      RECT 0.000 836.930 0.900 837.230 ;
    END
  END w0_wd_in[11]
  PIN w0_wd_in[12]
    DIRECTION INPUT ;
    USE SIGNAL ;
    SHAPE ABUTMENT ;
    PORT
      LAYER met3 ;
      RECT 0.000 841.690 0.900 841.990 ;
    END
  END w0_wd_in[12]
  PIN w0_wd_in[13]
    DIRECTION INPUT ;
    USE SIGNAL ;
    SHAPE ABUTMENT ;
    PORT
      LAYER met3 ;
      RECT 0.000 846.450 0.900 846.750 ;
    END
  END w0_wd_in[13]
  PIN w0_wd_in[14]
    DIRECTION INPUT ;
    USE SIGNAL ;
    SHAPE ABUTMENT ;
    PORT
      LAYER met3 ;
      RECT 0.000 851.210 0.900 851.510 ;
    END
  END w0_wd_in[14]
  PIN w0_wd_in[15]
    DIRECTION INPUT ;
    USE SIGNAL ;
    SHAPE ABUTMENT ;
    PORT
      LAYER met3 ;
      RECT 0.000 855.970 0.900 856.270 ;
    END
  END w0_wd_in[15]
  PIN w0_wd_in[16]
    DIRECTION INPUT ;
    USE SIGNAL ;
    SHAPE ABUTMENT ;
    PORT
      LAYER met3 ;
      RECT 0.000 860.730 0.900 861.030 ;
    END
  END w0_wd_in[16]
  PIN w0_wd_in[17]
    DIRECTION INPUT ;
    USE SIGNAL ;
    SHAPE ABUTMENT ;
    PORT
      LAYER met3 ;
      RECT 0.000 865.490 0.900 865.790 ;
    END
  END w0_wd_in[17]
  PIN w0_wd_in[18]
    DIRECTION INPUT ;
    USE SIGNAL ;
    SHAPE ABUTMENT ;
    PORT
      LAYER met3 ;
      RECT 0.000 870.250 0.900 870.550 ;
    END
  END w0_wd_in[18]
  PIN w0_wd_in[19]
    DIRECTION INPUT ;
    USE SIGNAL ;
    SHAPE ABUTMENT ;
    PORT
      LAYER met3 ;
      RECT 0.000 875.010 0.900 875.310 ;
    END
  END w0_wd_in[19]
  PIN w0_wd_in[20]
    DIRECTION INPUT ;
    USE SIGNAL ;
    SHAPE ABUTMENT ;
    PORT
      LAYER met3 ;
      RECT 0.000 879.770 0.900 880.070 ;
    END
  END w0_wd_in[20]
  PIN w0_wd_in[21]
    DIRECTION INPUT ;
    USE SIGNAL ;
    SHAPE ABUTMENT ;
    PORT
      LAYER met3 ;
      RECT 0.000 884.530 0.900 884.830 ;
    END
  END w0_wd_in[21]
  PIN w0_wd_in[22]
    DIRECTION INPUT ;
    USE SIGNAL ;
    SHAPE ABUTMENT ;
    PORT
      LAYER met3 ;
      RECT 0.000 889.290 0.900 889.590 ;
    END
  END w0_wd_in[22]
  PIN w0_wd_in[23]
    DIRECTION INPUT ;
    USE SIGNAL ;
    SHAPE ABUTMENT ;
    PORT
      LAYER met3 ;
      RECT 0.000 894.050 0.900 894.350 ;
    END
  END w0_wd_in[23]
  PIN w0_wd_in[24]
    DIRECTION INPUT ;
    USE SIGNAL ;
    SHAPE ABUTMENT ;
    PORT
      LAYER met3 ;
      RECT 0.000 898.810 0.900 899.110 ;
    END
  END w0_wd_in[24]
  PIN w0_wd_in[25]
    DIRECTION INPUT ;
    USE SIGNAL ;
    SHAPE ABUTMENT ;
    PORT
      LAYER met3 ;
      RECT 0.000 903.570 0.900 903.870 ;
    END
  END w0_wd_in[25]
  PIN w0_wd_in[26]
    DIRECTION INPUT ;
    USE SIGNAL ;
    SHAPE ABUTMENT ;
    PORT
      LAYER met3 ;
      RECT 0.000 908.330 0.900 908.630 ;
    END
  END w0_wd_in[26]
  PIN w0_wd_in[27]
    DIRECTION INPUT ;
    USE SIGNAL ;
    SHAPE ABUTMENT ;
    PORT
      LAYER met3 ;
      RECT 0.000 913.090 0.900 913.390 ;
    END
  END w0_wd_in[27]
  PIN w0_wd_in[28]
    DIRECTION INPUT ;
    USE SIGNAL ;
    SHAPE ABUTMENT ;
    PORT
      LAYER met3 ;
      RECT 0.000 917.850 0.900 918.150 ;
    END
  END w0_wd_in[28]
  PIN w0_wd_in[29]
    DIRECTION INPUT ;
    USE SIGNAL ;
    SHAPE ABUTMENT ;
    PORT
      LAYER met3 ;
      RECT 0.000 922.610 0.900 922.910 ;
    END
  END w0_wd_in[29]
  PIN w0_wd_in[30]
    DIRECTION INPUT ;
    USE SIGNAL ;
    SHAPE ABUTMENT ;
    PORT
      LAYER met3 ;
      RECT 0.000 927.370 0.900 927.670 ;
    END
  END w0_wd_in[30]
  PIN w0_wd_in[31]
    DIRECTION INPUT ;
    USE SIGNAL ;
    SHAPE ABUTMENT ;
    PORT
      LAYER met3 ;
      RECT 0.000 932.130 0.900 932.430 ;
    END
  END w0_wd_in[31]
  PIN w0_wd_in[32]
    DIRECTION INPUT ;
    USE SIGNAL ;
    SHAPE ABUTMENT ;
    PORT
      LAYER met3 ;
      RECT 0.000 936.890 0.900 937.190 ;
    END
  END w0_wd_in[32]
  PIN w0_wd_in[33]
    DIRECTION INPUT ;
    USE SIGNAL ;
    SHAPE ABUTMENT ;
    PORT
      LAYER met3 ;
      RECT 0.000 941.650 0.900 941.950 ;
    END
  END w0_wd_in[33]
  PIN w0_wd_in[34]
    DIRECTION INPUT ;
    USE SIGNAL ;
    SHAPE ABUTMENT ;
    PORT
      LAYER met3 ;
      RECT 0.000 946.410 0.900 946.710 ;
    END
  END w0_wd_in[34]
  PIN w0_wd_in[35]
    DIRECTION INPUT ;
    USE SIGNAL ;
    SHAPE ABUTMENT ;
    PORT
      LAYER met3 ;
      RECT 0.000 951.170 0.900 951.470 ;
    END
  END w0_wd_in[35]
  PIN w0_wd_in[36]
    DIRECTION INPUT ;
    USE SIGNAL ;
    SHAPE ABUTMENT ;
    PORT
      LAYER met3 ;
      RECT 0.000 955.930 0.900 956.230 ;
    END
  END w0_wd_in[36]
  PIN w0_wd_in[37]
    DIRECTION INPUT ;
    USE SIGNAL ;
    SHAPE ABUTMENT ;
    PORT
      LAYER met3 ;
      RECT 0.000 960.690 0.900 960.990 ;
    END
  END w0_wd_in[37]
  PIN w0_wd_in[38]
    DIRECTION INPUT ;
    USE SIGNAL ;
    SHAPE ABUTMENT ;
    PORT
      LAYER met3 ;
      RECT 0.000 965.450 0.900 965.750 ;
    END
  END w0_wd_in[38]
  PIN w0_wd_in[39]
    DIRECTION INPUT ;
    USE SIGNAL ;
    SHAPE ABUTMENT ;
    PORT
      LAYER met3 ;
      RECT 0.000 970.210 0.900 970.510 ;
    END
  END w0_wd_in[39]
  PIN w0_wd_in[40]
    DIRECTION INPUT ;
    USE SIGNAL ;
    SHAPE ABUTMENT ;
    PORT
      LAYER met3 ;
      RECT 0.000 974.970 0.900 975.270 ;
    END
  END w0_wd_in[40]
  PIN w0_wd_in[41]
    DIRECTION INPUT ;
    USE SIGNAL ;
    SHAPE ABUTMENT ;
    PORT
      LAYER met3 ;
      RECT 0.000 979.730 0.900 980.030 ;
    END
  END w0_wd_in[41]
  PIN w0_wd_in[42]
    DIRECTION INPUT ;
    USE SIGNAL ;
    SHAPE ABUTMENT ;
    PORT
      LAYER met3 ;
      RECT 0.000 984.490 0.900 984.790 ;
    END
  END w0_wd_in[42]
  PIN w0_wd_in[43]
    DIRECTION INPUT ;
    USE SIGNAL ;
    SHAPE ABUTMENT ;
    PORT
      LAYER met3 ;
      RECT 0.000 989.250 0.900 989.550 ;
    END
  END w0_wd_in[43]
  PIN w0_wd_in[44]
    DIRECTION INPUT ;
    USE SIGNAL ;
    SHAPE ABUTMENT ;
    PORT
      LAYER met3 ;
      RECT 0.000 994.010 0.900 994.310 ;
    END
  END w0_wd_in[44]
  PIN w0_wd_in[45]
    DIRECTION INPUT ;
    USE SIGNAL ;
    SHAPE ABUTMENT ;
    PORT
      LAYER met3 ;
      RECT 0.000 998.770 0.900 999.070 ;
    END
  END w0_wd_in[45]
  PIN w0_wd_in[46]
    DIRECTION INPUT ;
    USE SIGNAL ;
    SHAPE ABUTMENT ;
    PORT
      LAYER met3 ;
      RECT 0.000 1003.530 0.900 1003.830 ;
    END
  END w0_wd_in[46]
  PIN w0_wd_in[47]
    DIRECTION INPUT ;
    USE SIGNAL ;
    SHAPE ABUTMENT ;
    PORT
      LAYER met3 ;
      RECT 0.000 1008.290 0.900 1008.590 ;
    END
  END w0_wd_in[47]
  PIN w0_wd_in[48]
    DIRECTION INPUT ;
    USE SIGNAL ;
    SHAPE ABUTMENT ;
    PORT
      LAYER met3 ;
      RECT 0.000 1013.050 0.900 1013.350 ;
    END
  END w0_wd_in[48]
  PIN w0_wd_in[49]
    DIRECTION INPUT ;
    USE SIGNAL ;
    SHAPE ABUTMENT ;
    PORT
      LAYER met3 ;
      RECT 0.000 1017.810 0.900 1018.110 ;
    END
  END w0_wd_in[49]
  PIN w0_wd_in[50]
    DIRECTION INPUT ;
    USE SIGNAL ;
    SHAPE ABUTMENT ;
    PORT
      LAYER met3 ;
      RECT 0.000 1022.570 0.900 1022.870 ;
    END
  END w0_wd_in[50]
  PIN w0_wd_in[51]
    DIRECTION INPUT ;
    USE SIGNAL ;
    SHAPE ABUTMENT ;
    PORT
      LAYER met3 ;
      RECT 0.000 1027.330 0.900 1027.630 ;
    END
  END w0_wd_in[51]
  PIN w0_wd_in[52]
    DIRECTION INPUT ;
    USE SIGNAL ;
    SHAPE ABUTMENT ;
    PORT
      LAYER met3 ;
      RECT 0.000 1032.090 0.900 1032.390 ;
    END
  END w0_wd_in[52]
  PIN w0_wd_in[53]
    DIRECTION INPUT ;
    USE SIGNAL ;
    SHAPE ABUTMENT ;
    PORT
      LAYER met3 ;
      RECT 0.000 1036.850 0.900 1037.150 ;
    END
  END w0_wd_in[53]
  PIN w0_wd_in[54]
    DIRECTION INPUT ;
    USE SIGNAL ;
    SHAPE ABUTMENT ;
    PORT
      LAYER met3 ;
      RECT 0.000 1041.610 0.900 1041.910 ;
    END
  END w0_wd_in[54]
  PIN w0_wd_in[55]
    DIRECTION INPUT ;
    USE SIGNAL ;
    SHAPE ABUTMENT ;
    PORT
      LAYER met3 ;
      RECT 0.000 1046.370 0.900 1046.670 ;
    END
  END w0_wd_in[55]
  PIN w0_wd_in[56]
    DIRECTION INPUT ;
    USE SIGNAL ;
    SHAPE ABUTMENT ;
    PORT
      LAYER met3 ;
      RECT 0.000 1051.130 0.900 1051.430 ;
    END
  END w0_wd_in[56]
  PIN w0_wd_in[57]
    DIRECTION INPUT ;
    USE SIGNAL ;
    SHAPE ABUTMENT ;
    PORT
      LAYER met3 ;
      RECT 0.000 1055.890 0.900 1056.190 ;
    END
  END w0_wd_in[57]
  PIN w0_wd_in[58]
    DIRECTION INPUT ;
    USE SIGNAL ;
    SHAPE ABUTMENT ;
    PORT
      LAYER met3 ;
      RECT 0.000 1060.650 0.900 1060.950 ;
    END
  END w0_wd_in[58]
  PIN w0_wd_in[59]
    DIRECTION INPUT ;
    USE SIGNAL ;
    SHAPE ABUTMENT ;
    PORT
      LAYER met3 ;
      RECT 0.000 1065.410 0.900 1065.710 ;
    END
  END w0_wd_in[59]
  PIN w0_wd_in[60]
    DIRECTION INPUT ;
    USE SIGNAL ;
    SHAPE ABUTMENT ;
    PORT
      LAYER met3 ;
      RECT 0.000 1070.170 0.900 1070.470 ;
    END
  END w0_wd_in[60]
  PIN w0_wd_in[61]
    DIRECTION INPUT ;
    USE SIGNAL ;
    SHAPE ABUTMENT ;
    PORT
      LAYER met3 ;
      RECT 0.000 1074.930 0.900 1075.230 ;
    END
  END w0_wd_in[61]
  PIN w0_wd_in[62]
    DIRECTION INPUT ;
    USE SIGNAL ;
    SHAPE ABUTMENT ;
    PORT
      LAYER met3 ;
      RECT 0.000 1079.690 0.900 1079.990 ;
    END
  END w0_wd_in[62]
  PIN w0_wd_in[63]
    DIRECTION INPUT ;
    USE SIGNAL ;
    SHAPE ABUTMENT ;
    PORT
      LAYER met3 ;
      RECT 0.000 1084.450 0.900 1084.750 ;
    END
  END w0_wd_in[63]
  PIN w0_wd_in[64]
    DIRECTION INPUT ;
    USE SIGNAL ;
    SHAPE ABUTMENT ;
    PORT
      LAYER met3 ;
      RECT 0.000 1089.210 0.900 1089.510 ;
    END
  END w0_wd_in[64]
  PIN w0_wd_in[65]
    DIRECTION INPUT ;
    USE SIGNAL ;
    SHAPE ABUTMENT ;
    PORT
      LAYER met3 ;
      RECT 0.000 1093.970 0.900 1094.270 ;
    END
  END w0_wd_in[65]
  PIN w0_wd_in[66]
    DIRECTION INPUT ;
    USE SIGNAL ;
    SHAPE ABUTMENT ;
    PORT
      LAYER met3 ;
      RECT 0.000 1098.730 0.900 1099.030 ;
    END
  END w0_wd_in[66]
  PIN w0_wd_in[67]
    DIRECTION INPUT ;
    USE SIGNAL ;
    SHAPE ABUTMENT ;
    PORT
      LAYER met3 ;
      RECT 0.000 1103.490 0.900 1103.790 ;
    END
  END w0_wd_in[67]
  PIN w0_wd_in[68]
    DIRECTION INPUT ;
    USE SIGNAL ;
    SHAPE ABUTMENT ;
    PORT
      LAYER met3 ;
      RECT 0.000 1108.250 0.900 1108.550 ;
    END
  END w0_wd_in[68]
  PIN w0_wd_in[69]
    DIRECTION INPUT ;
    USE SIGNAL ;
    SHAPE ABUTMENT ;
    PORT
      LAYER met3 ;
      RECT 0.000 1113.010 0.900 1113.310 ;
    END
  END w0_wd_in[69]
  PIN w0_wd_in[70]
    DIRECTION INPUT ;
    USE SIGNAL ;
    SHAPE ABUTMENT ;
    PORT
      LAYER met3 ;
      RECT 0.000 1117.770 0.900 1118.070 ;
    END
  END w0_wd_in[70]
  PIN w0_wd_in[71]
    DIRECTION INPUT ;
    USE SIGNAL ;
    SHAPE ABUTMENT ;
    PORT
      LAYER met3 ;
      RECT 0.000 1122.530 0.900 1122.830 ;
    END
  END w0_wd_in[71]
  PIN w0_wd_in[72]
    DIRECTION INPUT ;
    USE SIGNAL ;
    SHAPE ABUTMENT ;
    PORT
      LAYER met3 ;
      RECT 0.000 1127.290 0.900 1127.590 ;
    END
  END w0_wd_in[72]
  PIN w0_wd_in[73]
    DIRECTION INPUT ;
    USE SIGNAL ;
    SHAPE ABUTMENT ;
    PORT
      LAYER met3 ;
      RECT 0.000 1132.050 0.900 1132.350 ;
    END
  END w0_wd_in[73]
  PIN w0_wd_in[74]
    DIRECTION INPUT ;
    USE SIGNAL ;
    SHAPE ABUTMENT ;
    PORT
      LAYER met3 ;
      RECT 0.000 1136.810 0.900 1137.110 ;
    END
  END w0_wd_in[74]
  PIN w0_wd_in[75]
    DIRECTION INPUT ;
    USE SIGNAL ;
    SHAPE ABUTMENT ;
    PORT
      LAYER met3 ;
      RECT 0.000 1141.570 0.900 1141.870 ;
    END
  END w0_wd_in[75]
  PIN w0_wd_in[76]
    DIRECTION INPUT ;
    USE SIGNAL ;
    SHAPE ABUTMENT ;
    PORT
      LAYER met3 ;
      RECT 0.000 1146.330 0.900 1146.630 ;
    END
  END w0_wd_in[76]
  PIN w0_wd_in[77]
    DIRECTION INPUT ;
    USE SIGNAL ;
    SHAPE ABUTMENT ;
    PORT
      LAYER met3 ;
      RECT 0.000 1151.090 0.900 1151.390 ;
    END
  END w0_wd_in[77]
  PIN w0_wd_in[78]
    DIRECTION INPUT ;
    USE SIGNAL ;
    SHAPE ABUTMENT ;
    PORT
      LAYER met3 ;
      RECT 0.000 1155.850 0.900 1156.150 ;
    END
  END w0_wd_in[78]
  PIN w0_wd_in[79]
    DIRECTION INPUT ;
    USE SIGNAL ;
    SHAPE ABUTMENT ;
    PORT
      LAYER met3 ;
      RECT 0.000 1160.610 0.900 1160.910 ;
    END
  END w0_wd_in[79]
  PIN w0_wd_in[80]
    DIRECTION INPUT ;
    USE SIGNAL ;
    SHAPE ABUTMENT ;
    PORT
      LAYER met3 ;
      RECT 0.000 1165.370 0.900 1165.670 ;
    END
  END w0_wd_in[80]
  PIN w0_wd_in[81]
    DIRECTION INPUT ;
    USE SIGNAL ;
    SHAPE ABUTMENT ;
    PORT
      LAYER met3 ;
      RECT 0.000 1170.130 0.900 1170.430 ;
    END
  END w0_wd_in[81]
  PIN w0_wd_in[82]
    DIRECTION INPUT ;
    USE SIGNAL ;
    SHAPE ABUTMENT ;
    PORT
      LAYER met3 ;
      RECT 0.000 1174.890 0.900 1175.190 ;
    END
  END w0_wd_in[82]
  PIN w0_wd_in[83]
    DIRECTION INPUT ;
    USE SIGNAL ;
    SHAPE ABUTMENT ;
    PORT
      LAYER met3 ;
      RECT 0.000 1179.650 0.900 1179.950 ;
    END
  END w0_wd_in[83]
  PIN w0_wd_in[84]
    DIRECTION INPUT ;
    USE SIGNAL ;
    SHAPE ABUTMENT ;
    PORT
      LAYER met3 ;
      RECT 0.000 1184.410 0.900 1184.710 ;
    END
  END w0_wd_in[84]
  PIN w0_wd_in[85]
    DIRECTION INPUT ;
    USE SIGNAL ;
    SHAPE ABUTMENT ;
    PORT
      LAYER met3 ;
      RECT 0.000 1189.170 0.900 1189.470 ;
    END
  END w0_wd_in[85]
  PIN w0_wd_in[86]
    DIRECTION INPUT ;
    USE SIGNAL ;
    SHAPE ABUTMENT ;
    PORT
      LAYER met3 ;
      RECT 0.000 1193.930 0.900 1194.230 ;
    END
  END w0_wd_in[86]
  PIN w0_wd_in[87]
    DIRECTION INPUT ;
    USE SIGNAL ;
    SHAPE ABUTMENT ;
    PORT
      LAYER met3 ;
      RECT 0.000 1198.690 0.900 1198.990 ;
    END
  END w0_wd_in[87]
  PIN w0_wd_in[88]
    DIRECTION INPUT ;
    USE SIGNAL ;
    SHAPE ABUTMENT ;
    PORT
      LAYER met3 ;
      RECT 0.000 1203.450 0.900 1203.750 ;
    END
  END w0_wd_in[88]
  PIN w0_wd_in[89]
    DIRECTION INPUT ;
    USE SIGNAL ;
    SHAPE ABUTMENT ;
    PORT
      LAYER met3 ;
      RECT 0.000 1208.210 0.900 1208.510 ;
    END
  END w0_wd_in[89]
  PIN w0_wd_in[90]
    DIRECTION INPUT ;
    USE SIGNAL ;
    SHAPE ABUTMENT ;
    PORT
      LAYER met3 ;
      RECT 0.000 1212.970 0.900 1213.270 ;
    END
  END w0_wd_in[90]
  PIN w0_wd_in[91]
    DIRECTION INPUT ;
    USE SIGNAL ;
    SHAPE ABUTMENT ;
    PORT
      LAYER met3 ;
      RECT 0.000 1217.730 0.900 1218.030 ;
    END
  END w0_wd_in[91]
  PIN w0_wd_in[92]
    DIRECTION INPUT ;
    USE SIGNAL ;
    SHAPE ABUTMENT ;
    PORT
      LAYER met3 ;
      RECT 0.000 1222.490 0.900 1222.790 ;
    END
  END w0_wd_in[92]
  PIN w0_wd_in[93]
    DIRECTION INPUT ;
    USE SIGNAL ;
    SHAPE ABUTMENT ;
    PORT
      LAYER met3 ;
      RECT 0.000 1227.250 0.900 1227.550 ;
    END
  END w0_wd_in[93]
  PIN w0_wd_in[94]
    DIRECTION INPUT ;
    USE SIGNAL ;
    SHAPE ABUTMENT ;
    PORT
      LAYER met3 ;
      RECT 0.000 1232.010 0.900 1232.310 ;
    END
  END w0_wd_in[94]
  PIN w0_wd_in[95]
    DIRECTION INPUT ;
    USE SIGNAL ;
    SHAPE ABUTMENT ;
    PORT
      LAYER met3 ;
      RECT 0.000 1236.770 0.900 1237.070 ;
    END
  END w0_wd_in[95]
  PIN w0_wd_in[96]
    DIRECTION INPUT ;
    USE SIGNAL ;
    SHAPE ABUTMENT ;
    PORT
      LAYER met3 ;
      RECT 0.000 1241.530 0.900 1241.830 ;
    END
  END w0_wd_in[96]
  PIN w0_wd_in[97]
    DIRECTION INPUT ;
    USE SIGNAL ;
    SHAPE ABUTMENT ;
    PORT
      LAYER met3 ;
      RECT 0.000 1246.290 0.900 1246.590 ;
    END
  END w0_wd_in[97]
  PIN w0_wd_in[98]
    DIRECTION INPUT ;
    USE SIGNAL ;
    SHAPE ABUTMENT ;
    PORT
      LAYER met3 ;
      RECT 0.000 1251.050 0.900 1251.350 ;
    END
  END w0_wd_in[98]
  PIN w0_wd_in[99]
    DIRECTION INPUT ;
    USE SIGNAL ;
    SHAPE ABUTMENT ;
    PORT
      LAYER met3 ;
      RECT 0.000 1255.810 0.900 1256.110 ;
    END
  END w0_wd_in[99]
  PIN w0_wd_in[100]
    DIRECTION INPUT ;
    USE SIGNAL ;
    SHAPE ABUTMENT ;
    PORT
      LAYER met3 ;
      RECT 0.000 1260.570 0.900 1260.870 ;
    END
  END w0_wd_in[100]
  PIN w0_wd_in[101]
    DIRECTION INPUT ;
    USE SIGNAL ;
    SHAPE ABUTMENT ;
    PORT
      LAYER met3 ;
      RECT 0.000 1265.330 0.900 1265.630 ;
    END
  END w0_wd_in[101]
  PIN w0_wd_in[102]
    DIRECTION INPUT ;
    USE SIGNAL ;
    SHAPE ABUTMENT ;
    PORT
      LAYER met3 ;
      RECT 0.000 1270.090 0.900 1270.390 ;
    END
  END w0_wd_in[102]
  PIN w0_wd_in[103]
    DIRECTION INPUT ;
    USE SIGNAL ;
    SHAPE ABUTMENT ;
    PORT
      LAYER met3 ;
      RECT 0.000 1274.850 0.900 1275.150 ;
    END
  END w0_wd_in[103]
  PIN w0_wd_in[104]
    DIRECTION INPUT ;
    USE SIGNAL ;
    SHAPE ABUTMENT ;
    PORT
      LAYER met3 ;
      RECT 0.000 1279.610 0.900 1279.910 ;
    END
  END w0_wd_in[104]
  PIN w0_wd_in[105]
    DIRECTION INPUT ;
    USE SIGNAL ;
    SHAPE ABUTMENT ;
    PORT
      LAYER met3 ;
      RECT 0.000 1284.370 0.900 1284.670 ;
    END
  END w0_wd_in[105]
  PIN w0_wd_in[106]
    DIRECTION INPUT ;
    USE SIGNAL ;
    SHAPE ABUTMENT ;
    PORT
      LAYER met3 ;
      RECT 0.000 1289.130 0.900 1289.430 ;
    END
  END w0_wd_in[106]
  PIN w0_wd_in[107]
    DIRECTION INPUT ;
    USE SIGNAL ;
    SHAPE ABUTMENT ;
    PORT
      LAYER met3 ;
      RECT 0.000 1293.890 0.900 1294.190 ;
    END
  END w0_wd_in[107]
  PIN w0_wd_in[108]
    DIRECTION INPUT ;
    USE SIGNAL ;
    SHAPE ABUTMENT ;
    PORT
      LAYER met3 ;
      RECT 0.000 1298.650 0.900 1298.950 ;
    END
  END w0_wd_in[108]
  PIN w0_wd_in[109]
    DIRECTION INPUT ;
    USE SIGNAL ;
    SHAPE ABUTMENT ;
    PORT
      LAYER met3 ;
      RECT 0.000 1303.410 0.900 1303.710 ;
    END
  END w0_wd_in[109]
  PIN w0_wd_in[110]
    DIRECTION INPUT ;
    USE SIGNAL ;
    SHAPE ABUTMENT ;
    PORT
      LAYER met3 ;
      RECT 0.000 1308.170 0.900 1308.470 ;
    END
  END w0_wd_in[110]
  PIN w0_wd_in[111]
    DIRECTION INPUT ;
    USE SIGNAL ;
    SHAPE ABUTMENT ;
    PORT
      LAYER met3 ;
      RECT 0.000 1312.930 0.900 1313.230 ;
    END
  END w0_wd_in[111]
  PIN w0_wd_in[112]
    DIRECTION INPUT ;
    USE SIGNAL ;
    SHAPE ABUTMENT ;
    PORT
      LAYER met3 ;
      RECT 0.000 1317.690 0.900 1317.990 ;
    END
  END w0_wd_in[112]
  PIN w0_wd_in[113]
    DIRECTION INPUT ;
    USE SIGNAL ;
    SHAPE ABUTMENT ;
    PORT
      LAYER met3 ;
      RECT 0.000 1322.450 0.900 1322.750 ;
    END
  END w0_wd_in[113]
  PIN w0_wd_in[114]
    DIRECTION INPUT ;
    USE SIGNAL ;
    SHAPE ABUTMENT ;
    PORT
      LAYER met3 ;
      RECT 0.000 1327.210 0.900 1327.510 ;
    END
  END w0_wd_in[114]
  PIN w0_wd_in[115]
    DIRECTION INPUT ;
    USE SIGNAL ;
    SHAPE ABUTMENT ;
    PORT
      LAYER met3 ;
      RECT 0.000 1331.970 0.900 1332.270 ;
    END
  END w0_wd_in[115]
  PIN w0_wd_in[116]
    DIRECTION INPUT ;
    USE SIGNAL ;
    SHAPE ABUTMENT ;
    PORT
      LAYER met3 ;
      RECT 0.000 1336.730 0.900 1337.030 ;
    END
  END w0_wd_in[116]
  PIN w0_wd_in[117]
    DIRECTION INPUT ;
    USE SIGNAL ;
    SHAPE ABUTMENT ;
    PORT
      LAYER met3 ;
      RECT 0.000 1341.490 0.900 1341.790 ;
    END
  END w0_wd_in[117]
  PIN w0_wd_in[118]
    DIRECTION INPUT ;
    USE SIGNAL ;
    SHAPE ABUTMENT ;
    PORT
      LAYER met3 ;
      RECT 0.000 1346.250 0.900 1346.550 ;
    END
  END w0_wd_in[118]
  PIN w0_wd_in[119]
    DIRECTION INPUT ;
    USE SIGNAL ;
    SHAPE ABUTMENT ;
    PORT
      LAYER met3 ;
      RECT 0.000 1351.010 0.900 1351.310 ;
    END
  END w0_wd_in[119]
  PIN w0_wd_in[120]
    DIRECTION INPUT ;
    USE SIGNAL ;
    SHAPE ABUTMENT ;
    PORT
      LAYER met3 ;
      RECT 0.000 1355.770 0.900 1356.070 ;
    END
  END w0_wd_in[120]
  PIN w0_wd_in[121]
    DIRECTION INPUT ;
    USE SIGNAL ;
    SHAPE ABUTMENT ;
    PORT
      LAYER met3 ;
      RECT 0.000 1360.530 0.900 1360.830 ;
    END
  END w0_wd_in[121]
  PIN w0_wd_in[122]
    DIRECTION INPUT ;
    USE SIGNAL ;
    SHAPE ABUTMENT ;
    PORT
      LAYER met3 ;
      RECT 0.000 1365.290 0.900 1365.590 ;
    END
  END w0_wd_in[122]
  PIN w0_wd_in[123]
    DIRECTION INPUT ;
    USE SIGNAL ;
    SHAPE ABUTMENT ;
    PORT
      LAYER met3 ;
      RECT 0.000 1370.050 0.900 1370.350 ;
    END
  END w0_wd_in[123]
  PIN w0_wd_in[124]
    DIRECTION INPUT ;
    USE SIGNAL ;
    SHAPE ABUTMENT ;
    PORT
      LAYER met3 ;
      RECT 0.000 1374.810 0.900 1375.110 ;
    END
  END w0_wd_in[124]
  PIN w0_wd_in[125]
    DIRECTION INPUT ;
    USE SIGNAL ;
    SHAPE ABUTMENT ;
    PORT
      LAYER met3 ;
      RECT 0.000 1379.570 0.900 1379.870 ;
    END
  END w0_wd_in[125]
  PIN w0_wd_in[126]
    DIRECTION INPUT ;
    USE SIGNAL ;
    SHAPE ABUTMENT ;
    PORT
      LAYER met3 ;
      RECT 0.000 1384.330 0.900 1384.630 ;
    END
  END w0_wd_in[126]
  PIN w0_wd_in[127]
    DIRECTION INPUT ;
    USE SIGNAL ;
    SHAPE ABUTMENT ;
    PORT
      LAYER met3 ;
      RECT 0.000 1389.090 0.900 1389.390 ;
    END
  END w0_wd_in[127]
  PIN w0_wd_in[128]
    DIRECTION INPUT ;
    USE SIGNAL ;
    SHAPE ABUTMENT ;
    PORT
      LAYER met3 ;
      RECT 0.000 1393.850 0.900 1394.150 ;
    END
  END w0_wd_in[128]
  PIN w0_wd_in[129]
    DIRECTION INPUT ;
    USE SIGNAL ;
    SHAPE ABUTMENT ;
    PORT
      LAYER met3 ;
      RECT 0.000 1398.610 0.900 1398.910 ;
    END
  END w0_wd_in[129]
  PIN w0_wd_in[130]
    DIRECTION INPUT ;
    USE SIGNAL ;
    SHAPE ABUTMENT ;
    PORT
      LAYER met3 ;
      RECT 0.000 1403.370 0.900 1403.670 ;
    END
  END w0_wd_in[130]
  PIN w0_wd_in[131]
    DIRECTION INPUT ;
    USE SIGNAL ;
    SHAPE ABUTMENT ;
    PORT
      LAYER met3 ;
      RECT 0.000 1408.130 0.900 1408.430 ;
    END
  END w0_wd_in[131]
  PIN w0_wd_in[132]
    DIRECTION INPUT ;
    USE SIGNAL ;
    SHAPE ABUTMENT ;
    PORT
      LAYER met3 ;
      RECT 0.000 1412.890 0.900 1413.190 ;
    END
  END w0_wd_in[132]
  PIN w0_wd_in[133]
    DIRECTION INPUT ;
    USE SIGNAL ;
    SHAPE ABUTMENT ;
    PORT
      LAYER met3 ;
      RECT 0.000 1417.650 0.900 1417.950 ;
    END
  END w0_wd_in[133]
  PIN w0_wd_in[134]
    DIRECTION INPUT ;
    USE SIGNAL ;
    SHAPE ABUTMENT ;
    PORT
      LAYER met3 ;
      RECT 0.000 1422.410 0.900 1422.710 ;
    END
  END w0_wd_in[134]
  PIN w0_wd_in[135]
    DIRECTION INPUT ;
    USE SIGNAL ;
    SHAPE ABUTMENT ;
    PORT
      LAYER met3 ;
      RECT 0.000 1427.170 0.900 1427.470 ;
    END
  END w0_wd_in[135]
  PIN w0_wd_in[136]
    DIRECTION INPUT ;
    USE SIGNAL ;
    SHAPE ABUTMENT ;
    PORT
      LAYER met3 ;
      RECT 0.000 1431.930 0.900 1432.230 ;
    END
  END w0_wd_in[136]
  PIN w0_wd_in[137]
    DIRECTION INPUT ;
    USE SIGNAL ;
    SHAPE ABUTMENT ;
    PORT
      LAYER met3 ;
      RECT 0.000 1436.690 0.900 1436.990 ;
    END
  END w0_wd_in[137]
  PIN w0_wd_in[138]
    DIRECTION INPUT ;
    USE SIGNAL ;
    SHAPE ABUTMENT ;
    PORT
      LAYER met3 ;
      RECT 0.000 1441.450 0.900 1441.750 ;
    END
  END w0_wd_in[138]
  PIN w0_wd_in[139]
    DIRECTION INPUT ;
    USE SIGNAL ;
    SHAPE ABUTMENT ;
    PORT
      LAYER met3 ;
      RECT 0.000 1446.210 0.900 1446.510 ;
    END
  END w0_wd_in[139]
  PIN w0_wd_in[140]
    DIRECTION INPUT ;
    USE SIGNAL ;
    SHAPE ABUTMENT ;
    PORT
      LAYER met3 ;
      RECT 0.000 1450.970 0.900 1451.270 ;
    END
  END w0_wd_in[140]
  PIN w0_wd_in[141]
    DIRECTION INPUT ;
    USE SIGNAL ;
    SHAPE ABUTMENT ;
    PORT
      LAYER met3 ;
      RECT 0.000 1455.730 0.900 1456.030 ;
    END
  END w0_wd_in[141]
  PIN w0_wd_in[142]
    DIRECTION INPUT ;
    USE SIGNAL ;
    SHAPE ABUTMENT ;
    PORT
      LAYER met3 ;
      RECT 0.000 1460.490 0.900 1460.790 ;
    END
  END w0_wd_in[142]
  PIN w0_wd_in[143]
    DIRECTION INPUT ;
    USE SIGNAL ;
    SHAPE ABUTMENT ;
    PORT
      LAYER met3 ;
      RECT 0.000 1465.250 0.900 1465.550 ;
    END
  END w0_wd_in[143]
  PIN w0_wd_in[144]
    DIRECTION INPUT ;
    USE SIGNAL ;
    SHAPE ABUTMENT ;
    PORT
      LAYER met3 ;
      RECT 0.000 1470.010 0.900 1470.310 ;
    END
  END w0_wd_in[144]
  PIN w0_wd_in[145]
    DIRECTION INPUT ;
    USE SIGNAL ;
    SHAPE ABUTMENT ;
    PORT
      LAYER met3 ;
      RECT 0.000 1474.770 0.900 1475.070 ;
    END
  END w0_wd_in[145]
  PIN w0_wd_in[146]
    DIRECTION INPUT ;
    USE SIGNAL ;
    SHAPE ABUTMENT ;
    PORT
      LAYER met3 ;
      RECT 0.000 1479.530 0.900 1479.830 ;
    END
  END w0_wd_in[146]
  PIN w0_wd_in[147]
    DIRECTION INPUT ;
    USE SIGNAL ;
    SHAPE ABUTMENT ;
    PORT
      LAYER met3 ;
      RECT 0.000 1484.290 0.900 1484.590 ;
    END
  END w0_wd_in[147]
  PIN w0_wd_in[148]
    DIRECTION INPUT ;
    USE SIGNAL ;
    SHAPE ABUTMENT ;
    PORT
      LAYER met3 ;
      RECT 0.000 1489.050 0.900 1489.350 ;
    END
  END w0_wd_in[148]
  PIN w0_wd_in[149]
    DIRECTION INPUT ;
    USE SIGNAL ;
    SHAPE ABUTMENT ;
    PORT
      LAYER met3 ;
      RECT 0.000 1493.810 0.900 1494.110 ;
    END
  END w0_wd_in[149]
  PIN w0_wd_in[150]
    DIRECTION INPUT ;
    USE SIGNAL ;
    SHAPE ABUTMENT ;
    PORT
      LAYER met3 ;
      RECT 0.000 1498.570 0.900 1498.870 ;
    END
  END w0_wd_in[150]
  PIN w0_wd_in[151]
    DIRECTION INPUT ;
    USE SIGNAL ;
    SHAPE ABUTMENT ;
    PORT
      LAYER met3 ;
      RECT 0.000 1503.330 0.900 1503.630 ;
    END
  END w0_wd_in[151]
  PIN w0_wd_in[152]
    DIRECTION INPUT ;
    USE SIGNAL ;
    SHAPE ABUTMENT ;
    PORT
      LAYER met3 ;
      RECT 0.000 1508.090 0.900 1508.390 ;
    END
  END w0_wd_in[152]
  PIN w0_wd_in[153]
    DIRECTION INPUT ;
    USE SIGNAL ;
    SHAPE ABUTMENT ;
    PORT
      LAYER met3 ;
      RECT 0.000 1512.850 0.900 1513.150 ;
    END
  END w0_wd_in[153]
  PIN w0_wd_in[154]
    DIRECTION INPUT ;
    USE SIGNAL ;
    SHAPE ABUTMENT ;
    PORT
      LAYER met3 ;
      RECT 0.000 1517.610 0.900 1517.910 ;
    END
  END w0_wd_in[154]
  PIN w0_wd_in[155]
    DIRECTION INPUT ;
    USE SIGNAL ;
    SHAPE ABUTMENT ;
    PORT
      LAYER met3 ;
      RECT 0.000 1522.370 0.900 1522.670 ;
    END
  END w0_wd_in[155]
  PIN w0_wd_in[156]
    DIRECTION INPUT ;
    USE SIGNAL ;
    SHAPE ABUTMENT ;
    PORT
      LAYER met3 ;
      RECT 0.000 1527.130 0.900 1527.430 ;
    END
  END w0_wd_in[156]
  PIN w0_wd_in[157]
    DIRECTION INPUT ;
    USE SIGNAL ;
    SHAPE ABUTMENT ;
    PORT
      LAYER met3 ;
      RECT 0.000 1531.890 0.900 1532.190 ;
    END
  END w0_wd_in[157]
  PIN w0_wd_in[158]
    DIRECTION INPUT ;
    USE SIGNAL ;
    SHAPE ABUTMENT ;
    PORT
      LAYER met3 ;
      RECT 0.000 1536.650 0.900 1536.950 ;
    END
  END w0_wd_in[158]
  PIN w0_wd_in[159]
    DIRECTION INPUT ;
    USE SIGNAL ;
    SHAPE ABUTMENT ;
    PORT
      LAYER met3 ;
      RECT 0.000 1541.410 0.900 1541.710 ;
    END
  END w0_wd_in[159]
  PIN w0_wd_in[160]
    DIRECTION INPUT ;
    USE SIGNAL ;
    SHAPE ABUTMENT ;
    PORT
      LAYER met3 ;
      RECT 0.000 1546.170 0.900 1546.470 ;
    END
  END w0_wd_in[160]
  PIN w0_wd_in[161]
    DIRECTION INPUT ;
    USE SIGNAL ;
    SHAPE ABUTMENT ;
    PORT
      LAYER met3 ;
      RECT 0.000 1550.930 0.900 1551.230 ;
    END
  END w0_wd_in[161]
  PIN w0_wd_in[162]
    DIRECTION INPUT ;
    USE SIGNAL ;
    SHAPE ABUTMENT ;
    PORT
      LAYER met3 ;
      RECT 0.000 1555.690 0.900 1555.990 ;
    END
  END w0_wd_in[162]
  PIN w0_wd_in[163]
    DIRECTION INPUT ;
    USE SIGNAL ;
    SHAPE ABUTMENT ;
    PORT
      LAYER met3 ;
      RECT 0.000 1560.450 0.900 1560.750 ;
    END
  END w0_wd_in[163]
  PIN w0_wd_in[164]
    DIRECTION INPUT ;
    USE SIGNAL ;
    SHAPE ABUTMENT ;
    PORT
      LAYER met3 ;
      RECT 1670.740 779.810 1671.640 780.110 ;
    END
  END w0_wd_in[164]
  PIN w0_wd_in[165]
    DIRECTION INPUT ;
    USE SIGNAL ;
    SHAPE ABUTMENT ;
    PORT
      LAYER met3 ;
      RECT 1670.740 784.570 1671.640 784.870 ;
    END
  END w0_wd_in[165]
  PIN w0_wd_in[166]
    DIRECTION INPUT ;
    USE SIGNAL ;
    SHAPE ABUTMENT ;
    PORT
      LAYER met3 ;
      RECT 1670.740 789.330 1671.640 789.630 ;
    END
  END w0_wd_in[166]
  PIN w0_wd_in[167]
    DIRECTION INPUT ;
    USE SIGNAL ;
    SHAPE ABUTMENT ;
    PORT
      LAYER met3 ;
      RECT 1670.740 794.090 1671.640 794.390 ;
    END
  END w0_wd_in[167]
  PIN w0_wd_in[168]
    DIRECTION INPUT ;
    USE SIGNAL ;
    SHAPE ABUTMENT ;
    PORT
      LAYER met3 ;
      RECT 1670.740 798.850 1671.640 799.150 ;
    END
  END w0_wd_in[168]
  PIN w0_wd_in[169]
    DIRECTION INPUT ;
    USE SIGNAL ;
    SHAPE ABUTMENT ;
    PORT
      LAYER met3 ;
      RECT 1670.740 803.610 1671.640 803.910 ;
    END
  END w0_wd_in[169]
  PIN w0_wd_in[170]
    DIRECTION INPUT ;
    USE SIGNAL ;
    SHAPE ABUTMENT ;
    PORT
      LAYER met3 ;
      RECT 1670.740 808.370 1671.640 808.670 ;
    END
  END w0_wd_in[170]
  PIN w0_wd_in[171]
    DIRECTION INPUT ;
    USE SIGNAL ;
    SHAPE ABUTMENT ;
    PORT
      LAYER met3 ;
      RECT 1670.740 813.130 1671.640 813.430 ;
    END
  END w0_wd_in[171]
  PIN w0_wd_in[172]
    DIRECTION INPUT ;
    USE SIGNAL ;
    SHAPE ABUTMENT ;
    PORT
      LAYER met3 ;
      RECT 1670.740 817.890 1671.640 818.190 ;
    END
  END w0_wd_in[172]
  PIN w0_wd_in[173]
    DIRECTION INPUT ;
    USE SIGNAL ;
    SHAPE ABUTMENT ;
    PORT
      LAYER met3 ;
      RECT 1670.740 822.650 1671.640 822.950 ;
    END
  END w0_wd_in[173]
  PIN w0_wd_in[174]
    DIRECTION INPUT ;
    USE SIGNAL ;
    SHAPE ABUTMENT ;
    PORT
      LAYER met3 ;
      RECT 1670.740 827.410 1671.640 827.710 ;
    END
  END w0_wd_in[174]
  PIN w0_wd_in[175]
    DIRECTION INPUT ;
    USE SIGNAL ;
    SHAPE ABUTMENT ;
    PORT
      LAYER met3 ;
      RECT 1670.740 832.170 1671.640 832.470 ;
    END
  END w0_wd_in[175]
  PIN w0_wd_in[176]
    DIRECTION INPUT ;
    USE SIGNAL ;
    SHAPE ABUTMENT ;
    PORT
      LAYER met3 ;
      RECT 1670.740 836.930 1671.640 837.230 ;
    END
  END w0_wd_in[176]
  PIN w0_wd_in[177]
    DIRECTION INPUT ;
    USE SIGNAL ;
    SHAPE ABUTMENT ;
    PORT
      LAYER met3 ;
      RECT 1670.740 841.690 1671.640 841.990 ;
    END
  END w0_wd_in[177]
  PIN w0_wd_in[178]
    DIRECTION INPUT ;
    USE SIGNAL ;
    SHAPE ABUTMENT ;
    PORT
      LAYER met3 ;
      RECT 1670.740 846.450 1671.640 846.750 ;
    END
  END w0_wd_in[178]
  PIN w0_wd_in[179]
    DIRECTION INPUT ;
    USE SIGNAL ;
    SHAPE ABUTMENT ;
    PORT
      LAYER met3 ;
      RECT 1670.740 851.210 1671.640 851.510 ;
    END
  END w0_wd_in[179]
  PIN w0_wd_in[180]
    DIRECTION INPUT ;
    USE SIGNAL ;
    SHAPE ABUTMENT ;
    PORT
      LAYER met3 ;
      RECT 1670.740 855.970 1671.640 856.270 ;
    END
  END w0_wd_in[180]
  PIN w0_wd_in[181]
    DIRECTION INPUT ;
    USE SIGNAL ;
    SHAPE ABUTMENT ;
    PORT
      LAYER met3 ;
      RECT 1670.740 860.730 1671.640 861.030 ;
    END
  END w0_wd_in[181]
  PIN w0_wd_in[182]
    DIRECTION INPUT ;
    USE SIGNAL ;
    SHAPE ABUTMENT ;
    PORT
      LAYER met3 ;
      RECT 1670.740 865.490 1671.640 865.790 ;
    END
  END w0_wd_in[182]
  PIN w0_wd_in[183]
    DIRECTION INPUT ;
    USE SIGNAL ;
    SHAPE ABUTMENT ;
    PORT
      LAYER met3 ;
      RECT 1670.740 870.250 1671.640 870.550 ;
    END
  END w0_wd_in[183]
  PIN w0_wd_in[184]
    DIRECTION INPUT ;
    USE SIGNAL ;
    SHAPE ABUTMENT ;
    PORT
      LAYER met3 ;
      RECT 1670.740 875.010 1671.640 875.310 ;
    END
  END w0_wd_in[184]
  PIN w0_wd_in[185]
    DIRECTION INPUT ;
    USE SIGNAL ;
    SHAPE ABUTMENT ;
    PORT
      LAYER met3 ;
      RECT 1670.740 879.770 1671.640 880.070 ;
    END
  END w0_wd_in[185]
  PIN w0_wd_in[186]
    DIRECTION INPUT ;
    USE SIGNAL ;
    SHAPE ABUTMENT ;
    PORT
      LAYER met3 ;
      RECT 1670.740 884.530 1671.640 884.830 ;
    END
  END w0_wd_in[186]
  PIN w0_wd_in[187]
    DIRECTION INPUT ;
    USE SIGNAL ;
    SHAPE ABUTMENT ;
    PORT
      LAYER met3 ;
      RECT 1670.740 889.290 1671.640 889.590 ;
    END
  END w0_wd_in[187]
  PIN w0_wd_in[188]
    DIRECTION INPUT ;
    USE SIGNAL ;
    SHAPE ABUTMENT ;
    PORT
      LAYER met3 ;
      RECT 1670.740 894.050 1671.640 894.350 ;
    END
  END w0_wd_in[188]
  PIN w0_wd_in[189]
    DIRECTION INPUT ;
    USE SIGNAL ;
    SHAPE ABUTMENT ;
    PORT
      LAYER met3 ;
      RECT 1670.740 898.810 1671.640 899.110 ;
    END
  END w0_wd_in[189]
  PIN w0_wd_in[190]
    DIRECTION INPUT ;
    USE SIGNAL ;
    SHAPE ABUTMENT ;
    PORT
      LAYER met3 ;
      RECT 1670.740 903.570 1671.640 903.870 ;
    END
  END w0_wd_in[190]
  PIN w0_wd_in[191]
    DIRECTION INPUT ;
    USE SIGNAL ;
    SHAPE ABUTMENT ;
    PORT
      LAYER met3 ;
      RECT 1670.740 908.330 1671.640 908.630 ;
    END
  END w0_wd_in[191]
  PIN w0_wd_in[192]
    DIRECTION INPUT ;
    USE SIGNAL ;
    SHAPE ABUTMENT ;
    PORT
      LAYER met3 ;
      RECT 1670.740 913.090 1671.640 913.390 ;
    END
  END w0_wd_in[192]
  PIN w0_wd_in[193]
    DIRECTION INPUT ;
    USE SIGNAL ;
    SHAPE ABUTMENT ;
    PORT
      LAYER met3 ;
      RECT 1670.740 917.850 1671.640 918.150 ;
    END
  END w0_wd_in[193]
  PIN w0_wd_in[194]
    DIRECTION INPUT ;
    USE SIGNAL ;
    SHAPE ABUTMENT ;
    PORT
      LAYER met3 ;
      RECT 1670.740 922.610 1671.640 922.910 ;
    END
  END w0_wd_in[194]
  PIN w0_wd_in[195]
    DIRECTION INPUT ;
    USE SIGNAL ;
    SHAPE ABUTMENT ;
    PORT
      LAYER met3 ;
      RECT 1670.740 927.370 1671.640 927.670 ;
    END
  END w0_wd_in[195]
  PIN w0_wd_in[196]
    DIRECTION INPUT ;
    USE SIGNAL ;
    SHAPE ABUTMENT ;
    PORT
      LAYER met3 ;
      RECT 1670.740 932.130 1671.640 932.430 ;
    END
  END w0_wd_in[196]
  PIN w0_wd_in[197]
    DIRECTION INPUT ;
    USE SIGNAL ;
    SHAPE ABUTMENT ;
    PORT
      LAYER met3 ;
      RECT 1670.740 936.890 1671.640 937.190 ;
    END
  END w0_wd_in[197]
  PIN w0_wd_in[198]
    DIRECTION INPUT ;
    USE SIGNAL ;
    SHAPE ABUTMENT ;
    PORT
      LAYER met3 ;
      RECT 1670.740 941.650 1671.640 941.950 ;
    END
  END w0_wd_in[198]
  PIN w0_wd_in[199]
    DIRECTION INPUT ;
    USE SIGNAL ;
    SHAPE ABUTMENT ;
    PORT
      LAYER met3 ;
      RECT 1670.740 946.410 1671.640 946.710 ;
    END
  END w0_wd_in[199]
  PIN w0_wd_in[200]
    DIRECTION INPUT ;
    USE SIGNAL ;
    SHAPE ABUTMENT ;
    PORT
      LAYER met3 ;
      RECT 1670.740 951.170 1671.640 951.470 ;
    END
  END w0_wd_in[200]
  PIN w0_wd_in[201]
    DIRECTION INPUT ;
    USE SIGNAL ;
    SHAPE ABUTMENT ;
    PORT
      LAYER met3 ;
      RECT 1670.740 955.930 1671.640 956.230 ;
    END
  END w0_wd_in[201]
  PIN w0_wd_in[202]
    DIRECTION INPUT ;
    USE SIGNAL ;
    SHAPE ABUTMENT ;
    PORT
      LAYER met3 ;
      RECT 1670.740 960.690 1671.640 960.990 ;
    END
  END w0_wd_in[202]
  PIN w0_wd_in[203]
    DIRECTION INPUT ;
    USE SIGNAL ;
    SHAPE ABUTMENT ;
    PORT
      LAYER met3 ;
      RECT 1670.740 965.450 1671.640 965.750 ;
    END
  END w0_wd_in[203]
  PIN w0_wd_in[204]
    DIRECTION INPUT ;
    USE SIGNAL ;
    SHAPE ABUTMENT ;
    PORT
      LAYER met3 ;
      RECT 1670.740 970.210 1671.640 970.510 ;
    END
  END w0_wd_in[204]
  PIN w0_wd_in[205]
    DIRECTION INPUT ;
    USE SIGNAL ;
    SHAPE ABUTMENT ;
    PORT
      LAYER met3 ;
      RECT 1670.740 974.970 1671.640 975.270 ;
    END
  END w0_wd_in[205]
  PIN w0_wd_in[206]
    DIRECTION INPUT ;
    USE SIGNAL ;
    SHAPE ABUTMENT ;
    PORT
      LAYER met3 ;
      RECT 1670.740 979.730 1671.640 980.030 ;
    END
  END w0_wd_in[206]
  PIN w0_wd_in[207]
    DIRECTION INPUT ;
    USE SIGNAL ;
    SHAPE ABUTMENT ;
    PORT
      LAYER met3 ;
      RECT 1670.740 984.490 1671.640 984.790 ;
    END
  END w0_wd_in[207]
  PIN w0_wd_in[208]
    DIRECTION INPUT ;
    USE SIGNAL ;
    SHAPE ABUTMENT ;
    PORT
      LAYER met3 ;
      RECT 1670.740 989.250 1671.640 989.550 ;
    END
  END w0_wd_in[208]
  PIN w0_wd_in[209]
    DIRECTION INPUT ;
    USE SIGNAL ;
    SHAPE ABUTMENT ;
    PORT
      LAYER met3 ;
      RECT 1670.740 994.010 1671.640 994.310 ;
    END
  END w0_wd_in[209]
  PIN w0_wd_in[210]
    DIRECTION INPUT ;
    USE SIGNAL ;
    SHAPE ABUTMENT ;
    PORT
      LAYER met3 ;
      RECT 1670.740 998.770 1671.640 999.070 ;
    END
  END w0_wd_in[210]
  PIN w0_wd_in[211]
    DIRECTION INPUT ;
    USE SIGNAL ;
    SHAPE ABUTMENT ;
    PORT
      LAYER met3 ;
      RECT 1670.740 1003.530 1671.640 1003.830 ;
    END
  END w0_wd_in[211]
  PIN w0_wd_in[212]
    DIRECTION INPUT ;
    USE SIGNAL ;
    SHAPE ABUTMENT ;
    PORT
      LAYER met3 ;
      RECT 1670.740 1008.290 1671.640 1008.590 ;
    END
  END w0_wd_in[212]
  PIN w0_wd_in[213]
    DIRECTION INPUT ;
    USE SIGNAL ;
    SHAPE ABUTMENT ;
    PORT
      LAYER met3 ;
      RECT 1670.740 1013.050 1671.640 1013.350 ;
    END
  END w0_wd_in[213]
  PIN w0_wd_in[214]
    DIRECTION INPUT ;
    USE SIGNAL ;
    SHAPE ABUTMENT ;
    PORT
      LAYER met3 ;
      RECT 1670.740 1017.810 1671.640 1018.110 ;
    END
  END w0_wd_in[214]
  PIN w0_wd_in[215]
    DIRECTION INPUT ;
    USE SIGNAL ;
    SHAPE ABUTMENT ;
    PORT
      LAYER met3 ;
      RECT 1670.740 1022.570 1671.640 1022.870 ;
    END
  END w0_wd_in[215]
  PIN w0_wd_in[216]
    DIRECTION INPUT ;
    USE SIGNAL ;
    SHAPE ABUTMENT ;
    PORT
      LAYER met3 ;
      RECT 1670.740 1027.330 1671.640 1027.630 ;
    END
  END w0_wd_in[216]
  PIN w0_wd_in[217]
    DIRECTION INPUT ;
    USE SIGNAL ;
    SHAPE ABUTMENT ;
    PORT
      LAYER met3 ;
      RECT 1670.740 1032.090 1671.640 1032.390 ;
    END
  END w0_wd_in[217]
  PIN w0_wd_in[218]
    DIRECTION INPUT ;
    USE SIGNAL ;
    SHAPE ABUTMENT ;
    PORT
      LAYER met3 ;
      RECT 1670.740 1036.850 1671.640 1037.150 ;
    END
  END w0_wd_in[218]
  PIN w0_wd_in[219]
    DIRECTION INPUT ;
    USE SIGNAL ;
    SHAPE ABUTMENT ;
    PORT
      LAYER met3 ;
      RECT 1670.740 1041.610 1671.640 1041.910 ;
    END
  END w0_wd_in[219]
  PIN w0_wd_in[220]
    DIRECTION INPUT ;
    USE SIGNAL ;
    SHAPE ABUTMENT ;
    PORT
      LAYER met3 ;
      RECT 1670.740 1046.370 1671.640 1046.670 ;
    END
  END w0_wd_in[220]
  PIN w0_wd_in[221]
    DIRECTION INPUT ;
    USE SIGNAL ;
    SHAPE ABUTMENT ;
    PORT
      LAYER met3 ;
      RECT 1670.740 1051.130 1671.640 1051.430 ;
    END
  END w0_wd_in[221]
  PIN w0_wd_in[222]
    DIRECTION INPUT ;
    USE SIGNAL ;
    SHAPE ABUTMENT ;
    PORT
      LAYER met3 ;
      RECT 1670.740 1055.890 1671.640 1056.190 ;
    END
  END w0_wd_in[222]
  PIN w0_wd_in[223]
    DIRECTION INPUT ;
    USE SIGNAL ;
    SHAPE ABUTMENT ;
    PORT
      LAYER met3 ;
      RECT 1670.740 1060.650 1671.640 1060.950 ;
    END
  END w0_wd_in[223]
  PIN w0_wd_in[224]
    DIRECTION INPUT ;
    USE SIGNAL ;
    SHAPE ABUTMENT ;
    PORT
      LAYER met3 ;
      RECT 1670.740 1065.410 1671.640 1065.710 ;
    END
  END w0_wd_in[224]
  PIN w0_wd_in[225]
    DIRECTION INPUT ;
    USE SIGNAL ;
    SHAPE ABUTMENT ;
    PORT
      LAYER met3 ;
      RECT 1670.740 1070.170 1671.640 1070.470 ;
    END
  END w0_wd_in[225]
  PIN w0_wd_in[226]
    DIRECTION INPUT ;
    USE SIGNAL ;
    SHAPE ABUTMENT ;
    PORT
      LAYER met3 ;
      RECT 1670.740 1074.930 1671.640 1075.230 ;
    END
  END w0_wd_in[226]
  PIN w0_wd_in[227]
    DIRECTION INPUT ;
    USE SIGNAL ;
    SHAPE ABUTMENT ;
    PORT
      LAYER met3 ;
      RECT 1670.740 1079.690 1671.640 1079.990 ;
    END
  END w0_wd_in[227]
  PIN w0_wd_in[228]
    DIRECTION INPUT ;
    USE SIGNAL ;
    SHAPE ABUTMENT ;
    PORT
      LAYER met3 ;
      RECT 1670.740 1084.450 1671.640 1084.750 ;
    END
  END w0_wd_in[228]
  PIN w0_wd_in[229]
    DIRECTION INPUT ;
    USE SIGNAL ;
    SHAPE ABUTMENT ;
    PORT
      LAYER met3 ;
      RECT 1670.740 1089.210 1671.640 1089.510 ;
    END
  END w0_wd_in[229]
  PIN w0_wd_in[230]
    DIRECTION INPUT ;
    USE SIGNAL ;
    SHAPE ABUTMENT ;
    PORT
      LAYER met3 ;
      RECT 1670.740 1093.970 1671.640 1094.270 ;
    END
  END w0_wd_in[230]
  PIN w0_wd_in[231]
    DIRECTION INPUT ;
    USE SIGNAL ;
    SHAPE ABUTMENT ;
    PORT
      LAYER met3 ;
      RECT 1670.740 1098.730 1671.640 1099.030 ;
    END
  END w0_wd_in[231]
  PIN w0_wd_in[232]
    DIRECTION INPUT ;
    USE SIGNAL ;
    SHAPE ABUTMENT ;
    PORT
      LAYER met3 ;
      RECT 1670.740 1103.490 1671.640 1103.790 ;
    END
  END w0_wd_in[232]
  PIN w0_wd_in[233]
    DIRECTION INPUT ;
    USE SIGNAL ;
    SHAPE ABUTMENT ;
    PORT
      LAYER met3 ;
      RECT 1670.740 1108.250 1671.640 1108.550 ;
    END
  END w0_wd_in[233]
  PIN w0_wd_in[234]
    DIRECTION INPUT ;
    USE SIGNAL ;
    SHAPE ABUTMENT ;
    PORT
      LAYER met3 ;
      RECT 1670.740 1113.010 1671.640 1113.310 ;
    END
  END w0_wd_in[234]
  PIN w0_wd_in[235]
    DIRECTION INPUT ;
    USE SIGNAL ;
    SHAPE ABUTMENT ;
    PORT
      LAYER met3 ;
      RECT 1670.740 1117.770 1671.640 1118.070 ;
    END
  END w0_wd_in[235]
  PIN w0_wd_in[236]
    DIRECTION INPUT ;
    USE SIGNAL ;
    SHAPE ABUTMENT ;
    PORT
      LAYER met3 ;
      RECT 1670.740 1122.530 1671.640 1122.830 ;
    END
  END w0_wd_in[236]
  PIN w0_wd_in[237]
    DIRECTION INPUT ;
    USE SIGNAL ;
    SHAPE ABUTMENT ;
    PORT
      LAYER met3 ;
      RECT 1670.740 1127.290 1671.640 1127.590 ;
    END
  END w0_wd_in[237]
  PIN w0_wd_in[238]
    DIRECTION INPUT ;
    USE SIGNAL ;
    SHAPE ABUTMENT ;
    PORT
      LAYER met3 ;
      RECT 1670.740 1132.050 1671.640 1132.350 ;
    END
  END w0_wd_in[238]
  PIN w0_wd_in[239]
    DIRECTION INPUT ;
    USE SIGNAL ;
    SHAPE ABUTMENT ;
    PORT
      LAYER met3 ;
      RECT 1670.740 1136.810 1671.640 1137.110 ;
    END
  END w0_wd_in[239]
  PIN w0_wd_in[240]
    DIRECTION INPUT ;
    USE SIGNAL ;
    SHAPE ABUTMENT ;
    PORT
      LAYER met3 ;
      RECT 1670.740 1141.570 1671.640 1141.870 ;
    END
  END w0_wd_in[240]
  PIN w0_wd_in[241]
    DIRECTION INPUT ;
    USE SIGNAL ;
    SHAPE ABUTMENT ;
    PORT
      LAYER met3 ;
      RECT 1670.740 1146.330 1671.640 1146.630 ;
    END
  END w0_wd_in[241]
  PIN w0_wd_in[242]
    DIRECTION INPUT ;
    USE SIGNAL ;
    SHAPE ABUTMENT ;
    PORT
      LAYER met3 ;
      RECT 1670.740 1151.090 1671.640 1151.390 ;
    END
  END w0_wd_in[242]
  PIN w0_wd_in[243]
    DIRECTION INPUT ;
    USE SIGNAL ;
    SHAPE ABUTMENT ;
    PORT
      LAYER met3 ;
      RECT 1670.740 1155.850 1671.640 1156.150 ;
    END
  END w0_wd_in[243]
  PIN w0_wd_in[244]
    DIRECTION INPUT ;
    USE SIGNAL ;
    SHAPE ABUTMENT ;
    PORT
      LAYER met3 ;
      RECT 1670.740 1160.610 1671.640 1160.910 ;
    END
  END w0_wd_in[244]
  PIN w0_wd_in[245]
    DIRECTION INPUT ;
    USE SIGNAL ;
    SHAPE ABUTMENT ;
    PORT
      LAYER met3 ;
      RECT 1670.740 1165.370 1671.640 1165.670 ;
    END
  END w0_wd_in[245]
  PIN w0_wd_in[246]
    DIRECTION INPUT ;
    USE SIGNAL ;
    SHAPE ABUTMENT ;
    PORT
      LAYER met3 ;
      RECT 1670.740 1170.130 1671.640 1170.430 ;
    END
  END w0_wd_in[246]
  PIN w0_wd_in[247]
    DIRECTION INPUT ;
    USE SIGNAL ;
    SHAPE ABUTMENT ;
    PORT
      LAYER met3 ;
      RECT 1670.740 1174.890 1671.640 1175.190 ;
    END
  END w0_wd_in[247]
  PIN w0_wd_in[248]
    DIRECTION INPUT ;
    USE SIGNAL ;
    SHAPE ABUTMENT ;
    PORT
      LAYER met3 ;
      RECT 1670.740 1179.650 1671.640 1179.950 ;
    END
  END w0_wd_in[248]
  PIN w0_wd_in[249]
    DIRECTION INPUT ;
    USE SIGNAL ;
    SHAPE ABUTMENT ;
    PORT
      LAYER met3 ;
      RECT 1670.740 1184.410 1671.640 1184.710 ;
    END
  END w0_wd_in[249]
  PIN w0_wd_in[250]
    DIRECTION INPUT ;
    USE SIGNAL ;
    SHAPE ABUTMENT ;
    PORT
      LAYER met3 ;
      RECT 1670.740 1189.170 1671.640 1189.470 ;
    END
  END w0_wd_in[250]
  PIN w0_wd_in[251]
    DIRECTION INPUT ;
    USE SIGNAL ;
    SHAPE ABUTMENT ;
    PORT
      LAYER met3 ;
      RECT 1670.740 1193.930 1671.640 1194.230 ;
    END
  END w0_wd_in[251]
  PIN w0_wd_in[252]
    DIRECTION INPUT ;
    USE SIGNAL ;
    SHAPE ABUTMENT ;
    PORT
      LAYER met3 ;
      RECT 1670.740 1198.690 1671.640 1198.990 ;
    END
  END w0_wd_in[252]
  PIN w0_wd_in[253]
    DIRECTION INPUT ;
    USE SIGNAL ;
    SHAPE ABUTMENT ;
    PORT
      LAYER met3 ;
      RECT 1670.740 1203.450 1671.640 1203.750 ;
    END
  END w0_wd_in[253]
  PIN w0_wd_in[254]
    DIRECTION INPUT ;
    USE SIGNAL ;
    SHAPE ABUTMENT ;
    PORT
      LAYER met3 ;
      RECT 1670.740 1208.210 1671.640 1208.510 ;
    END
  END w0_wd_in[254]
  PIN w0_wd_in[255]
    DIRECTION INPUT ;
    USE SIGNAL ;
    SHAPE ABUTMENT ;
    PORT
      LAYER met3 ;
      RECT 1670.740 1212.970 1671.640 1213.270 ;
    END
  END w0_wd_in[255]
  PIN w0_wd_in[256]
    DIRECTION INPUT ;
    USE SIGNAL ;
    SHAPE ABUTMENT ;
    PORT
      LAYER met3 ;
      RECT 1670.740 1217.730 1671.640 1218.030 ;
    END
  END w0_wd_in[256]
  PIN w0_wd_in[257]
    DIRECTION INPUT ;
    USE SIGNAL ;
    SHAPE ABUTMENT ;
    PORT
      LAYER met3 ;
      RECT 1670.740 1222.490 1671.640 1222.790 ;
    END
  END w0_wd_in[257]
  PIN w0_wd_in[258]
    DIRECTION INPUT ;
    USE SIGNAL ;
    SHAPE ABUTMENT ;
    PORT
      LAYER met3 ;
      RECT 1670.740 1227.250 1671.640 1227.550 ;
    END
  END w0_wd_in[258]
  PIN w0_wd_in[259]
    DIRECTION INPUT ;
    USE SIGNAL ;
    SHAPE ABUTMENT ;
    PORT
      LAYER met3 ;
      RECT 1670.740 1232.010 1671.640 1232.310 ;
    END
  END w0_wd_in[259]
  PIN w0_wd_in[260]
    DIRECTION INPUT ;
    USE SIGNAL ;
    SHAPE ABUTMENT ;
    PORT
      LAYER met3 ;
      RECT 1670.740 1236.770 1671.640 1237.070 ;
    END
  END w0_wd_in[260]
  PIN w0_wd_in[261]
    DIRECTION INPUT ;
    USE SIGNAL ;
    SHAPE ABUTMENT ;
    PORT
      LAYER met3 ;
      RECT 1670.740 1241.530 1671.640 1241.830 ;
    END
  END w0_wd_in[261]
  PIN w0_wd_in[262]
    DIRECTION INPUT ;
    USE SIGNAL ;
    SHAPE ABUTMENT ;
    PORT
      LAYER met3 ;
      RECT 1670.740 1246.290 1671.640 1246.590 ;
    END
  END w0_wd_in[262]
  PIN w0_wd_in[263]
    DIRECTION INPUT ;
    USE SIGNAL ;
    SHAPE ABUTMENT ;
    PORT
      LAYER met3 ;
      RECT 1670.740 1251.050 1671.640 1251.350 ;
    END
  END w0_wd_in[263]
  PIN w0_wd_in[264]
    DIRECTION INPUT ;
    USE SIGNAL ;
    SHAPE ABUTMENT ;
    PORT
      LAYER met3 ;
      RECT 1670.740 1255.810 1671.640 1256.110 ;
    END
  END w0_wd_in[264]
  PIN w0_wd_in[265]
    DIRECTION INPUT ;
    USE SIGNAL ;
    SHAPE ABUTMENT ;
    PORT
      LAYER met3 ;
      RECT 1670.740 1260.570 1671.640 1260.870 ;
    END
  END w0_wd_in[265]
  PIN w0_wd_in[266]
    DIRECTION INPUT ;
    USE SIGNAL ;
    SHAPE ABUTMENT ;
    PORT
      LAYER met3 ;
      RECT 1670.740 1265.330 1671.640 1265.630 ;
    END
  END w0_wd_in[266]
  PIN w0_wd_in[267]
    DIRECTION INPUT ;
    USE SIGNAL ;
    SHAPE ABUTMENT ;
    PORT
      LAYER met3 ;
      RECT 1670.740 1270.090 1671.640 1270.390 ;
    END
  END w0_wd_in[267]
  PIN w0_wd_in[268]
    DIRECTION INPUT ;
    USE SIGNAL ;
    SHAPE ABUTMENT ;
    PORT
      LAYER met3 ;
      RECT 1670.740 1274.850 1671.640 1275.150 ;
    END
  END w0_wd_in[268]
  PIN w0_wd_in[269]
    DIRECTION INPUT ;
    USE SIGNAL ;
    SHAPE ABUTMENT ;
    PORT
      LAYER met3 ;
      RECT 1670.740 1279.610 1671.640 1279.910 ;
    END
  END w0_wd_in[269]
  PIN w0_wd_in[270]
    DIRECTION INPUT ;
    USE SIGNAL ;
    SHAPE ABUTMENT ;
    PORT
      LAYER met3 ;
      RECT 1670.740 1284.370 1671.640 1284.670 ;
    END
  END w0_wd_in[270]
  PIN w0_wd_in[271]
    DIRECTION INPUT ;
    USE SIGNAL ;
    SHAPE ABUTMENT ;
    PORT
      LAYER met3 ;
      RECT 1670.740 1289.130 1671.640 1289.430 ;
    END
  END w0_wd_in[271]
  PIN w0_wd_in[272]
    DIRECTION INPUT ;
    USE SIGNAL ;
    SHAPE ABUTMENT ;
    PORT
      LAYER met3 ;
      RECT 1670.740 1293.890 1671.640 1294.190 ;
    END
  END w0_wd_in[272]
  PIN w0_wd_in[273]
    DIRECTION INPUT ;
    USE SIGNAL ;
    SHAPE ABUTMENT ;
    PORT
      LAYER met3 ;
      RECT 1670.740 1298.650 1671.640 1298.950 ;
    END
  END w0_wd_in[273]
  PIN w0_wd_in[274]
    DIRECTION INPUT ;
    USE SIGNAL ;
    SHAPE ABUTMENT ;
    PORT
      LAYER met3 ;
      RECT 1670.740 1303.410 1671.640 1303.710 ;
    END
  END w0_wd_in[274]
  PIN w0_wd_in[275]
    DIRECTION INPUT ;
    USE SIGNAL ;
    SHAPE ABUTMENT ;
    PORT
      LAYER met3 ;
      RECT 1670.740 1308.170 1671.640 1308.470 ;
    END
  END w0_wd_in[275]
  PIN w0_wd_in[276]
    DIRECTION INPUT ;
    USE SIGNAL ;
    SHAPE ABUTMENT ;
    PORT
      LAYER met3 ;
      RECT 1670.740 1312.930 1671.640 1313.230 ;
    END
  END w0_wd_in[276]
  PIN w0_wd_in[277]
    DIRECTION INPUT ;
    USE SIGNAL ;
    SHAPE ABUTMENT ;
    PORT
      LAYER met3 ;
      RECT 1670.740 1317.690 1671.640 1317.990 ;
    END
  END w0_wd_in[277]
  PIN w0_wd_in[278]
    DIRECTION INPUT ;
    USE SIGNAL ;
    SHAPE ABUTMENT ;
    PORT
      LAYER met3 ;
      RECT 1670.740 1322.450 1671.640 1322.750 ;
    END
  END w0_wd_in[278]
  PIN w0_wd_in[279]
    DIRECTION INPUT ;
    USE SIGNAL ;
    SHAPE ABUTMENT ;
    PORT
      LAYER met3 ;
      RECT 1670.740 1327.210 1671.640 1327.510 ;
    END
  END w0_wd_in[279]
  PIN w0_wd_in[280]
    DIRECTION INPUT ;
    USE SIGNAL ;
    SHAPE ABUTMENT ;
    PORT
      LAYER met3 ;
      RECT 1670.740 1331.970 1671.640 1332.270 ;
    END
  END w0_wd_in[280]
  PIN w0_wd_in[281]
    DIRECTION INPUT ;
    USE SIGNAL ;
    SHAPE ABUTMENT ;
    PORT
      LAYER met3 ;
      RECT 1670.740 1336.730 1671.640 1337.030 ;
    END
  END w0_wd_in[281]
  PIN w0_wd_in[282]
    DIRECTION INPUT ;
    USE SIGNAL ;
    SHAPE ABUTMENT ;
    PORT
      LAYER met3 ;
      RECT 1670.740 1341.490 1671.640 1341.790 ;
    END
  END w0_wd_in[282]
  PIN w0_wd_in[283]
    DIRECTION INPUT ;
    USE SIGNAL ;
    SHAPE ABUTMENT ;
    PORT
      LAYER met3 ;
      RECT 1670.740 1346.250 1671.640 1346.550 ;
    END
  END w0_wd_in[283]
  PIN w0_wd_in[284]
    DIRECTION INPUT ;
    USE SIGNAL ;
    SHAPE ABUTMENT ;
    PORT
      LAYER met3 ;
      RECT 1670.740 1351.010 1671.640 1351.310 ;
    END
  END w0_wd_in[284]
  PIN w0_wd_in[285]
    DIRECTION INPUT ;
    USE SIGNAL ;
    SHAPE ABUTMENT ;
    PORT
      LAYER met3 ;
      RECT 1670.740 1355.770 1671.640 1356.070 ;
    END
  END w0_wd_in[285]
  PIN w0_wd_in[286]
    DIRECTION INPUT ;
    USE SIGNAL ;
    SHAPE ABUTMENT ;
    PORT
      LAYER met3 ;
      RECT 1670.740 1360.530 1671.640 1360.830 ;
    END
  END w0_wd_in[286]
  PIN w0_wd_in[287]
    DIRECTION INPUT ;
    USE SIGNAL ;
    SHAPE ABUTMENT ;
    PORT
      LAYER met3 ;
      RECT 1670.740 1365.290 1671.640 1365.590 ;
    END
  END w0_wd_in[287]
  PIN w0_wd_in[288]
    DIRECTION INPUT ;
    USE SIGNAL ;
    SHAPE ABUTMENT ;
    PORT
      LAYER met3 ;
      RECT 1670.740 1370.050 1671.640 1370.350 ;
    END
  END w0_wd_in[288]
  PIN w0_wd_in[289]
    DIRECTION INPUT ;
    USE SIGNAL ;
    SHAPE ABUTMENT ;
    PORT
      LAYER met3 ;
      RECT 1670.740 1374.810 1671.640 1375.110 ;
    END
  END w0_wd_in[289]
  PIN w0_wd_in[290]
    DIRECTION INPUT ;
    USE SIGNAL ;
    SHAPE ABUTMENT ;
    PORT
      LAYER met3 ;
      RECT 1670.740 1379.570 1671.640 1379.870 ;
    END
  END w0_wd_in[290]
  PIN w0_wd_in[291]
    DIRECTION INPUT ;
    USE SIGNAL ;
    SHAPE ABUTMENT ;
    PORT
      LAYER met3 ;
      RECT 1670.740 1384.330 1671.640 1384.630 ;
    END
  END w0_wd_in[291]
  PIN w0_wd_in[292]
    DIRECTION INPUT ;
    USE SIGNAL ;
    SHAPE ABUTMENT ;
    PORT
      LAYER met3 ;
      RECT 1670.740 1389.090 1671.640 1389.390 ;
    END
  END w0_wd_in[292]
  PIN w0_wd_in[293]
    DIRECTION INPUT ;
    USE SIGNAL ;
    SHAPE ABUTMENT ;
    PORT
      LAYER met3 ;
      RECT 1670.740 1393.850 1671.640 1394.150 ;
    END
  END w0_wd_in[293]
  PIN w0_wd_in[294]
    DIRECTION INPUT ;
    USE SIGNAL ;
    SHAPE ABUTMENT ;
    PORT
      LAYER met3 ;
      RECT 1670.740 1398.610 1671.640 1398.910 ;
    END
  END w0_wd_in[294]
  PIN w0_wd_in[295]
    DIRECTION INPUT ;
    USE SIGNAL ;
    SHAPE ABUTMENT ;
    PORT
      LAYER met3 ;
      RECT 1670.740 1403.370 1671.640 1403.670 ;
    END
  END w0_wd_in[295]
  PIN w0_wd_in[296]
    DIRECTION INPUT ;
    USE SIGNAL ;
    SHAPE ABUTMENT ;
    PORT
      LAYER met3 ;
      RECT 1670.740 1408.130 1671.640 1408.430 ;
    END
  END w0_wd_in[296]
  PIN w0_wd_in[297]
    DIRECTION INPUT ;
    USE SIGNAL ;
    SHAPE ABUTMENT ;
    PORT
      LAYER met3 ;
      RECT 1670.740 1412.890 1671.640 1413.190 ;
    END
  END w0_wd_in[297]
  PIN w0_wd_in[298]
    DIRECTION INPUT ;
    USE SIGNAL ;
    SHAPE ABUTMENT ;
    PORT
      LAYER met3 ;
      RECT 1670.740 1417.650 1671.640 1417.950 ;
    END
  END w0_wd_in[298]
  PIN w0_wd_in[299]
    DIRECTION INPUT ;
    USE SIGNAL ;
    SHAPE ABUTMENT ;
    PORT
      LAYER met3 ;
      RECT 1670.740 1422.410 1671.640 1422.710 ;
    END
  END w0_wd_in[299]
  PIN w0_wd_in[300]
    DIRECTION INPUT ;
    USE SIGNAL ;
    SHAPE ABUTMENT ;
    PORT
      LAYER met3 ;
      RECT 1670.740 1427.170 1671.640 1427.470 ;
    END
  END w0_wd_in[300]
  PIN w0_wd_in[301]
    DIRECTION INPUT ;
    USE SIGNAL ;
    SHAPE ABUTMENT ;
    PORT
      LAYER met3 ;
      RECT 1670.740 1431.930 1671.640 1432.230 ;
    END
  END w0_wd_in[301]
  PIN w0_wd_in[302]
    DIRECTION INPUT ;
    USE SIGNAL ;
    SHAPE ABUTMENT ;
    PORT
      LAYER met3 ;
      RECT 1670.740 1436.690 1671.640 1436.990 ;
    END
  END w0_wd_in[302]
  PIN w0_wd_in[303]
    DIRECTION INPUT ;
    USE SIGNAL ;
    SHAPE ABUTMENT ;
    PORT
      LAYER met3 ;
      RECT 1670.740 1441.450 1671.640 1441.750 ;
    END
  END w0_wd_in[303]
  PIN w0_wd_in[304]
    DIRECTION INPUT ;
    USE SIGNAL ;
    SHAPE ABUTMENT ;
    PORT
      LAYER met3 ;
      RECT 1670.740 1446.210 1671.640 1446.510 ;
    END
  END w0_wd_in[304]
  PIN w0_wd_in[305]
    DIRECTION INPUT ;
    USE SIGNAL ;
    SHAPE ABUTMENT ;
    PORT
      LAYER met3 ;
      RECT 1670.740 1450.970 1671.640 1451.270 ;
    END
  END w0_wd_in[305]
  PIN w0_wd_in[306]
    DIRECTION INPUT ;
    USE SIGNAL ;
    SHAPE ABUTMENT ;
    PORT
      LAYER met3 ;
      RECT 1670.740 1455.730 1671.640 1456.030 ;
    END
  END w0_wd_in[306]
  PIN w0_wd_in[307]
    DIRECTION INPUT ;
    USE SIGNAL ;
    SHAPE ABUTMENT ;
    PORT
      LAYER met3 ;
      RECT 1670.740 1460.490 1671.640 1460.790 ;
    END
  END w0_wd_in[307]
  PIN w0_wd_in[308]
    DIRECTION INPUT ;
    USE SIGNAL ;
    SHAPE ABUTMENT ;
    PORT
      LAYER met3 ;
      RECT 1670.740 1465.250 1671.640 1465.550 ;
    END
  END w0_wd_in[308]
  PIN w0_wd_in[309]
    DIRECTION INPUT ;
    USE SIGNAL ;
    SHAPE ABUTMENT ;
    PORT
      LAYER met3 ;
      RECT 1670.740 1470.010 1671.640 1470.310 ;
    END
  END w0_wd_in[309]
  PIN w0_wd_in[310]
    DIRECTION INPUT ;
    USE SIGNAL ;
    SHAPE ABUTMENT ;
    PORT
      LAYER met3 ;
      RECT 1670.740 1474.770 1671.640 1475.070 ;
    END
  END w0_wd_in[310]
  PIN w0_wd_in[311]
    DIRECTION INPUT ;
    USE SIGNAL ;
    SHAPE ABUTMENT ;
    PORT
      LAYER met3 ;
      RECT 1670.740 1479.530 1671.640 1479.830 ;
    END
  END w0_wd_in[311]
  PIN w0_wd_in[312]
    DIRECTION INPUT ;
    USE SIGNAL ;
    SHAPE ABUTMENT ;
    PORT
      LAYER met3 ;
      RECT 1670.740 1484.290 1671.640 1484.590 ;
    END
  END w0_wd_in[312]
  PIN w0_wd_in[313]
    DIRECTION INPUT ;
    USE SIGNAL ;
    SHAPE ABUTMENT ;
    PORT
      LAYER met3 ;
      RECT 1670.740 1489.050 1671.640 1489.350 ;
    END
  END w0_wd_in[313]
  PIN w0_wd_in[314]
    DIRECTION INPUT ;
    USE SIGNAL ;
    SHAPE ABUTMENT ;
    PORT
      LAYER met3 ;
      RECT 1670.740 1493.810 1671.640 1494.110 ;
    END
  END w0_wd_in[314]
  PIN w0_wd_in[315]
    DIRECTION INPUT ;
    USE SIGNAL ;
    SHAPE ABUTMENT ;
    PORT
      LAYER met3 ;
      RECT 1670.740 1498.570 1671.640 1498.870 ;
    END
  END w0_wd_in[315]
  PIN w0_wd_in[316]
    DIRECTION INPUT ;
    USE SIGNAL ;
    SHAPE ABUTMENT ;
    PORT
      LAYER met3 ;
      RECT 1670.740 1503.330 1671.640 1503.630 ;
    END
  END w0_wd_in[316]
  PIN w0_wd_in[317]
    DIRECTION INPUT ;
    USE SIGNAL ;
    SHAPE ABUTMENT ;
    PORT
      LAYER met3 ;
      RECT 1670.740 1508.090 1671.640 1508.390 ;
    END
  END w0_wd_in[317]
  PIN w0_wd_in[318]
    DIRECTION INPUT ;
    USE SIGNAL ;
    SHAPE ABUTMENT ;
    PORT
      LAYER met3 ;
      RECT 1670.740 1512.850 1671.640 1513.150 ;
    END
  END w0_wd_in[318]
  PIN w0_wd_in[319]
    DIRECTION INPUT ;
    USE SIGNAL ;
    SHAPE ABUTMENT ;
    PORT
      LAYER met3 ;
      RECT 1670.740 1517.610 1671.640 1517.910 ;
    END
  END w0_wd_in[319]
  PIN w0_wd_in[320]
    DIRECTION INPUT ;
    USE SIGNAL ;
    SHAPE ABUTMENT ;
    PORT
      LAYER met3 ;
      RECT 1670.740 1522.370 1671.640 1522.670 ;
    END
  END w0_wd_in[320]
  PIN w0_wd_in[321]
    DIRECTION INPUT ;
    USE SIGNAL ;
    SHAPE ABUTMENT ;
    PORT
      LAYER met3 ;
      RECT 1670.740 1527.130 1671.640 1527.430 ;
    END
  END w0_wd_in[321]
  PIN w0_wd_in[322]
    DIRECTION INPUT ;
    USE SIGNAL ;
    SHAPE ABUTMENT ;
    PORT
      LAYER met3 ;
      RECT 1670.740 1531.890 1671.640 1532.190 ;
    END
  END w0_wd_in[322]
  PIN w0_wd_in[323]
    DIRECTION INPUT ;
    USE SIGNAL ;
    SHAPE ABUTMENT ;
    PORT
      LAYER met3 ;
      RECT 1670.740 1536.650 1671.640 1536.950 ;
    END
  END w0_wd_in[323]
  PIN w0_wd_in[324]
    DIRECTION INPUT ;
    USE SIGNAL ;
    SHAPE ABUTMENT ;
    PORT
      LAYER met3 ;
      RECT 1670.740 1541.410 1671.640 1541.710 ;
    END
  END w0_wd_in[324]
  PIN w0_wd_in[325]
    DIRECTION INPUT ;
    USE SIGNAL ;
    SHAPE ABUTMENT ;
    PORT
      LAYER met3 ;
      RECT 1670.740 1546.170 1671.640 1546.470 ;
    END
  END w0_wd_in[325]
  PIN w0_wd_in[326]
    DIRECTION INPUT ;
    USE SIGNAL ;
    SHAPE ABUTMENT ;
    PORT
      LAYER met3 ;
      RECT 1670.740 1550.930 1671.640 1551.230 ;
    END
  END w0_wd_in[326]
  PIN w0_wd_in[327]
    DIRECTION OUTPUT ;
    USE SIGNAL ;
    SHAPE ABUTMENT ;
    PORT
      LAYER met2 ;
      RECT 2.690 0.000 2.830 0.420 ;
    END
  END w0_wd_in[327]
  PIN w0_wd_in[328]
    DIRECTION OUTPUT ;
    USE SIGNAL ;
    SHAPE ABUTMENT ;
    PORT
      LAYER met2 ;
      RECT 4.990 0.000 5.130 0.420 ;
    END
  END w0_wd_in[328]
  PIN w0_wd_in[329]
    DIRECTION OUTPUT ;
    USE SIGNAL ;
    SHAPE ABUTMENT ;
    PORT
      LAYER met2 ;
      RECT 7.290 0.000 7.430 0.420 ;
    END
  END w0_wd_in[329]
  PIN w0_wd_in[330]
    DIRECTION OUTPUT ;
    USE SIGNAL ;
    SHAPE ABUTMENT ;
    PORT
      LAYER met2 ;
      RECT 9.590 0.000 9.730 0.420 ;
    END
  END w0_wd_in[330]
  PIN w0_wd_in[331]
    DIRECTION OUTPUT ;
    USE SIGNAL ;
    SHAPE ABUTMENT ;
    PORT
      LAYER met2 ;
      RECT 11.890 0.000 12.030 0.420 ;
    END
  END w0_wd_in[331]
  PIN w0_wd_in[332]
    DIRECTION OUTPUT ;
    USE SIGNAL ;
    SHAPE ABUTMENT ;
    PORT
      LAYER met2 ;
      RECT 14.190 0.000 14.330 0.420 ;
    END
  END w0_wd_in[332]
  PIN w0_wd_in[333]
    DIRECTION OUTPUT ;
    USE SIGNAL ;
    SHAPE ABUTMENT ;
    PORT
      LAYER met2 ;
      RECT 16.490 0.000 16.630 0.420 ;
    END
  END w0_wd_in[333]
  PIN w0_wd_in[334]
    DIRECTION OUTPUT ;
    USE SIGNAL ;
    SHAPE ABUTMENT ;
    PORT
      LAYER met2 ;
      RECT 18.790 0.000 18.930 0.420 ;
    END
  END w0_wd_in[334]
  PIN w0_wd_in[335]
    DIRECTION OUTPUT ;
    USE SIGNAL ;
    SHAPE ABUTMENT ;
    PORT
      LAYER met2 ;
      RECT 21.090 0.000 21.230 0.420 ;
    END
  END w0_wd_in[335]
  PIN w0_wd_in[336]
    DIRECTION OUTPUT ;
    USE SIGNAL ;
    SHAPE ABUTMENT ;
    PORT
      LAYER met2 ;
      RECT 23.390 0.000 23.530 0.420 ;
    END
  END w0_wd_in[336]
  PIN w0_wd_in[337]
    DIRECTION OUTPUT ;
    USE SIGNAL ;
    SHAPE ABUTMENT ;
    PORT
      LAYER met2 ;
      RECT 25.690 0.000 25.830 0.420 ;
    END
  END w0_wd_in[337]
  PIN w0_wd_in[338]
    DIRECTION OUTPUT ;
    USE SIGNAL ;
    SHAPE ABUTMENT ;
    PORT
      LAYER met2 ;
      RECT 27.990 0.000 28.130 0.420 ;
    END
  END w0_wd_in[338]
  PIN w0_wd_in[339]
    DIRECTION OUTPUT ;
    USE SIGNAL ;
    SHAPE ABUTMENT ;
    PORT
      LAYER met2 ;
      RECT 30.290 0.000 30.430 0.420 ;
    END
  END w0_wd_in[339]
  PIN w0_wd_in[340]
    DIRECTION OUTPUT ;
    USE SIGNAL ;
    SHAPE ABUTMENT ;
    PORT
      LAYER met2 ;
      RECT 32.590 0.000 32.730 0.420 ;
    END
  END w0_wd_in[340]
  PIN w0_wd_in[341]
    DIRECTION OUTPUT ;
    USE SIGNAL ;
    SHAPE ABUTMENT ;
    PORT
      LAYER met2 ;
      RECT 34.890 0.000 35.030 0.420 ;
    END
  END w0_wd_in[341]
  PIN w0_wd_in[342]
    DIRECTION OUTPUT ;
    USE SIGNAL ;
    SHAPE ABUTMENT ;
    PORT
      LAYER met2 ;
      RECT 37.190 0.000 37.330 0.420 ;
    END
  END w0_wd_in[342]
  PIN w0_wd_in[343]
    DIRECTION OUTPUT ;
    USE SIGNAL ;
    SHAPE ABUTMENT ;
    PORT
      LAYER met2 ;
      RECT 39.490 0.000 39.630 0.420 ;
    END
  END w0_wd_in[343]
  PIN w0_wd_in[344]
    DIRECTION OUTPUT ;
    USE SIGNAL ;
    SHAPE ABUTMENT ;
    PORT
      LAYER met2 ;
      RECT 41.790 0.000 41.930 0.420 ;
    END
  END w0_wd_in[344]
  PIN w0_wd_in[345]
    DIRECTION OUTPUT ;
    USE SIGNAL ;
    SHAPE ABUTMENT ;
    PORT
      LAYER met2 ;
      RECT 44.090 0.000 44.230 0.420 ;
    END
  END w0_wd_in[345]
  PIN w0_wd_in[346]
    DIRECTION OUTPUT ;
    USE SIGNAL ;
    SHAPE ABUTMENT ;
    PORT
      LAYER met2 ;
      RECT 46.390 0.000 46.530 0.420 ;
    END
  END w0_wd_in[346]
  PIN w0_wd_in[347]
    DIRECTION OUTPUT ;
    USE SIGNAL ;
    SHAPE ABUTMENT ;
    PORT
      LAYER met2 ;
      RECT 48.690 0.000 48.830 0.420 ;
    END
  END w0_wd_in[347]
  PIN w0_wd_in[348]
    DIRECTION OUTPUT ;
    USE SIGNAL ;
    SHAPE ABUTMENT ;
    PORT
      LAYER met2 ;
      RECT 50.990 0.000 51.130 0.420 ;
    END
  END w0_wd_in[348]
  PIN w0_wd_in[349]
    DIRECTION OUTPUT ;
    USE SIGNAL ;
    SHAPE ABUTMENT ;
    PORT
      LAYER met2 ;
      RECT 53.290 0.000 53.430 0.420 ;
    END
  END w0_wd_in[349]
  PIN w0_wd_in[350]
    DIRECTION OUTPUT ;
    USE SIGNAL ;
    SHAPE ABUTMENT ;
    PORT
      LAYER met2 ;
      RECT 55.590 0.000 55.730 0.420 ;
    END
  END w0_wd_in[350]
  PIN w0_wd_in[351]
    DIRECTION OUTPUT ;
    USE SIGNAL ;
    SHAPE ABUTMENT ;
    PORT
      LAYER met2 ;
      RECT 57.890 0.000 58.030 0.420 ;
    END
  END w0_wd_in[351]
  PIN w0_wd_in[352]
    DIRECTION OUTPUT ;
    USE SIGNAL ;
    SHAPE ABUTMENT ;
    PORT
      LAYER met2 ;
      RECT 60.190 0.000 60.330 0.420 ;
    END
  END w0_wd_in[352]
  PIN w0_wd_in[353]
    DIRECTION OUTPUT ;
    USE SIGNAL ;
    SHAPE ABUTMENT ;
    PORT
      LAYER met2 ;
      RECT 62.490 0.000 62.630 0.420 ;
    END
  END w0_wd_in[353]
  PIN w0_wd_in[354]
    DIRECTION OUTPUT ;
    USE SIGNAL ;
    SHAPE ABUTMENT ;
    PORT
      LAYER met2 ;
      RECT 64.790 0.000 64.930 0.420 ;
    END
  END w0_wd_in[354]
  PIN w0_wd_in[355]
    DIRECTION OUTPUT ;
    USE SIGNAL ;
    SHAPE ABUTMENT ;
    PORT
      LAYER met2 ;
      RECT 67.090 0.000 67.230 0.420 ;
    END
  END w0_wd_in[355]
  PIN w0_wd_in[356]
    DIRECTION OUTPUT ;
    USE SIGNAL ;
    SHAPE ABUTMENT ;
    PORT
      LAYER met2 ;
      RECT 69.390 0.000 69.530 0.420 ;
    END
  END w0_wd_in[356]
  PIN w0_wd_in[357]
    DIRECTION OUTPUT ;
    USE SIGNAL ;
    SHAPE ABUTMENT ;
    PORT
      LAYER met2 ;
      RECT 71.690 0.000 71.830 0.420 ;
    END
  END w0_wd_in[357]
  PIN w0_wd_in[358]
    DIRECTION OUTPUT ;
    USE SIGNAL ;
    SHAPE ABUTMENT ;
    PORT
      LAYER met2 ;
      RECT 73.990 0.000 74.130 0.420 ;
    END
  END w0_wd_in[358]
  PIN w0_wd_in[359]
    DIRECTION OUTPUT ;
    USE SIGNAL ;
    SHAPE ABUTMENT ;
    PORT
      LAYER met2 ;
      RECT 76.290 0.000 76.430 0.420 ;
    END
  END w0_wd_in[359]
  PIN w0_wd_in[360]
    DIRECTION OUTPUT ;
    USE SIGNAL ;
    SHAPE ABUTMENT ;
    PORT
      LAYER met2 ;
      RECT 78.590 0.000 78.730 0.420 ;
    END
  END w0_wd_in[360]
  PIN w0_wd_in[361]
    DIRECTION OUTPUT ;
    USE SIGNAL ;
    SHAPE ABUTMENT ;
    PORT
      LAYER met2 ;
      RECT 80.890 0.000 81.030 0.420 ;
    END
  END w0_wd_in[361]
  PIN w0_wd_in[362]
    DIRECTION OUTPUT ;
    USE SIGNAL ;
    SHAPE ABUTMENT ;
    PORT
      LAYER met2 ;
      RECT 83.190 0.000 83.330 0.420 ;
    END
  END w0_wd_in[362]
  PIN w0_wd_in[363]
    DIRECTION OUTPUT ;
    USE SIGNAL ;
    SHAPE ABUTMENT ;
    PORT
      LAYER met2 ;
      RECT 85.490 0.000 85.630 0.420 ;
    END
  END w0_wd_in[363]
  PIN w0_wd_in[364]
    DIRECTION OUTPUT ;
    USE SIGNAL ;
    SHAPE ABUTMENT ;
    PORT
      LAYER met2 ;
      RECT 87.790 0.000 87.930 0.420 ;
    END
  END w0_wd_in[364]
  PIN w0_wd_in[365]
    DIRECTION OUTPUT ;
    USE SIGNAL ;
    SHAPE ABUTMENT ;
    PORT
      LAYER met2 ;
      RECT 90.090 0.000 90.230 0.420 ;
    END
  END w0_wd_in[365]
  PIN w0_wd_in[366]
    DIRECTION OUTPUT ;
    USE SIGNAL ;
    SHAPE ABUTMENT ;
    PORT
      LAYER met2 ;
      RECT 92.390 0.000 92.530 0.420 ;
    END
  END w0_wd_in[366]
  PIN w0_wd_in[367]
    DIRECTION OUTPUT ;
    USE SIGNAL ;
    SHAPE ABUTMENT ;
    PORT
      LAYER met2 ;
      RECT 94.690 0.000 94.830 0.420 ;
    END
  END w0_wd_in[367]
  PIN w0_wd_in[368]
    DIRECTION OUTPUT ;
    USE SIGNAL ;
    SHAPE ABUTMENT ;
    PORT
      LAYER met2 ;
      RECT 96.990 0.000 97.130 0.420 ;
    END
  END w0_wd_in[368]
  PIN w0_wd_in[369]
    DIRECTION OUTPUT ;
    USE SIGNAL ;
    SHAPE ABUTMENT ;
    PORT
      LAYER met2 ;
      RECT 99.290 0.000 99.430 0.420 ;
    END
  END w0_wd_in[369]
  PIN w0_wd_in[370]
    DIRECTION OUTPUT ;
    USE SIGNAL ;
    SHAPE ABUTMENT ;
    PORT
      LAYER met2 ;
      RECT 101.590 0.000 101.730 0.420 ;
    END
  END w0_wd_in[370]
  PIN w0_wd_in[371]
    DIRECTION OUTPUT ;
    USE SIGNAL ;
    SHAPE ABUTMENT ;
    PORT
      LAYER met2 ;
      RECT 103.890 0.000 104.030 0.420 ;
    END
  END w0_wd_in[371]
  PIN w0_wd_in[372]
    DIRECTION OUTPUT ;
    USE SIGNAL ;
    SHAPE ABUTMENT ;
    PORT
      LAYER met2 ;
      RECT 106.190 0.000 106.330 0.420 ;
    END
  END w0_wd_in[372]
  PIN w0_wd_in[373]
    DIRECTION OUTPUT ;
    USE SIGNAL ;
    SHAPE ABUTMENT ;
    PORT
      LAYER met2 ;
      RECT 108.490 0.000 108.630 0.420 ;
    END
  END w0_wd_in[373]
  PIN w0_wd_in[374]
    DIRECTION OUTPUT ;
    USE SIGNAL ;
    SHAPE ABUTMENT ;
    PORT
      LAYER met2 ;
      RECT 110.790 0.000 110.930 0.420 ;
    END
  END w0_wd_in[374]
  PIN w0_wd_in[375]
    DIRECTION OUTPUT ;
    USE SIGNAL ;
    SHAPE ABUTMENT ;
    PORT
      LAYER met2 ;
      RECT 113.090 0.000 113.230 0.420 ;
    END
  END w0_wd_in[375]
  PIN w0_wd_in[376]
    DIRECTION OUTPUT ;
    USE SIGNAL ;
    SHAPE ABUTMENT ;
    PORT
      LAYER met2 ;
      RECT 115.390 0.000 115.530 0.420 ;
    END
  END w0_wd_in[376]
  PIN w0_wd_in[377]
    DIRECTION OUTPUT ;
    USE SIGNAL ;
    SHAPE ABUTMENT ;
    PORT
      LAYER met2 ;
      RECT 117.690 0.000 117.830 0.420 ;
    END
  END w0_wd_in[377]
  PIN w0_wd_in[378]
    DIRECTION OUTPUT ;
    USE SIGNAL ;
    SHAPE ABUTMENT ;
    PORT
      LAYER met2 ;
      RECT 119.990 0.000 120.130 0.420 ;
    END
  END w0_wd_in[378]
  PIN w0_wd_in[379]
    DIRECTION OUTPUT ;
    USE SIGNAL ;
    SHAPE ABUTMENT ;
    PORT
      LAYER met2 ;
      RECT 122.290 0.000 122.430 0.420 ;
    END
  END w0_wd_in[379]
  PIN w0_wd_in[380]
    DIRECTION OUTPUT ;
    USE SIGNAL ;
    SHAPE ABUTMENT ;
    PORT
      LAYER met2 ;
      RECT 124.590 0.000 124.730 0.420 ;
    END
  END w0_wd_in[380]
  PIN w0_wd_in[381]
    DIRECTION OUTPUT ;
    USE SIGNAL ;
    SHAPE ABUTMENT ;
    PORT
      LAYER met2 ;
      RECT 126.890 0.000 127.030 0.420 ;
    END
  END w0_wd_in[381]
  PIN w0_wd_in[382]
    DIRECTION OUTPUT ;
    USE SIGNAL ;
    SHAPE ABUTMENT ;
    PORT
      LAYER met2 ;
      RECT 129.190 0.000 129.330 0.420 ;
    END
  END w0_wd_in[382]
  PIN w0_wd_in[383]
    DIRECTION OUTPUT ;
    USE SIGNAL ;
    SHAPE ABUTMENT ;
    PORT
      LAYER met2 ;
      RECT 131.490 0.000 131.630 0.420 ;
    END
  END w0_wd_in[383]
  PIN w0_wd_in[384]
    DIRECTION OUTPUT ;
    USE SIGNAL ;
    SHAPE ABUTMENT ;
    PORT
      LAYER met2 ;
      RECT 133.790 0.000 133.930 0.420 ;
    END
  END w0_wd_in[384]
  PIN w0_wd_in[385]
    DIRECTION OUTPUT ;
    USE SIGNAL ;
    SHAPE ABUTMENT ;
    PORT
      LAYER met2 ;
      RECT 136.090 0.000 136.230 0.420 ;
    END
  END w0_wd_in[385]
  PIN w0_wd_in[386]
    DIRECTION OUTPUT ;
    USE SIGNAL ;
    SHAPE ABUTMENT ;
    PORT
      LAYER met2 ;
      RECT 138.390 0.000 138.530 0.420 ;
    END
  END w0_wd_in[386]
  PIN w0_wd_in[387]
    DIRECTION OUTPUT ;
    USE SIGNAL ;
    SHAPE ABUTMENT ;
    PORT
      LAYER met2 ;
      RECT 140.690 0.000 140.830 0.420 ;
    END
  END w0_wd_in[387]
  PIN w0_wd_in[388]
    DIRECTION OUTPUT ;
    USE SIGNAL ;
    SHAPE ABUTMENT ;
    PORT
      LAYER met2 ;
      RECT 142.990 0.000 143.130 0.420 ;
    END
  END w0_wd_in[388]
  PIN w0_wd_in[389]
    DIRECTION OUTPUT ;
    USE SIGNAL ;
    SHAPE ABUTMENT ;
    PORT
      LAYER met2 ;
      RECT 145.290 0.000 145.430 0.420 ;
    END
  END w0_wd_in[389]
  PIN w0_wd_in[390]
    DIRECTION OUTPUT ;
    USE SIGNAL ;
    SHAPE ABUTMENT ;
    PORT
      LAYER met2 ;
      RECT 147.590 0.000 147.730 0.420 ;
    END
  END w0_wd_in[390]
  PIN w0_wd_in[391]
    DIRECTION OUTPUT ;
    USE SIGNAL ;
    SHAPE ABUTMENT ;
    PORT
      LAYER met2 ;
      RECT 149.890 0.000 150.030 0.420 ;
    END
  END w0_wd_in[391]
  PIN w0_wd_in[392]
    DIRECTION OUTPUT ;
    USE SIGNAL ;
    SHAPE ABUTMENT ;
    PORT
      LAYER met2 ;
      RECT 152.190 0.000 152.330 0.420 ;
    END
  END w0_wd_in[392]
  PIN w0_wd_in[393]
    DIRECTION OUTPUT ;
    USE SIGNAL ;
    SHAPE ABUTMENT ;
    PORT
      LAYER met2 ;
      RECT 154.490 0.000 154.630 0.420 ;
    END
  END w0_wd_in[393]
  PIN w0_wd_in[394]
    DIRECTION OUTPUT ;
    USE SIGNAL ;
    SHAPE ABUTMENT ;
    PORT
      LAYER met2 ;
      RECT 156.790 0.000 156.930 0.420 ;
    END
  END w0_wd_in[394]
  PIN w0_wd_in[395]
    DIRECTION OUTPUT ;
    USE SIGNAL ;
    SHAPE ABUTMENT ;
    PORT
      LAYER met2 ;
      RECT 159.090 0.000 159.230 0.420 ;
    END
  END w0_wd_in[395]
  PIN w0_wd_in[396]
    DIRECTION OUTPUT ;
    USE SIGNAL ;
    SHAPE ABUTMENT ;
    PORT
      LAYER met2 ;
      RECT 161.390 0.000 161.530 0.420 ;
    END
  END w0_wd_in[396]
  PIN w0_wd_in[397]
    DIRECTION OUTPUT ;
    USE SIGNAL ;
    SHAPE ABUTMENT ;
    PORT
      LAYER met2 ;
      RECT 163.690 0.000 163.830 0.420 ;
    END
  END w0_wd_in[397]
  PIN w0_wd_in[398]
    DIRECTION OUTPUT ;
    USE SIGNAL ;
    SHAPE ABUTMENT ;
    PORT
      LAYER met2 ;
      RECT 165.990 0.000 166.130 0.420 ;
    END
  END w0_wd_in[398]
  PIN w0_wd_in[399]
    DIRECTION OUTPUT ;
    USE SIGNAL ;
    SHAPE ABUTMENT ;
    PORT
      LAYER met2 ;
      RECT 168.290 0.000 168.430 0.420 ;
    END
  END w0_wd_in[399]
  PIN w0_wd_in[400]
    DIRECTION OUTPUT ;
    USE SIGNAL ;
    SHAPE ABUTMENT ;
    PORT
      LAYER met2 ;
      RECT 170.590 0.000 170.730 0.420 ;
    END
  END w0_wd_in[400]
  PIN w0_wd_in[401]
    DIRECTION OUTPUT ;
    USE SIGNAL ;
    SHAPE ABUTMENT ;
    PORT
      LAYER met2 ;
      RECT 172.890 0.000 173.030 0.420 ;
    END
  END w0_wd_in[401]
  PIN w0_wd_in[402]
    DIRECTION OUTPUT ;
    USE SIGNAL ;
    SHAPE ABUTMENT ;
    PORT
      LAYER met2 ;
      RECT 175.190 0.000 175.330 0.420 ;
    END
  END w0_wd_in[402]
  PIN w0_wd_in[403]
    DIRECTION OUTPUT ;
    USE SIGNAL ;
    SHAPE ABUTMENT ;
    PORT
      LAYER met2 ;
      RECT 177.490 0.000 177.630 0.420 ;
    END
  END w0_wd_in[403]
  PIN w0_wd_in[404]
    DIRECTION OUTPUT ;
    USE SIGNAL ;
    SHAPE ABUTMENT ;
    PORT
      LAYER met2 ;
      RECT 179.790 0.000 179.930 0.420 ;
    END
  END w0_wd_in[404]
  PIN w0_wd_in[405]
    DIRECTION OUTPUT ;
    USE SIGNAL ;
    SHAPE ABUTMENT ;
    PORT
      LAYER met2 ;
      RECT 182.090 0.000 182.230 0.420 ;
    END
  END w0_wd_in[405]
  PIN w0_wd_in[406]
    DIRECTION OUTPUT ;
    USE SIGNAL ;
    SHAPE ABUTMENT ;
    PORT
      LAYER met2 ;
      RECT 184.390 0.000 184.530 0.420 ;
    END
  END w0_wd_in[406]
  PIN w0_wd_in[407]
    DIRECTION OUTPUT ;
    USE SIGNAL ;
    SHAPE ABUTMENT ;
    PORT
      LAYER met2 ;
      RECT 186.690 0.000 186.830 0.420 ;
    END
  END w0_wd_in[407]
  PIN w0_wd_in[408]
    DIRECTION OUTPUT ;
    USE SIGNAL ;
    SHAPE ABUTMENT ;
    PORT
      LAYER met2 ;
      RECT 188.990 0.000 189.130 0.420 ;
    END
  END w0_wd_in[408]
  PIN w0_wd_in[409]
    DIRECTION OUTPUT ;
    USE SIGNAL ;
    SHAPE ABUTMENT ;
    PORT
      LAYER met2 ;
      RECT 191.290 0.000 191.430 0.420 ;
    END
  END w0_wd_in[409]
  PIN w0_wd_in[410]
    DIRECTION OUTPUT ;
    USE SIGNAL ;
    SHAPE ABUTMENT ;
    PORT
      LAYER met2 ;
      RECT 193.590 0.000 193.730 0.420 ;
    END
  END w0_wd_in[410]
  PIN w0_wd_in[411]
    DIRECTION OUTPUT ;
    USE SIGNAL ;
    SHAPE ABUTMENT ;
    PORT
      LAYER met2 ;
      RECT 195.890 0.000 196.030 0.420 ;
    END
  END w0_wd_in[411]
  PIN w0_wd_in[412]
    DIRECTION OUTPUT ;
    USE SIGNAL ;
    SHAPE ABUTMENT ;
    PORT
      LAYER met2 ;
      RECT 198.190 0.000 198.330 0.420 ;
    END
  END w0_wd_in[412]
  PIN w0_wd_in[413]
    DIRECTION OUTPUT ;
    USE SIGNAL ;
    SHAPE ABUTMENT ;
    PORT
      LAYER met2 ;
      RECT 200.490 0.000 200.630 0.420 ;
    END
  END w0_wd_in[413]
  PIN w0_wd_in[414]
    DIRECTION OUTPUT ;
    USE SIGNAL ;
    SHAPE ABUTMENT ;
    PORT
      LAYER met2 ;
      RECT 202.790 0.000 202.930 0.420 ;
    END
  END w0_wd_in[414]
  PIN w0_wd_in[415]
    DIRECTION OUTPUT ;
    USE SIGNAL ;
    SHAPE ABUTMENT ;
    PORT
      LAYER met2 ;
      RECT 205.090 0.000 205.230 0.420 ;
    END
  END w0_wd_in[415]
  PIN w0_wd_in[416]
    DIRECTION OUTPUT ;
    USE SIGNAL ;
    SHAPE ABUTMENT ;
    PORT
      LAYER met2 ;
      RECT 207.390 0.000 207.530 0.420 ;
    END
  END w0_wd_in[416]
  PIN w0_wd_in[417]
    DIRECTION OUTPUT ;
    USE SIGNAL ;
    SHAPE ABUTMENT ;
    PORT
      LAYER met2 ;
      RECT 209.690 0.000 209.830 0.420 ;
    END
  END w0_wd_in[417]
  PIN w0_wd_in[418]
    DIRECTION OUTPUT ;
    USE SIGNAL ;
    SHAPE ABUTMENT ;
    PORT
      LAYER met2 ;
      RECT 211.990 0.000 212.130 0.420 ;
    END
  END w0_wd_in[418]
  PIN w0_wd_in[419]
    DIRECTION OUTPUT ;
    USE SIGNAL ;
    SHAPE ABUTMENT ;
    PORT
      LAYER met2 ;
      RECT 214.290 0.000 214.430 0.420 ;
    END
  END w0_wd_in[419]
  PIN w0_wd_in[420]
    DIRECTION OUTPUT ;
    USE SIGNAL ;
    SHAPE ABUTMENT ;
    PORT
      LAYER met2 ;
      RECT 216.590 0.000 216.730 0.420 ;
    END
  END w0_wd_in[420]
  PIN w0_wd_in[421]
    DIRECTION OUTPUT ;
    USE SIGNAL ;
    SHAPE ABUTMENT ;
    PORT
      LAYER met2 ;
      RECT 218.890 0.000 219.030 0.420 ;
    END
  END w0_wd_in[421]
  PIN w0_wd_in[422]
    DIRECTION OUTPUT ;
    USE SIGNAL ;
    SHAPE ABUTMENT ;
    PORT
      LAYER met2 ;
      RECT 221.190 0.000 221.330 0.420 ;
    END
  END w0_wd_in[422]
  PIN w0_wd_in[423]
    DIRECTION OUTPUT ;
    USE SIGNAL ;
    SHAPE ABUTMENT ;
    PORT
      LAYER met2 ;
      RECT 223.490 0.000 223.630 0.420 ;
    END
  END w0_wd_in[423]
  PIN w0_wd_in[424]
    DIRECTION OUTPUT ;
    USE SIGNAL ;
    SHAPE ABUTMENT ;
    PORT
      LAYER met2 ;
      RECT 225.790 0.000 225.930 0.420 ;
    END
  END w0_wd_in[424]
  PIN w0_wd_in[425]
    DIRECTION OUTPUT ;
    USE SIGNAL ;
    SHAPE ABUTMENT ;
    PORT
      LAYER met2 ;
      RECT 228.090 0.000 228.230 0.420 ;
    END
  END w0_wd_in[425]
  PIN w0_wd_in[426]
    DIRECTION OUTPUT ;
    USE SIGNAL ;
    SHAPE ABUTMENT ;
    PORT
      LAYER met2 ;
      RECT 230.390 0.000 230.530 0.420 ;
    END
  END w0_wd_in[426]
  PIN w0_wd_in[427]
    DIRECTION OUTPUT ;
    USE SIGNAL ;
    SHAPE ABUTMENT ;
    PORT
      LAYER met2 ;
      RECT 232.690 0.000 232.830 0.420 ;
    END
  END w0_wd_in[427]
  PIN w0_wd_in[428]
    DIRECTION OUTPUT ;
    USE SIGNAL ;
    SHAPE ABUTMENT ;
    PORT
      LAYER met2 ;
      RECT 234.990 0.000 235.130 0.420 ;
    END
  END w0_wd_in[428]
  PIN w0_wd_in[429]
    DIRECTION OUTPUT ;
    USE SIGNAL ;
    SHAPE ABUTMENT ;
    PORT
      LAYER met2 ;
      RECT 237.290 0.000 237.430 0.420 ;
    END
  END w0_wd_in[429]
  PIN w0_wd_in[430]
    DIRECTION OUTPUT ;
    USE SIGNAL ;
    SHAPE ABUTMENT ;
    PORT
      LAYER met2 ;
      RECT 239.590 0.000 239.730 0.420 ;
    END
  END w0_wd_in[430]
  PIN w0_wd_in[431]
    DIRECTION OUTPUT ;
    USE SIGNAL ;
    SHAPE ABUTMENT ;
    PORT
      LAYER met2 ;
      RECT 241.890 0.000 242.030 0.420 ;
    END
  END w0_wd_in[431]
  PIN w0_wd_in[432]
    DIRECTION OUTPUT ;
    USE SIGNAL ;
    SHAPE ABUTMENT ;
    PORT
      LAYER met2 ;
      RECT 244.190 0.000 244.330 0.420 ;
    END
  END w0_wd_in[432]
  PIN w0_wd_in[433]
    DIRECTION OUTPUT ;
    USE SIGNAL ;
    SHAPE ABUTMENT ;
    PORT
      LAYER met2 ;
      RECT 246.490 0.000 246.630 0.420 ;
    END
  END w0_wd_in[433]
  PIN w0_wd_in[434]
    DIRECTION OUTPUT ;
    USE SIGNAL ;
    SHAPE ABUTMENT ;
    PORT
      LAYER met2 ;
      RECT 248.790 0.000 248.930 0.420 ;
    END
  END w0_wd_in[434]
  PIN w0_wd_in[435]
    DIRECTION OUTPUT ;
    USE SIGNAL ;
    SHAPE ABUTMENT ;
    PORT
      LAYER met2 ;
      RECT 251.090 0.000 251.230 0.420 ;
    END
  END w0_wd_in[435]
  PIN w0_wd_in[436]
    DIRECTION OUTPUT ;
    USE SIGNAL ;
    SHAPE ABUTMENT ;
    PORT
      LAYER met2 ;
      RECT 253.390 0.000 253.530 0.420 ;
    END
  END w0_wd_in[436]
  PIN w0_wd_in[437]
    DIRECTION OUTPUT ;
    USE SIGNAL ;
    SHAPE ABUTMENT ;
    PORT
      LAYER met2 ;
      RECT 255.690 0.000 255.830 0.420 ;
    END
  END w0_wd_in[437]
  PIN w0_wd_in[438]
    DIRECTION OUTPUT ;
    USE SIGNAL ;
    SHAPE ABUTMENT ;
    PORT
      LAYER met2 ;
      RECT 257.990 0.000 258.130 0.420 ;
    END
  END w0_wd_in[438]
  PIN w0_wd_in[439]
    DIRECTION OUTPUT ;
    USE SIGNAL ;
    SHAPE ABUTMENT ;
    PORT
      LAYER met2 ;
      RECT 260.290 0.000 260.430 0.420 ;
    END
  END w0_wd_in[439]
  PIN w0_wd_in[440]
    DIRECTION OUTPUT ;
    USE SIGNAL ;
    SHAPE ABUTMENT ;
    PORT
      LAYER met2 ;
      RECT 262.590 0.000 262.730 0.420 ;
    END
  END w0_wd_in[440]
  PIN w0_wd_in[441]
    DIRECTION OUTPUT ;
    USE SIGNAL ;
    SHAPE ABUTMENT ;
    PORT
      LAYER met2 ;
      RECT 264.890 0.000 265.030 0.420 ;
    END
  END w0_wd_in[441]
  PIN w0_wd_in[442]
    DIRECTION OUTPUT ;
    USE SIGNAL ;
    SHAPE ABUTMENT ;
    PORT
      LAYER met2 ;
      RECT 267.190 0.000 267.330 0.420 ;
    END
  END w0_wd_in[442]
  PIN w0_wd_in[443]
    DIRECTION OUTPUT ;
    USE SIGNAL ;
    SHAPE ABUTMENT ;
    PORT
      LAYER met2 ;
      RECT 269.490 0.000 269.630 0.420 ;
    END
  END w0_wd_in[443]
  PIN w0_wd_in[444]
    DIRECTION OUTPUT ;
    USE SIGNAL ;
    SHAPE ABUTMENT ;
    PORT
      LAYER met2 ;
      RECT 271.790 0.000 271.930 0.420 ;
    END
  END w0_wd_in[444]
  PIN w0_wd_in[445]
    DIRECTION OUTPUT ;
    USE SIGNAL ;
    SHAPE ABUTMENT ;
    PORT
      LAYER met2 ;
      RECT 274.090 0.000 274.230 0.420 ;
    END
  END w0_wd_in[445]
  PIN w0_wd_in[446]
    DIRECTION OUTPUT ;
    USE SIGNAL ;
    SHAPE ABUTMENT ;
    PORT
      LAYER met2 ;
      RECT 276.390 0.000 276.530 0.420 ;
    END
  END w0_wd_in[446]
  PIN w0_wd_in[447]
    DIRECTION OUTPUT ;
    USE SIGNAL ;
    SHAPE ABUTMENT ;
    PORT
      LAYER met2 ;
      RECT 278.690 0.000 278.830 0.420 ;
    END
  END w0_wd_in[447]
  PIN w0_wd_in[448]
    DIRECTION OUTPUT ;
    USE SIGNAL ;
    SHAPE ABUTMENT ;
    PORT
      LAYER met2 ;
      RECT 280.990 0.000 281.130 0.420 ;
    END
  END w0_wd_in[448]
  PIN w0_wd_in[449]
    DIRECTION OUTPUT ;
    USE SIGNAL ;
    SHAPE ABUTMENT ;
    PORT
      LAYER met2 ;
      RECT 283.290 0.000 283.430 0.420 ;
    END
  END w0_wd_in[449]
  PIN w0_wd_in[450]
    DIRECTION OUTPUT ;
    USE SIGNAL ;
    SHAPE ABUTMENT ;
    PORT
      LAYER met2 ;
      RECT 285.590 0.000 285.730 0.420 ;
    END
  END w0_wd_in[450]
  PIN w0_wd_in[451]
    DIRECTION OUTPUT ;
    USE SIGNAL ;
    SHAPE ABUTMENT ;
    PORT
      LAYER met2 ;
      RECT 287.890 0.000 288.030 0.420 ;
    END
  END w0_wd_in[451]
  PIN w0_wd_in[452]
    DIRECTION OUTPUT ;
    USE SIGNAL ;
    SHAPE ABUTMENT ;
    PORT
      LAYER met2 ;
      RECT 290.190 0.000 290.330 0.420 ;
    END
  END w0_wd_in[452]
  PIN w0_wd_in[453]
    DIRECTION OUTPUT ;
    USE SIGNAL ;
    SHAPE ABUTMENT ;
    PORT
      LAYER met2 ;
      RECT 292.490 0.000 292.630 0.420 ;
    END
  END w0_wd_in[453]
  PIN w0_wd_in[454]
    DIRECTION OUTPUT ;
    USE SIGNAL ;
    SHAPE ABUTMENT ;
    PORT
      LAYER met2 ;
      RECT 294.790 0.000 294.930 0.420 ;
    END
  END w0_wd_in[454]
  PIN w0_wd_in[455]
    DIRECTION OUTPUT ;
    USE SIGNAL ;
    SHAPE ABUTMENT ;
    PORT
      LAYER met2 ;
      RECT 297.090 0.000 297.230 0.420 ;
    END
  END w0_wd_in[455]
  PIN w0_wd_in[456]
    DIRECTION OUTPUT ;
    USE SIGNAL ;
    SHAPE ABUTMENT ;
    PORT
      LAYER met2 ;
      RECT 299.390 0.000 299.530 0.420 ;
    END
  END w0_wd_in[456]
  PIN w0_wd_in[457]
    DIRECTION OUTPUT ;
    USE SIGNAL ;
    SHAPE ABUTMENT ;
    PORT
      LAYER met2 ;
      RECT 301.690 0.000 301.830 0.420 ;
    END
  END w0_wd_in[457]
  PIN w0_wd_in[458]
    DIRECTION OUTPUT ;
    USE SIGNAL ;
    SHAPE ABUTMENT ;
    PORT
      LAYER met2 ;
      RECT 303.990 0.000 304.130 0.420 ;
    END
  END w0_wd_in[458]
  PIN w0_wd_in[459]
    DIRECTION OUTPUT ;
    USE SIGNAL ;
    SHAPE ABUTMENT ;
    PORT
      LAYER met2 ;
      RECT 306.290 0.000 306.430 0.420 ;
    END
  END w0_wd_in[459]
  PIN w0_wd_in[460]
    DIRECTION OUTPUT ;
    USE SIGNAL ;
    SHAPE ABUTMENT ;
    PORT
      LAYER met2 ;
      RECT 308.590 0.000 308.730 0.420 ;
    END
  END w0_wd_in[460]
  PIN w0_wd_in[461]
    DIRECTION OUTPUT ;
    USE SIGNAL ;
    SHAPE ABUTMENT ;
    PORT
      LAYER met2 ;
      RECT 310.890 0.000 311.030 0.420 ;
    END
  END w0_wd_in[461]
  PIN w0_wd_in[462]
    DIRECTION OUTPUT ;
    USE SIGNAL ;
    SHAPE ABUTMENT ;
    PORT
      LAYER met2 ;
      RECT 313.190 0.000 313.330 0.420 ;
    END
  END w0_wd_in[462]
  PIN w0_wd_in[463]
    DIRECTION OUTPUT ;
    USE SIGNAL ;
    SHAPE ABUTMENT ;
    PORT
      LAYER met2 ;
      RECT 315.490 0.000 315.630 0.420 ;
    END
  END w0_wd_in[463]
  PIN w0_wd_in[464]
    DIRECTION OUTPUT ;
    USE SIGNAL ;
    SHAPE ABUTMENT ;
    PORT
      LAYER met2 ;
      RECT 317.790 0.000 317.930 0.420 ;
    END
  END w0_wd_in[464]
  PIN w0_wd_in[465]
    DIRECTION OUTPUT ;
    USE SIGNAL ;
    SHAPE ABUTMENT ;
    PORT
      LAYER met2 ;
      RECT 320.090 0.000 320.230 0.420 ;
    END
  END w0_wd_in[465]
  PIN w0_wd_in[466]
    DIRECTION OUTPUT ;
    USE SIGNAL ;
    SHAPE ABUTMENT ;
    PORT
      LAYER met2 ;
      RECT 322.390 0.000 322.530 0.420 ;
    END
  END w0_wd_in[466]
  PIN w0_wd_in[467]
    DIRECTION OUTPUT ;
    USE SIGNAL ;
    SHAPE ABUTMENT ;
    PORT
      LAYER met2 ;
      RECT 324.690 0.000 324.830 0.420 ;
    END
  END w0_wd_in[467]
  PIN w0_wd_in[468]
    DIRECTION OUTPUT ;
    USE SIGNAL ;
    SHAPE ABUTMENT ;
    PORT
      LAYER met2 ;
      RECT 326.990 0.000 327.130 0.420 ;
    END
  END w0_wd_in[468]
  PIN w0_wd_in[469]
    DIRECTION OUTPUT ;
    USE SIGNAL ;
    SHAPE ABUTMENT ;
    PORT
      LAYER met2 ;
      RECT 329.290 0.000 329.430 0.420 ;
    END
  END w0_wd_in[469]
  PIN w0_wd_in[470]
    DIRECTION OUTPUT ;
    USE SIGNAL ;
    SHAPE ABUTMENT ;
    PORT
      LAYER met2 ;
      RECT 331.590 0.000 331.730 0.420 ;
    END
  END w0_wd_in[470]
  PIN w0_wd_in[471]
    DIRECTION OUTPUT ;
    USE SIGNAL ;
    SHAPE ABUTMENT ;
    PORT
      LAYER met2 ;
      RECT 333.890 0.000 334.030 0.420 ;
    END
  END w0_wd_in[471]
  PIN w0_wd_in[472]
    DIRECTION OUTPUT ;
    USE SIGNAL ;
    SHAPE ABUTMENT ;
    PORT
      LAYER met2 ;
      RECT 336.190 0.000 336.330 0.420 ;
    END
  END w0_wd_in[472]
  PIN w0_wd_in[473]
    DIRECTION OUTPUT ;
    USE SIGNAL ;
    SHAPE ABUTMENT ;
    PORT
      LAYER met2 ;
      RECT 338.490 0.000 338.630 0.420 ;
    END
  END w0_wd_in[473]
  PIN w0_wd_in[474]
    DIRECTION OUTPUT ;
    USE SIGNAL ;
    SHAPE ABUTMENT ;
    PORT
      LAYER met2 ;
      RECT 340.790 0.000 340.930 0.420 ;
    END
  END w0_wd_in[474]
  PIN w0_wd_in[475]
    DIRECTION OUTPUT ;
    USE SIGNAL ;
    SHAPE ABUTMENT ;
    PORT
      LAYER met2 ;
      RECT 343.090 0.000 343.230 0.420 ;
    END
  END w0_wd_in[475]
  PIN w0_wd_in[476]
    DIRECTION OUTPUT ;
    USE SIGNAL ;
    SHAPE ABUTMENT ;
    PORT
      LAYER met2 ;
      RECT 345.390 0.000 345.530 0.420 ;
    END
  END w0_wd_in[476]
  PIN w0_wd_in[477]
    DIRECTION OUTPUT ;
    USE SIGNAL ;
    SHAPE ABUTMENT ;
    PORT
      LAYER met2 ;
      RECT 347.690 0.000 347.830 0.420 ;
    END
  END w0_wd_in[477]
  PIN w0_wd_in[478]
    DIRECTION OUTPUT ;
    USE SIGNAL ;
    SHAPE ABUTMENT ;
    PORT
      LAYER met2 ;
      RECT 349.990 0.000 350.130 0.420 ;
    END
  END w0_wd_in[478]
  PIN w0_wd_in[479]
    DIRECTION OUTPUT ;
    USE SIGNAL ;
    SHAPE ABUTMENT ;
    PORT
      LAYER met2 ;
      RECT 352.290 0.000 352.430 0.420 ;
    END
  END w0_wd_in[479]
  PIN w0_wd_in[480]
    DIRECTION OUTPUT ;
    USE SIGNAL ;
    SHAPE ABUTMENT ;
    PORT
      LAYER met2 ;
      RECT 354.590 0.000 354.730 0.420 ;
    END
  END w0_wd_in[480]
  PIN w0_wd_in[481]
    DIRECTION OUTPUT ;
    USE SIGNAL ;
    SHAPE ABUTMENT ;
    PORT
      LAYER met2 ;
      RECT 356.890 0.000 357.030 0.420 ;
    END
  END w0_wd_in[481]
  PIN w0_wd_in[482]
    DIRECTION OUTPUT ;
    USE SIGNAL ;
    SHAPE ABUTMENT ;
    PORT
      LAYER met2 ;
      RECT 359.190 0.000 359.330 0.420 ;
    END
  END w0_wd_in[482]
  PIN w0_wd_in[483]
    DIRECTION OUTPUT ;
    USE SIGNAL ;
    SHAPE ABUTMENT ;
    PORT
      LAYER met2 ;
      RECT 361.490 0.000 361.630 0.420 ;
    END
  END w0_wd_in[483]
  PIN w0_wd_in[484]
    DIRECTION OUTPUT ;
    USE SIGNAL ;
    SHAPE ABUTMENT ;
    PORT
      LAYER met2 ;
      RECT 363.790 0.000 363.930 0.420 ;
    END
  END w0_wd_in[484]
  PIN w0_wd_in[485]
    DIRECTION OUTPUT ;
    USE SIGNAL ;
    SHAPE ABUTMENT ;
    PORT
      LAYER met2 ;
      RECT 366.090 0.000 366.230 0.420 ;
    END
  END w0_wd_in[485]
  PIN w0_wd_in[486]
    DIRECTION OUTPUT ;
    USE SIGNAL ;
    SHAPE ABUTMENT ;
    PORT
      LAYER met2 ;
      RECT 368.390 0.000 368.530 0.420 ;
    END
  END w0_wd_in[486]
  PIN w0_wd_in[487]
    DIRECTION OUTPUT ;
    USE SIGNAL ;
    SHAPE ABUTMENT ;
    PORT
      LAYER met2 ;
      RECT 370.690 0.000 370.830 0.420 ;
    END
  END w0_wd_in[487]
  PIN w0_wd_in[488]
    DIRECTION OUTPUT ;
    USE SIGNAL ;
    SHAPE ABUTMENT ;
    PORT
      LAYER met2 ;
      RECT 372.990 0.000 373.130 0.420 ;
    END
  END w0_wd_in[488]
  PIN w0_wd_in[489]
    DIRECTION OUTPUT ;
    USE SIGNAL ;
    SHAPE ABUTMENT ;
    PORT
      LAYER met2 ;
      RECT 375.290 0.000 375.430 0.420 ;
    END
  END w0_wd_in[489]
  PIN w0_wd_in[490]
    DIRECTION OUTPUT ;
    USE SIGNAL ;
    SHAPE ABUTMENT ;
    PORT
      LAYER met2 ;
      RECT 377.590 0.000 377.730 0.420 ;
    END
  END w0_wd_in[490]
  PIN w0_wd_in[491]
    DIRECTION OUTPUT ;
    USE SIGNAL ;
    SHAPE ABUTMENT ;
    PORT
      LAYER met2 ;
      RECT 379.890 0.000 380.030 0.420 ;
    END
  END w0_wd_in[491]
  PIN w0_wd_in[492]
    DIRECTION OUTPUT ;
    USE SIGNAL ;
    SHAPE ABUTMENT ;
    PORT
      LAYER met2 ;
      RECT 382.190 0.000 382.330 0.420 ;
    END
  END w0_wd_in[492]
  PIN w0_wd_in[493]
    DIRECTION OUTPUT ;
    USE SIGNAL ;
    SHAPE ABUTMENT ;
    PORT
      LAYER met2 ;
      RECT 384.490 0.000 384.630 0.420 ;
    END
  END w0_wd_in[493]
  PIN w0_wd_in[494]
    DIRECTION OUTPUT ;
    USE SIGNAL ;
    SHAPE ABUTMENT ;
    PORT
      LAYER met2 ;
      RECT 386.790 0.000 386.930 0.420 ;
    END
  END w0_wd_in[494]
  PIN w0_wd_in[495]
    DIRECTION OUTPUT ;
    USE SIGNAL ;
    SHAPE ABUTMENT ;
    PORT
      LAYER met2 ;
      RECT 389.090 0.000 389.230 0.420 ;
    END
  END w0_wd_in[495]
  PIN w0_wd_in[496]
    DIRECTION OUTPUT ;
    USE SIGNAL ;
    SHAPE ABUTMENT ;
    PORT
      LAYER met2 ;
      RECT 391.390 0.000 391.530 0.420 ;
    END
  END w0_wd_in[496]
  PIN w0_wd_in[497]
    DIRECTION OUTPUT ;
    USE SIGNAL ;
    SHAPE ABUTMENT ;
    PORT
      LAYER met2 ;
      RECT 393.690 0.000 393.830 0.420 ;
    END
  END w0_wd_in[497]
  PIN w0_wd_in[498]
    DIRECTION OUTPUT ;
    USE SIGNAL ;
    SHAPE ABUTMENT ;
    PORT
      LAYER met2 ;
      RECT 395.990 0.000 396.130 0.420 ;
    END
  END w0_wd_in[498]
  PIN w0_wd_in[499]
    DIRECTION OUTPUT ;
    USE SIGNAL ;
    SHAPE ABUTMENT ;
    PORT
      LAYER met2 ;
      RECT 398.290 0.000 398.430 0.420 ;
    END
  END w0_wd_in[499]
  PIN w0_wd_in[500]
    DIRECTION OUTPUT ;
    USE SIGNAL ;
    SHAPE ABUTMENT ;
    PORT
      LAYER met2 ;
      RECT 400.590 0.000 400.730 0.420 ;
    END
  END w0_wd_in[500]
  PIN w0_wd_in[501]
    DIRECTION OUTPUT ;
    USE SIGNAL ;
    SHAPE ABUTMENT ;
    PORT
      LAYER met2 ;
      RECT 402.890 0.000 403.030 0.420 ;
    END
  END w0_wd_in[501]
  PIN w0_wd_in[502]
    DIRECTION OUTPUT ;
    USE SIGNAL ;
    SHAPE ABUTMENT ;
    PORT
      LAYER met2 ;
      RECT 405.190 0.000 405.330 0.420 ;
    END
  END w0_wd_in[502]
  PIN w0_wd_in[503]
    DIRECTION OUTPUT ;
    USE SIGNAL ;
    SHAPE ABUTMENT ;
    PORT
      LAYER met2 ;
      RECT 407.490 0.000 407.630 0.420 ;
    END
  END w0_wd_in[503]
  PIN w0_wd_in[504]
    DIRECTION OUTPUT ;
    USE SIGNAL ;
    SHAPE ABUTMENT ;
    PORT
      LAYER met2 ;
      RECT 409.790 0.000 409.930 0.420 ;
    END
  END w0_wd_in[504]
  PIN w0_wd_in[505]
    DIRECTION OUTPUT ;
    USE SIGNAL ;
    SHAPE ABUTMENT ;
    PORT
      LAYER met2 ;
      RECT 412.090 0.000 412.230 0.420 ;
    END
  END w0_wd_in[505]
  PIN w0_wd_in[506]
    DIRECTION OUTPUT ;
    USE SIGNAL ;
    SHAPE ABUTMENT ;
    PORT
      LAYER met2 ;
      RECT 414.390 0.000 414.530 0.420 ;
    END
  END w0_wd_in[506]
  PIN w0_wd_in[507]
    DIRECTION OUTPUT ;
    USE SIGNAL ;
    SHAPE ABUTMENT ;
    PORT
      LAYER met2 ;
      RECT 416.690 0.000 416.830 0.420 ;
    END
  END w0_wd_in[507]
  PIN w0_wd_in[508]
    DIRECTION OUTPUT ;
    USE SIGNAL ;
    SHAPE ABUTMENT ;
    PORT
      LAYER met2 ;
      RECT 418.990 0.000 419.130 0.420 ;
    END
  END w0_wd_in[508]
  PIN w0_wd_in[509]
    DIRECTION OUTPUT ;
    USE SIGNAL ;
    SHAPE ABUTMENT ;
    PORT
      LAYER met2 ;
      RECT 421.290 0.000 421.430 0.420 ;
    END
  END w0_wd_in[509]
  PIN w0_wd_in[510]
    DIRECTION OUTPUT ;
    USE SIGNAL ;
    SHAPE ABUTMENT ;
    PORT
      LAYER met2 ;
      RECT 423.590 0.000 423.730 0.420 ;
    END
  END w0_wd_in[510]
  PIN w0_wd_in[511]
    DIRECTION OUTPUT ;
    USE SIGNAL ;
    SHAPE ABUTMENT ;
    PORT
      LAYER met2 ;
      RECT 425.890 0.000 426.030 0.420 ;
    END
  END w0_wd_in[511]
  PIN w0_wd_in[512]
    DIRECTION OUTPUT ;
    USE SIGNAL ;
    SHAPE ABUTMENT ;
    PORT
      LAYER met2 ;
      RECT 428.190 0.000 428.330 0.420 ;
    END
  END w0_wd_in[512]
  PIN w0_wd_in[513]
    DIRECTION OUTPUT ;
    USE SIGNAL ;
    SHAPE ABUTMENT ;
    PORT
      LAYER met2 ;
      RECT 430.490 0.000 430.630 0.420 ;
    END
  END w0_wd_in[513]
  PIN w0_wd_in[514]
    DIRECTION OUTPUT ;
    USE SIGNAL ;
    SHAPE ABUTMENT ;
    PORT
      LAYER met2 ;
      RECT 432.790 0.000 432.930 0.420 ;
    END
  END w0_wd_in[514]
  PIN w0_wd_in[515]
    DIRECTION OUTPUT ;
    USE SIGNAL ;
    SHAPE ABUTMENT ;
    PORT
      LAYER met2 ;
      RECT 435.090 0.000 435.230 0.420 ;
    END
  END w0_wd_in[515]
  PIN w0_wd_in[516]
    DIRECTION OUTPUT ;
    USE SIGNAL ;
    SHAPE ABUTMENT ;
    PORT
      LAYER met2 ;
      RECT 437.390 0.000 437.530 0.420 ;
    END
  END w0_wd_in[516]
  PIN w0_wd_in[517]
    DIRECTION OUTPUT ;
    USE SIGNAL ;
    SHAPE ABUTMENT ;
    PORT
      LAYER met2 ;
      RECT 439.690 0.000 439.830 0.420 ;
    END
  END w0_wd_in[517]
  PIN w0_wd_in[518]
    DIRECTION OUTPUT ;
    USE SIGNAL ;
    SHAPE ABUTMENT ;
    PORT
      LAYER met2 ;
      RECT 441.990 0.000 442.130 0.420 ;
    END
  END w0_wd_in[518]
  PIN w0_wd_in[519]
    DIRECTION OUTPUT ;
    USE SIGNAL ;
    SHAPE ABUTMENT ;
    PORT
      LAYER met2 ;
      RECT 444.290 0.000 444.430 0.420 ;
    END
  END w0_wd_in[519]
  PIN w0_wd_in[520]
    DIRECTION OUTPUT ;
    USE SIGNAL ;
    SHAPE ABUTMENT ;
    PORT
      LAYER met2 ;
      RECT 446.590 0.000 446.730 0.420 ;
    END
  END w0_wd_in[520]
  PIN w0_wd_in[521]
    DIRECTION OUTPUT ;
    USE SIGNAL ;
    SHAPE ABUTMENT ;
    PORT
      LAYER met2 ;
      RECT 448.890 0.000 449.030 0.420 ;
    END
  END w0_wd_in[521]
  PIN w0_wd_in[522]
    DIRECTION OUTPUT ;
    USE SIGNAL ;
    SHAPE ABUTMENT ;
    PORT
      LAYER met2 ;
      RECT 451.190 0.000 451.330 0.420 ;
    END
  END w0_wd_in[522]
  PIN w0_wd_in[523]
    DIRECTION OUTPUT ;
    USE SIGNAL ;
    SHAPE ABUTMENT ;
    PORT
      LAYER met2 ;
      RECT 453.490 0.000 453.630 0.420 ;
    END
  END w0_wd_in[523]
  PIN w0_wd_in[524]
    DIRECTION OUTPUT ;
    USE SIGNAL ;
    SHAPE ABUTMENT ;
    PORT
      LAYER met2 ;
      RECT 455.790 0.000 455.930 0.420 ;
    END
  END w0_wd_in[524]
  PIN w0_wd_in[525]
    DIRECTION OUTPUT ;
    USE SIGNAL ;
    SHAPE ABUTMENT ;
    PORT
      LAYER met2 ;
      RECT 458.090 0.000 458.230 0.420 ;
    END
  END w0_wd_in[525]
  PIN w0_wd_in[526]
    DIRECTION OUTPUT ;
    USE SIGNAL ;
    SHAPE ABUTMENT ;
    PORT
      LAYER met2 ;
      RECT 460.390 0.000 460.530 0.420 ;
    END
  END w0_wd_in[526]
  PIN w0_wd_in[527]
    DIRECTION OUTPUT ;
    USE SIGNAL ;
    SHAPE ABUTMENT ;
    PORT
      LAYER met2 ;
      RECT 462.690 0.000 462.830 0.420 ;
    END
  END w0_wd_in[527]
  PIN w0_wd_in[528]
    DIRECTION OUTPUT ;
    USE SIGNAL ;
    SHAPE ABUTMENT ;
    PORT
      LAYER met2 ;
      RECT 464.990 0.000 465.130 0.420 ;
    END
  END w0_wd_in[528]
  PIN w0_wd_in[529]
    DIRECTION OUTPUT ;
    USE SIGNAL ;
    SHAPE ABUTMENT ;
    PORT
      LAYER met2 ;
      RECT 467.290 0.000 467.430 0.420 ;
    END
  END w0_wd_in[529]
  PIN w0_wd_in[530]
    DIRECTION OUTPUT ;
    USE SIGNAL ;
    SHAPE ABUTMENT ;
    PORT
      LAYER met2 ;
      RECT 469.590 0.000 469.730 0.420 ;
    END
  END w0_wd_in[530]
  PIN w0_wd_in[531]
    DIRECTION OUTPUT ;
    USE SIGNAL ;
    SHAPE ABUTMENT ;
    PORT
      LAYER met2 ;
      RECT 471.890 0.000 472.030 0.420 ;
    END
  END w0_wd_in[531]
  PIN w0_wd_in[532]
    DIRECTION OUTPUT ;
    USE SIGNAL ;
    SHAPE ABUTMENT ;
    PORT
      LAYER met2 ;
      RECT 474.190 0.000 474.330 0.420 ;
    END
  END w0_wd_in[532]
  PIN w0_wd_in[533]
    DIRECTION OUTPUT ;
    USE SIGNAL ;
    SHAPE ABUTMENT ;
    PORT
      LAYER met2 ;
      RECT 476.490 0.000 476.630 0.420 ;
    END
  END w0_wd_in[533]
  PIN w0_wd_in[534]
    DIRECTION OUTPUT ;
    USE SIGNAL ;
    SHAPE ABUTMENT ;
    PORT
      LAYER met2 ;
      RECT 478.790 0.000 478.930 0.420 ;
    END
  END w0_wd_in[534]
  PIN w0_wd_in[535]
    DIRECTION OUTPUT ;
    USE SIGNAL ;
    SHAPE ABUTMENT ;
    PORT
      LAYER met2 ;
      RECT 481.090 0.000 481.230 0.420 ;
    END
  END w0_wd_in[535]
  PIN w0_wd_in[536]
    DIRECTION OUTPUT ;
    USE SIGNAL ;
    SHAPE ABUTMENT ;
    PORT
      LAYER met2 ;
      RECT 483.390 0.000 483.530 0.420 ;
    END
  END w0_wd_in[536]
  PIN w0_wd_in[537]
    DIRECTION OUTPUT ;
    USE SIGNAL ;
    SHAPE ABUTMENT ;
    PORT
      LAYER met2 ;
      RECT 485.690 0.000 485.830 0.420 ;
    END
  END w0_wd_in[537]
  PIN w0_wd_in[538]
    DIRECTION OUTPUT ;
    USE SIGNAL ;
    SHAPE ABUTMENT ;
    PORT
      LAYER met2 ;
      RECT 487.990 0.000 488.130 0.420 ;
    END
  END w0_wd_in[538]
  PIN w0_wd_in[539]
    DIRECTION OUTPUT ;
    USE SIGNAL ;
    SHAPE ABUTMENT ;
    PORT
      LAYER met2 ;
      RECT 490.290 0.000 490.430 0.420 ;
    END
  END w0_wd_in[539]
  PIN w0_wd_in[540]
    DIRECTION OUTPUT ;
    USE SIGNAL ;
    SHAPE ABUTMENT ;
    PORT
      LAYER met2 ;
      RECT 492.590 0.000 492.730 0.420 ;
    END
  END w0_wd_in[540]
  PIN w0_wd_in[541]
    DIRECTION OUTPUT ;
    USE SIGNAL ;
    SHAPE ABUTMENT ;
    PORT
      LAYER met2 ;
      RECT 494.890 0.000 495.030 0.420 ;
    END
  END w0_wd_in[541]
  PIN w0_wd_in[542]
    DIRECTION OUTPUT ;
    USE SIGNAL ;
    SHAPE ABUTMENT ;
    PORT
      LAYER met2 ;
      RECT 497.190 0.000 497.330 0.420 ;
    END
  END w0_wd_in[542]
  PIN w0_wd_in[543]
    DIRECTION OUTPUT ;
    USE SIGNAL ;
    SHAPE ABUTMENT ;
    PORT
      LAYER met2 ;
      RECT 499.490 0.000 499.630 0.420 ;
    END
  END w0_wd_in[543]
  PIN w0_wd_in[544]
    DIRECTION OUTPUT ;
    USE SIGNAL ;
    SHAPE ABUTMENT ;
    PORT
      LAYER met2 ;
      RECT 501.790 0.000 501.930 0.420 ;
    END
  END w0_wd_in[544]
  PIN w0_wd_in[545]
    DIRECTION OUTPUT ;
    USE SIGNAL ;
    SHAPE ABUTMENT ;
    PORT
      LAYER met2 ;
      RECT 504.090 0.000 504.230 0.420 ;
    END
  END w0_wd_in[545]
  PIN w0_wd_in[546]
    DIRECTION OUTPUT ;
    USE SIGNAL ;
    SHAPE ABUTMENT ;
    PORT
      LAYER met2 ;
      RECT 506.390 0.000 506.530 0.420 ;
    END
  END w0_wd_in[546]
  PIN w0_wd_in[547]
    DIRECTION OUTPUT ;
    USE SIGNAL ;
    SHAPE ABUTMENT ;
    PORT
      LAYER met2 ;
      RECT 508.690 0.000 508.830 0.420 ;
    END
  END w0_wd_in[547]
  PIN w0_wd_in[548]
    DIRECTION OUTPUT ;
    USE SIGNAL ;
    SHAPE ABUTMENT ;
    PORT
      LAYER met2 ;
      RECT 510.990 0.000 511.130 0.420 ;
    END
  END w0_wd_in[548]
  PIN w0_wd_in[549]
    DIRECTION OUTPUT ;
    USE SIGNAL ;
    SHAPE ABUTMENT ;
    PORT
      LAYER met2 ;
      RECT 513.290 0.000 513.430 0.420 ;
    END
  END w0_wd_in[549]
  PIN w0_wd_in[550]
    DIRECTION OUTPUT ;
    USE SIGNAL ;
    SHAPE ABUTMENT ;
    PORT
      LAYER met2 ;
      RECT 515.590 0.000 515.730 0.420 ;
    END
  END w0_wd_in[550]
  PIN w0_wd_in[551]
    DIRECTION OUTPUT ;
    USE SIGNAL ;
    SHAPE ABUTMENT ;
    PORT
      LAYER met2 ;
      RECT 517.890 0.000 518.030 0.420 ;
    END
  END w0_wd_in[551]
  PIN w0_wd_in[552]
    DIRECTION OUTPUT ;
    USE SIGNAL ;
    SHAPE ABUTMENT ;
    PORT
      LAYER met2 ;
      RECT 520.190 0.000 520.330 0.420 ;
    END
  END w0_wd_in[552]
  PIN w0_wd_in[553]
    DIRECTION OUTPUT ;
    USE SIGNAL ;
    SHAPE ABUTMENT ;
    PORT
      LAYER met2 ;
      RECT 522.490 0.000 522.630 0.420 ;
    END
  END w0_wd_in[553]
  PIN w0_wd_in[554]
    DIRECTION OUTPUT ;
    USE SIGNAL ;
    SHAPE ABUTMENT ;
    PORT
      LAYER met2 ;
      RECT 524.790 0.000 524.930 0.420 ;
    END
  END w0_wd_in[554]
  PIN w0_wd_in[555]
    DIRECTION OUTPUT ;
    USE SIGNAL ;
    SHAPE ABUTMENT ;
    PORT
      LAYER met2 ;
      RECT 527.090 0.000 527.230 0.420 ;
    END
  END w0_wd_in[555]
  PIN w0_wd_in[556]
    DIRECTION OUTPUT ;
    USE SIGNAL ;
    SHAPE ABUTMENT ;
    PORT
      LAYER met2 ;
      RECT 529.390 0.000 529.530 0.420 ;
    END
  END w0_wd_in[556]
  PIN w0_wd_in[557]
    DIRECTION OUTPUT ;
    USE SIGNAL ;
    SHAPE ABUTMENT ;
    PORT
      LAYER met2 ;
      RECT 531.690 0.000 531.830 0.420 ;
    END
  END w0_wd_in[557]
  PIN w0_wd_in[558]
    DIRECTION OUTPUT ;
    USE SIGNAL ;
    SHAPE ABUTMENT ;
    PORT
      LAYER met2 ;
      RECT 533.990 0.000 534.130 0.420 ;
    END
  END w0_wd_in[558]
  PIN w0_wd_in[559]
    DIRECTION OUTPUT ;
    USE SIGNAL ;
    SHAPE ABUTMENT ;
    PORT
      LAYER met2 ;
      RECT 536.290 0.000 536.430 0.420 ;
    END
  END w0_wd_in[559]
  PIN w0_wd_in[560]
    DIRECTION OUTPUT ;
    USE SIGNAL ;
    SHAPE ABUTMENT ;
    PORT
      LAYER met2 ;
      RECT 538.590 0.000 538.730 0.420 ;
    END
  END w0_wd_in[560]
  PIN w0_wd_in[561]
    DIRECTION OUTPUT ;
    USE SIGNAL ;
    SHAPE ABUTMENT ;
    PORT
      LAYER met2 ;
      RECT 540.890 0.000 541.030 0.420 ;
    END
  END w0_wd_in[561]
  PIN w0_wd_in[562]
    DIRECTION OUTPUT ;
    USE SIGNAL ;
    SHAPE ABUTMENT ;
    PORT
      LAYER met2 ;
      RECT 543.190 0.000 543.330 0.420 ;
    END
  END w0_wd_in[562]
  PIN w0_wd_in[563]
    DIRECTION OUTPUT ;
    USE SIGNAL ;
    SHAPE ABUTMENT ;
    PORT
      LAYER met2 ;
      RECT 545.490 0.000 545.630 0.420 ;
    END
  END w0_wd_in[563]
  PIN w0_wd_in[564]
    DIRECTION OUTPUT ;
    USE SIGNAL ;
    SHAPE ABUTMENT ;
    PORT
      LAYER met2 ;
      RECT 547.790 0.000 547.930 0.420 ;
    END
  END w0_wd_in[564]
  PIN w0_wd_in[565]
    DIRECTION OUTPUT ;
    USE SIGNAL ;
    SHAPE ABUTMENT ;
    PORT
      LAYER met2 ;
      RECT 550.090 0.000 550.230 0.420 ;
    END
  END w0_wd_in[565]
  PIN w0_wd_in[566]
    DIRECTION OUTPUT ;
    USE SIGNAL ;
    SHAPE ABUTMENT ;
    PORT
      LAYER met2 ;
      RECT 552.390 0.000 552.530 0.420 ;
    END
  END w0_wd_in[566]
  PIN w0_wd_in[567]
    DIRECTION OUTPUT ;
    USE SIGNAL ;
    SHAPE ABUTMENT ;
    PORT
      LAYER met2 ;
      RECT 554.690 0.000 554.830 0.420 ;
    END
  END w0_wd_in[567]
  PIN w0_wd_in[568]
    DIRECTION OUTPUT ;
    USE SIGNAL ;
    SHAPE ABUTMENT ;
    PORT
      LAYER met2 ;
      RECT 556.990 0.000 557.130 0.420 ;
    END
  END w0_wd_in[568]
  PIN w0_wd_in[569]
    DIRECTION OUTPUT ;
    USE SIGNAL ;
    SHAPE ABUTMENT ;
    PORT
      LAYER met2 ;
      RECT 559.290 0.000 559.430 0.420 ;
    END
  END w0_wd_in[569]
  PIN w0_wd_in[570]
    DIRECTION OUTPUT ;
    USE SIGNAL ;
    SHAPE ABUTMENT ;
    PORT
      LAYER met2 ;
      RECT 561.590 0.000 561.730 0.420 ;
    END
  END w0_wd_in[570]
  PIN w0_wd_in[571]
    DIRECTION OUTPUT ;
    USE SIGNAL ;
    SHAPE ABUTMENT ;
    PORT
      LAYER met2 ;
      RECT 563.890 0.000 564.030 0.420 ;
    END
  END w0_wd_in[571]
  PIN w0_wd_in[572]
    DIRECTION OUTPUT ;
    USE SIGNAL ;
    SHAPE ABUTMENT ;
    PORT
      LAYER met2 ;
      RECT 566.190 0.000 566.330 0.420 ;
    END
  END w0_wd_in[572]
  PIN w0_wd_in[573]
    DIRECTION OUTPUT ;
    USE SIGNAL ;
    SHAPE ABUTMENT ;
    PORT
      LAYER met2 ;
      RECT 568.490 0.000 568.630 0.420 ;
    END
  END w0_wd_in[573]
  PIN w0_wd_in[574]
    DIRECTION OUTPUT ;
    USE SIGNAL ;
    SHAPE ABUTMENT ;
    PORT
      LAYER met2 ;
      RECT 570.790 0.000 570.930 0.420 ;
    END
  END w0_wd_in[574]
  PIN w0_wd_in[575]
    DIRECTION OUTPUT ;
    USE SIGNAL ;
    SHAPE ABUTMENT ;
    PORT
      LAYER met2 ;
      RECT 573.090 0.000 573.230 0.420 ;
    END
  END w0_wd_in[575]
  PIN w0_wd_in[576]
    DIRECTION OUTPUT ;
    USE SIGNAL ;
    SHAPE ABUTMENT ;
    PORT
      LAYER met2 ;
      RECT 575.390 0.000 575.530 0.420 ;
    END
  END w0_wd_in[576]
  PIN w0_wd_in[577]
    DIRECTION OUTPUT ;
    USE SIGNAL ;
    SHAPE ABUTMENT ;
    PORT
      LAYER met2 ;
      RECT 577.690 0.000 577.830 0.420 ;
    END
  END w0_wd_in[577]
  PIN w0_wd_in[578]
    DIRECTION OUTPUT ;
    USE SIGNAL ;
    SHAPE ABUTMENT ;
    PORT
      LAYER met2 ;
      RECT 579.990 0.000 580.130 0.420 ;
    END
  END w0_wd_in[578]
  PIN w0_wd_in[579]
    DIRECTION OUTPUT ;
    USE SIGNAL ;
    SHAPE ABUTMENT ;
    PORT
      LAYER met2 ;
      RECT 582.290 0.000 582.430 0.420 ;
    END
  END w0_wd_in[579]
  PIN w0_wd_in[580]
    DIRECTION OUTPUT ;
    USE SIGNAL ;
    SHAPE ABUTMENT ;
    PORT
      LAYER met2 ;
      RECT 584.590 0.000 584.730 0.420 ;
    END
  END w0_wd_in[580]
  PIN w0_wd_in[581]
    DIRECTION OUTPUT ;
    USE SIGNAL ;
    SHAPE ABUTMENT ;
    PORT
      LAYER met2 ;
      RECT 586.890 0.000 587.030 0.420 ;
    END
  END w0_wd_in[581]
  PIN w0_wd_in[582]
    DIRECTION OUTPUT ;
    USE SIGNAL ;
    SHAPE ABUTMENT ;
    PORT
      LAYER met2 ;
      RECT 589.190 0.000 589.330 0.420 ;
    END
  END w0_wd_in[582]
  PIN w0_wd_in[583]
    DIRECTION OUTPUT ;
    USE SIGNAL ;
    SHAPE ABUTMENT ;
    PORT
      LAYER met2 ;
      RECT 591.490 0.000 591.630 0.420 ;
    END
  END w0_wd_in[583]
  PIN w0_wd_in[584]
    DIRECTION OUTPUT ;
    USE SIGNAL ;
    SHAPE ABUTMENT ;
    PORT
      LAYER met2 ;
      RECT 593.790 0.000 593.930 0.420 ;
    END
  END w0_wd_in[584]
  PIN w0_wd_in[585]
    DIRECTION OUTPUT ;
    USE SIGNAL ;
    SHAPE ABUTMENT ;
    PORT
      LAYER met2 ;
      RECT 596.090 0.000 596.230 0.420 ;
    END
  END w0_wd_in[585]
  PIN w0_wd_in[586]
    DIRECTION OUTPUT ;
    USE SIGNAL ;
    SHAPE ABUTMENT ;
    PORT
      LAYER met2 ;
      RECT 598.390 0.000 598.530 0.420 ;
    END
  END w0_wd_in[586]
  PIN w0_wd_in[587]
    DIRECTION OUTPUT ;
    USE SIGNAL ;
    SHAPE ABUTMENT ;
    PORT
      LAYER met2 ;
      RECT 600.690 0.000 600.830 0.420 ;
    END
  END w0_wd_in[587]
  PIN w0_wd_in[588]
    DIRECTION OUTPUT ;
    USE SIGNAL ;
    SHAPE ABUTMENT ;
    PORT
      LAYER met2 ;
      RECT 602.990 0.000 603.130 0.420 ;
    END
  END w0_wd_in[588]
  PIN w0_wd_in[589]
    DIRECTION OUTPUT ;
    USE SIGNAL ;
    SHAPE ABUTMENT ;
    PORT
      LAYER met2 ;
      RECT 605.290 0.000 605.430 0.420 ;
    END
  END w0_wd_in[589]
  PIN w0_wd_in[590]
    DIRECTION OUTPUT ;
    USE SIGNAL ;
    SHAPE ABUTMENT ;
    PORT
      LAYER met2 ;
      RECT 607.590 0.000 607.730 0.420 ;
    END
  END w0_wd_in[590]
  PIN w0_wd_in[591]
    DIRECTION OUTPUT ;
    USE SIGNAL ;
    SHAPE ABUTMENT ;
    PORT
      LAYER met2 ;
      RECT 609.890 0.000 610.030 0.420 ;
    END
  END w0_wd_in[591]
  PIN w0_wd_in[592]
    DIRECTION OUTPUT ;
    USE SIGNAL ;
    SHAPE ABUTMENT ;
    PORT
      LAYER met2 ;
      RECT 612.190 0.000 612.330 0.420 ;
    END
  END w0_wd_in[592]
  PIN w0_wd_in[593]
    DIRECTION OUTPUT ;
    USE SIGNAL ;
    SHAPE ABUTMENT ;
    PORT
      LAYER met2 ;
      RECT 614.490 0.000 614.630 0.420 ;
    END
  END w0_wd_in[593]
  PIN w0_wd_in[594]
    DIRECTION OUTPUT ;
    USE SIGNAL ;
    SHAPE ABUTMENT ;
    PORT
      LAYER met2 ;
      RECT 616.790 0.000 616.930 0.420 ;
    END
  END w0_wd_in[594]
  PIN w0_wd_in[595]
    DIRECTION OUTPUT ;
    USE SIGNAL ;
    SHAPE ABUTMENT ;
    PORT
      LAYER met2 ;
      RECT 619.090 0.000 619.230 0.420 ;
    END
  END w0_wd_in[595]
  PIN w0_wd_in[596]
    DIRECTION OUTPUT ;
    USE SIGNAL ;
    SHAPE ABUTMENT ;
    PORT
      LAYER met2 ;
      RECT 621.390 0.000 621.530 0.420 ;
    END
  END w0_wd_in[596]
  PIN w0_wd_in[597]
    DIRECTION OUTPUT ;
    USE SIGNAL ;
    SHAPE ABUTMENT ;
    PORT
      LAYER met2 ;
      RECT 623.690 0.000 623.830 0.420 ;
    END
  END w0_wd_in[597]
  PIN w0_wd_in[598]
    DIRECTION OUTPUT ;
    USE SIGNAL ;
    SHAPE ABUTMENT ;
    PORT
      LAYER met2 ;
      RECT 625.990 0.000 626.130 0.420 ;
    END
  END w0_wd_in[598]
  PIN w0_wd_in[599]
    DIRECTION OUTPUT ;
    USE SIGNAL ;
    SHAPE ABUTMENT ;
    PORT
      LAYER met2 ;
      RECT 628.290 0.000 628.430 0.420 ;
    END
  END w0_wd_in[599]
  PIN w0_wd_in[600]
    DIRECTION OUTPUT ;
    USE SIGNAL ;
    SHAPE ABUTMENT ;
    PORT
      LAYER met2 ;
      RECT 630.590 0.000 630.730 0.420 ;
    END
  END w0_wd_in[600]
  PIN w0_wd_in[601]
    DIRECTION OUTPUT ;
    USE SIGNAL ;
    SHAPE ABUTMENT ;
    PORT
      LAYER met2 ;
      RECT 632.890 0.000 633.030 0.420 ;
    END
  END w0_wd_in[601]
  PIN w0_wd_in[602]
    DIRECTION OUTPUT ;
    USE SIGNAL ;
    SHAPE ABUTMENT ;
    PORT
      LAYER met2 ;
      RECT 635.190 0.000 635.330 0.420 ;
    END
  END w0_wd_in[602]
  PIN w0_wd_in[603]
    DIRECTION OUTPUT ;
    USE SIGNAL ;
    SHAPE ABUTMENT ;
    PORT
      LAYER met2 ;
      RECT 637.490 0.000 637.630 0.420 ;
    END
  END w0_wd_in[603]
  PIN w0_wd_in[604]
    DIRECTION OUTPUT ;
    USE SIGNAL ;
    SHAPE ABUTMENT ;
    PORT
      LAYER met2 ;
      RECT 639.790 0.000 639.930 0.420 ;
    END
  END w0_wd_in[604]
  PIN w0_wd_in[605]
    DIRECTION OUTPUT ;
    USE SIGNAL ;
    SHAPE ABUTMENT ;
    PORT
      LAYER met2 ;
      RECT 642.090 0.000 642.230 0.420 ;
    END
  END w0_wd_in[605]
  PIN w0_wd_in[606]
    DIRECTION OUTPUT ;
    USE SIGNAL ;
    SHAPE ABUTMENT ;
    PORT
      LAYER met2 ;
      RECT 644.390 0.000 644.530 0.420 ;
    END
  END w0_wd_in[606]
  PIN w0_wd_in[607]
    DIRECTION OUTPUT ;
    USE SIGNAL ;
    SHAPE ABUTMENT ;
    PORT
      LAYER met2 ;
      RECT 646.690 0.000 646.830 0.420 ;
    END
  END w0_wd_in[607]
  PIN w0_wd_in[608]
    DIRECTION OUTPUT ;
    USE SIGNAL ;
    SHAPE ABUTMENT ;
    PORT
      LAYER met2 ;
      RECT 648.990 0.000 649.130 0.420 ;
    END
  END w0_wd_in[608]
  PIN w0_wd_in[609]
    DIRECTION OUTPUT ;
    USE SIGNAL ;
    SHAPE ABUTMENT ;
    PORT
      LAYER met2 ;
      RECT 651.290 0.000 651.430 0.420 ;
    END
  END w0_wd_in[609]
  PIN w0_wd_in[610]
    DIRECTION OUTPUT ;
    USE SIGNAL ;
    SHAPE ABUTMENT ;
    PORT
      LAYER met2 ;
      RECT 653.590 0.000 653.730 0.420 ;
    END
  END w0_wd_in[610]
  PIN w0_wd_in[611]
    DIRECTION OUTPUT ;
    USE SIGNAL ;
    SHAPE ABUTMENT ;
    PORT
      LAYER met2 ;
      RECT 655.890 0.000 656.030 0.420 ;
    END
  END w0_wd_in[611]
  PIN w0_wd_in[612]
    DIRECTION OUTPUT ;
    USE SIGNAL ;
    SHAPE ABUTMENT ;
    PORT
      LAYER met2 ;
      RECT 658.190 0.000 658.330 0.420 ;
    END
  END w0_wd_in[612]
  PIN w0_wd_in[613]
    DIRECTION OUTPUT ;
    USE SIGNAL ;
    SHAPE ABUTMENT ;
    PORT
      LAYER met2 ;
      RECT 660.490 0.000 660.630 0.420 ;
    END
  END w0_wd_in[613]
  PIN w0_wd_in[614]
    DIRECTION OUTPUT ;
    USE SIGNAL ;
    SHAPE ABUTMENT ;
    PORT
      LAYER met2 ;
      RECT 662.790 0.000 662.930 0.420 ;
    END
  END w0_wd_in[614]
  PIN w0_wd_in[615]
    DIRECTION OUTPUT ;
    USE SIGNAL ;
    SHAPE ABUTMENT ;
    PORT
      LAYER met2 ;
      RECT 665.090 0.000 665.230 0.420 ;
    END
  END w0_wd_in[615]
  PIN w0_wd_in[616]
    DIRECTION OUTPUT ;
    USE SIGNAL ;
    SHAPE ABUTMENT ;
    PORT
      LAYER met2 ;
      RECT 667.390 0.000 667.530 0.420 ;
    END
  END w0_wd_in[616]
  PIN w0_wd_in[617]
    DIRECTION OUTPUT ;
    USE SIGNAL ;
    SHAPE ABUTMENT ;
    PORT
      LAYER met2 ;
      RECT 669.690 0.000 669.830 0.420 ;
    END
  END w0_wd_in[617]
  PIN w0_wd_in[618]
    DIRECTION OUTPUT ;
    USE SIGNAL ;
    SHAPE ABUTMENT ;
    PORT
      LAYER met2 ;
      RECT 671.990 0.000 672.130 0.420 ;
    END
  END w0_wd_in[618]
  PIN w0_wd_in[619]
    DIRECTION OUTPUT ;
    USE SIGNAL ;
    SHAPE ABUTMENT ;
    PORT
      LAYER met2 ;
      RECT 674.290 0.000 674.430 0.420 ;
    END
  END w0_wd_in[619]
  PIN w0_wd_in[620]
    DIRECTION OUTPUT ;
    USE SIGNAL ;
    SHAPE ABUTMENT ;
    PORT
      LAYER met2 ;
      RECT 676.590 0.000 676.730 0.420 ;
    END
  END w0_wd_in[620]
  PIN w0_wd_in[621]
    DIRECTION OUTPUT ;
    USE SIGNAL ;
    SHAPE ABUTMENT ;
    PORT
      LAYER met2 ;
      RECT 678.890 0.000 679.030 0.420 ;
    END
  END w0_wd_in[621]
  PIN w0_wd_in[622]
    DIRECTION OUTPUT ;
    USE SIGNAL ;
    SHAPE ABUTMENT ;
    PORT
      LAYER met2 ;
      RECT 681.190 0.000 681.330 0.420 ;
    END
  END w0_wd_in[622]
  PIN w0_wd_in[623]
    DIRECTION OUTPUT ;
    USE SIGNAL ;
    SHAPE ABUTMENT ;
    PORT
      LAYER met2 ;
      RECT 683.490 0.000 683.630 0.420 ;
    END
  END w0_wd_in[623]
  PIN w0_wd_in[624]
    DIRECTION OUTPUT ;
    USE SIGNAL ;
    SHAPE ABUTMENT ;
    PORT
      LAYER met2 ;
      RECT 685.790 0.000 685.930 0.420 ;
    END
  END w0_wd_in[624]
  PIN w0_wd_in[625]
    DIRECTION OUTPUT ;
    USE SIGNAL ;
    SHAPE ABUTMENT ;
    PORT
      LAYER met2 ;
      RECT 688.090 0.000 688.230 0.420 ;
    END
  END w0_wd_in[625]
  PIN w0_wd_in[626]
    DIRECTION OUTPUT ;
    USE SIGNAL ;
    SHAPE ABUTMENT ;
    PORT
      LAYER met2 ;
      RECT 690.390 0.000 690.530 0.420 ;
    END
  END w0_wd_in[626]
  PIN w0_wd_in[627]
    DIRECTION OUTPUT ;
    USE SIGNAL ;
    SHAPE ABUTMENT ;
    PORT
      LAYER met2 ;
      RECT 692.690 0.000 692.830 0.420 ;
    END
  END w0_wd_in[627]
  PIN w0_wd_in[628]
    DIRECTION OUTPUT ;
    USE SIGNAL ;
    SHAPE ABUTMENT ;
    PORT
      LAYER met2 ;
      RECT 694.990 0.000 695.130 0.420 ;
    END
  END w0_wd_in[628]
  PIN w0_wd_in[629]
    DIRECTION OUTPUT ;
    USE SIGNAL ;
    SHAPE ABUTMENT ;
    PORT
      LAYER met2 ;
      RECT 697.290 0.000 697.430 0.420 ;
    END
  END w0_wd_in[629]
  PIN w0_wd_in[630]
    DIRECTION OUTPUT ;
    USE SIGNAL ;
    SHAPE ABUTMENT ;
    PORT
      LAYER met2 ;
      RECT 699.590 0.000 699.730 0.420 ;
    END
  END w0_wd_in[630]
  PIN w0_wd_in[631]
    DIRECTION OUTPUT ;
    USE SIGNAL ;
    SHAPE ABUTMENT ;
    PORT
      LAYER met2 ;
      RECT 701.890 0.000 702.030 0.420 ;
    END
  END w0_wd_in[631]
  PIN w0_wd_in[632]
    DIRECTION OUTPUT ;
    USE SIGNAL ;
    SHAPE ABUTMENT ;
    PORT
      LAYER met2 ;
      RECT 704.190 0.000 704.330 0.420 ;
    END
  END w0_wd_in[632]
  PIN w0_wd_in[633]
    DIRECTION OUTPUT ;
    USE SIGNAL ;
    SHAPE ABUTMENT ;
    PORT
      LAYER met2 ;
      RECT 706.490 0.000 706.630 0.420 ;
    END
  END w0_wd_in[633]
  PIN w0_wd_in[634]
    DIRECTION OUTPUT ;
    USE SIGNAL ;
    SHAPE ABUTMENT ;
    PORT
      LAYER met2 ;
      RECT 708.790 0.000 708.930 0.420 ;
    END
  END w0_wd_in[634]
  PIN w0_wd_in[635]
    DIRECTION OUTPUT ;
    USE SIGNAL ;
    SHAPE ABUTMENT ;
    PORT
      LAYER met2 ;
      RECT 711.090 0.000 711.230 0.420 ;
    END
  END w0_wd_in[635]
  PIN w0_wd_in[636]
    DIRECTION OUTPUT ;
    USE SIGNAL ;
    SHAPE ABUTMENT ;
    PORT
      LAYER met2 ;
      RECT 713.390 0.000 713.530 0.420 ;
    END
  END w0_wd_in[636]
  PIN w0_wd_in[637]
    DIRECTION OUTPUT ;
    USE SIGNAL ;
    SHAPE ABUTMENT ;
    PORT
      LAYER met2 ;
      RECT 715.690 0.000 715.830 0.420 ;
    END
  END w0_wd_in[637]
  PIN w0_wd_in[638]
    DIRECTION OUTPUT ;
    USE SIGNAL ;
    SHAPE ABUTMENT ;
    PORT
      LAYER met2 ;
      RECT 717.990 0.000 718.130 0.420 ;
    END
  END w0_wd_in[638]
  PIN w0_wd_in[639]
    DIRECTION OUTPUT ;
    USE SIGNAL ;
    SHAPE ABUTMENT ;
    PORT
      LAYER met2 ;
      RECT 720.290 0.000 720.430 0.420 ;
    END
  END w0_wd_in[639]
  PIN w0_wd_in[640]
    DIRECTION OUTPUT ;
    USE SIGNAL ;
    SHAPE ABUTMENT ;
    PORT
      LAYER met2 ;
      RECT 722.590 0.000 722.730 0.420 ;
    END
  END w0_wd_in[640]
  PIN w0_wd_in[641]
    DIRECTION OUTPUT ;
    USE SIGNAL ;
    SHAPE ABUTMENT ;
    PORT
      LAYER met2 ;
      RECT 724.890 0.000 725.030 0.420 ;
    END
  END w0_wd_in[641]
  PIN w0_wd_in[642]
    DIRECTION OUTPUT ;
    USE SIGNAL ;
    SHAPE ABUTMENT ;
    PORT
      LAYER met2 ;
      RECT 727.190 0.000 727.330 0.420 ;
    END
  END w0_wd_in[642]
  PIN w0_wd_in[643]
    DIRECTION OUTPUT ;
    USE SIGNAL ;
    SHAPE ABUTMENT ;
    PORT
      LAYER met2 ;
      RECT 729.490 0.000 729.630 0.420 ;
    END
  END w0_wd_in[643]
  PIN w0_wd_in[644]
    DIRECTION OUTPUT ;
    USE SIGNAL ;
    SHAPE ABUTMENT ;
    PORT
      LAYER met2 ;
      RECT 731.790 0.000 731.930 0.420 ;
    END
  END w0_wd_in[644]
  PIN w0_wd_in[645]
    DIRECTION OUTPUT ;
    USE SIGNAL ;
    SHAPE ABUTMENT ;
    PORT
      LAYER met2 ;
      RECT 734.090 0.000 734.230 0.420 ;
    END
  END w0_wd_in[645]
  PIN w0_wd_in[646]
    DIRECTION OUTPUT ;
    USE SIGNAL ;
    SHAPE ABUTMENT ;
    PORT
      LAYER met2 ;
      RECT 736.390 0.000 736.530 0.420 ;
    END
  END w0_wd_in[646]
  PIN w0_wd_in[647]
    DIRECTION OUTPUT ;
    USE SIGNAL ;
    SHAPE ABUTMENT ;
    PORT
      LAYER met2 ;
      RECT 738.690 0.000 738.830 0.420 ;
    END
  END w0_wd_in[647]
  PIN w0_wd_in[648]
    DIRECTION OUTPUT ;
    USE SIGNAL ;
    SHAPE ABUTMENT ;
    PORT
      LAYER met2 ;
      RECT 740.990 0.000 741.130 0.420 ;
    END
  END w0_wd_in[648]
  PIN w0_wd_in[649]
    DIRECTION OUTPUT ;
    USE SIGNAL ;
    SHAPE ABUTMENT ;
    PORT
      LAYER met2 ;
      RECT 743.290 0.000 743.430 0.420 ;
    END
  END w0_wd_in[649]
  PIN w0_wd_in[650]
    DIRECTION OUTPUT ;
    USE SIGNAL ;
    SHAPE ABUTMENT ;
    PORT
      LAYER met2 ;
      RECT 745.590 0.000 745.730 0.420 ;
    END
  END w0_wd_in[650]
  PIN w0_wd_in[651]
    DIRECTION OUTPUT ;
    USE SIGNAL ;
    SHAPE ABUTMENT ;
    PORT
      LAYER met2 ;
      RECT 747.890 0.000 748.030 0.420 ;
    END
  END w0_wd_in[651]
  PIN w0_wd_in[652]
    DIRECTION OUTPUT ;
    USE SIGNAL ;
    SHAPE ABUTMENT ;
    PORT
      LAYER met2 ;
      RECT 750.190 0.000 750.330 0.420 ;
    END
  END w0_wd_in[652]
  PIN w0_wd_in[653]
    DIRECTION OUTPUT ;
    USE SIGNAL ;
    SHAPE ABUTMENT ;
    PORT
      LAYER met2 ;
      RECT 752.490 0.000 752.630 0.420 ;
    END
  END w0_wd_in[653]
  PIN r0_rd_out[0]
    DIRECTION OUTPUT ;
    USE SIGNAL ;
    SHAPE ABUTMENT ;
    PORT
      LAYER met2 ;
      RECT 754.790 0.000 754.930 0.420 ;
    END
  END r0_rd_out[0]
  PIN r0_rd_out[1]
    DIRECTION OUTPUT ;
    USE SIGNAL ;
    SHAPE ABUTMENT ;
    PORT
      LAYER met2 ;
      RECT 757.090 0.000 757.230 0.420 ;
    END
  END r0_rd_out[1]
  PIN r0_rd_out[2]
    DIRECTION OUTPUT ;
    USE SIGNAL ;
    SHAPE ABUTMENT ;
    PORT
      LAYER met2 ;
      RECT 759.390 0.000 759.530 0.420 ;
    END
  END r0_rd_out[2]
  PIN r0_rd_out[3]
    DIRECTION OUTPUT ;
    USE SIGNAL ;
    SHAPE ABUTMENT ;
    PORT
      LAYER met2 ;
      RECT 761.690 0.000 761.830 0.420 ;
    END
  END r0_rd_out[3]
  PIN r0_rd_out[4]
    DIRECTION OUTPUT ;
    USE SIGNAL ;
    SHAPE ABUTMENT ;
    PORT
      LAYER met2 ;
      RECT 763.990 0.000 764.130 0.420 ;
    END
  END r0_rd_out[4]
  PIN r0_rd_out[5]
    DIRECTION OUTPUT ;
    USE SIGNAL ;
    SHAPE ABUTMENT ;
    PORT
      LAYER met2 ;
      RECT 766.290 0.000 766.430 0.420 ;
    END
  END r0_rd_out[5]
  PIN r0_rd_out[6]
    DIRECTION OUTPUT ;
    USE SIGNAL ;
    SHAPE ABUTMENT ;
    PORT
      LAYER met2 ;
      RECT 768.590 0.000 768.730 0.420 ;
    END
  END r0_rd_out[6]
  PIN r0_rd_out[7]
    DIRECTION OUTPUT ;
    USE SIGNAL ;
    SHAPE ABUTMENT ;
    PORT
      LAYER met2 ;
      RECT 770.890 0.000 771.030 0.420 ;
    END
  END r0_rd_out[7]
  PIN r0_rd_out[8]
    DIRECTION OUTPUT ;
    USE SIGNAL ;
    SHAPE ABUTMENT ;
    PORT
      LAYER met2 ;
      RECT 773.190 0.000 773.330 0.420 ;
    END
  END r0_rd_out[8]
  PIN r0_rd_out[9]
    DIRECTION OUTPUT ;
    USE SIGNAL ;
    SHAPE ABUTMENT ;
    PORT
      LAYER met2 ;
      RECT 775.490 0.000 775.630 0.420 ;
    END
  END r0_rd_out[9]
  PIN r0_rd_out[10]
    DIRECTION OUTPUT ;
    USE SIGNAL ;
    SHAPE ABUTMENT ;
    PORT
      LAYER met2 ;
      RECT 777.790 0.000 777.930 0.420 ;
    END
  END r0_rd_out[10]
  PIN r0_rd_out[11]
    DIRECTION OUTPUT ;
    USE SIGNAL ;
    SHAPE ABUTMENT ;
    PORT
      LAYER met2 ;
      RECT 780.090 0.000 780.230 0.420 ;
    END
  END r0_rd_out[11]
  PIN r0_rd_out[12]
    DIRECTION OUTPUT ;
    USE SIGNAL ;
    SHAPE ABUTMENT ;
    PORT
      LAYER met2 ;
      RECT 782.390 0.000 782.530 0.420 ;
    END
  END r0_rd_out[12]
  PIN r0_rd_out[13]
    DIRECTION OUTPUT ;
    USE SIGNAL ;
    SHAPE ABUTMENT ;
    PORT
      LAYER met2 ;
      RECT 784.690 0.000 784.830 0.420 ;
    END
  END r0_rd_out[13]
  PIN r0_rd_out[14]
    DIRECTION OUTPUT ;
    USE SIGNAL ;
    SHAPE ABUTMENT ;
    PORT
      LAYER met2 ;
      RECT 786.990 0.000 787.130 0.420 ;
    END
  END r0_rd_out[14]
  PIN r0_rd_out[15]
    DIRECTION OUTPUT ;
    USE SIGNAL ;
    SHAPE ABUTMENT ;
    PORT
      LAYER met2 ;
      RECT 789.290 0.000 789.430 0.420 ;
    END
  END r0_rd_out[15]
  PIN r0_rd_out[16]
    DIRECTION OUTPUT ;
    USE SIGNAL ;
    SHAPE ABUTMENT ;
    PORT
      LAYER met2 ;
      RECT 791.590 0.000 791.730 0.420 ;
    END
  END r0_rd_out[16]
  PIN r0_rd_out[17]
    DIRECTION OUTPUT ;
    USE SIGNAL ;
    SHAPE ABUTMENT ;
    PORT
      LAYER met2 ;
      RECT 793.890 0.000 794.030 0.420 ;
    END
  END r0_rd_out[17]
  PIN r0_rd_out[18]
    DIRECTION OUTPUT ;
    USE SIGNAL ;
    SHAPE ABUTMENT ;
    PORT
      LAYER met2 ;
      RECT 796.190 0.000 796.330 0.420 ;
    END
  END r0_rd_out[18]
  PIN r0_rd_out[19]
    DIRECTION OUTPUT ;
    USE SIGNAL ;
    SHAPE ABUTMENT ;
    PORT
      LAYER met2 ;
      RECT 798.490 0.000 798.630 0.420 ;
    END
  END r0_rd_out[19]
  PIN r0_rd_out[20]
    DIRECTION OUTPUT ;
    USE SIGNAL ;
    SHAPE ABUTMENT ;
    PORT
      LAYER met2 ;
      RECT 800.790 0.000 800.930 0.420 ;
    END
  END r0_rd_out[20]
  PIN r0_rd_out[21]
    DIRECTION OUTPUT ;
    USE SIGNAL ;
    SHAPE ABUTMENT ;
    PORT
      LAYER met2 ;
      RECT 803.090 0.000 803.230 0.420 ;
    END
  END r0_rd_out[21]
  PIN r0_rd_out[22]
    DIRECTION OUTPUT ;
    USE SIGNAL ;
    SHAPE ABUTMENT ;
    PORT
      LAYER met2 ;
      RECT 805.390 0.000 805.530 0.420 ;
    END
  END r0_rd_out[22]
  PIN r0_rd_out[23]
    DIRECTION OUTPUT ;
    USE SIGNAL ;
    SHAPE ABUTMENT ;
    PORT
      LAYER met2 ;
      RECT 807.690 0.000 807.830 0.420 ;
    END
  END r0_rd_out[23]
  PIN r0_rd_out[24]
    DIRECTION OUTPUT ;
    USE SIGNAL ;
    SHAPE ABUTMENT ;
    PORT
      LAYER met2 ;
      RECT 809.990 0.000 810.130 0.420 ;
    END
  END r0_rd_out[24]
  PIN r0_rd_out[25]
    DIRECTION OUTPUT ;
    USE SIGNAL ;
    SHAPE ABUTMENT ;
    PORT
      LAYER met2 ;
      RECT 812.290 0.000 812.430 0.420 ;
    END
  END r0_rd_out[25]
  PIN r0_rd_out[26]
    DIRECTION OUTPUT ;
    USE SIGNAL ;
    SHAPE ABUTMENT ;
    PORT
      LAYER met2 ;
      RECT 814.590 0.000 814.730 0.420 ;
    END
  END r0_rd_out[26]
  PIN r0_rd_out[27]
    DIRECTION OUTPUT ;
    USE SIGNAL ;
    SHAPE ABUTMENT ;
    PORT
      LAYER met2 ;
      RECT 816.890 0.000 817.030 0.420 ;
    END
  END r0_rd_out[27]
  PIN r0_rd_out[28]
    DIRECTION OUTPUT ;
    USE SIGNAL ;
    SHAPE ABUTMENT ;
    PORT
      LAYER met2 ;
      RECT 819.190 0.000 819.330 0.420 ;
    END
  END r0_rd_out[28]
  PIN r0_rd_out[29]
    DIRECTION OUTPUT ;
    USE SIGNAL ;
    SHAPE ABUTMENT ;
    PORT
      LAYER met2 ;
      RECT 821.490 0.000 821.630 0.420 ;
    END
  END r0_rd_out[29]
  PIN r0_rd_out[30]
    DIRECTION OUTPUT ;
    USE SIGNAL ;
    SHAPE ABUTMENT ;
    PORT
      LAYER met2 ;
      RECT 823.790 0.000 823.930 0.420 ;
    END
  END r0_rd_out[30]
  PIN r0_rd_out[31]
    DIRECTION OUTPUT ;
    USE SIGNAL ;
    SHAPE ABUTMENT ;
    PORT
      LAYER met2 ;
      RECT 826.090 0.000 826.230 0.420 ;
    END
  END r0_rd_out[31]
  PIN r0_rd_out[32]
    DIRECTION OUTPUT ;
    USE SIGNAL ;
    SHAPE ABUTMENT ;
    PORT
      LAYER met2 ;
      RECT 828.390 0.000 828.530 0.420 ;
    END
  END r0_rd_out[32]
  PIN r0_rd_out[33]
    DIRECTION OUTPUT ;
    USE SIGNAL ;
    SHAPE ABUTMENT ;
    PORT
      LAYER met2 ;
      RECT 830.690 0.000 830.830 0.420 ;
    END
  END r0_rd_out[33]
  PIN r0_rd_out[34]
    DIRECTION OUTPUT ;
    USE SIGNAL ;
    SHAPE ABUTMENT ;
    PORT
      LAYER met2 ;
      RECT 832.990 0.000 833.130 0.420 ;
    END
  END r0_rd_out[34]
  PIN r0_rd_out[35]
    DIRECTION OUTPUT ;
    USE SIGNAL ;
    SHAPE ABUTMENT ;
    PORT
      LAYER met2 ;
      RECT 835.290 0.000 835.430 0.420 ;
    END
  END r0_rd_out[35]
  PIN r0_rd_out[36]
    DIRECTION OUTPUT ;
    USE SIGNAL ;
    SHAPE ABUTMENT ;
    PORT
      LAYER met2 ;
      RECT 837.590 0.000 837.730 0.420 ;
    END
  END r0_rd_out[36]
  PIN r0_rd_out[37]
    DIRECTION OUTPUT ;
    USE SIGNAL ;
    SHAPE ABUTMENT ;
    PORT
      LAYER met2 ;
      RECT 839.890 0.000 840.030 0.420 ;
    END
  END r0_rd_out[37]
  PIN r0_rd_out[38]
    DIRECTION OUTPUT ;
    USE SIGNAL ;
    SHAPE ABUTMENT ;
    PORT
      LAYER met2 ;
      RECT 842.190 0.000 842.330 0.420 ;
    END
  END r0_rd_out[38]
  PIN r0_rd_out[39]
    DIRECTION OUTPUT ;
    USE SIGNAL ;
    SHAPE ABUTMENT ;
    PORT
      LAYER met2 ;
      RECT 844.490 0.000 844.630 0.420 ;
    END
  END r0_rd_out[39]
  PIN r0_rd_out[40]
    DIRECTION OUTPUT ;
    USE SIGNAL ;
    SHAPE ABUTMENT ;
    PORT
      LAYER met2 ;
      RECT 846.790 0.000 846.930 0.420 ;
    END
  END r0_rd_out[40]
  PIN r0_rd_out[41]
    DIRECTION OUTPUT ;
    USE SIGNAL ;
    SHAPE ABUTMENT ;
    PORT
      LAYER met2 ;
      RECT 849.090 0.000 849.230 0.420 ;
    END
  END r0_rd_out[41]
  PIN r0_rd_out[42]
    DIRECTION OUTPUT ;
    USE SIGNAL ;
    SHAPE ABUTMENT ;
    PORT
      LAYER met2 ;
      RECT 851.390 0.000 851.530 0.420 ;
    END
  END r0_rd_out[42]
  PIN r0_rd_out[43]
    DIRECTION OUTPUT ;
    USE SIGNAL ;
    SHAPE ABUTMENT ;
    PORT
      LAYER met2 ;
      RECT 853.690 0.000 853.830 0.420 ;
    END
  END r0_rd_out[43]
  PIN r0_rd_out[44]
    DIRECTION OUTPUT ;
    USE SIGNAL ;
    SHAPE ABUTMENT ;
    PORT
      LAYER met2 ;
      RECT 855.990 0.000 856.130 0.420 ;
    END
  END r0_rd_out[44]
  PIN r0_rd_out[45]
    DIRECTION OUTPUT ;
    USE SIGNAL ;
    SHAPE ABUTMENT ;
    PORT
      LAYER met2 ;
      RECT 858.290 0.000 858.430 0.420 ;
    END
  END r0_rd_out[45]
  PIN r0_rd_out[46]
    DIRECTION OUTPUT ;
    USE SIGNAL ;
    SHAPE ABUTMENT ;
    PORT
      LAYER met2 ;
      RECT 860.590 0.000 860.730 0.420 ;
    END
  END r0_rd_out[46]
  PIN r0_rd_out[47]
    DIRECTION OUTPUT ;
    USE SIGNAL ;
    SHAPE ABUTMENT ;
    PORT
      LAYER met2 ;
      RECT 862.890 0.000 863.030 0.420 ;
    END
  END r0_rd_out[47]
  PIN r0_rd_out[48]
    DIRECTION OUTPUT ;
    USE SIGNAL ;
    SHAPE ABUTMENT ;
    PORT
      LAYER met2 ;
      RECT 865.190 0.000 865.330 0.420 ;
    END
  END r0_rd_out[48]
  PIN r0_rd_out[49]
    DIRECTION OUTPUT ;
    USE SIGNAL ;
    SHAPE ABUTMENT ;
    PORT
      LAYER met2 ;
      RECT 867.490 0.000 867.630 0.420 ;
    END
  END r0_rd_out[49]
  PIN r0_rd_out[50]
    DIRECTION OUTPUT ;
    USE SIGNAL ;
    SHAPE ABUTMENT ;
    PORT
      LAYER met2 ;
      RECT 869.790 0.000 869.930 0.420 ;
    END
  END r0_rd_out[50]
  PIN r0_rd_out[51]
    DIRECTION OUTPUT ;
    USE SIGNAL ;
    SHAPE ABUTMENT ;
    PORT
      LAYER met2 ;
      RECT 872.090 0.000 872.230 0.420 ;
    END
  END r0_rd_out[51]
  PIN r0_rd_out[52]
    DIRECTION OUTPUT ;
    USE SIGNAL ;
    SHAPE ABUTMENT ;
    PORT
      LAYER met2 ;
      RECT 874.390 0.000 874.530 0.420 ;
    END
  END r0_rd_out[52]
  PIN r0_rd_out[53]
    DIRECTION OUTPUT ;
    USE SIGNAL ;
    SHAPE ABUTMENT ;
    PORT
      LAYER met2 ;
      RECT 876.690 0.000 876.830 0.420 ;
    END
  END r0_rd_out[53]
  PIN r0_rd_out[54]
    DIRECTION OUTPUT ;
    USE SIGNAL ;
    SHAPE ABUTMENT ;
    PORT
      LAYER met2 ;
      RECT 878.990 0.000 879.130 0.420 ;
    END
  END r0_rd_out[54]
  PIN r0_rd_out[55]
    DIRECTION OUTPUT ;
    USE SIGNAL ;
    SHAPE ABUTMENT ;
    PORT
      LAYER met2 ;
      RECT 881.290 0.000 881.430 0.420 ;
    END
  END r0_rd_out[55]
  PIN r0_rd_out[56]
    DIRECTION OUTPUT ;
    USE SIGNAL ;
    SHAPE ABUTMENT ;
    PORT
      LAYER met2 ;
      RECT 883.590 0.000 883.730 0.420 ;
    END
  END r0_rd_out[56]
  PIN r0_rd_out[57]
    DIRECTION OUTPUT ;
    USE SIGNAL ;
    SHAPE ABUTMENT ;
    PORT
      LAYER met2 ;
      RECT 885.890 0.000 886.030 0.420 ;
    END
  END r0_rd_out[57]
  PIN r0_rd_out[58]
    DIRECTION OUTPUT ;
    USE SIGNAL ;
    SHAPE ABUTMENT ;
    PORT
      LAYER met2 ;
      RECT 888.190 0.000 888.330 0.420 ;
    END
  END r0_rd_out[58]
  PIN r0_rd_out[59]
    DIRECTION OUTPUT ;
    USE SIGNAL ;
    SHAPE ABUTMENT ;
    PORT
      LAYER met2 ;
      RECT 890.490 0.000 890.630 0.420 ;
    END
  END r0_rd_out[59]
  PIN r0_rd_out[60]
    DIRECTION OUTPUT ;
    USE SIGNAL ;
    SHAPE ABUTMENT ;
    PORT
      LAYER met2 ;
      RECT 892.790 0.000 892.930 0.420 ;
    END
  END r0_rd_out[60]
  PIN r0_rd_out[61]
    DIRECTION OUTPUT ;
    USE SIGNAL ;
    SHAPE ABUTMENT ;
    PORT
      LAYER met2 ;
      RECT 895.090 0.000 895.230 0.420 ;
    END
  END r0_rd_out[61]
  PIN r0_rd_out[62]
    DIRECTION OUTPUT ;
    USE SIGNAL ;
    SHAPE ABUTMENT ;
    PORT
      LAYER met2 ;
      RECT 897.390 0.000 897.530 0.420 ;
    END
  END r0_rd_out[62]
  PIN r0_rd_out[63]
    DIRECTION OUTPUT ;
    USE SIGNAL ;
    SHAPE ABUTMENT ;
    PORT
      LAYER met2 ;
      RECT 899.690 0.000 899.830 0.420 ;
    END
  END r0_rd_out[63]
  PIN r0_rd_out[64]
    DIRECTION OUTPUT ;
    USE SIGNAL ;
    SHAPE ABUTMENT ;
    PORT
      LAYER met2 ;
      RECT 901.990 0.000 902.130 0.420 ;
    END
  END r0_rd_out[64]
  PIN r0_rd_out[65]
    DIRECTION OUTPUT ;
    USE SIGNAL ;
    SHAPE ABUTMENT ;
    PORT
      LAYER met2 ;
      RECT 904.290 0.000 904.430 0.420 ;
    END
  END r0_rd_out[65]
  PIN r0_rd_out[66]
    DIRECTION OUTPUT ;
    USE SIGNAL ;
    SHAPE ABUTMENT ;
    PORT
      LAYER met2 ;
      RECT 906.590 0.000 906.730 0.420 ;
    END
  END r0_rd_out[66]
  PIN r0_rd_out[67]
    DIRECTION OUTPUT ;
    USE SIGNAL ;
    SHAPE ABUTMENT ;
    PORT
      LAYER met2 ;
      RECT 908.890 0.000 909.030 0.420 ;
    END
  END r0_rd_out[67]
  PIN r0_rd_out[68]
    DIRECTION OUTPUT ;
    USE SIGNAL ;
    SHAPE ABUTMENT ;
    PORT
      LAYER met2 ;
      RECT 911.190 0.000 911.330 0.420 ;
    END
  END r0_rd_out[68]
  PIN r0_rd_out[69]
    DIRECTION OUTPUT ;
    USE SIGNAL ;
    SHAPE ABUTMENT ;
    PORT
      LAYER met2 ;
      RECT 913.490 0.000 913.630 0.420 ;
    END
  END r0_rd_out[69]
  PIN r0_rd_out[70]
    DIRECTION OUTPUT ;
    USE SIGNAL ;
    SHAPE ABUTMENT ;
    PORT
      LAYER met2 ;
      RECT 915.790 0.000 915.930 0.420 ;
    END
  END r0_rd_out[70]
  PIN r0_rd_out[71]
    DIRECTION OUTPUT ;
    USE SIGNAL ;
    SHAPE ABUTMENT ;
    PORT
      LAYER met2 ;
      RECT 918.090 0.000 918.230 0.420 ;
    END
  END r0_rd_out[71]
  PIN r0_rd_out[72]
    DIRECTION OUTPUT ;
    USE SIGNAL ;
    SHAPE ABUTMENT ;
    PORT
      LAYER met2 ;
      RECT 920.390 0.000 920.530 0.420 ;
    END
  END r0_rd_out[72]
  PIN r0_rd_out[73]
    DIRECTION OUTPUT ;
    USE SIGNAL ;
    SHAPE ABUTMENT ;
    PORT
      LAYER met2 ;
      RECT 922.690 0.000 922.830 0.420 ;
    END
  END r0_rd_out[73]
  PIN r0_rd_out[74]
    DIRECTION OUTPUT ;
    USE SIGNAL ;
    SHAPE ABUTMENT ;
    PORT
      LAYER met2 ;
      RECT 924.990 0.000 925.130 0.420 ;
    END
  END r0_rd_out[74]
  PIN r0_rd_out[75]
    DIRECTION OUTPUT ;
    USE SIGNAL ;
    SHAPE ABUTMENT ;
    PORT
      LAYER met2 ;
      RECT 927.290 0.000 927.430 0.420 ;
    END
  END r0_rd_out[75]
  PIN r0_rd_out[76]
    DIRECTION OUTPUT ;
    USE SIGNAL ;
    SHAPE ABUTMENT ;
    PORT
      LAYER met2 ;
      RECT 929.590 0.000 929.730 0.420 ;
    END
  END r0_rd_out[76]
  PIN r0_rd_out[77]
    DIRECTION OUTPUT ;
    USE SIGNAL ;
    SHAPE ABUTMENT ;
    PORT
      LAYER met2 ;
      RECT 931.890 0.000 932.030 0.420 ;
    END
  END r0_rd_out[77]
  PIN r0_rd_out[78]
    DIRECTION OUTPUT ;
    USE SIGNAL ;
    SHAPE ABUTMENT ;
    PORT
      LAYER met2 ;
      RECT 934.190 0.000 934.330 0.420 ;
    END
  END r0_rd_out[78]
  PIN r0_rd_out[79]
    DIRECTION OUTPUT ;
    USE SIGNAL ;
    SHAPE ABUTMENT ;
    PORT
      LAYER met2 ;
      RECT 936.490 0.000 936.630 0.420 ;
    END
  END r0_rd_out[79]
  PIN r0_rd_out[80]
    DIRECTION OUTPUT ;
    USE SIGNAL ;
    SHAPE ABUTMENT ;
    PORT
      LAYER met2 ;
      RECT 938.790 0.000 938.930 0.420 ;
    END
  END r0_rd_out[80]
  PIN r0_rd_out[81]
    DIRECTION OUTPUT ;
    USE SIGNAL ;
    SHAPE ABUTMENT ;
    PORT
      LAYER met2 ;
      RECT 941.090 0.000 941.230 0.420 ;
    END
  END r0_rd_out[81]
  PIN r0_rd_out[82]
    DIRECTION OUTPUT ;
    USE SIGNAL ;
    SHAPE ABUTMENT ;
    PORT
      LAYER met2 ;
      RECT 943.390 0.000 943.530 0.420 ;
    END
  END r0_rd_out[82]
  PIN r0_rd_out[83]
    DIRECTION OUTPUT ;
    USE SIGNAL ;
    SHAPE ABUTMENT ;
    PORT
      LAYER met2 ;
      RECT 945.690 0.000 945.830 0.420 ;
    END
  END r0_rd_out[83]
  PIN r0_rd_out[84]
    DIRECTION OUTPUT ;
    USE SIGNAL ;
    SHAPE ABUTMENT ;
    PORT
      LAYER met2 ;
      RECT 947.990 0.000 948.130 0.420 ;
    END
  END r0_rd_out[84]
  PIN r0_rd_out[85]
    DIRECTION OUTPUT ;
    USE SIGNAL ;
    SHAPE ABUTMENT ;
    PORT
      LAYER met2 ;
      RECT 950.290 0.000 950.430 0.420 ;
    END
  END r0_rd_out[85]
  PIN r0_rd_out[86]
    DIRECTION OUTPUT ;
    USE SIGNAL ;
    SHAPE ABUTMENT ;
    PORT
      LAYER met2 ;
      RECT 952.590 0.000 952.730 0.420 ;
    END
  END r0_rd_out[86]
  PIN r0_rd_out[87]
    DIRECTION OUTPUT ;
    USE SIGNAL ;
    SHAPE ABUTMENT ;
    PORT
      LAYER met2 ;
      RECT 954.890 0.000 955.030 0.420 ;
    END
  END r0_rd_out[87]
  PIN r0_rd_out[88]
    DIRECTION OUTPUT ;
    USE SIGNAL ;
    SHAPE ABUTMENT ;
    PORT
      LAYER met2 ;
      RECT 957.190 0.000 957.330 0.420 ;
    END
  END r0_rd_out[88]
  PIN r0_rd_out[89]
    DIRECTION OUTPUT ;
    USE SIGNAL ;
    SHAPE ABUTMENT ;
    PORT
      LAYER met2 ;
      RECT 959.490 0.000 959.630 0.420 ;
    END
  END r0_rd_out[89]
  PIN r0_rd_out[90]
    DIRECTION OUTPUT ;
    USE SIGNAL ;
    SHAPE ABUTMENT ;
    PORT
      LAYER met2 ;
      RECT 961.790 0.000 961.930 0.420 ;
    END
  END r0_rd_out[90]
  PIN r0_rd_out[91]
    DIRECTION OUTPUT ;
    USE SIGNAL ;
    SHAPE ABUTMENT ;
    PORT
      LAYER met2 ;
      RECT 964.090 0.000 964.230 0.420 ;
    END
  END r0_rd_out[91]
  PIN r0_rd_out[92]
    DIRECTION OUTPUT ;
    USE SIGNAL ;
    SHAPE ABUTMENT ;
    PORT
      LAYER met2 ;
      RECT 966.390 0.000 966.530 0.420 ;
    END
  END r0_rd_out[92]
  PIN r0_rd_out[93]
    DIRECTION OUTPUT ;
    USE SIGNAL ;
    SHAPE ABUTMENT ;
    PORT
      LAYER met2 ;
      RECT 968.690 0.000 968.830 0.420 ;
    END
  END r0_rd_out[93]
  PIN r0_rd_out[94]
    DIRECTION OUTPUT ;
    USE SIGNAL ;
    SHAPE ABUTMENT ;
    PORT
      LAYER met2 ;
      RECT 970.990 0.000 971.130 0.420 ;
    END
  END r0_rd_out[94]
  PIN r0_rd_out[95]
    DIRECTION OUTPUT ;
    USE SIGNAL ;
    SHAPE ABUTMENT ;
    PORT
      LAYER met2 ;
      RECT 973.290 0.000 973.430 0.420 ;
    END
  END r0_rd_out[95]
  PIN r0_rd_out[96]
    DIRECTION OUTPUT ;
    USE SIGNAL ;
    SHAPE ABUTMENT ;
    PORT
      LAYER met2 ;
      RECT 975.590 0.000 975.730 0.420 ;
    END
  END r0_rd_out[96]
  PIN r0_rd_out[97]
    DIRECTION OUTPUT ;
    USE SIGNAL ;
    SHAPE ABUTMENT ;
    PORT
      LAYER met2 ;
      RECT 977.890 0.000 978.030 0.420 ;
    END
  END r0_rd_out[97]
  PIN r0_rd_out[98]
    DIRECTION OUTPUT ;
    USE SIGNAL ;
    SHAPE ABUTMENT ;
    PORT
      LAYER met2 ;
      RECT 980.190 0.000 980.330 0.420 ;
    END
  END r0_rd_out[98]
  PIN r0_rd_out[99]
    DIRECTION OUTPUT ;
    USE SIGNAL ;
    SHAPE ABUTMENT ;
    PORT
      LAYER met2 ;
      RECT 982.490 0.000 982.630 0.420 ;
    END
  END r0_rd_out[99]
  PIN r0_rd_out[100]
    DIRECTION OUTPUT ;
    USE SIGNAL ;
    SHAPE ABUTMENT ;
    PORT
      LAYER met2 ;
      RECT 984.790 0.000 984.930 0.420 ;
    END
  END r0_rd_out[100]
  PIN r0_rd_out[101]
    DIRECTION OUTPUT ;
    USE SIGNAL ;
    SHAPE ABUTMENT ;
    PORT
      LAYER met2 ;
      RECT 987.090 0.000 987.230 0.420 ;
    END
  END r0_rd_out[101]
  PIN r0_rd_out[102]
    DIRECTION OUTPUT ;
    USE SIGNAL ;
    SHAPE ABUTMENT ;
    PORT
      LAYER met2 ;
      RECT 989.390 0.000 989.530 0.420 ;
    END
  END r0_rd_out[102]
  PIN r0_rd_out[103]
    DIRECTION OUTPUT ;
    USE SIGNAL ;
    SHAPE ABUTMENT ;
    PORT
      LAYER met2 ;
      RECT 991.690 0.000 991.830 0.420 ;
    END
  END r0_rd_out[103]
  PIN r0_rd_out[104]
    DIRECTION OUTPUT ;
    USE SIGNAL ;
    SHAPE ABUTMENT ;
    PORT
      LAYER met2 ;
      RECT 993.990 0.000 994.130 0.420 ;
    END
  END r0_rd_out[104]
  PIN r0_rd_out[105]
    DIRECTION OUTPUT ;
    USE SIGNAL ;
    SHAPE ABUTMENT ;
    PORT
      LAYER met2 ;
      RECT 996.290 0.000 996.430 0.420 ;
    END
  END r0_rd_out[105]
  PIN r0_rd_out[106]
    DIRECTION OUTPUT ;
    USE SIGNAL ;
    SHAPE ABUTMENT ;
    PORT
      LAYER met2 ;
      RECT 998.590 0.000 998.730 0.420 ;
    END
  END r0_rd_out[106]
  PIN r0_rd_out[107]
    DIRECTION OUTPUT ;
    USE SIGNAL ;
    SHAPE ABUTMENT ;
    PORT
      LAYER met2 ;
      RECT 1000.890 0.000 1001.030 0.420 ;
    END
  END r0_rd_out[107]
  PIN r0_rd_out[108]
    DIRECTION OUTPUT ;
    USE SIGNAL ;
    SHAPE ABUTMENT ;
    PORT
      LAYER met2 ;
      RECT 1003.190 0.000 1003.330 0.420 ;
    END
  END r0_rd_out[108]
  PIN r0_rd_out[109]
    DIRECTION OUTPUT ;
    USE SIGNAL ;
    SHAPE ABUTMENT ;
    PORT
      LAYER met2 ;
      RECT 1005.490 0.000 1005.630 0.420 ;
    END
  END r0_rd_out[109]
  PIN r0_rd_out[110]
    DIRECTION OUTPUT ;
    USE SIGNAL ;
    SHAPE ABUTMENT ;
    PORT
      LAYER met2 ;
      RECT 1007.790 0.000 1007.930 0.420 ;
    END
  END r0_rd_out[110]
  PIN r0_rd_out[111]
    DIRECTION OUTPUT ;
    USE SIGNAL ;
    SHAPE ABUTMENT ;
    PORT
      LAYER met2 ;
      RECT 1010.090 0.000 1010.230 0.420 ;
    END
  END r0_rd_out[111]
  PIN r0_rd_out[112]
    DIRECTION OUTPUT ;
    USE SIGNAL ;
    SHAPE ABUTMENT ;
    PORT
      LAYER met2 ;
      RECT 1012.390 0.000 1012.530 0.420 ;
    END
  END r0_rd_out[112]
  PIN r0_rd_out[113]
    DIRECTION OUTPUT ;
    USE SIGNAL ;
    SHAPE ABUTMENT ;
    PORT
      LAYER met2 ;
      RECT 1014.690 0.000 1014.830 0.420 ;
    END
  END r0_rd_out[113]
  PIN r0_rd_out[114]
    DIRECTION OUTPUT ;
    USE SIGNAL ;
    SHAPE ABUTMENT ;
    PORT
      LAYER met2 ;
      RECT 1016.990 0.000 1017.130 0.420 ;
    END
  END r0_rd_out[114]
  PIN r0_rd_out[115]
    DIRECTION OUTPUT ;
    USE SIGNAL ;
    SHAPE ABUTMENT ;
    PORT
      LAYER met2 ;
      RECT 1019.290 0.000 1019.430 0.420 ;
    END
  END r0_rd_out[115]
  PIN r0_rd_out[116]
    DIRECTION OUTPUT ;
    USE SIGNAL ;
    SHAPE ABUTMENT ;
    PORT
      LAYER met2 ;
      RECT 1021.590 0.000 1021.730 0.420 ;
    END
  END r0_rd_out[116]
  PIN r0_rd_out[117]
    DIRECTION OUTPUT ;
    USE SIGNAL ;
    SHAPE ABUTMENT ;
    PORT
      LAYER met2 ;
      RECT 1023.890 0.000 1024.030 0.420 ;
    END
  END r0_rd_out[117]
  PIN r0_rd_out[118]
    DIRECTION OUTPUT ;
    USE SIGNAL ;
    SHAPE ABUTMENT ;
    PORT
      LAYER met2 ;
      RECT 1026.190 0.000 1026.330 0.420 ;
    END
  END r0_rd_out[118]
  PIN r0_rd_out[119]
    DIRECTION OUTPUT ;
    USE SIGNAL ;
    SHAPE ABUTMENT ;
    PORT
      LAYER met2 ;
      RECT 1028.490 0.000 1028.630 0.420 ;
    END
  END r0_rd_out[119]
  PIN r0_rd_out[120]
    DIRECTION OUTPUT ;
    USE SIGNAL ;
    SHAPE ABUTMENT ;
    PORT
      LAYER met2 ;
      RECT 1030.790 0.000 1030.930 0.420 ;
    END
  END r0_rd_out[120]
  PIN r0_rd_out[121]
    DIRECTION OUTPUT ;
    USE SIGNAL ;
    SHAPE ABUTMENT ;
    PORT
      LAYER met2 ;
      RECT 1033.090 0.000 1033.230 0.420 ;
    END
  END r0_rd_out[121]
  PIN r0_rd_out[122]
    DIRECTION OUTPUT ;
    USE SIGNAL ;
    SHAPE ABUTMENT ;
    PORT
      LAYER met2 ;
      RECT 1035.390 0.000 1035.530 0.420 ;
    END
  END r0_rd_out[122]
  PIN r0_rd_out[123]
    DIRECTION OUTPUT ;
    USE SIGNAL ;
    SHAPE ABUTMENT ;
    PORT
      LAYER met2 ;
      RECT 1037.690 0.000 1037.830 0.420 ;
    END
  END r0_rd_out[123]
  PIN r0_rd_out[124]
    DIRECTION OUTPUT ;
    USE SIGNAL ;
    SHAPE ABUTMENT ;
    PORT
      LAYER met2 ;
      RECT 1039.990 0.000 1040.130 0.420 ;
    END
  END r0_rd_out[124]
  PIN r0_rd_out[125]
    DIRECTION OUTPUT ;
    USE SIGNAL ;
    SHAPE ABUTMENT ;
    PORT
      LAYER met2 ;
      RECT 1042.290 0.000 1042.430 0.420 ;
    END
  END r0_rd_out[125]
  PIN r0_rd_out[126]
    DIRECTION OUTPUT ;
    USE SIGNAL ;
    SHAPE ABUTMENT ;
    PORT
      LAYER met2 ;
      RECT 1044.590 0.000 1044.730 0.420 ;
    END
  END r0_rd_out[126]
  PIN r0_rd_out[127]
    DIRECTION OUTPUT ;
    USE SIGNAL ;
    SHAPE ABUTMENT ;
    PORT
      LAYER met2 ;
      RECT 1046.890 0.000 1047.030 0.420 ;
    END
  END r0_rd_out[127]
  PIN r0_rd_out[128]
    DIRECTION OUTPUT ;
    USE SIGNAL ;
    SHAPE ABUTMENT ;
    PORT
      LAYER met2 ;
      RECT 1049.190 0.000 1049.330 0.420 ;
    END
  END r0_rd_out[128]
  PIN r0_rd_out[129]
    DIRECTION OUTPUT ;
    USE SIGNAL ;
    SHAPE ABUTMENT ;
    PORT
      LAYER met2 ;
      RECT 1051.490 0.000 1051.630 0.420 ;
    END
  END r0_rd_out[129]
  PIN r0_rd_out[130]
    DIRECTION OUTPUT ;
    USE SIGNAL ;
    SHAPE ABUTMENT ;
    PORT
      LAYER met2 ;
      RECT 1053.790 0.000 1053.930 0.420 ;
    END
  END r0_rd_out[130]
  PIN r0_rd_out[131]
    DIRECTION OUTPUT ;
    USE SIGNAL ;
    SHAPE ABUTMENT ;
    PORT
      LAYER met2 ;
      RECT 1056.090 0.000 1056.230 0.420 ;
    END
  END r0_rd_out[131]
  PIN r0_rd_out[132]
    DIRECTION OUTPUT ;
    USE SIGNAL ;
    SHAPE ABUTMENT ;
    PORT
      LAYER met2 ;
      RECT 1058.390 0.000 1058.530 0.420 ;
    END
  END r0_rd_out[132]
  PIN r0_rd_out[133]
    DIRECTION OUTPUT ;
    USE SIGNAL ;
    SHAPE ABUTMENT ;
    PORT
      LAYER met2 ;
      RECT 1060.690 0.000 1060.830 0.420 ;
    END
  END r0_rd_out[133]
  PIN r0_rd_out[134]
    DIRECTION OUTPUT ;
    USE SIGNAL ;
    SHAPE ABUTMENT ;
    PORT
      LAYER met2 ;
      RECT 1062.990 0.000 1063.130 0.420 ;
    END
  END r0_rd_out[134]
  PIN r0_rd_out[135]
    DIRECTION OUTPUT ;
    USE SIGNAL ;
    SHAPE ABUTMENT ;
    PORT
      LAYER met2 ;
      RECT 1065.290 0.000 1065.430 0.420 ;
    END
  END r0_rd_out[135]
  PIN r0_rd_out[136]
    DIRECTION OUTPUT ;
    USE SIGNAL ;
    SHAPE ABUTMENT ;
    PORT
      LAYER met2 ;
      RECT 1067.590 0.000 1067.730 0.420 ;
    END
  END r0_rd_out[136]
  PIN r0_rd_out[137]
    DIRECTION OUTPUT ;
    USE SIGNAL ;
    SHAPE ABUTMENT ;
    PORT
      LAYER met2 ;
      RECT 1069.890 0.000 1070.030 0.420 ;
    END
  END r0_rd_out[137]
  PIN r0_rd_out[138]
    DIRECTION OUTPUT ;
    USE SIGNAL ;
    SHAPE ABUTMENT ;
    PORT
      LAYER met2 ;
      RECT 1072.190 0.000 1072.330 0.420 ;
    END
  END r0_rd_out[138]
  PIN r0_rd_out[139]
    DIRECTION OUTPUT ;
    USE SIGNAL ;
    SHAPE ABUTMENT ;
    PORT
      LAYER met2 ;
      RECT 1074.490 0.000 1074.630 0.420 ;
    END
  END r0_rd_out[139]
  PIN r0_rd_out[140]
    DIRECTION OUTPUT ;
    USE SIGNAL ;
    SHAPE ABUTMENT ;
    PORT
      LAYER met2 ;
      RECT 1076.790 0.000 1076.930 0.420 ;
    END
  END r0_rd_out[140]
  PIN r0_rd_out[141]
    DIRECTION OUTPUT ;
    USE SIGNAL ;
    SHAPE ABUTMENT ;
    PORT
      LAYER met2 ;
      RECT 1079.090 0.000 1079.230 0.420 ;
    END
  END r0_rd_out[141]
  PIN r0_rd_out[142]
    DIRECTION OUTPUT ;
    USE SIGNAL ;
    SHAPE ABUTMENT ;
    PORT
      LAYER met2 ;
      RECT 1081.390 0.000 1081.530 0.420 ;
    END
  END r0_rd_out[142]
  PIN r0_rd_out[143]
    DIRECTION OUTPUT ;
    USE SIGNAL ;
    SHAPE ABUTMENT ;
    PORT
      LAYER met2 ;
      RECT 1083.690 0.000 1083.830 0.420 ;
    END
  END r0_rd_out[143]
  PIN r0_rd_out[144]
    DIRECTION OUTPUT ;
    USE SIGNAL ;
    SHAPE ABUTMENT ;
    PORT
      LAYER met2 ;
      RECT 1085.990 0.000 1086.130 0.420 ;
    END
  END r0_rd_out[144]
  PIN r0_rd_out[145]
    DIRECTION OUTPUT ;
    USE SIGNAL ;
    SHAPE ABUTMENT ;
    PORT
      LAYER met2 ;
      RECT 1088.290 0.000 1088.430 0.420 ;
    END
  END r0_rd_out[145]
  PIN r0_rd_out[146]
    DIRECTION OUTPUT ;
    USE SIGNAL ;
    SHAPE ABUTMENT ;
    PORT
      LAYER met2 ;
      RECT 1090.590 0.000 1090.730 0.420 ;
    END
  END r0_rd_out[146]
  PIN r0_rd_out[147]
    DIRECTION OUTPUT ;
    USE SIGNAL ;
    SHAPE ABUTMENT ;
    PORT
      LAYER met2 ;
      RECT 1092.890 0.000 1093.030 0.420 ;
    END
  END r0_rd_out[147]
  PIN r0_rd_out[148]
    DIRECTION OUTPUT ;
    USE SIGNAL ;
    SHAPE ABUTMENT ;
    PORT
      LAYER met2 ;
      RECT 1095.190 0.000 1095.330 0.420 ;
    END
  END r0_rd_out[148]
  PIN r0_rd_out[149]
    DIRECTION OUTPUT ;
    USE SIGNAL ;
    SHAPE ABUTMENT ;
    PORT
      LAYER met2 ;
      RECT 1097.490 0.000 1097.630 0.420 ;
    END
  END r0_rd_out[149]
  PIN r0_rd_out[150]
    DIRECTION OUTPUT ;
    USE SIGNAL ;
    SHAPE ABUTMENT ;
    PORT
      LAYER met2 ;
      RECT 1099.790 0.000 1099.930 0.420 ;
    END
  END r0_rd_out[150]
  PIN r0_rd_out[151]
    DIRECTION OUTPUT ;
    USE SIGNAL ;
    SHAPE ABUTMENT ;
    PORT
      LAYER met2 ;
      RECT 1102.090 0.000 1102.230 0.420 ;
    END
  END r0_rd_out[151]
  PIN r0_rd_out[152]
    DIRECTION OUTPUT ;
    USE SIGNAL ;
    SHAPE ABUTMENT ;
    PORT
      LAYER met2 ;
      RECT 1104.390 0.000 1104.530 0.420 ;
    END
  END r0_rd_out[152]
  PIN r0_rd_out[153]
    DIRECTION OUTPUT ;
    USE SIGNAL ;
    SHAPE ABUTMENT ;
    PORT
      LAYER met2 ;
      RECT 1106.690 0.000 1106.830 0.420 ;
    END
  END r0_rd_out[153]
  PIN r0_rd_out[154]
    DIRECTION OUTPUT ;
    USE SIGNAL ;
    SHAPE ABUTMENT ;
    PORT
      LAYER met2 ;
      RECT 1108.990 0.000 1109.130 0.420 ;
    END
  END r0_rd_out[154]
  PIN r0_rd_out[155]
    DIRECTION OUTPUT ;
    USE SIGNAL ;
    SHAPE ABUTMENT ;
    PORT
      LAYER met2 ;
      RECT 1111.290 0.000 1111.430 0.420 ;
    END
  END r0_rd_out[155]
  PIN r0_rd_out[156]
    DIRECTION OUTPUT ;
    USE SIGNAL ;
    SHAPE ABUTMENT ;
    PORT
      LAYER met2 ;
      RECT 1113.590 0.000 1113.730 0.420 ;
    END
  END r0_rd_out[156]
  PIN r0_rd_out[157]
    DIRECTION OUTPUT ;
    USE SIGNAL ;
    SHAPE ABUTMENT ;
    PORT
      LAYER met2 ;
      RECT 1115.890 0.000 1116.030 0.420 ;
    END
  END r0_rd_out[157]
  PIN r0_rd_out[158]
    DIRECTION OUTPUT ;
    USE SIGNAL ;
    SHAPE ABUTMENT ;
    PORT
      LAYER met2 ;
      RECT 1118.190 0.000 1118.330 0.420 ;
    END
  END r0_rd_out[158]
  PIN r0_rd_out[159]
    DIRECTION OUTPUT ;
    USE SIGNAL ;
    SHAPE ABUTMENT ;
    PORT
      LAYER met2 ;
      RECT 1120.490 0.000 1120.630 0.420 ;
    END
  END r0_rd_out[159]
  PIN r0_rd_out[160]
    DIRECTION OUTPUT ;
    USE SIGNAL ;
    SHAPE ABUTMENT ;
    PORT
      LAYER met2 ;
      RECT 1122.790 0.000 1122.930 0.420 ;
    END
  END r0_rd_out[160]
  PIN r0_rd_out[161]
    DIRECTION OUTPUT ;
    USE SIGNAL ;
    SHAPE ABUTMENT ;
    PORT
      LAYER met2 ;
      RECT 1125.090 0.000 1125.230 0.420 ;
    END
  END r0_rd_out[161]
  PIN r0_rd_out[162]
    DIRECTION OUTPUT ;
    USE SIGNAL ;
    SHAPE ABUTMENT ;
    PORT
      LAYER met2 ;
      RECT 1127.390 0.000 1127.530 0.420 ;
    END
  END r0_rd_out[162]
  PIN r0_rd_out[163]
    DIRECTION OUTPUT ;
    USE SIGNAL ;
    SHAPE ABUTMENT ;
    PORT
      LAYER met2 ;
      RECT 1129.690 0.000 1129.830 0.420 ;
    END
  END r0_rd_out[163]
  PIN r0_rd_out[164]
    DIRECTION OUTPUT ;
    USE SIGNAL ;
    SHAPE ABUTMENT ;
    PORT
      LAYER met2 ;
      RECT 1131.990 0.000 1132.130 0.420 ;
    END
  END r0_rd_out[164]
  PIN r0_rd_out[165]
    DIRECTION OUTPUT ;
    USE SIGNAL ;
    SHAPE ABUTMENT ;
    PORT
      LAYER met2 ;
      RECT 1134.290 0.000 1134.430 0.420 ;
    END
  END r0_rd_out[165]
  PIN r0_rd_out[166]
    DIRECTION OUTPUT ;
    USE SIGNAL ;
    SHAPE ABUTMENT ;
    PORT
      LAYER met2 ;
      RECT 1136.590 0.000 1136.730 0.420 ;
    END
  END r0_rd_out[166]
  PIN r0_rd_out[167]
    DIRECTION OUTPUT ;
    USE SIGNAL ;
    SHAPE ABUTMENT ;
    PORT
      LAYER met2 ;
      RECT 1138.890 0.000 1139.030 0.420 ;
    END
  END r0_rd_out[167]
  PIN r0_rd_out[168]
    DIRECTION OUTPUT ;
    USE SIGNAL ;
    SHAPE ABUTMENT ;
    PORT
      LAYER met2 ;
      RECT 1141.190 0.000 1141.330 0.420 ;
    END
  END r0_rd_out[168]
  PIN r0_rd_out[169]
    DIRECTION OUTPUT ;
    USE SIGNAL ;
    SHAPE ABUTMENT ;
    PORT
      LAYER met2 ;
      RECT 1143.490 0.000 1143.630 0.420 ;
    END
  END r0_rd_out[169]
  PIN r0_rd_out[170]
    DIRECTION OUTPUT ;
    USE SIGNAL ;
    SHAPE ABUTMENT ;
    PORT
      LAYER met2 ;
      RECT 1145.790 0.000 1145.930 0.420 ;
    END
  END r0_rd_out[170]
  PIN r0_rd_out[171]
    DIRECTION OUTPUT ;
    USE SIGNAL ;
    SHAPE ABUTMENT ;
    PORT
      LAYER met2 ;
      RECT 1148.090 0.000 1148.230 0.420 ;
    END
  END r0_rd_out[171]
  PIN r0_rd_out[172]
    DIRECTION OUTPUT ;
    USE SIGNAL ;
    SHAPE ABUTMENT ;
    PORT
      LAYER met2 ;
      RECT 1150.390 0.000 1150.530 0.420 ;
    END
  END r0_rd_out[172]
  PIN r0_rd_out[173]
    DIRECTION OUTPUT ;
    USE SIGNAL ;
    SHAPE ABUTMENT ;
    PORT
      LAYER met2 ;
      RECT 1152.690 0.000 1152.830 0.420 ;
    END
  END r0_rd_out[173]
  PIN r0_rd_out[174]
    DIRECTION OUTPUT ;
    USE SIGNAL ;
    SHAPE ABUTMENT ;
    PORT
      LAYER met2 ;
      RECT 1154.990 0.000 1155.130 0.420 ;
    END
  END r0_rd_out[174]
  PIN r0_rd_out[175]
    DIRECTION OUTPUT ;
    USE SIGNAL ;
    SHAPE ABUTMENT ;
    PORT
      LAYER met2 ;
      RECT 1157.290 0.000 1157.430 0.420 ;
    END
  END r0_rd_out[175]
  PIN r0_rd_out[176]
    DIRECTION OUTPUT ;
    USE SIGNAL ;
    SHAPE ABUTMENT ;
    PORT
      LAYER met2 ;
      RECT 1159.590 0.000 1159.730 0.420 ;
    END
  END r0_rd_out[176]
  PIN r0_rd_out[177]
    DIRECTION OUTPUT ;
    USE SIGNAL ;
    SHAPE ABUTMENT ;
    PORT
      LAYER met2 ;
      RECT 1161.890 0.000 1162.030 0.420 ;
    END
  END r0_rd_out[177]
  PIN r0_rd_out[178]
    DIRECTION OUTPUT ;
    USE SIGNAL ;
    SHAPE ABUTMENT ;
    PORT
      LAYER met2 ;
      RECT 1164.190 0.000 1164.330 0.420 ;
    END
  END r0_rd_out[178]
  PIN r0_rd_out[179]
    DIRECTION OUTPUT ;
    USE SIGNAL ;
    SHAPE ABUTMENT ;
    PORT
      LAYER met2 ;
      RECT 1166.490 0.000 1166.630 0.420 ;
    END
  END r0_rd_out[179]
  PIN r0_rd_out[180]
    DIRECTION OUTPUT ;
    USE SIGNAL ;
    SHAPE ABUTMENT ;
    PORT
      LAYER met2 ;
      RECT 1168.790 0.000 1168.930 0.420 ;
    END
  END r0_rd_out[180]
  PIN r0_rd_out[181]
    DIRECTION OUTPUT ;
    USE SIGNAL ;
    SHAPE ABUTMENT ;
    PORT
      LAYER met2 ;
      RECT 1171.090 0.000 1171.230 0.420 ;
    END
  END r0_rd_out[181]
  PIN r0_rd_out[182]
    DIRECTION OUTPUT ;
    USE SIGNAL ;
    SHAPE ABUTMENT ;
    PORT
      LAYER met2 ;
      RECT 1173.390 0.000 1173.530 0.420 ;
    END
  END r0_rd_out[182]
  PIN r0_rd_out[183]
    DIRECTION OUTPUT ;
    USE SIGNAL ;
    SHAPE ABUTMENT ;
    PORT
      LAYER met2 ;
      RECT 1175.690 0.000 1175.830 0.420 ;
    END
  END r0_rd_out[183]
  PIN r0_rd_out[184]
    DIRECTION OUTPUT ;
    USE SIGNAL ;
    SHAPE ABUTMENT ;
    PORT
      LAYER met2 ;
      RECT 1177.990 0.000 1178.130 0.420 ;
    END
  END r0_rd_out[184]
  PIN r0_rd_out[185]
    DIRECTION OUTPUT ;
    USE SIGNAL ;
    SHAPE ABUTMENT ;
    PORT
      LAYER met2 ;
      RECT 1180.290 0.000 1180.430 0.420 ;
    END
  END r0_rd_out[185]
  PIN r0_rd_out[186]
    DIRECTION OUTPUT ;
    USE SIGNAL ;
    SHAPE ABUTMENT ;
    PORT
      LAYER met2 ;
      RECT 1182.590 0.000 1182.730 0.420 ;
    END
  END r0_rd_out[186]
  PIN r0_rd_out[187]
    DIRECTION OUTPUT ;
    USE SIGNAL ;
    SHAPE ABUTMENT ;
    PORT
      LAYER met2 ;
      RECT 1184.890 0.000 1185.030 0.420 ;
    END
  END r0_rd_out[187]
  PIN r0_rd_out[188]
    DIRECTION OUTPUT ;
    USE SIGNAL ;
    SHAPE ABUTMENT ;
    PORT
      LAYER met2 ;
      RECT 1187.190 0.000 1187.330 0.420 ;
    END
  END r0_rd_out[188]
  PIN r0_rd_out[189]
    DIRECTION OUTPUT ;
    USE SIGNAL ;
    SHAPE ABUTMENT ;
    PORT
      LAYER met2 ;
      RECT 1189.490 0.000 1189.630 0.420 ;
    END
  END r0_rd_out[189]
  PIN r0_rd_out[190]
    DIRECTION OUTPUT ;
    USE SIGNAL ;
    SHAPE ABUTMENT ;
    PORT
      LAYER met2 ;
      RECT 1191.790 0.000 1191.930 0.420 ;
    END
  END r0_rd_out[190]
  PIN r0_rd_out[191]
    DIRECTION OUTPUT ;
    USE SIGNAL ;
    SHAPE ABUTMENT ;
    PORT
      LAYER met2 ;
      RECT 1194.090 0.000 1194.230 0.420 ;
    END
  END r0_rd_out[191]
  PIN r0_rd_out[192]
    DIRECTION OUTPUT ;
    USE SIGNAL ;
    SHAPE ABUTMENT ;
    PORT
      LAYER met2 ;
      RECT 1196.390 0.000 1196.530 0.420 ;
    END
  END r0_rd_out[192]
  PIN r0_rd_out[193]
    DIRECTION OUTPUT ;
    USE SIGNAL ;
    SHAPE ABUTMENT ;
    PORT
      LAYER met2 ;
      RECT 1198.690 0.000 1198.830 0.420 ;
    END
  END r0_rd_out[193]
  PIN r0_rd_out[194]
    DIRECTION OUTPUT ;
    USE SIGNAL ;
    SHAPE ABUTMENT ;
    PORT
      LAYER met2 ;
      RECT 1200.990 0.000 1201.130 0.420 ;
    END
  END r0_rd_out[194]
  PIN r0_rd_out[195]
    DIRECTION OUTPUT ;
    USE SIGNAL ;
    SHAPE ABUTMENT ;
    PORT
      LAYER met2 ;
      RECT 1203.290 0.000 1203.430 0.420 ;
    END
  END r0_rd_out[195]
  PIN r0_rd_out[196]
    DIRECTION OUTPUT ;
    USE SIGNAL ;
    SHAPE ABUTMENT ;
    PORT
      LAYER met2 ;
      RECT 1205.590 0.000 1205.730 0.420 ;
    END
  END r0_rd_out[196]
  PIN r0_rd_out[197]
    DIRECTION OUTPUT ;
    USE SIGNAL ;
    SHAPE ABUTMENT ;
    PORT
      LAYER met2 ;
      RECT 1207.890 0.000 1208.030 0.420 ;
    END
  END r0_rd_out[197]
  PIN r0_rd_out[198]
    DIRECTION OUTPUT ;
    USE SIGNAL ;
    SHAPE ABUTMENT ;
    PORT
      LAYER met2 ;
      RECT 1210.190 0.000 1210.330 0.420 ;
    END
  END r0_rd_out[198]
  PIN r0_rd_out[199]
    DIRECTION OUTPUT ;
    USE SIGNAL ;
    SHAPE ABUTMENT ;
    PORT
      LAYER met2 ;
      RECT 1212.490 0.000 1212.630 0.420 ;
    END
  END r0_rd_out[199]
  PIN r0_rd_out[200]
    DIRECTION OUTPUT ;
    USE SIGNAL ;
    SHAPE ABUTMENT ;
    PORT
      LAYER met2 ;
      RECT 1214.790 0.000 1214.930 0.420 ;
    END
  END r0_rd_out[200]
  PIN r0_rd_out[201]
    DIRECTION OUTPUT ;
    USE SIGNAL ;
    SHAPE ABUTMENT ;
    PORT
      LAYER met2 ;
      RECT 1217.090 0.000 1217.230 0.420 ;
    END
  END r0_rd_out[201]
  PIN r0_rd_out[202]
    DIRECTION OUTPUT ;
    USE SIGNAL ;
    SHAPE ABUTMENT ;
    PORT
      LAYER met2 ;
      RECT 1219.390 0.000 1219.530 0.420 ;
    END
  END r0_rd_out[202]
  PIN r0_rd_out[203]
    DIRECTION OUTPUT ;
    USE SIGNAL ;
    SHAPE ABUTMENT ;
    PORT
      LAYER met2 ;
      RECT 1221.690 0.000 1221.830 0.420 ;
    END
  END r0_rd_out[203]
  PIN r0_rd_out[204]
    DIRECTION OUTPUT ;
    USE SIGNAL ;
    SHAPE ABUTMENT ;
    PORT
      LAYER met2 ;
      RECT 1223.990 0.000 1224.130 0.420 ;
    END
  END r0_rd_out[204]
  PIN r0_rd_out[205]
    DIRECTION OUTPUT ;
    USE SIGNAL ;
    SHAPE ABUTMENT ;
    PORT
      LAYER met2 ;
      RECT 1226.290 0.000 1226.430 0.420 ;
    END
  END r0_rd_out[205]
  PIN r0_rd_out[206]
    DIRECTION OUTPUT ;
    USE SIGNAL ;
    SHAPE ABUTMENT ;
    PORT
      LAYER met2 ;
      RECT 1228.590 0.000 1228.730 0.420 ;
    END
  END r0_rd_out[206]
  PIN r0_rd_out[207]
    DIRECTION OUTPUT ;
    USE SIGNAL ;
    SHAPE ABUTMENT ;
    PORT
      LAYER met2 ;
      RECT 1230.890 0.000 1231.030 0.420 ;
    END
  END r0_rd_out[207]
  PIN r0_rd_out[208]
    DIRECTION OUTPUT ;
    USE SIGNAL ;
    SHAPE ABUTMENT ;
    PORT
      LAYER met2 ;
      RECT 1233.190 0.000 1233.330 0.420 ;
    END
  END r0_rd_out[208]
  PIN r0_rd_out[209]
    DIRECTION OUTPUT ;
    USE SIGNAL ;
    SHAPE ABUTMENT ;
    PORT
      LAYER met2 ;
      RECT 1235.490 0.000 1235.630 0.420 ;
    END
  END r0_rd_out[209]
  PIN r0_rd_out[210]
    DIRECTION OUTPUT ;
    USE SIGNAL ;
    SHAPE ABUTMENT ;
    PORT
      LAYER met2 ;
      RECT 1237.790 0.000 1237.930 0.420 ;
    END
  END r0_rd_out[210]
  PIN r0_rd_out[211]
    DIRECTION OUTPUT ;
    USE SIGNAL ;
    SHAPE ABUTMENT ;
    PORT
      LAYER met2 ;
      RECT 1240.090 0.000 1240.230 0.420 ;
    END
  END r0_rd_out[211]
  PIN r0_rd_out[212]
    DIRECTION OUTPUT ;
    USE SIGNAL ;
    SHAPE ABUTMENT ;
    PORT
      LAYER met2 ;
      RECT 1242.390 0.000 1242.530 0.420 ;
    END
  END r0_rd_out[212]
  PIN r0_rd_out[213]
    DIRECTION OUTPUT ;
    USE SIGNAL ;
    SHAPE ABUTMENT ;
    PORT
      LAYER met2 ;
      RECT 1244.690 0.000 1244.830 0.420 ;
    END
  END r0_rd_out[213]
  PIN r0_rd_out[214]
    DIRECTION OUTPUT ;
    USE SIGNAL ;
    SHAPE ABUTMENT ;
    PORT
      LAYER met2 ;
      RECT 1246.990 0.000 1247.130 0.420 ;
    END
  END r0_rd_out[214]
  PIN r0_rd_out[215]
    DIRECTION OUTPUT ;
    USE SIGNAL ;
    SHAPE ABUTMENT ;
    PORT
      LAYER met2 ;
      RECT 1249.290 0.000 1249.430 0.420 ;
    END
  END r0_rd_out[215]
  PIN r0_rd_out[216]
    DIRECTION OUTPUT ;
    USE SIGNAL ;
    SHAPE ABUTMENT ;
    PORT
      LAYER met2 ;
      RECT 1251.590 0.000 1251.730 0.420 ;
    END
  END r0_rd_out[216]
  PIN r0_rd_out[217]
    DIRECTION OUTPUT ;
    USE SIGNAL ;
    SHAPE ABUTMENT ;
    PORT
      LAYER met2 ;
      RECT 1253.890 0.000 1254.030 0.420 ;
    END
  END r0_rd_out[217]
  PIN r0_rd_out[218]
    DIRECTION OUTPUT ;
    USE SIGNAL ;
    SHAPE ABUTMENT ;
    PORT
      LAYER met2 ;
      RECT 1256.190 0.000 1256.330 0.420 ;
    END
  END r0_rd_out[218]
  PIN r0_rd_out[219]
    DIRECTION OUTPUT ;
    USE SIGNAL ;
    SHAPE ABUTMENT ;
    PORT
      LAYER met2 ;
      RECT 1258.490 0.000 1258.630 0.420 ;
    END
  END r0_rd_out[219]
  PIN r0_rd_out[220]
    DIRECTION OUTPUT ;
    USE SIGNAL ;
    SHAPE ABUTMENT ;
    PORT
      LAYER met2 ;
      RECT 1260.790 0.000 1260.930 0.420 ;
    END
  END r0_rd_out[220]
  PIN r0_rd_out[221]
    DIRECTION OUTPUT ;
    USE SIGNAL ;
    SHAPE ABUTMENT ;
    PORT
      LAYER met2 ;
      RECT 1263.090 0.000 1263.230 0.420 ;
    END
  END r0_rd_out[221]
  PIN r0_rd_out[222]
    DIRECTION OUTPUT ;
    USE SIGNAL ;
    SHAPE ABUTMENT ;
    PORT
      LAYER met2 ;
      RECT 1265.390 0.000 1265.530 0.420 ;
    END
  END r0_rd_out[222]
  PIN r0_rd_out[223]
    DIRECTION OUTPUT ;
    USE SIGNAL ;
    SHAPE ABUTMENT ;
    PORT
      LAYER met2 ;
      RECT 1267.690 0.000 1267.830 0.420 ;
    END
  END r0_rd_out[223]
  PIN r0_rd_out[224]
    DIRECTION OUTPUT ;
    USE SIGNAL ;
    SHAPE ABUTMENT ;
    PORT
      LAYER met2 ;
      RECT 1269.990 0.000 1270.130 0.420 ;
    END
  END r0_rd_out[224]
  PIN r0_rd_out[225]
    DIRECTION OUTPUT ;
    USE SIGNAL ;
    SHAPE ABUTMENT ;
    PORT
      LAYER met2 ;
      RECT 1272.290 0.000 1272.430 0.420 ;
    END
  END r0_rd_out[225]
  PIN r0_rd_out[226]
    DIRECTION OUTPUT ;
    USE SIGNAL ;
    SHAPE ABUTMENT ;
    PORT
      LAYER met2 ;
      RECT 1274.590 0.000 1274.730 0.420 ;
    END
  END r0_rd_out[226]
  PIN r0_rd_out[227]
    DIRECTION OUTPUT ;
    USE SIGNAL ;
    SHAPE ABUTMENT ;
    PORT
      LAYER met2 ;
      RECT 1276.890 0.000 1277.030 0.420 ;
    END
  END r0_rd_out[227]
  PIN r0_rd_out[228]
    DIRECTION OUTPUT ;
    USE SIGNAL ;
    SHAPE ABUTMENT ;
    PORT
      LAYER met2 ;
      RECT 1279.190 0.000 1279.330 0.420 ;
    END
  END r0_rd_out[228]
  PIN r0_rd_out[229]
    DIRECTION OUTPUT ;
    USE SIGNAL ;
    SHAPE ABUTMENT ;
    PORT
      LAYER met2 ;
      RECT 1281.490 0.000 1281.630 0.420 ;
    END
  END r0_rd_out[229]
  PIN r0_rd_out[230]
    DIRECTION OUTPUT ;
    USE SIGNAL ;
    SHAPE ABUTMENT ;
    PORT
      LAYER met2 ;
      RECT 1283.790 0.000 1283.930 0.420 ;
    END
  END r0_rd_out[230]
  PIN r0_rd_out[231]
    DIRECTION OUTPUT ;
    USE SIGNAL ;
    SHAPE ABUTMENT ;
    PORT
      LAYER met2 ;
      RECT 1286.090 0.000 1286.230 0.420 ;
    END
  END r0_rd_out[231]
  PIN r0_rd_out[232]
    DIRECTION OUTPUT ;
    USE SIGNAL ;
    SHAPE ABUTMENT ;
    PORT
      LAYER met2 ;
      RECT 1288.390 0.000 1288.530 0.420 ;
    END
  END r0_rd_out[232]
  PIN r0_rd_out[233]
    DIRECTION OUTPUT ;
    USE SIGNAL ;
    SHAPE ABUTMENT ;
    PORT
      LAYER met2 ;
      RECT 1290.690 0.000 1290.830 0.420 ;
    END
  END r0_rd_out[233]
  PIN r0_rd_out[234]
    DIRECTION OUTPUT ;
    USE SIGNAL ;
    SHAPE ABUTMENT ;
    PORT
      LAYER met2 ;
      RECT 1292.990 0.000 1293.130 0.420 ;
    END
  END r0_rd_out[234]
  PIN r0_rd_out[235]
    DIRECTION OUTPUT ;
    USE SIGNAL ;
    SHAPE ABUTMENT ;
    PORT
      LAYER met2 ;
      RECT 1295.290 0.000 1295.430 0.420 ;
    END
  END r0_rd_out[235]
  PIN r0_rd_out[236]
    DIRECTION OUTPUT ;
    USE SIGNAL ;
    SHAPE ABUTMENT ;
    PORT
      LAYER met2 ;
      RECT 1297.590 0.000 1297.730 0.420 ;
    END
  END r0_rd_out[236]
  PIN r0_rd_out[237]
    DIRECTION OUTPUT ;
    USE SIGNAL ;
    SHAPE ABUTMENT ;
    PORT
      LAYER met2 ;
      RECT 1299.890 0.000 1300.030 0.420 ;
    END
  END r0_rd_out[237]
  PIN r0_rd_out[238]
    DIRECTION OUTPUT ;
    USE SIGNAL ;
    SHAPE ABUTMENT ;
    PORT
      LAYER met2 ;
      RECT 1302.190 0.000 1302.330 0.420 ;
    END
  END r0_rd_out[238]
  PIN r0_rd_out[239]
    DIRECTION OUTPUT ;
    USE SIGNAL ;
    SHAPE ABUTMENT ;
    PORT
      LAYER met2 ;
      RECT 1304.490 0.000 1304.630 0.420 ;
    END
  END r0_rd_out[239]
  PIN r0_rd_out[240]
    DIRECTION OUTPUT ;
    USE SIGNAL ;
    SHAPE ABUTMENT ;
    PORT
      LAYER met2 ;
      RECT 1306.790 0.000 1306.930 0.420 ;
    END
  END r0_rd_out[240]
  PIN r0_rd_out[241]
    DIRECTION OUTPUT ;
    USE SIGNAL ;
    SHAPE ABUTMENT ;
    PORT
      LAYER met2 ;
      RECT 1309.090 0.000 1309.230 0.420 ;
    END
  END r0_rd_out[241]
  PIN r0_rd_out[242]
    DIRECTION OUTPUT ;
    USE SIGNAL ;
    SHAPE ABUTMENT ;
    PORT
      LAYER met2 ;
      RECT 1311.390 0.000 1311.530 0.420 ;
    END
  END r0_rd_out[242]
  PIN r0_rd_out[243]
    DIRECTION OUTPUT ;
    USE SIGNAL ;
    SHAPE ABUTMENT ;
    PORT
      LAYER met2 ;
      RECT 1313.690 0.000 1313.830 0.420 ;
    END
  END r0_rd_out[243]
  PIN r0_rd_out[244]
    DIRECTION OUTPUT ;
    USE SIGNAL ;
    SHAPE ABUTMENT ;
    PORT
      LAYER met2 ;
      RECT 1315.990 0.000 1316.130 0.420 ;
    END
  END r0_rd_out[244]
  PIN r0_rd_out[245]
    DIRECTION OUTPUT ;
    USE SIGNAL ;
    SHAPE ABUTMENT ;
    PORT
      LAYER met2 ;
      RECT 1318.290 0.000 1318.430 0.420 ;
    END
  END r0_rd_out[245]
  PIN r0_rd_out[246]
    DIRECTION OUTPUT ;
    USE SIGNAL ;
    SHAPE ABUTMENT ;
    PORT
      LAYER met2 ;
      RECT 1320.590 0.000 1320.730 0.420 ;
    END
  END r0_rd_out[246]
  PIN r0_rd_out[247]
    DIRECTION OUTPUT ;
    USE SIGNAL ;
    SHAPE ABUTMENT ;
    PORT
      LAYER met2 ;
      RECT 1322.890 0.000 1323.030 0.420 ;
    END
  END r0_rd_out[247]
  PIN r0_rd_out[248]
    DIRECTION OUTPUT ;
    USE SIGNAL ;
    SHAPE ABUTMENT ;
    PORT
      LAYER met2 ;
      RECT 1325.190 0.000 1325.330 0.420 ;
    END
  END r0_rd_out[248]
  PIN r0_rd_out[249]
    DIRECTION OUTPUT ;
    USE SIGNAL ;
    SHAPE ABUTMENT ;
    PORT
      LAYER met2 ;
      RECT 1327.490 0.000 1327.630 0.420 ;
    END
  END r0_rd_out[249]
  PIN r0_rd_out[250]
    DIRECTION OUTPUT ;
    USE SIGNAL ;
    SHAPE ABUTMENT ;
    PORT
      LAYER met2 ;
      RECT 1329.790 0.000 1329.930 0.420 ;
    END
  END r0_rd_out[250]
  PIN r0_rd_out[251]
    DIRECTION OUTPUT ;
    USE SIGNAL ;
    SHAPE ABUTMENT ;
    PORT
      LAYER met2 ;
      RECT 1332.090 0.000 1332.230 0.420 ;
    END
  END r0_rd_out[251]
  PIN r0_rd_out[252]
    DIRECTION OUTPUT ;
    USE SIGNAL ;
    SHAPE ABUTMENT ;
    PORT
      LAYER met2 ;
      RECT 1334.390 0.000 1334.530 0.420 ;
    END
  END r0_rd_out[252]
  PIN r0_rd_out[253]
    DIRECTION OUTPUT ;
    USE SIGNAL ;
    SHAPE ABUTMENT ;
    PORT
      LAYER met2 ;
      RECT 1336.690 0.000 1336.830 0.420 ;
    END
  END r0_rd_out[253]
  PIN r0_rd_out[254]
    DIRECTION OUTPUT ;
    USE SIGNAL ;
    SHAPE ABUTMENT ;
    PORT
      LAYER met2 ;
      RECT 1338.990 0.000 1339.130 0.420 ;
    END
  END r0_rd_out[254]
  PIN r0_rd_out[255]
    DIRECTION OUTPUT ;
    USE SIGNAL ;
    SHAPE ABUTMENT ;
    PORT
      LAYER met2 ;
      RECT 1341.290 0.000 1341.430 0.420 ;
    END
  END r0_rd_out[255]
  PIN r0_rd_out[256]
    DIRECTION OUTPUT ;
    USE SIGNAL ;
    SHAPE ABUTMENT ;
    PORT
      LAYER met2 ;
      RECT 1343.590 0.000 1343.730 0.420 ;
    END
  END r0_rd_out[256]
  PIN r0_rd_out[257]
    DIRECTION OUTPUT ;
    USE SIGNAL ;
    SHAPE ABUTMENT ;
    PORT
      LAYER met2 ;
      RECT 1345.890 0.000 1346.030 0.420 ;
    END
  END r0_rd_out[257]
  PIN r0_rd_out[258]
    DIRECTION OUTPUT ;
    USE SIGNAL ;
    SHAPE ABUTMENT ;
    PORT
      LAYER met2 ;
      RECT 1348.190 0.000 1348.330 0.420 ;
    END
  END r0_rd_out[258]
  PIN r0_rd_out[259]
    DIRECTION OUTPUT ;
    USE SIGNAL ;
    SHAPE ABUTMENT ;
    PORT
      LAYER met2 ;
      RECT 1350.490 0.000 1350.630 0.420 ;
    END
  END r0_rd_out[259]
  PIN r0_rd_out[260]
    DIRECTION OUTPUT ;
    USE SIGNAL ;
    SHAPE ABUTMENT ;
    PORT
      LAYER met2 ;
      RECT 1352.790 0.000 1352.930 0.420 ;
    END
  END r0_rd_out[260]
  PIN r0_rd_out[261]
    DIRECTION OUTPUT ;
    USE SIGNAL ;
    SHAPE ABUTMENT ;
    PORT
      LAYER met2 ;
      RECT 1355.090 0.000 1355.230 0.420 ;
    END
  END r0_rd_out[261]
  PIN r0_rd_out[262]
    DIRECTION OUTPUT ;
    USE SIGNAL ;
    SHAPE ABUTMENT ;
    PORT
      LAYER met2 ;
      RECT 1357.390 0.000 1357.530 0.420 ;
    END
  END r0_rd_out[262]
  PIN r0_rd_out[263]
    DIRECTION OUTPUT ;
    USE SIGNAL ;
    SHAPE ABUTMENT ;
    PORT
      LAYER met2 ;
      RECT 1359.690 0.000 1359.830 0.420 ;
    END
  END r0_rd_out[263]
  PIN r0_rd_out[264]
    DIRECTION OUTPUT ;
    USE SIGNAL ;
    SHAPE ABUTMENT ;
    PORT
      LAYER met2 ;
      RECT 1361.990 0.000 1362.130 0.420 ;
    END
  END r0_rd_out[264]
  PIN r0_rd_out[265]
    DIRECTION OUTPUT ;
    USE SIGNAL ;
    SHAPE ABUTMENT ;
    PORT
      LAYER met2 ;
      RECT 1364.290 0.000 1364.430 0.420 ;
    END
  END r0_rd_out[265]
  PIN r0_rd_out[266]
    DIRECTION OUTPUT ;
    USE SIGNAL ;
    SHAPE ABUTMENT ;
    PORT
      LAYER met2 ;
      RECT 1366.590 0.000 1366.730 0.420 ;
    END
  END r0_rd_out[266]
  PIN r0_rd_out[267]
    DIRECTION OUTPUT ;
    USE SIGNAL ;
    SHAPE ABUTMENT ;
    PORT
      LAYER met2 ;
      RECT 1368.890 0.000 1369.030 0.420 ;
    END
  END r0_rd_out[267]
  PIN r0_rd_out[268]
    DIRECTION OUTPUT ;
    USE SIGNAL ;
    SHAPE ABUTMENT ;
    PORT
      LAYER met2 ;
      RECT 1371.190 0.000 1371.330 0.420 ;
    END
  END r0_rd_out[268]
  PIN r0_rd_out[269]
    DIRECTION OUTPUT ;
    USE SIGNAL ;
    SHAPE ABUTMENT ;
    PORT
      LAYER met2 ;
      RECT 1373.490 0.000 1373.630 0.420 ;
    END
  END r0_rd_out[269]
  PIN r0_rd_out[270]
    DIRECTION OUTPUT ;
    USE SIGNAL ;
    SHAPE ABUTMENT ;
    PORT
      LAYER met2 ;
      RECT 1375.790 0.000 1375.930 0.420 ;
    END
  END r0_rd_out[270]
  PIN r0_rd_out[271]
    DIRECTION OUTPUT ;
    USE SIGNAL ;
    SHAPE ABUTMENT ;
    PORT
      LAYER met2 ;
      RECT 1378.090 0.000 1378.230 0.420 ;
    END
  END r0_rd_out[271]
  PIN r0_rd_out[272]
    DIRECTION OUTPUT ;
    USE SIGNAL ;
    SHAPE ABUTMENT ;
    PORT
      LAYER met2 ;
      RECT 1380.390 0.000 1380.530 0.420 ;
    END
  END r0_rd_out[272]
  PIN r0_rd_out[273]
    DIRECTION OUTPUT ;
    USE SIGNAL ;
    SHAPE ABUTMENT ;
    PORT
      LAYER met2 ;
      RECT 1382.690 0.000 1382.830 0.420 ;
    END
  END r0_rd_out[273]
  PIN r0_rd_out[274]
    DIRECTION OUTPUT ;
    USE SIGNAL ;
    SHAPE ABUTMENT ;
    PORT
      LAYER met2 ;
      RECT 1384.990 0.000 1385.130 0.420 ;
    END
  END r0_rd_out[274]
  PIN r0_rd_out[275]
    DIRECTION OUTPUT ;
    USE SIGNAL ;
    SHAPE ABUTMENT ;
    PORT
      LAYER met2 ;
      RECT 1387.290 0.000 1387.430 0.420 ;
    END
  END r0_rd_out[275]
  PIN r0_rd_out[276]
    DIRECTION OUTPUT ;
    USE SIGNAL ;
    SHAPE ABUTMENT ;
    PORT
      LAYER met2 ;
      RECT 1389.590 0.000 1389.730 0.420 ;
    END
  END r0_rd_out[276]
  PIN r0_rd_out[277]
    DIRECTION OUTPUT ;
    USE SIGNAL ;
    SHAPE ABUTMENT ;
    PORT
      LAYER met2 ;
      RECT 1391.890 0.000 1392.030 0.420 ;
    END
  END r0_rd_out[277]
  PIN r0_rd_out[278]
    DIRECTION OUTPUT ;
    USE SIGNAL ;
    SHAPE ABUTMENT ;
    PORT
      LAYER met2 ;
      RECT 1394.190 0.000 1394.330 0.420 ;
    END
  END r0_rd_out[278]
  PIN r0_rd_out[279]
    DIRECTION OUTPUT ;
    USE SIGNAL ;
    SHAPE ABUTMENT ;
    PORT
      LAYER met2 ;
      RECT 1396.490 0.000 1396.630 0.420 ;
    END
  END r0_rd_out[279]
  PIN r0_rd_out[280]
    DIRECTION OUTPUT ;
    USE SIGNAL ;
    SHAPE ABUTMENT ;
    PORT
      LAYER met2 ;
      RECT 1398.790 0.000 1398.930 0.420 ;
    END
  END r0_rd_out[280]
  PIN r0_rd_out[281]
    DIRECTION OUTPUT ;
    USE SIGNAL ;
    SHAPE ABUTMENT ;
    PORT
      LAYER met2 ;
      RECT 1401.090 0.000 1401.230 0.420 ;
    END
  END r0_rd_out[281]
  PIN r0_rd_out[282]
    DIRECTION OUTPUT ;
    USE SIGNAL ;
    SHAPE ABUTMENT ;
    PORT
      LAYER met2 ;
      RECT 1403.390 0.000 1403.530 0.420 ;
    END
  END r0_rd_out[282]
  PIN r0_rd_out[283]
    DIRECTION OUTPUT ;
    USE SIGNAL ;
    SHAPE ABUTMENT ;
    PORT
      LAYER met2 ;
      RECT 1405.690 0.000 1405.830 0.420 ;
    END
  END r0_rd_out[283]
  PIN r0_rd_out[284]
    DIRECTION OUTPUT ;
    USE SIGNAL ;
    SHAPE ABUTMENT ;
    PORT
      LAYER met2 ;
      RECT 1407.990 0.000 1408.130 0.420 ;
    END
  END r0_rd_out[284]
  PIN r0_rd_out[285]
    DIRECTION OUTPUT ;
    USE SIGNAL ;
    SHAPE ABUTMENT ;
    PORT
      LAYER met2 ;
      RECT 1410.290 0.000 1410.430 0.420 ;
    END
  END r0_rd_out[285]
  PIN r0_rd_out[286]
    DIRECTION OUTPUT ;
    USE SIGNAL ;
    SHAPE ABUTMENT ;
    PORT
      LAYER met2 ;
      RECT 1412.590 0.000 1412.730 0.420 ;
    END
  END r0_rd_out[286]
  PIN r0_rd_out[287]
    DIRECTION OUTPUT ;
    USE SIGNAL ;
    SHAPE ABUTMENT ;
    PORT
      LAYER met2 ;
      RECT 1414.890 0.000 1415.030 0.420 ;
    END
  END r0_rd_out[287]
  PIN r0_rd_out[288]
    DIRECTION OUTPUT ;
    USE SIGNAL ;
    SHAPE ABUTMENT ;
    PORT
      LAYER met2 ;
      RECT 1417.190 0.000 1417.330 0.420 ;
    END
  END r0_rd_out[288]
  PIN r0_rd_out[289]
    DIRECTION OUTPUT ;
    USE SIGNAL ;
    SHAPE ABUTMENT ;
    PORT
      LAYER met2 ;
      RECT 1419.490 0.000 1419.630 0.420 ;
    END
  END r0_rd_out[289]
  PIN r0_rd_out[290]
    DIRECTION OUTPUT ;
    USE SIGNAL ;
    SHAPE ABUTMENT ;
    PORT
      LAYER met2 ;
      RECT 1421.790 0.000 1421.930 0.420 ;
    END
  END r0_rd_out[290]
  PIN r0_rd_out[291]
    DIRECTION OUTPUT ;
    USE SIGNAL ;
    SHAPE ABUTMENT ;
    PORT
      LAYER met2 ;
      RECT 1424.090 0.000 1424.230 0.420 ;
    END
  END r0_rd_out[291]
  PIN r0_rd_out[292]
    DIRECTION OUTPUT ;
    USE SIGNAL ;
    SHAPE ABUTMENT ;
    PORT
      LAYER met2 ;
      RECT 1426.390 0.000 1426.530 0.420 ;
    END
  END r0_rd_out[292]
  PIN r0_rd_out[293]
    DIRECTION OUTPUT ;
    USE SIGNAL ;
    SHAPE ABUTMENT ;
    PORT
      LAYER met2 ;
      RECT 1428.690 0.000 1428.830 0.420 ;
    END
  END r0_rd_out[293]
  PIN r0_rd_out[294]
    DIRECTION OUTPUT ;
    USE SIGNAL ;
    SHAPE ABUTMENT ;
    PORT
      LAYER met2 ;
      RECT 1430.990 0.000 1431.130 0.420 ;
    END
  END r0_rd_out[294]
  PIN r0_rd_out[295]
    DIRECTION OUTPUT ;
    USE SIGNAL ;
    SHAPE ABUTMENT ;
    PORT
      LAYER met2 ;
      RECT 1433.290 0.000 1433.430 0.420 ;
    END
  END r0_rd_out[295]
  PIN r0_rd_out[296]
    DIRECTION OUTPUT ;
    USE SIGNAL ;
    SHAPE ABUTMENT ;
    PORT
      LAYER met2 ;
      RECT 1435.590 0.000 1435.730 0.420 ;
    END
  END r0_rd_out[296]
  PIN r0_rd_out[297]
    DIRECTION OUTPUT ;
    USE SIGNAL ;
    SHAPE ABUTMENT ;
    PORT
      LAYER met2 ;
      RECT 1437.890 0.000 1438.030 0.420 ;
    END
  END r0_rd_out[297]
  PIN r0_rd_out[298]
    DIRECTION OUTPUT ;
    USE SIGNAL ;
    SHAPE ABUTMENT ;
    PORT
      LAYER met2 ;
      RECT 1440.190 0.000 1440.330 0.420 ;
    END
  END r0_rd_out[298]
  PIN r0_rd_out[299]
    DIRECTION OUTPUT ;
    USE SIGNAL ;
    SHAPE ABUTMENT ;
    PORT
      LAYER met2 ;
      RECT 1442.490 0.000 1442.630 0.420 ;
    END
  END r0_rd_out[299]
  PIN r0_rd_out[300]
    DIRECTION OUTPUT ;
    USE SIGNAL ;
    SHAPE ABUTMENT ;
    PORT
      LAYER met2 ;
      RECT 1444.790 0.000 1444.930 0.420 ;
    END
  END r0_rd_out[300]
  PIN r0_rd_out[301]
    DIRECTION OUTPUT ;
    USE SIGNAL ;
    SHAPE ABUTMENT ;
    PORT
      LAYER met2 ;
      RECT 1447.090 0.000 1447.230 0.420 ;
    END
  END r0_rd_out[301]
  PIN r0_rd_out[302]
    DIRECTION OUTPUT ;
    USE SIGNAL ;
    SHAPE ABUTMENT ;
    PORT
      LAYER met2 ;
      RECT 1449.390 0.000 1449.530 0.420 ;
    END
  END r0_rd_out[302]
  PIN r0_rd_out[303]
    DIRECTION OUTPUT ;
    USE SIGNAL ;
    SHAPE ABUTMENT ;
    PORT
      LAYER met2 ;
      RECT 1451.690 0.000 1451.830 0.420 ;
    END
  END r0_rd_out[303]
  PIN r0_rd_out[304]
    DIRECTION OUTPUT ;
    USE SIGNAL ;
    SHAPE ABUTMENT ;
    PORT
      LAYER met2 ;
      RECT 1453.990 0.000 1454.130 0.420 ;
    END
  END r0_rd_out[304]
  PIN r0_rd_out[305]
    DIRECTION OUTPUT ;
    USE SIGNAL ;
    SHAPE ABUTMENT ;
    PORT
      LAYER met2 ;
      RECT 1456.290 0.000 1456.430 0.420 ;
    END
  END r0_rd_out[305]
  PIN r0_rd_out[306]
    DIRECTION OUTPUT ;
    USE SIGNAL ;
    SHAPE ABUTMENT ;
    PORT
      LAYER met2 ;
      RECT 1458.590 0.000 1458.730 0.420 ;
    END
  END r0_rd_out[306]
  PIN r0_rd_out[307]
    DIRECTION OUTPUT ;
    USE SIGNAL ;
    SHAPE ABUTMENT ;
    PORT
      LAYER met2 ;
      RECT 1460.890 0.000 1461.030 0.420 ;
    END
  END r0_rd_out[307]
  PIN r0_rd_out[308]
    DIRECTION OUTPUT ;
    USE SIGNAL ;
    SHAPE ABUTMENT ;
    PORT
      LAYER met2 ;
      RECT 1463.190 0.000 1463.330 0.420 ;
    END
  END r0_rd_out[308]
  PIN r0_rd_out[309]
    DIRECTION OUTPUT ;
    USE SIGNAL ;
    SHAPE ABUTMENT ;
    PORT
      LAYER met2 ;
      RECT 1465.490 0.000 1465.630 0.420 ;
    END
  END r0_rd_out[309]
  PIN r0_rd_out[310]
    DIRECTION OUTPUT ;
    USE SIGNAL ;
    SHAPE ABUTMENT ;
    PORT
      LAYER met2 ;
      RECT 1467.790 0.000 1467.930 0.420 ;
    END
  END r0_rd_out[310]
  PIN r0_rd_out[311]
    DIRECTION OUTPUT ;
    USE SIGNAL ;
    SHAPE ABUTMENT ;
    PORT
      LAYER met2 ;
      RECT 1470.090 0.000 1470.230 0.420 ;
    END
  END r0_rd_out[311]
  PIN r0_rd_out[312]
    DIRECTION OUTPUT ;
    USE SIGNAL ;
    SHAPE ABUTMENT ;
    PORT
      LAYER met2 ;
      RECT 1472.390 0.000 1472.530 0.420 ;
    END
  END r0_rd_out[312]
  PIN r0_rd_out[313]
    DIRECTION OUTPUT ;
    USE SIGNAL ;
    SHAPE ABUTMENT ;
    PORT
      LAYER met2 ;
      RECT 1474.690 0.000 1474.830 0.420 ;
    END
  END r0_rd_out[313]
  PIN r0_rd_out[314]
    DIRECTION OUTPUT ;
    USE SIGNAL ;
    SHAPE ABUTMENT ;
    PORT
      LAYER met2 ;
      RECT 1476.990 0.000 1477.130 0.420 ;
    END
  END r0_rd_out[314]
  PIN r0_rd_out[315]
    DIRECTION OUTPUT ;
    USE SIGNAL ;
    SHAPE ABUTMENT ;
    PORT
      LAYER met2 ;
      RECT 1479.290 0.000 1479.430 0.420 ;
    END
  END r0_rd_out[315]
  PIN r0_rd_out[316]
    DIRECTION OUTPUT ;
    USE SIGNAL ;
    SHAPE ABUTMENT ;
    PORT
      LAYER met2 ;
      RECT 1481.590 0.000 1481.730 0.420 ;
    END
  END r0_rd_out[316]
  PIN r0_rd_out[317]
    DIRECTION OUTPUT ;
    USE SIGNAL ;
    SHAPE ABUTMENT ;
    PORT
      LAYER met2 ;
      RECT 1483.890 0.000 1484.030 0.420 ;
    END
  END r0_rd_out[317]
  PIN r0_rd_out[318]
    DIRECTION OUTPUT ;
    USE SIGNAL ;
    SHAPE ABUTMENT ;
    PORT
      LAYER met2 ;
      RECT 1486.190 0.000 1486.330 0.420 ;
    END
  END r0_rd_out[318]
  PIN r0_rd_out[319]
    DIRECTION OUTPUT ;
    USE SIGNAL ;
    SHAPE ABUTMENT ;
    PORT
      LAYER met2 ;
      RECT 1488.490 0.000 1488.630 0.420 ;
    END
  END r0_rd_out[319]
  PIN r0_rd_out[320]
    DIRECTION OUTPUT ;
    USE SIGNAL ;
    SHAPE ABUTMENT ;
    PORT
      LAYER met2 ;
      RECT 1490.790 0.000 1490.930 0.420 ;
    END
  END r0_rd_out[320]
  PIN r0_rd_out[321]
    DIRECTION OUTPUT ;
    USE SIGNAL ;
    SHAPE ABUTMENT ;
    PORT
      LAYER met2 ;
      RECT 1493.090 0.000 1493.230 0.420 ;
    END
  END r0_rd_out[321]
  PIN r0_rd_out[322]
    DIRECTION OUTPUT ;
    USE SIGNAL ;
    SHAPE ABUTMENT ;
    PORT
      LAYER met2 ;
      RECT 1495.390 0.000 1495.530 0.420 ;
    END
  END r0_rd_out[322]
  PIN r0_rd_out[323]
    DIRECTION OUTPUT ;
    USE SIGNAL ;
    SHAPE ABUTMENT ;
    PORT
      LAYER met2 ;
      RECT 1497.690 0.000 1497.830 0.420 ;
    END
  END r0_rd_out[323]
  PIN r0_rd_out[324]
    DIRECTION OUTPUT ;
    USE SIGNAL ;
    SHAPE ABUTMENT ;
    PORT
      LAYER met2 ;
      RECT 1499.990 0.000 1500.130 0.420 ;
    END
  END r0_rd_out[324]
  PIN r0_rd_out[325]
    DIRECTION OUTPUT ;
    USE SIGNAL ;
    SHAPE ABUTMENT ;
    PORT
      LAYER met2 ;
      RECT 1502.290 0.000 1502.430 0.420 ;
    END
  END r0_rd_out[325]
  PIN r0_rd_out[326]
    DIRECTION OUTPUT ;
    USE SIGNAL ;
    SHAPE ABUTMENT ;
    PORT
      LAYER met2 ;
      RECT 1504.590 0.000 1504.730 0.420 ;
    END
  END r0_rd_out[326]
  PIN r0_rd_out[327]
    DIRECTION OUTPUT ;
    USE SIGNAL ;
    SHAPE ABUTMENT ;
    PORT
      LAYER met2 ;
      RECT 754.790 1688.700 754.930 1689.120 ;
    END
  END r0_rd_out[327]
  PIN r0_rd_out[328]
    DIRECTION OUTPUT ;
    USE SIGNAL ;
    SHAPE ABUTMENT ;
    PORT
      LAYER met2 ;
      RECT 757.090 1688.700 757.230 1689.120 ;
    END
  END r0_rd_out[328]
  PIN r0_rd_out[329]
    DIRECTION OUTPUT ;
    USE SIGNAL ;
    SHAPE ABUTMENT ;
    PORT
      LAYER met2 ;
      RECT 759.390 1688.700 759.530 1689.120 ;
    END
  END r0_rd_out[329]
  PIN r0_rd_out[330]
    DIRECTION OUTPUT ;
    USE SIGNAL ;
    SHAPE ABUTMENT ;
    PORT
      LAYER met2 ;
      RECT 761.690 1688.700 761.830 1689.120 ;
    END
  END r0_rd_out[330]
  PIN r0_rd_out[331]
    DIRECTION OUTPUT ;
    USE SIGNAL ;
    SHAPE ABUTMENT ;
    PORT
      LAYER met2 ;
      RECT 763.990 1688.700 764.130 1689.120 ;
    END
  END r0_rd_out[331]
  PIN r0_rd_out[332]
    DIRECTION OUTPUT ;
    USE SIGNAL ;
    SHAPE ABUTMENT ;
    PORT
      LAYER met2 ;
      RECT 766.290 1688.700 766.430 1689.120 ;
    END
  END r0_rd_out[332]
  PIN r0_rd_out[333]
    DIRECTION OUTPUT ;
    USE SIGNAL ;
    SHAPE ABUTMENT ;
    PORT
      LAYER met2 ;
      RECT 768.590 1688.700 768.730 1689.120 ;
    END
  END r0_rd_out[333]
  PIN r0_rd_out[334]
    DIRECTION OUTPUT ;
    USE SIGNAL ;
    SHAPE ABUTMENT ;
    PORT
      LAYER met2 ;
      RECT 770.890 1688.700 771.030 1689.120 ;
    END
  END r0_rd_out[334]
  PIN r0_rd_out[335]
    DIRECTION OUTPUT ;
    USE SIGNAL ;
    SHAPE ABUTMENT ;
    PORT
      LAYER met2 ;
      RECT 773.190 1688.700 773.330 1689.120 ;
    END
  END r0_rd_out[335]
  PIN r0_rd_out[336]
    DIRECTION OUTPUT ;
    USE SIGNAL ;
    SHAPE ABUTMENT ;
    PORT
      LAYER met2 ;
      RECT 775.490 1688.700 775.630 1689.120 ;
    END
  END r0_rd_out[336]
  PIN r0_rd_out[337]
    DIRECTION OUTPUT ;
    USE SIGNAL ;
    SHAPE ABUTMENT ;
    PORT
      LAYER met2 ;
      RECT 777.790 1688.700 777.930 1689.120 ;
    END
  END r0_rd_out[337]
  PIN r0_rd_out[338]
    DIRECTION OUTPUT ;
    USE SIGNAL ;
    SHAPE ABUTMENT ;
    PORT
      LAYER met2 ;
      RECT 780.090 1688.700 780.230 1689.120 ;
    END
  END r0_rd_out[338]
  PIN r0_rd_out[339]
    DIRECTION OUTPUT ;
    USE SIGNAL ;
    SHAPE ABUTMENT ;
    PORT
      LAYER met2 ;
      RECT 782.390 1688.700 782.530 1689.120 ;
    END
  END r0_rd_out[339]
  PIN r0_rd_out[340]
    DIRECTION OUTPUT ;
    USE SIGNAL ;
    SHAPE ABUTMENT ;
    PORT
      LAYER met2 ;
      RECT 784.690 1688.700 784.830 1689.120 ;
    END
  END r0_rd_out[340]
  PIN r0_rd_out[341]
    DIRECTION OUTPUT ;
    USE SIGNAL ;
    SHAPE ABUTMENT ;
    PORT
      LAYER met2 ;
      RECT 786.990 1688.700 787.130 1689.120 ;
    END
  END r0_rd_out[341]
  PIN r0_rd_out[342]
    DIRECTION OUTPUT ;
    USE SIGNAL ;
    SHAPE ABUTMENT ;
    PORT
      LAYER met2 ;
      RECT 789.290 1688.700 789.430 1689.120 ;
    END
  END r0_rd_out[342]
  PIN r0_rd_out[343]
    DIRECTION OUTPUT ;
    USE SIGNAL ;
    SHAPE ABUTMENT ;
    PORT
      LAYER met2 ;
      RECT 791.590 1688.700 791.730 1689.120 ;
    END
  END r0_rd_out[343]
  PIN r0_rd_out[344]
    DIRECTION OUTPUT ;
    USE SIGNAL ;
    SHAPE ABUTMENT ;
    PORT
      LAYER met2 ;
      RECT 793.890 1688.700 794.030 1689.120 ;
    END
  END r0_rd_out[344]
  PIN r0_rd_out[345]
    DIRECTION OUTPUT ;
    USE SIGNAL ;
    SHAPE ABUTMENT ;
    PORT
      LAYER met2 ;
      RECT 796.190 1688.700 796.330 1689.120 ;
    END
  END r0_rd_out[345]
  PIN r0_rd_out[346]
    DIRECTION OUTPUT ;
    USE SIGNAL ;
    SHAPE ABUTMENT ;
    PORT
      LAYER met2 ;
      RECT 798.490 1688.700 798.630 1689.120 ;
    END
  END r0_rd_out[346]
  PIN r0_rd_out[347]
    DIRECTION OUTPUT ;
    USE SIGNAL ;
    SHAPE ABUTMENT ;
    PORT
      LAYER met2 ;
      RECT 800.790 1688.700 800.930 1689.120 ;
    END
  END r0_rd_out[347]
  PIN r0_rd_out[348]
    DIRECTION OUTPUT ;
    USE SIGNAL ;
    SHAPE ABUTMENT ;
    PORT
      LAYER met2 ;
      RECT 803.090 1688.700 803.230 1689.120 ;
    END
  END r0_rd_out[348]
  PIN r0_rd_out[349]
    DIRECTION OUTPUT ;
    USE SIGNAL ;
    SHAPE ABUTMENT ;
    PORT
      LAYER met2 ;
      RECT 805.390 1688.700 805.530 1689.120 ;
    END
  END r0_rd_out[349]
  PIN r0_rd_out[350]
    DIRECTION OUTPUT ;
    USE SIGNAL ;
    SHAPE ABUTMENT ;
    PORT
      LAYER met2 ;
      RECT 807.690 1688.700 807.830 1689.120 ;
    END
  END r0_rd_out[350]
  PIN r0_rd_out[351]
    DIRECTION OUTPUT ;
    USE SIGNAL ;
    SHAPE ABUTMENT ;
    PORT
      LAYER met2 ;
      RECT 809.990 1688.700 810.130 1689.120 ;
    END
  END r0_rd_out[351]
  PIN r0_rd_out[352]
    DIRECTION OUTPUT ;
    USE SIGNAL ;
    SHAPE ABUTMENT ;
    PORT
      LAYER met2 ;
      RECT 812.290 1688.700 812.430 1689.120 ;
    END
  END r0_rd_out[352]
  PIN r0_rd_out[353]
    DIRECTION OUTPUT ;
    USE SIGNAL ;
    SHAPE ABUTMENT ;
    PORT
      LAYER met2 ;
      RECT 814.590 1688.700 814.730 1689.120 ;
    END
  END r0_rd_out[353]
  PIN r0_rd_out[354]
    DIRECTION OUTPUT ;
    USE SIGNAL ;
    SHAPE ABUTMENT ;
    PORT
      LAYER met2 ;
      RECT 816.890 1688.700 817.030 1689.120 ;
    END
  END r0_rd_out[354]
  PIN r0_rd_out[355]
    DIRECTION OUTPUT ;
    USE SIGNAL ;
    SHAPE ABUTMENT ;
    PORT
      LAYER met2 ;
      RECT 819.190 1688.700 819.330 1689.120 ;
    END
  END r0_rd_out[355]
  PIN r0_rd_out[356]
    DIRECTION OUTPUT ;
    USE SIGNAL ;
    SHAPE ABUTMENT ;
    PORT
      LAYER met2 ;
      RECT 821.490 1688.700 821.630 1689.120 ;
    END
  END r0_rd_out[356]
  PIN r0_rd_out[357]
    DIRECTION OUTPUT ;
    USE SIGNAL ;
    SHAPE ABUTMENT ;
    PORT
      LAYER met2 ;
      RECT 823.790 1688.700 823.930 1689.120 ;
    END
  END r0_rd_out[357]
  PIN r0_rd_out[358]
    DIRECTION OUTPUT ;
    USE SIGNAL ;
    SHAPE ABUTMENT ;
    PORT
      LAYER met2 ;
      RECT 826.090 1688.700 826.230 1689.120 ;
    END
  END r0_rd_out[358]
  PIN r0_rd_out[359]
    DIRECTION OUTPUT ;
    USE SIGNAL ;
    SHAPE ABUTMENT ;
    PORT
      LAYER met2 ;
      RECT 828.390 1688.700 828.530 1689.120 ;
    END
  END r0_rd_out[359]
  PIN r0_rd_out[360]
    DIRECTION OUTPUT ;
    USE SIGNAL ;
    SHAPE ABUTMENT ;
    PORT
      LAYER met2 ;
      RECT 830.690 1688.700 830.830 1689.120 ;
    END
  END r0_rd_out[360]
  PIN r0_rd_out[361]
    DIRECTION OUTPUT ;
    USE SIGNAL ;
    SHAPE ABUTMENT ;
    PORT
      LAYER met2 ;
      RECT 832.990 1688.700 833.130 1689.120 ;
    END
  END r0_rd_out[361]
  PIN r0_rd_out[362]
    DIRECTION OUTPUT ;
    USE SIGNAL ;
    SHAPE ABUTMENT ;
    PORT
      LAYER met2 ;
      RECT 835.290 1688.700 835.430 1689.120 ;
    END
  END r0_rd_out[362]
  PIN r0_rd_out[363]
    DIRECTION OUTPUT ;
    USE SIGNAL ;
    SHAPE ABUTMENT ;
    PORT
      LAYER met2 ;
      RECT 837.590 1688.700 837.730 1689.120 ;
    END
  END r0_rd_out[363]
  PIN r0_rd_out[364]
    DIRECTION OUTPUT ;
    USE SIGNAL ;
    SHAPE ABUTMENT ;
    PORT
      LAYER met2 ;
      RECT 839.890 1688.700 840.030 1689.120 ;
    END
  END r0_rd_out[364]
  PIN r0_rd_out[365]
    DIRECTION OUTPUT ;
    USE SIGNAL ;
    SHAPE ABUTMENT ;
    PORT
      LAYER met2 ;
      RECT 842.190 1688.700 842.330 1689.120 ;
    END
  END r0_rd_out[365]
  PIN r0_rd_out[366]
    DIRECTION OUTPUT ;
    USE SIGNAL ;
    SHAPE ABUTMENT ;
    PORT
      LAYER met2 ;
      RECT 844.490 1688.700 844.630 1689.120 ;
    END
  END r0_rd_out[366]
  PIN r0_rd_out[367]
    DIRECTION OUTPUT ;
    USE SIGNAL ;
    SHAPE ABUTMENT ;
    PORT
      LAYER met2 ;
      RECT 846.790 1688.700 846.930 1689.120 ;
    END
  END r0_rd_out[367]
  PIN r0_rd_out[368]
    DIRECTION OUTPUT ;
    USE SIGNAL ;
    SHAPE ABUTMENT ;
    PORT
      LAYER met2 ;
      RECT 849.090 1688.700 849.230 1689.120 ;
    END
  END r0_rd_out[368]
  PIN r0_rd_out[369]
    DIRECTION OUTPUT ;
    USE SIGNAL ;
    SHAPE ABUTMENT ;
    PORT
      LAYER met2 ;
      RECT 851.390 1688.700 851.530 1689.120 ;
    END
  END r0_rd_out[369]
  PIN r0_rd_out[370]
    DIRECTION OUTPUT ;
    USE SIGNAL ;
    SHAPE ABUTMENT ;
    PORT
      LAYER met2 ;
      RECT 853.690 1688.700 853.830 1689.120 ;
    END
  END r0_rd_out[370]
  PIN r0_rd_out[371]
    DIRECTION OUTPUT ;
    USE SIGNAL ;
    SHAPE ABUTMENT ;
    PORT
      LAYER met2 ;
      RECT 855.990 1688.700 856.130 1689.120 ;
    END
  END r0_rd_out[371]
  PIN r0_rd_out[372]
    DIRECTION OUTPUT ;
    USE SIGNAL ;
    SHAPE ABUTMENT ;
    PORT
      LAYER met2 ;
      RECT 858.290 1688.700 858.430 1689.120 ;
    END
  END r0_rd_out[372]
  PIN r0_rd_out[373]
    DIRECTION OUTPUT ;
    USE SIGNAL ;
    SHAPE ABUTMENT ;
    PORT
      LAYER met2 ;
      RECT 860.590 1688.700 860.730 1689.120 ;
    END
  END r0_rd_out[373]
  PIN r0_rd_out[374]
    DIRECTION OUTPUT ;
    USE SIGNAL ;
    SHAPE ABUTMENT ;
    PORT
      LAYER met2 ;
      RECT 862.890 1688.700 863.030 1689.120 ;
    END
  END r0_rd_out[374]
  PIN r0_rd_out[375]
    DIRECTION OUTPUT ;
    USE SIGNAL ;
    SHAPE ABUTMENT ;
    PORT
      LAYER met2 ;
      RECT 865.190 1688.700 865.330 1689.120 ;
    END
  END r0_rd_out[375]
  PIN r0_rd_out[376]
    DIRECTION OUTPUT ;
    USE SIGNAL ;
    SHAPE ABUTMENT ;
    PORT
      LAYER met2 ;
      RECT 867.490 1688.700 867.630 1689.120 ;
    END
  END r0_rd_out[376]
  PIN r0_rd_out[377]
    DIRECTION OUTPUT ;
    USE SIGNAL ;
    SHAPE ABUTMENT ;
    PORT
      LAYER met2 ;
      RECT 869.790 1688.700 869.930 1689.120 ;
    END
  END r0_rd_out[377]
  PIN r0_rd_out[378]
    DIRECTION OUTPUT ;
    USE SIGNAL ;
    SHAPE ABUTMENT ;
    PORT
      LAYER met2 ;
      RECT 872.090 1688.700 872.230 1689.120 ;
    END
  END r0_rd_out[378]
  PIN r0_rd_out[379]
    DIRECTION OUTPUT ;
    USE SIGNAL ;
    SHAPE ABUTMENT ;
    PORT
      LAYER met2 ;
      RECT 874.390 1688.700 874.530 1689.120 ;
    END
  END r0_rd_out[379]
  PIN r0_rd_out[380]
    DIRECTION OUTPUT ;
    USE SIGNAL ;
    SHAPE ABUTMENT ;
    PORT
      LAYER met2 ;
      RECT 876.690 1688.700 876.830 1689.120 ;
    END
  END r0_rd_out[380]
  PIN r0_rd_out[381]
    DIRECTION OUTPUT ;
    USE SIGNAL ;
    SHAPE ABUTMENT ;
    PORT
      LAYER met2 ;
      RECT 878.990 1688.700 879.130 1689.120 ;
    END
  END r0_rd_out[381]
  PIN r0_rd_out[382]
    DIRECTION OUTPUT ;
    USE SIGNAL ;
    SHAPE ABUTMENT ;
    PORT
      LAYER met2 ;
      RECT 881.290 1688.700 881.430 1689.120 ;
    END
  END r0_rd_out[382]
  PIN r0_rd_out[383]
    DIRECTION OUTPUT ;
    USE SIGNAL ;
    SHAPE ABUTMENT ;
    PORT
      LAYER met2 ;
      RECT 883.590 1688.700 883.730 1689.120 ;
    END
  END r0_rd_out[383]
  PIN r0_rd_out[384]
    DIRECTION OUTPUT ;
    USE SIGNAL ;
    SHAPE ABUTMENT ;
    PORT
      LAYER met2 ;
      RECT 885.890 1688.700 886.030 1689.120 ;
    END
  END r0_rd_out[384]
  PIN r0_rd_out[385]
    DIRECTION OUTPUT ;
    USE SIGNAL ;
    SHAPE ABUTMENT ;
    PORT
      LAYER met2 ;
      RECT 888.190 1688.700 888.330 1689.120 ;
    END
  END r0_rd_out[385]
  PIN r0_rd_out[386]
    DIRECTION OUTPUT ;
    USE SIGNAL ;
    SHAPE ABUTMENT ;
    PORT
      LAYER met2 ;
      RECT 890.490 1688.700 890.630 1689.120 ;
    END
  END r0_rd_out[386]
  PIN r0_rd_out[387]
    DIRECTION OUTPUT ;
    USE SIGNAL ;
    SHAPE ABUTMENT ;
    PORT
      LAYER met2 ;
      RECT 892.790 1688.700 892.930 1689.120 ;
    END
  END r0_rd_out[387]
  PIN r0_rd_out[388]
    DIRECTION OUTPUT ;
    USE SIGNAL ;
    SHAPE ABUTMENT ;
    PORT
      LAYER met2 ;
      RECT 895.090 1688.700 895.230 1689.120 ;
    END
  END r0_rd_out[388]
  PIN r0_rd_out[389]
    DIRECTION OUTPUT ;
    USE SIGNAL ;
    SHAPE ABUTMENT ;
    PORT
      LAYER met2 ;
      RECT 897.390 1688.700 897.530 1689.120 ;
    END
  END r0_rd_out[389]
  PIN r0_rd_out[390]
    DIRECTION OUTPUT ;
    USE SIGNAL ;
    SHAPE ABUTMENT ;
    PORT
      LAYER met2 ;
      RECT 899.690 1688.700 899.830 1689.120 ;
    END
  END r0_rd_out[390]
  PIN r0_rd_out[391]
    DIRECTION OUTPUT ;
    USE SIGNAL ;
    SHAPE ABUTMENT ;
    PORT
      LAYER met2 ;
      RECT 901.990 1688.700 902.130 1689.120 ;
    END
  END r0_rd_out[391]
  PIN r0_rd_out[392]
    DIRECTION OUTPUT ;
    USE SIGNAL ;
    SHAPE ABUTMENT ;
    PORT
      LAYER met2 ;
      RECT 904.290 1688.700 904.430 1689.120 ;
    END
  END r0_rd_out[392]
  PIN r0_rd_out[393]
    DIRECTION OUTPUT ;
    USE SIGNAL ;
    SHAPE ABUTMENT ;
    PORT
      LAYER met2 ;
      RECT 906.590 1688.700 906.730 1689.120 ;
    END
  END r0_rd_out[393]
  PIN r0_rd_out[394]
    DIRECTION OUTPUT ;
    USE SIGNAL ;
    SHAPE ABUTMENT ;
    PORT
      LAYER met2 ;
      RECT 908.890 1688.700 909.030 1689.120 ;
    END
  END r0_rd_out[394]
  PIN r0_rd_out[395]
    DIRECTION OUTPUT ;
    USE SIGNAL ;
    SHAPE ABUTMENT ;
    PORT
      LAYER met2 ;
      RECT 911.190 1688.700 911.330 1689.120 ;
    END
  END r0_rd_out[395]
  PIN r0_rd_out[396]
    DIRECTION OUTPUT ;
    USE SIGNAL ;
    SHAPE ABUTMENT ;
    PORT
      LAYER met2 ;
      RECT 913.490 1688.700 913.630 1689.120 ;
    END
  END r0_rd_out[396]
  PIN r0_rd_out[397]
    DIRECTION OUTPUT ;
    USE SIGNAL ;
    SHAPE ABUTMENT ;
    PORT
      LAYER met2 ;
      RECT 915.790 1688.700 915.930 1689.120 ;
    END
  END r0_rd_out[397]
  PIN r0_rd_out[398]
    DIRECTION OUTPUT ;
    USE SIGNAL ;
    SHAPE ABUTMENT ;
    PORT
      LAYER met2 ;
      RECT 918.090 1688.700 918.230 1689.120 ;
    END
  END r0_rd_out[398]
  PIN r0_rd_out[399]
    DIRECTION OUTPUT ;
    USE SIGNAL ;
    SHAPE ABUTMENT ;
    PORT
      LAYER met2 ;
      RECT 920.390 1688.700 920.530 1689.120 ;
    END
  END r0_rd_out[399]
  PIN r0_rd_out[400]
    DIRECTION OUTPUT ;
    USE SIGNAL ;
    SHAPE ABUTMENT ;
    PORT
      LAYER met2 ;
      RECT 922.690 1688.700 922.830 1689.120 ;
    END
  END r0_rd_out[400]
  PIN r0_rd_out[401]
    DIRECTION OUTPUT ;
    USE SIGNAL ;
    SHAPE ABUTMENT ;
    PORT
      LAYER met2 ;
      RECT 924.990 1688.700 925.130 1689.120 ;
    END
  END r0_rd_out[401]
  PIN r0_rd_out[402]
    DIRECTION OUTPUT ;
    USE SIGNAL ;
    SHAPE ABUTMENT ;
    PORT
      LAYER met2 ;
      RECT 927.290 1688.700 927.430 1689.120 ;
    END
  END r0_rd_out[402]
  PIN r0_rd_out[403]
    DIRECTION OUTPUT ;
    USE SIGNAL ;
    SHAPE ABUTMENT ;
    PORT
      LAYER met2 ;
      RECT 929.590 1688.700 929.730 1689.120 ;
    END
  END r0_rd_out[403]
  PIN r0_rd_out[404]
    DIRECTION OUTPUT ;
    USE SIGNAL ;
    SHAPE ABUTMENT ;
    PORT
      LAYER met2 ;
      RECT 931.890 1688.700 932.030 1689.120 ;
    END
  END r0_rd_out[404]
  PIN r0_rd_out[405]
    DIRECTION OUTPUT ;
    USE SIGNAL ;
    SHAPE ABUTMENT ;
    PORT
      LAYER met2 ;
      RECT 934.190 1688.700 934.330 1689.120 ;
    END
  END r0_rd_out[405]
  PIN r0_rd_out[406]
    DIRECTION OUTPUT ;
    USE SIGNAL ;
    SHAPE ABUTMENT ;
    PORT
      LAYER met2 ;
      RECT 936.490 1688.700 936.630 1689.120 ;
    END
  END r0_rd_out[406]
  PIN r0_rd_out[407]
    DIRECTION OUTPUT ;
    USE SIGNAL ;
    SHAPE ABUTMENT ;
    PORT
      LAYER met2 ;
      RECT 938.790 1688.700 938.930 1689.120 ;
    END
  END r0_rd_out[407]
  PIN r0_rd_out[408]
    DIRECTION OUTPUT ;
    USE SIGNAL ;
    SHAPE ABUTMENT ;
    PORT
      LAYER met2 ;
      RECT 941.090 1688.700 941.230 1689.120 ;
    END
  END r0_rd_out[408]
  PIN r0_rd_out[409]
    DIRECTION OUTPUT ;
    USE SIGNAL ;
    SHAPE ABUTMENT ;
    PORT
      LAYER met2 ;
      RECT 943.390 1688.700 943.530 1689.120 ;
    END
  END r0_rd_out[409]
  PIN r0_rd_out[410]
    DIRECTION OUTPUT ;
    USE SIGNAL ;
    SHAPE ABUTMENT ;
    PORT
      LAYER met2 ;
      RECT 945.690 1688.700 945.830 1689.120 ;
    END
  END r0_rd_out[410]
  PIN r0_rd_out[411]
    DIRECTION OUTPUT ;
    USE SIGNAL ;
    SHAPE ABUTMENT ;
    PORT
      LAYER met2 ;
      RECT 947.990 1688.700 948.130 1689.120 ;
    END
  END r0_rd_out[411]
  PIN r0_rd_out[412]
    DIRECTION OUTPUT ;
    USE SIGNAL ;
    SHAPE ABUTMENT ;
    PORT
      LAYER met2 ;
      RECT 950.290 1688.700 950.430 1689.120 ;
    END
  END r0_rd_out[412]
  PIN r0_rd_out[413]
    DIRECTION OUTPUT ;
    USE SIGNAL ;
    SHAPE ABUTMENT ;
    PORT
      LAYER met2 ;
      RECT 952.590 1688.700 952.730 1689.120 ;
    END
  END r0_rd_out[413]
  PIN r0_rd_out[414]
    DIRECTION OUTPUT ;
    USE SIGNAL ;
    SHAPE ABUTMENT ;
    PORT
      LAYER met2 ;
      RECT 954.890 1688.700 955.030 1689.120 ;
    END
  END r0_rd_out[414]
  PIN r0_rd_out[415]
    DIRECTION OUTPUT ;
    USE SIGNAL ;
    SHAPE ABUTMENT ;
    PORT
      LAYER met2 ;
      RECT 957.190 1688.700 957.330 1689.120 ;
    END
  END r0_rd_out[415]
  PIN r0_rd_out[416]
    DIRECTION OUTPUT ;
    USE SIGNAL ;
    SHAPE ABUTMENT ;
    PORT
      LAYER met2 ;
      RECT 959.490 1688.700 959.630 1689.120 ;
    END
  END r0_rd_out[416]
  PIN r0_rd_out[417]
    DIRECTION OUTPUT ;
    USE SIGNAL ;
    SHAPE ABUTMENT ;
    PORT
      LAYER met2 ;
      RECT 961.790 1688.700 961.930 1689.120 ;
    END
  END r0_rd_out[417]
  PIN r0_rd_out[418]
    DIRECTION OUTPUT ;
    USE SIGNAL ;
    SHAPE ABUTMENT ;
    PORT
      LAYER met2 ;
      RECT 964.090 1688.700 964.230 1689.120 ;
    END
  END r0_rd_out[418]
  PIN r0_rd_out[419]
    DIRECTION OUTPUT ;
    USE SIGNAL ;
    SHAPE ABUTMENT ;
    PORT
      LAYER met2 ;
      RECT 966.390 1688.700 966.530 1689.120 ;
    END
  END r0_rd_out[419]
  PIN r0_rd_out[420]
    DIRECTION OUTPUT ;
    USE SIGNAL ;
    SHAPE ABUTMENT ;
    PORT
      LAYER met2 ;
      RECT 968.690 1688.700 968.830 1689.120 ;
    END
  END r0_rd_out[420]
  PIN r0_rd_out[421]
    DIRECTION OUTPUT ;
    USE SIGNAL ;
    SHAPE ABUTMENT ;
    PORT
      LAYER met2 ;
      RECT 970.990 1688.700 971.130 1689.120 ;
    END
  END r0_rd_out[421]
  PIN r0_rd_out[422]
    DIRECTION OUTPUT ;
    USE SIGNAL ;
    SHAPE ABUTMENT ;
    PORT
      LAYER met2 ;
      RECT 973.290 1688.700 973.430 1689.120 ;
    END
  END r0_rd_out[422]
  PIN r0_rd_out[423]
    DIRECTION OUTPUT ;
    USE SIGNAL ;
    SHAPE ABUTMENT ;
    PORT
      LAYER met2 ;
      RECT 975.590 1688.700 975.730 1689.120 ;
    END
  END r0_rd_out[423]
  PIN r0_rd_out[424]
    DIRECTION OUTPUT ;
    USE SIGNAL ;
    SHAPE ABUTMENT ;
    PORT
      LAYER met2 ;
      RECT 977.890 1688.700 978.030 1689.120 ;
    END
  END r0_rd_out[424]
  PIN r0_rd_out[425]
    DIRECTION OUTPUT ;
    USE SIGNAL ;
    SHAPE ABUTMENT ;
    PORT
      LAYER met2 ;
      RECT 980.190 1688.700 980.330 1689.120 ;
    END
  END r0_rd_out[425]
  PIN r0_rd_out[426]
    DIRECTION OUTPUT ;
    USE SIGNAL ;
    SHAPE ABUTMENT ;
    PORT
      LAYER met2 ;
      RECT 982.490 1688.700 982.630 1689.120 ;
    END
  END r0_rd_out[426]
  PIN r0_rd_out[427]
    DIRECTION OUTPUT ;
    USE SIGNAL ;
    SHAPE ABUTMENT ;
    PORT
      LAYER met2 ;
      RECT 984.790 1688.700 984.930 1689.120 ;
    END
  END r0_rd_out[427]
  PIN r0_rd_out[428]
    DIRECTION OUTPUT ;
    USE SIGNAL ;
    SHAPE ABUTMENT ;
    PORT
      LAYER met2 ;
      RECT 987.090 1688.700 987.230 1689.120 ;
    END
  END r0_rd_out[428]
  PIN r0_rd_out[429]
    DIRECTION OUTPUT ;
    USE SIGNAL ;
    SHAPE ABUTMENT ;
    PORT
      LAYER met2 ;
      RECT 989.390 1688.700 989.530 1689.120 ;
    END
  END r0_rd_out[429]
  PIN r0_rd_out[430]
    DIRECTION OUTPUT ;
    USE SIGNAL ;
    SHAPE ABUTMENT ;
    PORT
      LAYER met2 ;
      RECT 991.690 1688.700 991.830 1689.120 ;
    END
  END r0_rd_out[430]
  PIN r0_rd_out[431]
    DIRECTION OUTPUT ;
    USE SIGNAL ;
    SHAPE ABUTMENT ;
    PORT
      LAYER met2 ;
      RECT 993.990 1688.700 994.130 1689.120 ;
    END
  END r0_rd_out[431]
  PIN r0_rd_out[432]
    DIRECTION OUTPUT ;
    USE SIGNAL ;
    SHAPE ABUTMENT ;
    PORT
      LAYER met2 ;
      RECT 996.290 1688.700 996.430 1689.120 ;
    END
  END r0_rd_out[432]
  PIN r0_rd_out[433]
    DIRECTION OUTPUT ;
    USE SIGNAL ;
    SHAPE ABUTMENT ;
    PORT
      LAYER met2 ;
      RECT 998.590 1688.700 998.730 1689.120 ;
    END
  END r0_rd_out[433]
  PIN r0_rd_out[434]
    DIRECTION OUTPUT ;
    USE SIGNAL ;
    SHAPE ABUTMENT ;
    PORT
      LAYER met2 ;
      RECT 1000.890 1688.700 1001.030 1689.120 ;
    END
  END r0_rd_out[434]
  PIN r0_rd_out[435]
    DIRECTION OUTPUT ;
    USE SIGNAL ;
    SHAPE ABUTMENT ;
    PORT
      LAYER met2 ;
      RECT 1003.190 1688.700 1003.330 1689.120 ;
    END
  END r0_rd_out[435]
  PIN r0_rd_out[436]
    DIRECTION OUTPUT ;
    USE SIGNAL ;
    SHAPE ABUTMENT ;
    PORT
      LAYER met2 ;
      RECT 1005.490 1688.700 1005.630 1689.120 ;
    END
  END r0_rd_out[436]
  PIN r0_rd_out[437]
    DIRECTION OUTPUT ;
    USE SIGNAL ;
    SHAPE ABUTMENT ;
    PORT
      LAYER met2 ;
      RECT 1007.790 1688.700 1007.930 1689.120 ;
    END
  END r0_rd_out[437]
  PIN r0_rd_out[438]
    DIRECTION OUTPUT ;
    USE SIGNAL ;
    SHAPE ABUTMENT ;
    PORT
      LAYER met2 ;
      RECT 1010.090 1688.700 1010.230 1689.120 ;
    END
  END r0_rd_out[438]
  PIN r0_rd_out[439]
    DIRECTION OUTPUT ;
    USE SIGNAL ;
    SHAPE ABUTMENT ;
    PORT
      LAYER met2 ;
      RECT 1012.390 1688.700 1012.530 1689.120 ;
    END
  END r0_rd_out[439]
  PIN r0_rd_out[440]
    DIRECTION OUTPUT ;
    USE SIGNAL ;
    SHAPE ABUTMENT ;
    PORT
      LAYER met2 ;
      RECT 1014.690 1688.700 1014.830 1689.120 ;
    END
  END r0_rd_out[440]
  PIN r0_rd_out[441]
    DIRECTION OUTPUT ;
    USE SIGNAL ;
    SHAPE ABUTMENT ;
    PORT
      LAYER met2 ;
      RECT 1016.990 1688.700 1017.130 1689.120 ;
    END
  END r0_rd_out[441]
  PIN r0_rd_out[442]
    DIRECTION OUTPUT ;
    USE SIGNAL ;
    SHAPE ABUTMENT ;
    PORT
      LAYER met2 ;
      RECT 1019.290 1688.700 1019.430 1689.120 ;
    END
  END r0_rd_out[442]
  PIN r0_rd_out[443]
    DIRECTION OUTPUT ;
    USE SIGNAL ;
    SHAPE ABUTMENT ;
    PORT
      LAYER met2 ;
      RECT 1021.590 1688.700 1021.730 1689.120 ;
    END
  END r0_rd_out[443]
  PIN r0_rd_out[444]
    DIRECTION OUTPUT ;
    USE SIGNAL ;
    SHAPE ABUTMENT ;
    PORT
      LAYER met2 ;
      RECT 1023.890 1688.700 1024.030 1689.120 ;
    END
  END r0_rd_out[444]
  PIN r0_rd_out[445]
    DIRECTION OUTPUT ;
    USE SIGNAL ;
    SHAPE ABUTMENT ;
    PORT
      LAYER met2 ;
      RECT 1026.190 1688.700 1026.330 1689.120 ;
    END
  END r0_rd_out[445]
  PIN r0_rd_out[446]
    DIRECTION OUTPUT ;
    USE SIGNAL ;
    SHAPE ABUTMENT ;
    PORT
      LAYER met2 ;
      RECT 1028.490 1688.700 1028.630 1689.120 ;
    END
  END r0_rd_out[446]
  PIN r0_rd_out[447]
    DIRECTION OUTPUT ;
    USE SIGNAL ;
    SHAPE ABUTMENT ;
    PORT
      LAYER met2 ;
      RECT 1030.790 1688.700 1030.930 1689.120 ;
    END
  END r0_rd_out[447]
  PIN r0_rd_out[448]
    DIRECTION OUTPUT ;
    USE SIGNAL ;
    SHAPE ABUTMENT ;
    PORT
      LAYER met2 ;
      RECT 1033.090 1688.700 1033.230 1689.120 ;
    END
  END r0_rd_out[448]
  PIN r0_rd_out[449]
    DIRECTION OUTPUT ;
    USE SIGNAL ;
    SHAPE ABUTMENT ;
    PORT
      LAYER met2 ;
      RECT 1035.390 1688.700 1035.530 1689.120 ;
    END
  END r0_rd_out[449]
  PIN r0_rd_out[450]
    DIRECTION OUTPUT ;
    USE SIGNAL ;
    SHAPE ABUTMENT ;
    PORT
      LAYER met2 ;
      RECT 1037.690 1688.700 1037.830 1689.120 ;
    END
  END r0_rd_out[450]
  PIN r0_rd_out[451]
    DIRECTION OUTPUT ;
    USE SIGNAL ;
    SHAPE ABUTMENT ;
    PORT
      LAYER met2 ;
      RECT 1039.990 1688.700 1040.130 1689.120 ;
    END
  END r0_rd_out[451]
  PIN r0_rd_out[452]
    DIRECTION OUTPUT ;
    USE SIGNAL ;
    SHAPE ABUTMENT ;
    PORT
      LAYER met2 ;
      RECT 1042.290 1688.700 1042.430 1689.120 ;
    END
  END r0_rd_out[452]
  PIN r0_rd_out[453]
    DIRECTION OUTPUT ;
    USE SIGNAL ;
    SHAPE ABUTMENT ;
    PORT
      LAYER met2 ;
      RECT 1044.590 1688.700 1044.730 1689.120 ;
    END
  END r0_rd_out[453]
  PIN r0_rd_out[454]
    DIRECTION OUTPUT ;
    USE SIGNAL ;
    SHAPE ABUTMENT ;
    PORT
      LAYER met2 ;
      RECT 1046.890 1688.700 1047.030 1689.120 ;
    END
  END r0_rd_out[454]
  PIN r0_rd_out[455]
    DIRECTION OUTPUT ;
    USE SIGNAL ;
    SHAPE ABUTMENT ;
    PORT
      LAYER met2 ;
      RECT 1049.190 1688.700 1049.330 1689.120 ;
    END
  END r0_rd_out[455]
  PIN r0_rd_out[456]
    DIRECTION OUTPUT ;
    USE SIGNAL ;
    SHAPE ABUTMENT ;
    PORT
      LAYER met2 ;
      RECT 1051.490 1688.700 1051.630 1689.120 ;
    END
  END r0_rd_out[456]
  PIN r0_rd_out[457]
    DIRECTION OUTPUT ;
    USE SIGNAL ;
    SHAPE ABUTMENT ;
    PORT
      LAYER met2 ;
      RECT 1053.790 1688.700 1053.930 1689.120 ;
    END
  END r0_rd_out[457]
  PIN r0_rd_out[458]
    DIRECTION OUTPUT ;
    USE SIGNAL ;
    SHAPE ABUTMENT ;
    PORT
      LAYER met2 ;
      RECT 1056.090 1688.700 1056.230 1689.120 ;
    END
  END r0_rd_out[458]
  PIN r0_rd_out[459]
    DIRECTION OUTPUT ;
    USE SIGNAL ;
    SHAPE ABUTMENT ;
    PORT
      LAYER met2 ;
      RECT 1058.390 1688.700 1058.530 1689.120 ;
    END
  END r0_rd_out[459]
  PIN r0_rd_out[460]
    DIRECTION OUTPUT ;
    USE SIGNAL ;
    SHAPE ABUTMENT ;
    PORT
      LAYER met2 ;
      RECT 1060.690 1688.700 1060.830 1689.120 ;
    END
  END r0_rd_out[460]
  PIN r0_rd_out[461]
    DIRECTION OUTPUT ;
    USE SIGNAL ;
    SHAPE ABUTMENT ;
    PORT
      LAYER met2 ;
      RECT 1062.990 1688.700 1063.130 1689.120 ;
    END
  END r0_rd_out[461]
  PIN r0_rd_out[462]
    DIRECTION OUTPUT ;
    USE SIGNAL ;
    SHAPE ABUTMENT ;
    PORT
      LAYER met2 ;
      RECT 1065.290 1688.700 1065.430 1689.120 ;
    END
  END r0_rd_out[462]
  PIN r0_rd_out[463]
    DIRECTION OUTPUT ;
    USE SIGNAL ;
    SHAPE ABUTMENT ;
    PORT
      LAYER met2 ;
      RECT 1067.590 1688.700 1067.730 1689.120 ;
    END
  END r0_rd_out[463]
  PIN r0_rd_out[464]
    DIRECTION OUTPUT ;
    USE SIGNAL ;
    SHAPE ABUTMENT ;
    PORT
      LAYER met2 ;
      RECT 1069.890 1688.700 1070.030 1689.120 ;
    END
  END r0_rd_out[464]
  PIN r0_rd_out[465]
    DIRECTION OUTPUT ;
    USE SIGNAL ;
    SHAPE ABUTMENT ;
    PORT
      LAYER met2 ;
      RECT 1072.190 1688.700 1072.330 1689.120 ;
    END
  END r0_rd_out[465]
  PIN r0_rd_out[466]
    DIRECTION OUTPUT ;
    USE SIGNAL ;
    SHAPE ABUTMENT ;
    PORT
      LAYER met2 ;
      RECT 1074.490 1688.700 1074.630 1689.120 ;
    END
  END r0_rd_out[466]
  PIN r0_rd_out[467]
    DIRECTION OUTPUT ;
    USE SIGNAL ;
    SHAPE ABUTMENT ;
    PORT
      LAYER met2 ;
      RECT 1076.790 1688.700 1076.930 1689.120 ;
    END
  END r0_rd_out[467]
  PIN r0_rd_out[468]
    DIRECTION OUTPUT ;
    USE SIGNAL ;
    SHAPE ABUTMENT ;
    PORT
      LAYER met2 ;
      RECT 1079.090 1688.700 1079.230 1689.120 ;
    END
  END r0_rd_out[468]
  PIN r0_rd_out[469]
    DIRECTION OUTPUT ;
    USE SIGNAL ;
    SHAPE ABUTMENT ;
    PORT
      LAYER met2 ;
      RECT 1081.390 1688.700 1081.530 1689.120 ;
    END
  END r0_rd_out[469]
  PIN r0_rd_out[470]
    DIRECTION OUTPUT ;
    USE SIGNAL ;
    SHAPE ABUTMENT ;
    PORT
      LAYER met2 ;
      RECT 1083.690 1688.700 1083.830 1689.120 ;
    END
  END r0_rd_out[470]
  PIN r0_rd_out[471]
    DIRECTION OUTPUT ;
    USE SIGNAL ;
    SHAPE ABUTMENT ;
    PORT
      LAYER met2 ;
      RECT 1085.990 1688.700 1086.130 1689.120 ;
    END
  END r0_rd_out[471]
  PIN r0_rd_out[472]
    DIRECTION OUTPUT ;
    USE SIGNAL ;
    SHAPE ABUTMENT ;
    PORT
      LAYER met2 ;
      RECT 1088.290 1688.700 1088.430 1689.120 ;
    END
  END r0_rd_out[472]
  PIN r0_rd_out[473]
    DIRECTION OUTPUT ;
    USE SIGNAL ;
    SHAPE ABUTMENT ;
    PORT
      LAYER met2 ;
      RECT 1090.590 1688.700 1090.730 1689.120 ;
    END
  END r0_rd_out[473]
  PIN r0_rd_out[474]
    DIRECTION OUTPUT ;
    USE SIGNAL ;
    SHAPE ABUTMENT ;
    PORT
      LAYER met2 ;
      RECT 1092.890 1688.700 1093.030 1689.120 ;
    END
  END r0_rd_out[474]
  PIN r0_rd_out[475]
    DIRECTION OUTPUT ;
    USE SIGNAL ;
    SHAPE ABUTMENT ;
    PORT
      LAYER met2 ;
      RECT 1095.190 1688.700 1095.330 1689.120 ;
    END
  END r0_rd_out[475]
  PIN r0_rd_out[476]
    DIRECTION OUTPUT ;
    USE SIGNAL ;
    SHAPE ABUTMENT ;
    PORT
      LAYER met2 ;
      RECT 1097.490 1688.700 1097.630 1689.120 ;
    END
  END r0_rd_out[476]
  PIN r0_rd_out[477]
    DIRECTION OUTPUT ;
    USE SIGNAL ;
    SHAPE ABUTMENT ;
    PORT
      LAYER met2 ;
      RECT 1099.790 1688.700 1099.930 1689.120 ;
    END
  END r0_rd_out[477]
  PIN r0_rd_out[478]
    DIRECTION OUTPUT ;
    USE SIGNAL ;
    SHAPE ABUTMENT ;
    PORT
      LAYER met2 ;
      RECT 1102.090 1688.700 1102.230 1689.120 ;
    END
  END r0_rd_out[478]
  PIN r0_rd_out[479]
    DIRECTION OUTPUT ;
    USE SIGNAL ;
    SHAPE ABUTMENT ;
    PORT
      LAYER met2 ;
      RECT 1104.390 1688.700 1104.530 1689.120 ;
    END
  END r0_rd_out[479]
  PIN r0_rd_out[480]
    DIRECTION OUTPUT ;
    USE SIGNAL ;
    SHAPE ABUTMENT ;
    PORT
      LAYER met2 ;
      RECT 1106.690 1688.700 1106.830 1689.120 ;
    END
  END r0_rd_out[480]
  PIN r0_rd_out[481]
    DIRECTION OUTPUT ;
    USE SIGNAL ;
    SHAPE ABUTMENT ;
    PORT
      LAYER met2 ;
      RECT 1108.990 1688.700 1109.130 1689.120 ;
    END
  END r0_rd_out[481]
  PIN r0_rd_out[482]
    DIRECTION OUTPUT ;
    USE SIGNAL ;
    SHAPE ABUTMENT ;
    PORT
      LAYER met2 ;
      RECT 1111.290 1688.700 1111.430 1689.120 ;
    END
  END r0_rd_out[482]
  PIN r0_rd_out[483]
    DIRECTION OUTPUT ;
    USE SIGNAL ;
    SHAPE ABUTMENT ;
    PORT
      LAYER met2 ;
      RECT 1113.590 1688.700 1113.730 1689.120 ;
    END
  END r0_rd_out[483]
  PIN r0_rd_out[484]
    DIRECTION OUTPUT ;
    USE SIGNAL ;
    SHAPE ABUTMENT ;
    PORT
      LAYER met2 ;
      RECT 1115.890 1688.700 1116.030 1689.120 ;
    END
  END r0_rd_out[484]
  PIN r0_rd_out[485]
    DIRECTION OUTPUT ;
    USE SIGNAL ;
    SHAPE ABUTMENT ;
    PORT
      LAYER met2 ;
      RECT 1118.190 1688.700 1118.330 1689.120 ;
    END
  END r0_rd_out[485]
  PIN r0_rd_out[486]
    DIRECTION OUTPUT ;
    USE SIGNAL ;
    SHAPE ABUTMENT ;
    PORT
      LAYER met2 ;
      RECT 1120.490 1688.700 1120.630 1689.120 ;
    END
  END r0_rd_out[486]
  PIN r0_rd_out[487]
    DIRECTION OUTPUT ;
    USE SIGNAL ;
    SHAPE ABUTMENT ;
    PORT
      LAYER met2 ;
      RECT 1122.790 1688.700 1122.930 1689.120 ;
    END
  END r0_rd_out[487]
  PIN r0_rd_out[488]
    DIRECTION OUTPUT ;
    USE SIGNAL ;
    SHAPE ABUTMENT ;
    PORT
      LAYER met2 ;
      RECT 1125.090 1688.700 1125.230 1689.120 ;
    END
  END r0_rd_out[488]
  PIN r0_rd_out[489]
    DIRECTION OUTPUT ;
    USE SIGNAL ;
    SHAPE ABUTMENT ;
    PORT
      LAYER met2 ;
      RECT 1127.390 1688.700 1127.530 1689.120 ;
    END
  END r0_rd_out[489]
  PIN r0_rd_out[490]
    DIRECTION OUTPUT ;
    USE SIGNAL ;
    SHAPE ABUTMENT ;
    PORT
      LAYER met2 ;
      RECT 1129.690 1688.700 1129.830 1689.120 ;
    END
  END r0_rd_out[490]
  PIN r0_rd_out[491]
    DIRECTION OUTPUT ;
    USE SIGNAL ;
    SHAPE ABUTMENT ;
    PORT
      LAYER met2 ;
      RECT 1131.990 1688.700 1132.130 1689.120 ;
    END
  END r0_rd_out[491]
  PIN r0_rd_out[492]
    DIRECTION OUTPUT ;
    USE SIGNAL ;
    SHAPE ABUTMENT ;
    PORT
      LAYER met2 ;
      RECT 1134.290 1688.700 1134.430 1689.120 ;
    END
  END r0_rd_out[492]
  PIN r0_rd_out[493]
    DIRECTION OUTPUT ;
    USE SIGNAL ;
    SHAPE ABUTMENT ;
    PORT
      LAYER met2 ;
      RECT 1136.590 1688.700 1136.730 1689.120 ;
    END
  END r0_rd_out[493]
  PIN r0_rd_out[494]
    DIRECTION OUTPUT ;
    USE SIGNAL ;
    SHAPE ABUTMENT ;
    PORT
      LAYER met2 ;
      RECT 1138.890 1688.700 1139.030 1689.120 ;
    END
  END r0_rd_out[494]
  PIN r0_rd_out[495]
    DIRECTION OUTPUT ;
    USE SIGNAL ;
    SHAPE ABUTMENT ;
    PORT
      LAYER met2 ;
      RECT 1141.190 1688.700 1141.330 1689.120 ;
    END
  END r0_rd_out[495]
  PIN r0_rd_out[496]
    DIRECTION OUTPUT ;
    USE SIGNAL ;
    SHAPE ABUTMENT ;
    PORT
      LAYER met2 ;
      RECT 1143.490 1688.700 1143.630 1689.120 ;
    END
  END r0_rd_out[496]
  PIN r0_rd_out[497]
    DIRECTION OUTPUT ;
    USE SIGNAL ;
    SHAPE ABUTMENT ;
    PORT
      LAYER met2 ;
      RECT 1145.790 1688.700 1145.930 1689.120 ;
    END
  END r0_rd_out[497]
  PIN r0_rd_out[498]
    DIRECTION OUTPUT ;
    USE SIGNAL ;
    SHAPE ABUTMENT ;
    PORT
      LAYER met2 ;
      RECT 1148.090 1688.700 1148.230 1689.120 ;
    END
  END r0_rd_out[498]
  PIN r0_rd_out[499]
    DIRECTION OUTPUT ;
    USE SIGNAL ;
    SHAPE ABUTMENT ;
    PORT
      LAYER met2 ;
      RECT 1150.390 1688.700 1150.530 1689.120 ;
    END
  END r0_rd_out[499]
  PIN r0_rd_out[500]
    DIRECTION OUTPUT ;
    USE SIGNAL ;
    SHAPE ABUTMENT ;
    PORT
      LAYER met2 ;
      RECT 1152.690 1688.700 1152.830 1689.120 ;
    END
  END r0_rd_out[500]
  PIN r0_rd_out[501]
    DIRECTION OUTPUT ;
    USE SIGNAL ;
    SHAPE ABUTMENT ;
    PORT
      LAYER met2 ;
      RECT 1154.990 1688.700 1155.130 1689.120 ;
    END
  END r0_rd_out[501]
  PIN r0_rd_out[502]
    DIRECTION OUTPUT ;
    USE SIGNAL ;
    SHAPE ABUTMENT ;
    PORT
      LAYER met2 ;
      RECT 1157.290 1688.700 1157.430 1689.120 ;
    END
  END r0_rd_out[502]
  PIN r0_rd_out[503]
    DIRECTION OUTPUT ;
    USE SIGNAL ;
    SHAPE ABUTMENT ;
    PORT
      LAYER met2 ;
      RECT 1159.590 1688.700 1159.730 1689.120 ;
    END
  END r0_rd_out[503]
  PIN r0_rd_out[504]
    DIRECTION OUTPUT ;
    USE SIGNAL ;
    SHAPE ABUTMENT ;
    PORT
      LAYER met2 ;
      RECT 1161.890 1688.700 1162.030 1689.120 ;
    END
  END r0_rd_out[504]
  PIN r0_rd_out[505]
    DIRECTION OUTPUT ;
    USE SIGNAL ;
    SHAPE ABUTMENT ;
    PORT
      LAYER met2 ;
      RECT 1164.190 1688.700 1164.330 1689.120 ;
    END
  END r0_rd_out[505]
  PIN r0_rd_out[506]
    DIRECTION OUTPUT ;
    USE SIGNAL ;
    SHAPE ABUTMENT ;
    PORT
      LAYER met2 ;
      RECT 1166.490 1688.700 1166.630 1689.120 ;
    END
  END r0_rd_out[506]
  PIN r0_rd_out[507]
    DIRECTION OUTPUT ;
    USE SIGNAL ;
    SHAPE ABUTMENT ;
    PORT
      LAYER met2 ;
      RECT 1168.790 1688.700 1168.930 1689.120 ;
    END
  END r0_rd_out[507]
  PIN r0_rd_out[508]
    DIRECTION OUTPUT ;
    USE SIGNAL ;
    SHAPE ABUTMENT ;
    PORT
      LAYER met2 ;
      RECT 1171.090 1688.700 1171.230 1689.120 ;
    END
  END r0_rd_out[508]
  PIN r0_rd_out[509]
    DIRECTION OUTPUT ;
    USE SIGNAL ;
    SHAPE ABUTMENT ;
    PORT
      LAYER met2 ;
      RECT 1173.390 1688.700 1173.530 1689.120 ;
    END
  END r0_rd_out[509]
  PIN r0_rd_out[510]
    DIRECTION OUTPUT ;
    USE SIGNAL ;
    SHAPE ABUTMENT ;
    PORT
      LAYER met2 ;
      RECT 1175.690 1688.700 1175.830 1689.120 ;
    END
  END r0_rd_out[510]
  PIN r0_rd_out[511]
    DIRECTION OUTPUT ;
    USE SIGNAL ;
    SHAPE ABUTMENT ;
    PORT
      LAYER met2 ;
      RECT 1177.990 1688.700 1178.130 1689.120 ;
    END
  END r0_rd_out[511]
  PIN r0_rd_out[512]
    DIRECTION OUTPUT ;
    USE SIGNAL ;
    SHAPE ABUTMENT ;
    PORT
      LAYER met2 ;
      RECT 1180.290 1688.700 1180.430 1689.120 ;
    END
  END r0_rd_out[512]
  PIN r0_rd_out[513]
    DIRECTION OUTPUT ;
    USE SIGNAL ;
    SHAPE ABUTMENT ;
    PORT
      LAYER met2 ;
      RECT 1182.590 1688.700 1182.730 1689.120 ;
    END
  END r0_rd_out[513]
  PIN r0_rd_out[514]
    DIRECTION OUTPUT ;
    USE SIGNAL ;
    SHAPE ABUTMENT ;
    PORT
      LAYER met2 ;
      RECT 1184.890 1688.700 1185.030 1689.120 ;
    END
  END r0_rd_out[514]
  PIN r0_rd_out[515]
    DIRECTION OUTPUT ;
    USE SIGNAL ;
    SHAPE ABUTMENT ;
    PORT
      LAYER met2 ;
      RECT 1187.190 1688.700 1187.330 1689.120 ;
    END
  END r0_rd_out[515]
  PIN r0_rd_out[516]
    DIRECTION OUTPUT ;
    USE SIGNAL ;
    SHAPE ABUTMENT ;
    PORT
      LAYER met2 ;
      RECT 1189.490 1688.700 1189.630 1689.120 ;
    END
  END r0_rd_out[516]
  PIN r0_rd_out[517]
    DIRECTION OUTPUT ;
    USE SIGNAL ;
    SHAPE ABUTMENT ;
    PORT
      LAYER met2 ;
      RECT 1191.790 1688.700 1191.930 1689.120 ;
    END
  END r0_rd_out[517]
  PIN r0_rd_out[518]
    DIRECTION OUTPUT ;
    USE SIGNAL ;
    SHAPE ABUTMENT ;
    PORT
      LAYER met2 ;
      RECT 1194.090 1688.700 1194.230 1689.120 ;
    END
  END r0_rd_out[518]
  PIN r0_rd_out[519]
    DIRECTION OUTPUT ;
    USE SIGNAL ;
    SHAPE ABUTMENT ;
    PORT
      LAYER met2 ;
      RECT 1196.390 1688.700 1196.530 1689.120 ;
    END
  END r0_rd_out[519]
  PIN r0_rd_out[520]
    DIRECTION OUTPUT ;
    USE SIGNAL ;
    SHAPE ABUTMENT ;
    PORT
      LAYER met2 ;
      RECT 1198.690 1688.700 1198.830 1689.120 ;
    END
  END r0_rd_out[520]
  PIN r0_rd_out[521]
    DIRECTION OUTPUT ;
    USE SIGNAL ;
    SHAPE ABUTMENT ;
    PORT
      LAYER met2 ;
      RECT 1200.990 1688.700 1201.130 1689.120 ;
    END
  END r0_rd_out[521]
  PIN r0_rd_out[522]
    DIRECTION OUTPUT ;
    USE SIGNAL ;
    SHAPE ABUTMENT ;
    PORT
      LAYER met2 ;
      RECT 1203.290 1688.700 1203.430 1689.120 ;
    END
  END r0_rd_out[522]
  PIN r0_rd_out[523]
    DIRECTION OUTPUT ;
    USE SIGNAL ;
    SHAPE ABUTMENT ;
    PORT
      LAYER met2 ;
      RECT 1205.590 1688.700 1205.730 1689.120 ;
    END
  END r0_rd_out[523]
  PIN r0_rd_out[524]
    DIRECTION OUTPUT ;
    USE SIGNAL ;
    SHAPE ABUTMENT ;
    PORT
      LAYER met2 ;
      RECT 1207.890 1688.700 1208.030 1689.120 ;
    END
  END r0_rd_out[524]
  PIN r0_rd_out[525]
    DIRECTION OUTPUT ;
    USE SIGNAL ;
    SHAPE ABUTMENT ;
    PORT
      LAYER met2 ;
      RECT 1210.190 1688.700 1210.330 1689.120 ;
    END
  END r0_rd_out[525]
  PIN r0_rd_out[526]
    DIRECTION OUTPUT ;
    USE SIGNAL ;
    SHAPE ABUTMENT ;
    PORT
      LAYER met2 ;
      RECT 1212.490 1688.700 1212.630 1689.120 ;
    END
  END r0_rd_out[526]
  PIN r0_rd_out[527]
    DIRECTION OUTPUT ;
    USE SIGNAL ;
    SHAPE ABUTMENT ;
    PORT
      LAYER met2 ;
      RECT 1214.790 1688.700 1214.930 1689.120 ;
    END
  END r0_rd_out[527]
  PIN r0_rd_out[528]
    DIRECTION OUTPUT ;
    USE SIGNAL ;
    SHAPE ABUTMENT ;
    PORT
      LAYER met2 ;
      RECT 1217.090 1688.700 1217.230 1689.120 ;
    END
  END r0_rd_out[528]
  PIN r0_rd_out[529]
    DIRECTION OUTPUT ;
    USE SIGNAL ;
    SHAPE ABUTMENT ;
    PORT
      LAYER met2 ;
      RECT 1219.390 1688.700 1219.530 1689.120 ;
    END
  END r0_rd_out[529]
  PIN r0_rd_out[530]
    DIRECTION OUTPUT ;
    USE SIGNAL ;
    SHAPE ABUTMENT ;
    PORT
      LAYER met2 ;
      RECT 1221.690 1688.700 1221.830 1689.120 ;
    END
  END r0_rd_out[530]
  PIN r0_rd_out[531]
    DIRECTION OUTPUT ;
    USE SIGNAL ;
    SHAPE ABUTMENT ;
    PORT
      LAYER met2 ;
      RECT 1223.990 1688.700 1224.130 1689.120 ;
    END
  END r0_rd_out[531]
  PIN r0_rd_out[532]
    DIRECTION OUTPUT ;
    USE SIGNAL ;
    SHAPE ABUTMENT ;
    PORT
      LAYER met2 ;
      RECT 1226.290 1688.700 1226.430 1689.120 ;
    END
  END r0_rd_out[532]
  PIN r0_rd_out[533]
    DIRECTION OUTPUT ;
    USE SIGNAL ;
    SHAPE ABUTMENT ;
    PORT
      LAYER met2 ;
      RECT 1228.590 1688.700 1228.730 1689.120 ;
    END
  END r0_rd_out[533]
  PIN r0_rd_out[534]
    DIRECTION OUTPUT ;
    USE SIGNAL ;
    SHAPE ABUTMENT ;
    PORT
      LAYER met2 ;
      RECT 1230.890 1688.700 1231.030 1689.120 ;
    END
  END r0_rd_out[534]
  PIN r0_rd_out[535]
    DIRECTION OUTPUT ;
    USE SIGNAL ;
    SHAPE ABUTMENT ;
    PORT
      LAYER met2 ;
      RECT 1233.190 1688.700 1233.330 1689.120 ;
    END
  END r0_rd_out[535]
  PIN r0_rd_out[536]
    DIRECTION OUTPUT ;
    USE SIGNAL ;
    SHAPE ABUTMENT ;
    PORT
      LAYER met2 ;
      RECT 1235.490 1688.700 1235.630 1689.120 ;
    END
  END r0_rd_out[536]
  PIN r0_rd_out[537]
    DIRECTION OUTPUT ;
    USE SIGNAL ;
    SHAPE ABUTMENT ;
    PORT
      LAYER met2 ;
      RECT 1237.790 1688.700 1237.930 1689.120 ;
    END
  END r0_rd_out[537]
  PIN r0_rd_out[538]
    DIRECTION OUTPUT ;
    USE SIGNAL ;
    SHAPE ABUTMENT ;
    PORT
      LAYER met2 ;
      RECT 1240.090 1688.700 1240.230 1689.120 ;
    END
  END r0_rd_out[538]
  PIN r0_rd_out[539]
    DIRECTION OUTPUT ;
    USE SIGNAL ;
    SHAPE ABUTMENT ;
    PORT
      LAYER met2 ;
      RECT 1242.390 1688.700 1242.530 1689.120 ;
    END
  END r0_rd_out[539]
  PIN r0_rd_out[540]
    DIRECTION OUTPUT ;
    USE SIGNAL ;
    SHAPE ABUTMENT ;
    PORT
      LAYER met2 ;
      RECT 1244.690 1688.700 1244.830 1689.120 ;
    END
  END r0_rd_out[540]
  PIN r0_rd_out[541]
    DIRECTION OUTPUT ;
    USE SIGNAL ;
    SHAPE ABUTMENT ;
    PORT
      LAYER met2 ;
      RECT 1246.990 1688.700 1247.130 1689.120 ;
    END
  END r0_rd_out[541]
  PIN r0_rd_out[542]
    DIRECTION OUTPUT ;
    USE SIGNAL ;
    SHAPE ABUTMENT ;
    PORT
      LAYER met2 ;
      RECT 1249.290 1688.700 1249.430 1689.120 ;
    END
  END r0_rd_out[542]
  PIN r0_rd_out[543]
    DIRECTION OUTPUT ;
    USE SIGNAL ;
    SHAPE ABUTMENT ;
    PORT
      LAYER met2 ;
      RECT 1251.590 1688.700 1251.730 1689.120 ;
    END
  END r0_rd_out[543]
  PIN r0_rd_out[544]
    DIRECTION OUTPUT ;
    USE SIGNAL ;
    SHAPE ABUTMENT ;
    PORT
      LAYER met2 ;
      RECT 1253.890 1688.700 1254.030 1689.120 ;
    END
  END r0_rd_out[544]
  PIN r0_rd_out[545]
    DIRECTION OUTPUT ;
    USE SIGNAL ;
    SHAPE ABUTMENT ;
    PORT
      LAYER met2 ;
      RECT 1256.190 1688.700 1256.330 1689.120 ;
    END
  END r0_rd_out[545]
  PIN r0_rd_out[546]
    DIRECTION OUTPUT ;
    USE SIGNAL ;
    SHAPE ABUTMENT ;
    PORT
      LAYER met2 ;
      RECT 1258.490 1688.700 1258.630 1689.120 ;
    END
  END r0_rd_out[546]
  PIN r0_rd_out[547]
    DIRECTION OUTPUT ;
    USE SIGNAL ;
    SHAPE ABUTMENT ;
    PORT
      LAYER met2 ;
      RECT 1260.790 1688.700 1260.930 1689.120 ;
    END
  END r0_rd_out[547]
  PIN r0_rd_out[548]
    DIRECTION OUTPUT ;
    USE SIGNAL ;
    SHAPE ABUTMENT ;
    PORT
      LAYER met2 ;
      RECT 1263.090 1688.700 1263.230 1689.120 ;
    END
  END r0_rd_out[548]
  PIN r0_rd_out[549]
    DIRECTION OUTPUT ;
    USE SIGNAL ;
    SHAPE ABUTMENT ;
    PORT
      LAYER met2 ;
      RECT 1265.390 1688.700 1265.530 1689.120 ;
    END
  END r0_rd_out[549]
  PIN r0_rd_out[550]
    DIRECTION OUTPUT ;
    USE SIGNAL ;
    SHAPE ABUTMENT ;
    PORT
      LAYER met2 ;
      RECT 1267.690 1688.700 1267.830 1689.120 ;
    END
  END r0_rd_out[550]
  PIN r0_rd_out[551]
    DIRECTION OUTPUT ;
    USE SIGNAL ;
    SHAPE ABUTMENT ;
    PORT
      LAYER met2 ;
      RECT 1269.990 1688.700 1270.130 1689.120 ;
    END
  END r0_rd_out[551]
  PIN r0_rd_out[552]
    DIRECTION OUTPUT ;
    USE SIGNAL ;
    SHAPE ABUTMENT ;
    PORT
      LAYER met2 ;
      RECT 1272.290 1688.700 1272.430 1689.120 ;
    END
  END r0_rd_out[552]
  PIN r0_rd_out[553]
    DIRECTION OUTPUT ;
    USE SIGNAL ;
    SHAPE ABUTMENT ;
    PORT
      LAYER met2 ;
      RECT 1274.590 1688.700 1274.730 1689.120 ;
    END
  END r0_rd_out[553]
  PIN r0_rd_out[554]
    DIRECTION OUTPUT ;
    USE SIGNAL ;
    SHAPE ABUTMENT ;
    PORT
      LAYER met2 ;
      RECT 1276.890 1688.700 1277.030 1689.120 ;
    END
  END r0_rd_out[554]
  PIN r0_rd_out[555]
    DIRECTION OUTPUT ;
    USE SIGNAL ;
    SHAPE ABUTMENT ;
    PORT
      LAYER met2 ;
      RECT 1279.190 1688.700 1279.330 1689.120 ;
    END
  END r0_rd_out[555]
  PIN r0_rd_out[556]
    DIRECTION OUTPUT ;
    USE SIGNAL ;
    SHAPE ABUTMENT ;
    PORT
      LAYER met2 ;
      RECT 1281.490 1688.700 1281.630 1689.120 ;
    END
  END r0_rd_out[556]
  PIN r0_rd_out[557]
    DIRECTION OUTPUT ;
    USE SIGNAL ;
    SHAPE ABUTMENT ;
    PORT
      LAYER met2 ;
      RECT 1283.790 1688.700 1283.930 1689.120 ;
    END
  END r0_rd_out[557]
  PIN r0_rd_out[558]
    DIRECTION OUTPUT ;
    USE SIGNAL ;
    SHAPE ABUTMENT ;
    PORT
      LAYER met2 ;
      RECT 1286.090 1688.700 1286.230 1689.120 ;
    END
  END r0_rd_out[558]
  PIN r0_rd_out[559]
    DIRECTION OUTPUT ;
    USE SIGNAL ;
    SHAPE ABUTMENT ;
    PORT
      LAYER met2 ;
      RECT 1288.390 1688.700 1288.530 1689.120 ;
    END
  END r0_rd_out[559]
  PIN r0_rd_out[560]
    DIRECTION OUTPUT ;
    USE SIGNAL ;
    SHAPE ABUTMENT ;
    PORT
      LAYER met2 ;
      RECT 1290.690 1688.700 1290.830 1689.120 ;
    END
  END r0_rd_out[560]
  PIN r0_rd_out[561]
    DIRECTION OUTPUT ;
    USE SIGNAL ;
    SHAPE ABUTMENT ;
    PORT
      LAYER met2 ;
      RECT 1292.990 1688.700 1293.130 1689.120 ;
    END
  END r0_rd_out[561]
  PIN r0_rd_out[562]
    DIRECTION OUTPUT ;
    USE SIGNAL ;
    SHAPE ABUTMENT ;
    PORT
      LAYER met2 ;
      RECT 1295.290 1688.700 1295.430 1689.120 ;
    END
  END r0_rd_out[562]
  PIN r0_rd_out[563]
    DIRECTION OUTPUT ;
    USE SIGNAL ;
    SHAPE ABUTMENT ;
    PORT
      LAYER met2 ;
      RECT 1297.590 1688.700 1297.730 1689.120 ;
    END
  END r0_rd_out[563]
  PIN r0_rd_out[564]
    DIRECTION OUTPUT ;
    USE SIGNAL ;
    SHAPE ABUTMENT ;
    PORT
      LAYER met2 ;
      RECT 1299.890 1688.700 1300.030 1689.120 ;
    END
  END r0_rd_out[564]
  PIN r0_rd_out[565]
    DIRECTION OUTPUT ;
    USE SIGNAL ;
    SHAPE ABUTMENT ;
    PORT
      LAYER met2 ;
      RECT 1302.190 1688.700 1302.330 1689.120 ;
    END
  END r0_rd_out[565]
  PIN r0_rd_out[566]
    DIRECTION OUTPUT ;
    USE SIGNAL ;
    SHAPE ABUTMENT ;
    PORT
      LAYER met2 ;
      RECT 1304.490 1688.700 1304.630 1689.120 ;
    END
  END r0_rd_out[566]
  PIN r0_rd_out[567]
    DIRECTION OUTPUT ;
    USE SIGNAL ;
    SHAPE ABUTMENT ;
    PORT
      LAYER met2 ;
      RECT 1306.790 1688.700 1306.930 1689.120 ;
    END
  END r0_rd_out[567]
  PIN r0_rd_out[568]
    DIRECTION OUTPUT ;
    USE SIGNAL ;
    SHAPE ABUTMENT ;
    PORT
      LAYER met2 ;
      RECT 1309.090 1688.700 1309.230 1689.120 ;
    END
  END r0_rd_out[568]
  PIN r0_rd_out[569]
    DIRECTION OUTPUT ;
    USE SIGNAL ;
    SHAPE ABUTMENT ;
    PORT
      LAYER met2 ;
      RECT 1311.390 1688.700 1311.530 1689.120 ;
    END
  END r0_rd_out[569]
  PIN r0_rd_out[570]
    DIRECTION OUTPUT ;
    USE SIGNAL ;
    SHAPE ABUTMENT ;
    PORT
      LAYER met2 ;
      RECT 1313.690 1688.700 1313.830 1689.120 ;
    END
  END r0_rd_out[570]
  PIN r0_rd_out[571]
    DIRECTION OUTPUT ;
    USE SIGNAL ;
    SHAPE ABUTMENT ;
    PORT
      LAYER met2 ;
      RECT 1315.990 1688.700 1316.130 1689.120 ;
    END
  END r0_rd_out[571]
  PIN r0_rd_out[572]
    DIRECTION OUTPUT ;
    USE SIGNAL ;
    SHAPE ABUTMENT ;
    PORT
      LAYER met2 ;
      RECT 1318.290 1688.700 1318.430 1689.120 ;
    END
  END r0_rd_out[572]
  PIN r0_rd_out[573]
    DIRECTION OUTPUT ;
    USE SIGNAL ;
    SHAPE ABUTMENT ;
    PORT
      LAYER met2 ;
      RECT 1320.590 1688.700 1320.730 1689.120 ;
    END
  END r0_rd_out[573]
  PIN r0_rd_out[574]
    DIRECTION OUTPUT ;
    USE SIGNAL ;
    SHAPE ABUTMENT ;
    PORT
      LAYER met2 ;
      RECT 1322.890 1688.700 1323.030 1689.120 ;
    END
  END r0_rd_out[574]
  PIN r0_rd_out[575]
    DIRECTION OUTPUT ;
    USE SIGNAL ;
    SHAPE ABUTMENT ;
    PORT
      LAYER met2 ;
      RECT 1325.190 1688.700 1325.330 1689.120 ;
    END
  END r0_rd_out[575]
  PIN r0_rd_out[576]
    DIRECTION OUTPUT ;
    USE SIGNAL ;
    SHAPE ABUTMENT ;
    PORT
      LAYER met2 ;
      RECT 1327.490 1688.700 1327.630 1689.120 ;
    END
  END r0_rd_out[576]
  PIN r0_rd_out[577]
    DIRECTION OUTPUT ;
    USE SIGNAL ;
    SHAPE ABUTMENT ;
    PORT
      LAYER met2 ;
      RECT 1329.790 1688.700 1329.930 1689.120 ;
    END
  END r0_rd_out[577]
  PIN r0_rd_out[578]
    DIRECTION OUTPUT ;
    USE SIGNAL ;
    SHAPE ABUTMENT ;
    PORT
      LAYER met2 ;
      RECT 1332.090 1688.700 1332.230 1689.120 ;
    END
  END r0_rd_out[578]
  PIN r0_rd_out[579]
    DIRECTION OUTPUT ;
    USE SIGNAL ;
    SHAPE ABUTMENT ;
    PORT
      LAYER met2 ;
      RECT 1334.390 1688.700 1334.530 1689.120 ;
    END
  END r0_rd_out[579]
  PIN r0_rd_out[580]
    DIRECTION OUTPUT ;
    USE SIGNAL ;
    SHAPE ABUTMENT ;
    PORT
      LAYER met2 ;
      RECT 1336.690 1688.700 1336.830 1689.120 ;
    END
  END r0_rd_out[580]
  PIN r0_rd_out[581]
    DIRECTION OUTPUT ;
    USE SIGNAL ;
    SHAPE ABUTMENT ;
    PORT
      LAYER met2 ;
      RECT 1338.990 1688.700 1339.130 1689.120 ;
    END
  END r0_rd_out[581]
  PIN r0_rd_out[582]
    DIRECTION OUTPUT ;
    USE SIGNAL ;
    SHAPE ABUTMENT ;
    PORT
      LAYER met2 ;
      RECT 1341.290 1688.700 1341.430 1689.120 ;
    END
  END r0_rd_out[582]
  PIN r0_rd_out[583]
    DIRECTION OUTPUT ;
    USE SIGNAL ;
    SHAPE ABUTMENT ;
    PORT
      LAYER met2 ;
      RECT 1343.590 1688.700 1343.730 1689.120 ;
    END
  END r0_rd_out[583]
  PIN r0_rd_out[584]
    DIRECTION OUTPUT ;
    USE SIGNAL ;
    SHAPE ABUTMENT ;
    PORT
      LAYER met2 ;
      RECT 1345.890 1688.700 1346.030 1689.120 ;
    END
  END r0_rd_out[584]
  PIN r0_rd_out[585]
    DIRECTION OUTPUT ;
    USE SIGNAL ;
    SHAPE ABUTMENT ;
    PORT
      LAYER met2 ;
      RECT 1348.190 1688.700 1348.330 1689.120 ;
    END
  END r0_rd_out[585]
  PIN r0_rd_out[586]
    DIRECTION OUTPUT ;
    USE SIGNAL ;
    SHAPE ABUTMENT ;
    PORT
      LAYER met2 ;
      RECT 1350.490 1688.700 1350.630 1689.120 ;
    END
  END r0_rd_out[586]
  PIN r0_rd_out[587]
    DIRECTION OUTPUT ;
    USE SIGNAL ;
    SHAPE ABUTMENT ;
    PORT
      LAYER met2 ;
      RECT 1352.790 1688.700 1352.930 1689.120 ;
    END
  END r0_rd_out[587]
  PIN r0_rd_out[588]
    DIRECTION OUTPUT ;
    USE SIGNAL ;
    SHAPE ABUTMENT ;
    PORT
      LAYER met2 ;
      RECT 1355.090 1688.700 1355.230 1689.120 ;
    END
  END r0_rd_out[588]
  PIN r0_rd_out[589]
    DIRECTION OUTPUT ;
    USE SIGNAL ;
    SHAPE ABUTMENT ;
    PORT
      LAYER met2 ;
      RECT 1357.390 1688.700 1357.530 1689.120 ;
    END
  END r0_rd_out[589]
  PIN r0_rd_out[590]
    DIRECTION OUTPUT ;
    USE SIGNAL ;
    SHAPE ABUTMENT ;
    PORT
      LAYER met2 ;
      RECT 1359.690 1688.700 1359.830 1689.120 ;
    END
  END r0_rd_out[590]
  PIN r0_rd_out[591]
    DIRECTION OUTPUT ;
    USE SIGNAL ;
    SHAPE ABUTMENT ;
    PORT
      LAYER met2 ;
      RECT 1361.990 1688.700 1362.130 1689.120 ;
    END
  END r0_rd_out[591]
  PIN r0_rd_out[592]
    DIRECTION OUTPUT ;
    USE SIGNAL ;
    SHAPE ABUTMENT ;
    PORT
      LAYER met2 ;
      RECT 1364.290 1688.700 1364.430 1689.120 ;
    END
  END r0_rd_out[592]
  PIN r0_rd_out[593]
    DIRECTION OUTPUT ;
    USE SIGNAL ;
    SHAPE ABUTMENT ;
    PORT
      LAYER met2 ;
      RECT 1366.590 1688.700 1366.730 1689.120 ;
    END
  END r0_rd_out[593]
  PIN r0_rd_out[594]
    DIRECTION OUTPUT ;
    USE SIGNAL ;
    SHAPE ABUTMENT ;
    PORT
      LAYER met2 ;
      RECT 1368.890 1688.700 1369.030 1689.120 ;
    END
  END r0_rd_out[594]
  PIN r0_rd_out[595]
    DIRECTION OUTPUT ;
    USE SIGNAL ;
    SHAPE ABUTMENT ;
    PORT
      LAYER met2 ;
      RECT 1371.190 1688.700 1371.330 1689.120 ;
    END
  END r0_rd_out[595]
  PIN r0_rd_out[596]
    DIRECTION OUTPUT ;
    USE SIGNAL ;
    SHAPE ABUTMENT ;
    PORT
      LAYER met2 ;
      RECT 1373.490 1688.700 1373.630 1689.120 ;
    END
  END r0_rd_out[596]
  PIN r0_rd_out[597]
    DIRECTION OUTPUT ;
    USE SIGNAL ;
    SHAPE ABUTMENT ;
    PORT
      LAYER met2 ;
      RECT 1375.790 1688.700 1375.930 1689.120 ;
    END
  END r0_rd_out[597]
  PIN r0_rd_out[598]
    DIRECTION OUTPUT ;
    USE SIGNAL ;
    SHAPE ABUTMENT ;
    PORT
      LAYER met2 ;
      RECT 1378.090 1688.700 1378.230 1689.120 ;
    END
  END r0_rd_out[598]
  PIN r0_rd_out[599]
    DIRECTION OUTPUT ;
    USE SIGNAL ;
    SHAPE ABUTMENT ;
    PORT
      LAYER met2 ;
      RECT 1380.390 1688.700 1380.530 1689.120 ;
    END
  END r0_rd_out[599]
  PIN r0_rd_out[600]
    DIRECTION OUTPUT ;
    USE SIGNAL ;
    SHAPE ABUTMENT ;
    PORT
      LAYER met2 ;
      RECT 1382.690 1688.700 1382.830 1689.120 ;
    END
  END r0_rd_out[600]
  PIN r0_rd_out[601]
    DIRECTION OUTPUT ;
    USE SIGNAL ;
    SHAPE ABUTMENT ;
    PORT
      LAYER met2 ;
      RECT 1384.990 1688.700 1385.130 1689.120 ;
    END
  END r0_rd_out[601]
  PIN r0_rd_out[602]
    DIRECTION OUTPUT ;
    USE SIGNAL ;
    SHAPE ABUTMENT ;
    PORT
      LAYER met2 ;
      RECT 1387.290 1688.700 1387.430 1689.120 ;
    END
  END r0_rd_out[602]
  PIN r0_rd_out[603]
    DIRECTION OUTPUT ;
    USE SIGNAL ;
    SHAPE ABUTMENT ;
    PORT
      LAYER met2 ;
      RECT 1389.590 1688.700 1389.730 1689.120 ;
    END
  END r0_rd_out[603]
  PIN r0_rd_out[604]
    DIRECTION OUTPUT ;
    USE SIGNAL ;
    SHAPE ABUTMENT ;
    PORT
      LAYER met2 ;
      RECT 1391.890 1688.700 1392.030 1689.120 ;
    END
  END r0_rd_out[604]
  PIN r0_rd_out[605]
    DIRECTION OUTPUT ;
    USE SIGNAL ;
    SHAPE ABUTMENT ;
    PORT
      LAYER met2 ;
      RECT 1394.190 1688.700 1394.330 1689.120 ;
    END
  END r0_rd_out[605]
  PIN r0_rd_out[606]
    DIRECTION OUTPUT ;
    USE SIGNAL ;
    SHAPE ABUTMENT ;
    PORT
      LAYER met2 ;
      RECT 1396.490 1688.700 1396.630 1689.120 ;
    END
  END r0_rd_out[606]
  PIN r0_rd_out[607]
    DIRECTION OUTPUT ;
    USE SIGNAL ;
    SHAPE ABUTMENT ;
    PORT
      LAYER met2 ;
      RECT 1398.790 1688.700 1398.930 1689.120 ;
    END
  END r0_rd_out[607]
  PIN r0_rd_out[608]
    DIRECTION OUTPUT ;
    USE SIGNAL ;
    SHAPE ABUTMENT ;
    PORT
      LAYER met2 ;
      RECT 1401.090 1688.700 1401.230 1689.120 ;
    END
  END r0_rd_out[608]
  PIN r0_rd_out[609]
    DIRECTION OUTPUT ;
    USE SIGNAL ;
    SHAPE ABUTMENT ;
    PORT
      LAYER met2 ;
      RECT 1403.390 1688.700 1403.530 1689.120 ;
    END
  END r0_rd_out[609]
  PIN r0_rd_out[610]
    DIRECTION OUTPUT ;
    USE SIGNAL ;
    SHAPE ABUTMENT ;
    PORT
      LAYER met2 ;
      RECT 1405.690 1688.700 1405.830 1689.120 ;
    END
  END r0_rd_out[610]
  PIN r0_rd_out[611]
    DIRECTION OUTPUT ;
    USE SIGNAL ;
    SHAPE ABUTMENT ;
    PORT
      LAYER met2 ;
      RECT 1407.990 1688.700 1408.130 1689.120 ;
    END
  END r0_rd_out[611]
  PIN r0_rd_out[612]
    DIRECTION OUTPUT ;
    USE SIGNAL ;
    SHAPE ABUTMENT ;
    PORT
      LAYER met2 ;
      RECT 1410.290 1688.700 1410.430 1689.120 ;
    END
  END r0_rd_out[612]
  PIN r0_rd_out[613]
    DIRECTION OUTPUT ;
    USE SIGNAL ;
    SHAPE ABUTMENT ;
    PORT
      LAYER met2 ;
      RECT 1412.590 1688.700 1412.730 1689.120 ;
    END
  END r0_rd_out[613]
  PIN r0_rd_out[614]
    DIRECTION OUTPUT ;
    USE SIGNAL ;
    SHAPE ABUTMENT ;
    PORT
      LAYER met2 ;
      RECT 1414.890 1688.700 1415.030 1689.120 ;
    END
  END r0_rd_out[614]
  PIN r0_rd_out[615]
    DIRECTION OUTPUT ;
    USE SIGNAL ;
    SHAPE ABUTMENT ;
    PORT
      LAYER met2 ;
      RECT 1417.190 1688.700 1417.330 1689.120 ;
    END
  END r0_rd_out[615]
  PIN r0_rd_out[616]
    DIRECTION OUTPUT ;
    USE SIGNAL ;
    SHAPE ABUTMENT ;
    PORT
      LAYER met2 ;
      RECT 1419.490 1688.700 1419.630 1689.120 ;
    END
  END r0_rd_out[616]
  PIN r0_rd_out[617]
    DIRECTION OUTPUT ;
    USE SIGNAL ;
    SHAPE ABUTMENT ;
    PORT
      LAYER met2 ;
      RECT 1421.790 1688.700 1421.930 1689.120 ;
    END
  END r0_rd_out[617]
  PIN r0_rd_out[618]
    DIRECTION OUTPUT ;
    USE SIGNAL ;
    SHAPE ABUTMENT ;
    PORT
      LAYER met2 ;
      RECT 1424.090 1688.700 1424.230 1689.120 ;
    END
  END r0_rd_out[618]
  PIN r0_rd_out[619]
    DIRECTION OUTPUT ;
    USE SIGNAL ;
    SHAPE ABUTMENT ;
    PORT
      LAYER met2 ;
      RECT 1426.390 1688.700 1426.530 1689.120 ;
    END
  END r0_rd_out[619]
  PIN r0_rd_out[620]
    DIRECTION OUTPUT ;
    USE SIGNAL ;
    SHAPE ABUTMENT ;
    PORT
      LAYER met2 ;
      RECT 1428.690 1688.700 1428.830 1689.120 ;
    END
  END r0_rd_out[620]
  PIN r0_rd_out[621]
    DIRECTION OUTPUT ;
    USE SIGNAL ;
    SHAPE ABUTMENT ;
    PORT
      LAYER met2 ;
      RECT 1430.990 1688.700 1431.130 1689.120 ;
    END
  END r0_rd_out[621]
  PIN r0_rd_out[622]
    DIRECTION OUTPUT ;
    USE SIGNAL ;
    SHAPE ABUTMENT ;
    PORT
      LAYER met2 ;
      RECT 1433.290 1688.700 1433.430 1689.120 ;
    END
  END r0_rd_out[622]
  PIN r0_rd_out[623]
    DIRECTION OUTPUT ;
    USE SIGNAL ;
    SHAPE ABUTMENT ;
    PORT
      LAYER met2 ;
      RECT 1435.590 1688.700 1435.730 1689.120 ;
    END
  END r0_rd_out[623]
  PIN r0_rd_out[624]
    DIRECTION OUTPUT ;
    USE SIGNAL ;
    SHAPE ABUTMENT ;
    PORT
      LAYER met2 ;
      RECT 1437.890 1688.700 1438.030 1689.120 ;
    END
  END r0_rd_out[624]
  PIN r0_rd_out[625]
    DIRECTION OUTPUT ;
    USE SIGNAL ;
    SHAPE ABUTMENT ;
    PORT
      LAYER met2 ;
      RECT 1440.190 1688.700 1440.330 1689.120 ;
    END
  END r0_rd_out[625]
  PIN r0_rd_out[626]
    DIRECTION OUTPUT ;
    USE SIGNAL ;
    SHAPE ABUTMENT ;
    PORT
      LAYER met2 ;
      RECT 1442.490 1688.700 1442.630 1689.120 ;
    END
  END r0_rd_out[626]
  PIN r0_rd_out[627]
    DIRECTION OUTPUT ;
    USE SIGNAL ;
    SHAPE ABUTMENT ;
    PORT
      LAYER met2 ;
      RECT 1444.790 1688.700 1444.930 1689.120 ;
    END
  END r0_rd_out[627]
  PIN r0_rd_out[628]
    DIRECTION OUTPUT ;
    USE SIGNAL ;
    SHAPE ABUTMENT ;
    PORT
      LAYER met2 ;
      RECT 1447.090 1688.700 1447.230 1689.120 ;
    END
  END r0_rd_out[628]
  PIN r0_rd_out[629]
    DIRECTION OUTPUT ;
    USE SIGNAL ;
    SHAPE ABUTMENT ;
    PORT
      LAYER met2 ;
      RECT 1449.390 1688.700 1449.530 1689.120 ;
    END
  END r0_rd_out[629]
  PIN r0_rd_out[630]
    DIRECTION OUTPUT ;
    USE SIGNAL ;
    SHAPE ABUTMENT ;
    PORT
      LAYER met2 ;
      RECT 1451.690 1688.700 1451.830 1689.120 ;
    END
  END r0_rd_out[630]
  PIN r0_rd_out[631]
    DIRECTION OUTPUT ;
    USE SIGNAL ;
    SHAPE ABUTMENT ;
    PORT
      LAYER met2 ;
      RECT 1453.990 1688.700 1454.130 1689.120 ;
    END
  END r0_rd_out[631]
  PIN r0_rd_out[632]
    DIRECTION OUTPUT ;
    USE SIGNAL ;
    SHAPE ABUTMENT ;
    PORT
      LAYER met2 ;
      RECT 1456.290 1688.700 1456.430 1689.120 ;
    END
  END r0_rd_out[632]
  PIN r0_rd_out[633]
    DIRECTION OUTPUT ;
    USE SIGNAL ;
    SHAPE ABUTMENT ;
    PORT
      LAYER met2 ;
      RECT 1458.590 1688.700 1458.730 1689.120 ;
    END
  END r0_rd_out[633]
  PIN r0_rd_out[634]
    DIRECTION OUTPUT ;
    USE SIGNAL ;
    SHAPE ABUTMENT ;
    PORT
      LAYER met2 ;
      RECT 1460.890 1688.700 1461.030 1689.120 ;
    END
  END r0_rd_out[634]
  PIN r0_rd_out[635]
    DIRECTION OUTPUT ;
    USE SIGNAL ;
    SHAPE ABUTMENT ;
    PORT
      LAYER met2 ;
      RECT 1463.190 1688.700 1463.330 1689.120 ;
    END
  END r0_rd_out[635]
  PIN r0_rd_out[636]
    DIRECTION OUTPUT ;
    USE SIGNAL ;
    SHAPE ABUTMENT ;
    PORT
      LAYER met2 ;
      RECT 1465.490 1688.700 1465.630 1689.120 ;
    END
  END r0_rd_out[636]
  PIN r0_rd_out[637]
    DIRECTION OUTPUT ;
    USE SIGNAL ;
    SHAPE ABUTMENT ;
    PORT
      LAYER met2 ;
      RECT 1467.790 1688.700 1467.930 1689.120 ;
    END
  END r0_rd_out[637]
  PIN r0_rd_out[638]
    DIRECTION OUTPUT ;
    USE SIGNAL ;
    SHAPE ABUTMENT ;
    PORT
      LAYER met2 ;
      RECT 1470.090 1688.700 1470.230 1689.120 ;
    END
  END r0_rd_out[638]
  PIN r0_rd_out[639]
    DIRECTION OUTPUT ;
    USE SIGNAL ;
    SHAPE ABUTMENT ;
    PORT
      LAYER met2 ;
      RECT 1472.390 1688.700 1472.530 1689.120 ;
    END
  END r0_rd_out[639]
  PIN r0_rd_out[640]
    DIRECTION OUTPUT ;
    USE SIGNAL ;
    SHAPE ABUTMENT ;
    PORT
      LAYER met2 ;
      RECT 1474.690 1688.700 1474.830 1689.120 ;
    END
  END r0_rd_out[640]
  PIN r0_rd_out[641]
    DIRECTION OUTPUT ;
    USE SIGNAL ;
    SHAPE ABUTMENT ;
    PORT
      LAYER met2 ;
      RECT 1476.990 1688.700 1477.130 1689.120 ;
    END
  END r0_rd_out[641]
  PIN r0_rd_out[642]
    DIRECTION OUTPUT ;
    USE SIGNAL ;
    SHAPE ABUTMENT ;
    PORT
      LAYER met2 ;
      RECT 1479.290 1688.700 1479.430 1689.120 ;
    END
  END r0_rd_out[642]
  PIN r0_rd_out[643]
    DIRECTION OUTPUT ;
    USE SIGNAL ;
    SHAPE ABUTMENT ;
    PORT
      LAYER met2 ;
      RECT 1481.590 1688.700 1481.730 1689.120 ;
    END
  END r0_rd_out[643]
  PIN r0_rd_out[644]
    DIRECTION OUTPUT ;
    USE SIGNAL ;
    SHAPE ABUTMENT ;
    PORT
      LAYER met2 ;
      RECT 1483.890 1688.700 1484.030 1689.120 ;
    END
  END r0_rd_out[644]
  PIN r0_rd_out[645]
    DIRECTION OUTPUT ;
    USE SIGNAL ;
    SHAPE ABUTMENT ;
    PORT
      LAYER met2 ;
      RECT 1486.190 1688.700 1486.330 1689.120 ;
    END
  END r0_rd_out[645]
  PIN r0_rd_out[646]
    DIRECTION OUTPUT ;
    USE SIGNAL ;
    SHAPE ABUTMENT ;
    PORT
      LAYER met2 ;
      RECT 1488.490 1688.700 1488.630 1689.120 ;
    END
  END r0_rd_out[646]
  PIN r0_rd_out[647]
    DIRECTION OUTPUT ;
    USE SIGNAL ;
    SHAPE ABUTMENT ;
    PORT
      LAYER met2 ;
      RECT 1490.790 1688.700 1490.930 1689.120 ;
    END
  END r0_rd_out[647]
  PIN r0_rd_out[648]
    DIRECTION OUTPUT ;
    USE SIGNAL ;
    SHAPE ABUTMENT ;
    PORT
      LAYER met2 ;
      RECT 1493.090 1688.700 1493.230 1689.120 ;
    END
  END r0_rd_out[648]
  PIN r0_rd_out[649]
    DIRECTION OUTPUT ;
    USE SIGNAL ;
    SHAPE ABUTMENT ;
    PORT
      LAYER met2 ;
      RECT 1495.390 1688.700 1495.530 1689.120 ;
    END
  END r0_rd_out[649]
  PIN r0_rd_out[650]
    DIRECTION OUTPUT ;
    USE SIGNAL ;
    SHAPE ABUTMENT ;
    PORT
      LAYER met2 ;
      RECT 1497.690 1688.700 1497.830 1689.120 ;
    END
  END r0_rd_out[650]
  PIN r0_rd_out[651]
    DIRECTION OUTPUT ;
    USE SIGNAL ;
    SHAPE ABUTMENT ;
    PORT
      LAYER met2 ;
      RECT 1499.990 1688.700 1500.130 1689.120 ;
    END
  END r0_rd_out[651]
  PIN r0_rd_out[652]
    DIRECTION OUTPUT ;
    USE SIGNAL ;
    SHAPE ABUTMENT ;
    PORT
      LAYER met2 ;
      RECT 1502.290 1688.700 1502.430 1689.120 ;
    END
  END r0_rd_out[652]
  PIN r0_rd_out[653]
    DIRECTION OUTPUT ;
    USE SIGNAL ;
    SHAPE ABUTMENT ;
    PORT
      LAYER met2 ;
      RECT 1504.590 1688.700 1504.730 1689.120 ;
    END
  END r0_rd_out[653]
  PIN w0_addr_in[0]
    DIRECTION INPUT ;
    USE SIGNAL ;
    SHAPE ABUTMENT ;
    PORT
      LAYER met3 ;
      RECT 0.000 1565.210 0.900 1565.510 ;
    END
  END w0_addr_in[0]
  PIN w0_addr_in[1]
    DIRECTION INPUT ;
    USE SIGNAL ;
    SHAPE ABUTMENT ;
    PORT
      LAYER met3 ;
      RECT 0.000 1569.970 0.900 1570.270 ;
    END
  END w0_addr_in[1]
  PIN r0_addr_in[0]
    DIRECTION INPUT ;
    USE SIGNAL ;
    SHAPE ABUTMENT ;
    PORT
      LAYER met3 ;
      RECT 0.000 1579.490 0.900 1579.790 ;
    END
  END r0_addr_in[0]
  PIN r0_addr_in[1]
    DIRECTION INPUT ;
    USE SIGNAL ;
    SHAPE ABUTMENT ;
    PORT
      LAYER met3 ;
      RECT 0.000 1584.250 0.900 1584.550 ;
    END
  END r0_addr_in[1]
  PIN w0_we_in
    DIRECTION INPUT ;
    USE SIGNAL ;
    SHAPE ABUTMENT ;
    PORT
      LAYER met2 ;
      RECT 1506.890 1688.700 1507.030 1689.120 ;
    END
  END w0_we_in
  PIN w0_ce_in
    DIRECTION INPUT ;
    USE SIGNAL ;
    SHAPE ABUTMENT ;
    PORT
      LAYER met2 ;
      RECT 1509.190 1688.700 1509.330 1689.120 ;
    END
  END w0_ce_in
  PIN w0_clk
    DIRECTION INPUT ;
    USE SIGNAL ;
    SHAPE ABUTMENT ;
    PORT
      LAYER met2 ;
      RECT 1511.490 1688.700 1511.630 1689.120 ;
    END
  END w0_clk
  PIN r0_ce_in
    DIRECTION INPUT ;
    USE SIGNAL ;
    SHAPE ABUTMENT ;
    PORT
      LAYER met2 ;
      RECT 1513.790 1688.700 1513.930 1689.120 ;
    END
  END r0_ce_in
  PIN r0_clk
    DIRECTION INPUT ;
    USE SIGNAL ;
    SHAPE ABUTMENT ;
    PORT
      LAYER met2 ;
      RECT 1516.090 1688.700 1516.230 1689.120 ;
    END
  END r0_clk
  PIN VSS
    DIRECTION INOUT ;
    USE GROUND ;
    PORT
      LAYER met4 ;
      RECT 2.160 4.080 3.360 1685.040 ;
      RECT 13.040 4.080 14.240 1685.040 ;
      RECT 23.920 4.080 25.120 1685.040 ;
      RECT 34.800 4.080 36.000 1685.040 ;
      RECT 45.680 4.080 46.880 1685.040 ;
      RECT 56.560 4.080 57.760 1685.040 ;
      RECT 67.440 4.080 68.640 1685.040 ;
      RECT 78.320 4.080 79.520 1685.040 ;
      RECT 89.200 4.080 90.400 1685.040 ;
      RECT 100.080 4.080 101.280 1685.040 ;
      RECT 110.960 4.080 112.160 1685.040 ;
      RECT 121.840 4.080 123.040 1685.040 ;
      RECT 132.720 4.080 133.920 1685.040 ;
      RECT 143.600 4.080 144.800 1685.040 ;
      RECT 154.480 4.080 155.680 1685.040 ;
      RECT 165.360 4.080 166.560 1685.040 ;
      RECT 176.240 4.080 177.440 1685.040 ;
      RECT 187.120 4.080 188.320 1685.040 ;
      RECT 198.000 4.080 199.200 1685.040 ;
      RECT 208.880 4.080 210.080 1685.040 ;
      RECT 219.760 4.080 220.960 1685.040 ;
      RECT 230.640 4.080 231.840 1685.040 ;
      RECT 241.520 4.080 242.720 1685.040 ;
      RECT 252.400 4.080 253.600 1685.040 ;
      RECT 263.280 4.080 264.480 1685.040 ;
      RECT 274.160 4.080 275.360 1685.040 ;
      RECT 285.040 4.080 286.240 1685.040 ;
      RECT 295.920 4.080 297.120 1685.040 ;
      RECT 306.800 4.080 308.000 1685.040 ;
      RECT 317.680 4.080 318.880 1685.040 ;
      RECT 328.560 4.080 329.760 1685.040 ;
      RECT 339.440 4.080 340.640 1685.040 ;
      RECT 350.320 4.080 351.520 1685.040 ;
      RECT 361.200 4.080 362.400 1685.040 ;
      RECT 372.080 4.080 373.280 1685.040 ;
      RECT 382.960 4.080 384.160 1685.040 ;
      RECT 393.840 4.080 395.040 1685.040 ;
      RECT 404.720 4.080 405.920 1685.040 ;
      RECT 415.600 4.080 416.800 1685.040 ;
      RECT 426.480 4.080 427.680 1685.040 ;
      RECT 437.360 4.080 438.560 1685.040 ;
      RECT 448.240 4.080 449.440 1685.040 ;
      RECT 459.120 4.080 460.320 1685.040 ;
      RECT 470.000 4.080 471.200 1685.040 ;
      RECT 480.880 4.080 482.080 1685.040 ;
      RECT 491.760 4.080 492.960 1685.040 ;
      RECT 502.640 4.080 503.840 1685.040 ;
      RECT 513.520 4.080 514.720 1685.040 ;
      RECT 524.400 4.080 525.600 1685.040 ;
      RECT 535.280 4.080 536.480 1685.040 ;
      RECT 546.160 4.080 547.360 1685.040 ;
      RECT 557.040 4.080 558.240 1685.040 ;
      RECT 567.920 4.080 569.120 1685.040 ;
      RECT 578.800 4.080 580.000 1685.040 ;
      RECT 589.680 4.080 590.880 1685.040 ;
      RECT 600.560 4.080 601.760 1685.040 ;
      RECT 611.440 4.080 612.640 1685.040 ;
      RECT 622.320 4.080 623.520 1685.040 ;
      RECT 633.200 4.080 634.400 1685.040 ;
      RECT 644.080 4.080 645.280 1685.040 ;
      RECT 654.960 4.080 656.160 1685.040 ;
      RECT 665.840 4.080 667.040 1685.040 ;
      RECT 676.720 4.080 677.920 1685.040 ;
      RECT 687.600 4.080 688.800 1685.040 ;
      RECT 698.480 4.080 699.680 1685.040 ;
      RECT 709.360 4.080 710.560 1685.040 ;
      RECT 720.240 4.080 721.440 1685.040 ;
      RECT 731.120 4.080 732.320 1685.040 ;
      RECT 742.000 4.080 743.200 1685.040 ;
      RECT 752.880 4.080 754.080 1685.040 ;
      RECT 763.760 4.080 764.960 1685.040 ;
      RECT 774.640 4.080 775.840 1685.040 ;
      RECT 785.520 4.080 786.720 1685.040 ;
      RECT 796.400 4.080 797.600 1685.040 ;
      RECT 807.280 4.080 808.480 1685.040 ;
      RECT 818.160 4.080 819.360 1685.040 ;
      RECT 829.040 4.080 830.240 1685.040 ;
      RECT 839.920 4.080 841.120 1685.040 ;
      RECT 850.800 4.080 852.000 1685.040 ;
      RECT 861.680 4.080 862.880 1685.040 ;
      RECT 872.560 4.080 873.760 1685.040 ;
      RECT 883.440 4.080 884.640 1685.040 ;
      RECT 894.320 4.080 895.520 1685.040 ;
      RECT 905.200 4.080 906.400 1685.040 ;
      RECT 916.080 4.080 917.280 1685.040 ;
      RECT 926.960 4.080 928.160 1685.040 ;
      RECT 937.840 4.080 939.040 1685.040 ;
      RECT 948.720 4.080 949.920 1685.040 ;
      RECT 959.600 4.080 960.800 1685.040 ;
      RECT 970.480 4.080 971.680 1685.040 ;
      RECT 981.360 4.080 982.560 1685.040 ;
      RECT 992.240 4.080 993.440 1685.040 ;
      RECT 1003.120 4.080 1004.320 1685.040 ;
      RECT 1014.000 4.080 1015.200 1685.040 ;
      RECT 1024.880 4.080 1026.080 1685.040 ;
      RECT 1035.760 4.080 1036.960 1685.040 ;
      RECT 1046.640 4.080 1047.840 1685.040 ;
      RECT 1057.520 4.080 1058.720 1685.040 ;
      RECT 1068.400 4.080 1069.600 1685.040 ;
      RECT 1079.280 4.080 1080.480 1685.040 ;
      RECT 1090.160 4.080 1091.360 1685.040 ;
      RECT 1101.040 4.080 1102.240 1685.040 ;
      RECT 1111.920 4.080 1113.120 1685.040 ;
      RECT 1122.800 4.080 1124.000 1685.040 ;
      RECT 1133.680 4.080 1134.880 1685.040 ;
      RECT 1144.560 4.080 1145.760 1685.040 ;
      RECT 1155.440 4.080 1156.640 1685.040 ;
      RECT 1166.320 4.080 1167.520 1685.040 ;
      RECT 1177.200 4.080 1178.400 1685.040 ;
      RECT 1188.080 4.080 1189.280 1685.040 ;
      RECT 1198.960 4.080 1200.160 1685.040 ;
      RECT 1209.840 4.080 1211.040 1685.040 ;
      RECT 1220.720 4.080 1221.920 1685.040 ;
      RECT 1231.600 4.080 1232.800 1685.040 ;
      RECT 1242.480 4.080 1243.680 1685.040 ;
      RECT 1253.360 4.080 1254.560 1685.040 ;
      RECT 1264.240 4.080 1265.440 1685.040 ;
      RECT 1275.120 4.080 1276.320 1685.040 ;
      RECT 1286.000 4.080 1287.200 1685.040 ;
      RECT 1296.880 4.080 1298.080 1685.040 ;
      RECT 1307.760 4.080 1308.960 1685.040 ;
      RECT 1318.640 4.080 1319.840 1685.040 ;
      RECT 1329.520 4.080 1330.720 1685.040 ;
      RECT 1340.400 4.080 1341.600 1685.040 ;
      RECT 1351.280 4.080 1352.480 1685.040 ;
      RECT 1362.160 4.080 1363.360 1685.040 ;
      RECT 1373.040 4.080 1374.240 1685.040 ;
      RECT 1383.920 4.080 1385.120 1685.040 ;
      RECT 1394.800 4.080 1396.000 1685.040 ;
      RECT 1405.680 4.080 1406.880 1685.040 ;
      RECT 1416.560 4.080 1417.760 1685.040 ;
      RECT 1427.440 4.080 1428.640 1685.040 ;
      RECT 1438.320 4.080 1439.520 1685.040 ;
      RECT 1449.200 4.080 1450.400 1685.040 ;
      RECT 1460.080 4.080 1461.280 1685.040 ;
      RECT 1470.960 4.080 1472.160 1685.040 ;
      RECT 1481.840 4.080 1483.040 1685.040 ;
      RECT 1492.720 4.080 1493.920 1685.040 ;
      RECT 1503.600 4.080 1504.800 1685.040 ;
      RECT 1514.480 4.080 1515.680 1685.040 ;
      RECT 1525.360 4.080 1526.560 1685.040 ;
      RECT 1536.240 4.080 1537.440 1685.040 ;
      RECT 1547.120 4.080 1548.320 1685.040 ;
      RECT 1558.000 4.080 1559.200 1685.040 ;
      RECT 1568.880 4.080 1570.080 1685.040 ;
      RECT 1579.760 4.080 1580.960 1685.040 ;
      RECT 1590.640 4.080 1591.840 1685.040 ;
      RECT 1601.520 4.080 1602.720 1685.040 ;
      RECT 1612.400 4.080 1613.600 1685.040 ;
      RECT 1623.280 4.080 1624.480 1685.040 ;
      RECT 1634.160 4.080 1635.360 1685.040 ;
      RECT 1645.040 4.080 1646.240 1685.040 ;
      RECT 1655.920 4.080 1657.120 1685.040 ;
      RECT 1666.800 4.080 1668.000 1685.040 ;
    END
  END VSS
  PIN VDD
    DIRECTION INOUT ;
    USE POWER ;
    PORT
      LAYER met4 ;
      RECT 2.160 4.080 3.360 1685.040 ;
      RECT 13.040 4.080 14.240 1685.040 ;
      RECT 23.920 4.080 25.120 1685.040 ;
      RECT 34.800 4.080 36.000 1685.040 ;
      RECT 45.680 4.080 46.880 1685.040 ;
      RECT 56.560 4.080 57.760 1685.040 ;
      RECT 67.440 4.080 68.640 1685.040 ;
      RECT 78.320 4.080 79.520 1685.040 ;
      RECT 89.200 4.080 90.400 1685.040 ;
      RECT 100.080 4.080 101.280 1685.040 ;
      RECT 110.960 4.080 112.160 1685.040 ;
      RECT 121.840 4.080 123.040 1685.040 ;
      RECT 132.720 4.080 133.920 1685.040 ;
      RECT 143.600 4.080 144.800 1685.040 ;
      RECT 154.480 4.080 155.680 1685.040 ;
      RECT 165.360 4.080 166.560 1685.040 ;
      RECT 176.240 4.080 177.440 1685.040 ;
      RECT 187.120 4.080 188.320 1685.040 ;
      RECT 198.000 4.080 199.200 1685.040 ;
      RECT 208.880 4.080 210.080 1685.040 ;
      RECT 219.760 4.080 220.960 1685.040 ;
      RECT 230.640 4.080 231.840 1685.040 ;
      RECT 241.520 4.080 242.720 1685.040 ;
      RECT 252.400 4.080 253.600 1685.040 ;
      RECT 263.280 4.080 264.480 1685.040 ;
      RECT 274.160 4.080 275.360 1685.040 ;
      RECT 285.040 4.080 286.240 1685.040 ;
      RECT 295.920 4.080 297.120 1685.040 ;
      RECT 306.800 4.080 308.000 1685.040 ;
      RECT 317.680 4.080 318.880 1685.040 ;
      RECT 328.560 4.080 329.760 1685.040 ;
      RECT 339.440 4.080 340.640 1685.040 ;
      RECT 350.320 4.080 351.520 1685.040 ;
      RECT 361.200 4.080 362.400 1685.040 ;
      RECT 372.080 4.080 373.280 1685.040 ;
      RECT 382.960 4.080 384.160 1685.040 ;
      RECT 393.840 4.080 395.040 1685.040 ;
      RECT 404.720 4.080 405.920 1685.040 ;
      RECT 415.600 4.080 416.800 1685.040 ;
      RECT 426.480 4.080 427.680 1685.040 ;
      RECT 437.360 4.080 438.560 1685.040 ;
      RECT 448.240 4.080 449.440 1685.040 ;
      RECT 459.120 4.080 460.320 1685.040 ;
      RECT 470.000 4.080 471.200 1685.040 ;
      RECT 480.880 4.080 482.080 1685.040 ;
      RECT 491.760 4.080 492.960 1685.040 ;
      RECT 502.640 4.080 503.840 1685.040 ;
      RECT 513.520 4.080 514.720 1685.040 ;
      RECT 524.400 4.080 525.600 1685.040 ;
      RECT 535.280 4.080 536.480 1685.040 ;
      RECT 546.160 4.080 547.360 1685.040 ;
      RECT 557.040 4.080 558.240 1685.040 ;
      RECT 567.920 4.080 569.120 1685.040 ;
      RECT 578.800 4.080 580.000 1685.040 ;
      RECT 589.680 4.080 590.880 1685.040 ;
      RECT 600.560 4.080 601.760 1685.040 ;
      RECT 611.440 4.080 612.640 1685.040 ;
      RECT 622.320 4.080 623.520 1685.040 ;
      RECT 633.200 4.080 634.400 1685.040 ;
      RECT 644.080 4.080 645.280 1685.040 ;
      RECT 654.960 4.080 656.160 1685.040 ;
      RECT 665.840 4.080 667.040 1685.040 ;
      RECT 676.720 4.080 677.920 1685.040 ;
      RECT 687.600 4.080 688.800 1685.040 ;
      RECT 698.480 4.080 699.680 1685.040 ;
      RECT 709.360 4.080 710.560 1685.040 ;
      RECT 720.240 4.080 721.440 1685.040 ;
      RECT 731.120 4.080 732.320 1685.040 ;
      RECT 742.000 4.080 743.200 1685.040 ;
      RECT 752.880 4.080 754.080 1685.040 ;
      RECT 763.760 4.080 764.960 1685.040 ;
      RECT 774.640 4.080 775.840 1685.040 ;
      RECT 785.520 4.080 786.720 1685.040 ;
      RECT 796.400 4.080 797.600 1685.040 ;
      RECT 807.280 4.080 808.480 1685.040 ;
      RECT 818.160 4.080 819.360 1685.040 ;
      RECT 829.040 4.080 830.240 1685.040 ;
      RECT 839.920 4.080 841.120 1685.040 ;
      RECT 850.800 4.080 852.000 1685.040 ;
      RECT 861.680 4.080 862.880 1685.040 ;
      RECT 872.560 4.080 873.760 1685.040 ;
      RECT 883.440 4.080 884.640 1685.040 ;
      RECT 894.320 4.080 895.520 1685.040 ;
      RECT 905.200 4.080 906.400 1685.040 ;
      RECT 916.080 4.080 917.280 1685.040 ;
      RECT 926.960 4.080 928.160 1685.040 ;
      RECT 937.840 4.080 939.040 1685.040 ;
      RECT 948.720 4.080 949.920 1685.040 ;
      RECT 959.600 4.080 960.800 1685.040 ;
      RECT 970.480 4.080 971.680 1685.040 ;
      RECT 981.360 4.080 982.560 1685.040 ;
      RECT 992.240 4.080 993.440 1685.040 ;
      RECT 1003.120 4.080 1004.320 1685.040 ;
      RECT 1014.000 4.080 1015.200 1685.040 ;
      RECT 1024.880 4.080 1026.080 1685.040 ;
      RECT 1035.760 4.080 1036.960 1685.040 ;
      RECT 1046.640 4.080 1047.840 1685.040 ;
      RECT 1057.520 4.080 1058.720 1685.040 ;
      RECT 1068.400 4.080 1069.600 1685.040 ;
      RECT 1079.280 4.080 1080.480 1685.040 ;
      RECT 1090.160 4.080 1091.360 1685.040 ;
      RECT 1101.040 4.080 1102.240 1685.040 ;
      RECT 1111.920 4.080 1113.120 1685.040 ;
      RECT 1122.800 4.080 1124.000 1685.040 ;
      RECT 1133.680 4.080 1134.880 1685.040 ;
      RECT 1144.560 4.080 1145.760 1685.040 ;
      RECT 1155.440 4.080 1156.640 1685.040 ;
      RECT 1166.320 4.080 1167.520 1685.040 ;
      RECT 1177.200 4.080 1178.400 1685.040 ;
      RECT 1188.080 4.080 1189.280 1685.040 ;
      RECT 1198.960 4.080 1200.160 1685.040 ;
      RECT 1209.840 4.080 1211.040 1685.040 ;
      RECT 1220.720 4.080 1221.920 1685.040 ;
      RECT 1231.600 4.080 1232.800 1685.040 ;
      RECT 1242.480 4.080 1243.680 1685.040 ;
      RECT 1253.360 4.080 1254.560 1685.040 ;
      RECT 1264.240 4.080 1265.440 1685.040 ;
      RECT 1275.120 4.080 1276.320 1685.040 ;
      RECT 1286.000 4.080 1287.200 1685.040 ;
      RECT 1296.880 4.080 1298.080 1685.040 ;
      RECT 1307.760 4.080 1308.960 1685.040 ;
      RECT 1318.640 4.080 1319.840 1685.040 ;
      RECT 1329.520 4.080 1330.720 1685.040 ;
      RECT 1340.400 4.080 1341.600 1685.040 ;
      RECT 1351.280 4.080 1352.480 1685.040 ;
      RECT 1362.160 4.080 1363.360 1685.040 ;
      RECT 1373.040 4.080 1374.240 1685.040 ;
      RECT 1383.920 4.080 1385.120 1685.040 ;
      RECT 1394.800 4.080 1396.000 1685.040 ;
      RECT 1405.680 4.080 1406.880 1685.040 ;
      RECT 1416.560 4.080 1417.760 1685.040 ;
      RECT 1427.440 4.080 1428.640 1685.040 ;
      RECT 1438.320 4.080 1439.520 1685.040 ;
      RECT 1449.200 4.080 1450.400 1685.040 ;
      RECT 1460.080 4.080 1461.280 1685.040 ;
      RECT 1470.960 4.080 1472.160 1685.040 ;
      RECT 1481.840 4.080 1483.040 1685.040 ;
      RECT 1492.720 4.080 1493.920 1685.040 ;
      RECT 1503.600 4.080 1504.800 1685.040 ;
      RECT 1514.480 4.080 1515.680 1685.040 ;
      RECT 1525.360 4.080 1526.560 1685.040 ;
      RECT 1536.240 4.080 1537.440 1685.040 ;
      RECT 1547.120 4.080 1548.320 1685.040 ;
      RECT 1558.000 4.080 1559.200 1685.040 ;
      RECT 1568.880 4.080 1570.080 1685.040 ;
      RECT 1579.760 4.080 1580.960 1685.040 ;
      RECT 1590.640 4.080 1591.840 1685.040 ;
      RECT 1601.520 4.080 1602.720 1685.040 ;
      RECT 1612.400 4.080 1613.600 1685.040 ;
      RECT 1623.280 4.080 1624.480 1685.040 ;
      RECT 1634.160 4.080 1635.360 1685.040 ;
      RECT 1645.040 4.080 1646.240 1685.040 ;
      RECT 1655.920 4.080 1657.120 1685.040 ;
      RECT 1666.800 4.080 1668.000 1685.040 ;
    END
  END VDD
  OBS
    LAYER met1 ;
    RECT 0 0 1671.640 1689.120 ;
    LAYER met2 ;
    RECT 0 0 1671.640 1689.120 ;
    LAYER met3 ;
    RECT 0 0 1671.640 1689.120 ;
    LAYER met4 ;
    RECT 0 0 1671.640 1689.120 ;
  END
END fakeram_654x4_1r1w

END LIBRARY
